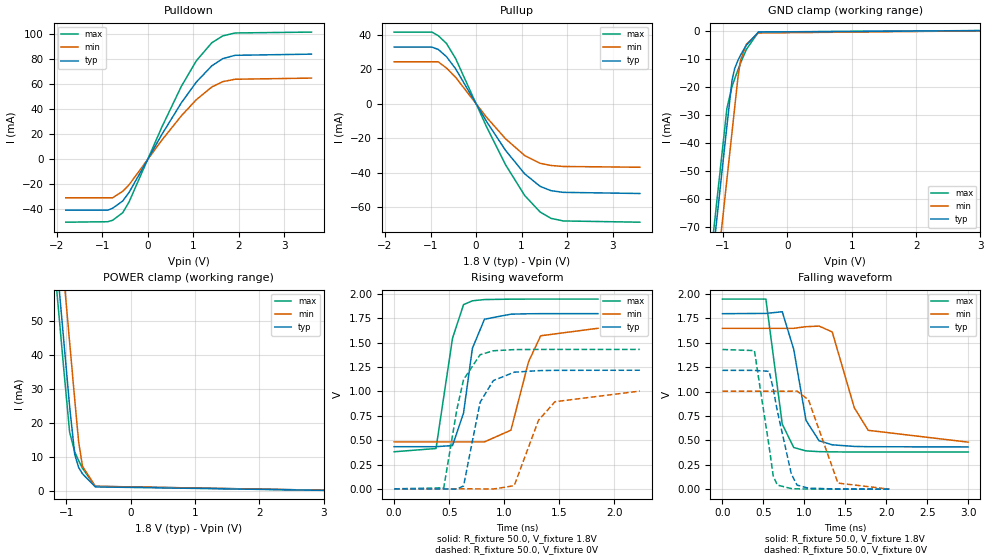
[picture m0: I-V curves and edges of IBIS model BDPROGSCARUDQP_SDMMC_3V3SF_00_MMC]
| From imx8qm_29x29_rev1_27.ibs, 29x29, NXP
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[Model] BDPROGSCARUDQP_SDMMC_3V3SF_00_MMC
Model_type I/O
Polarity   Non-Inverting
Enable   Active-Low
| CAP_THRESHOLD on pad IO is "CMOS" :
| Rising=10.0% of vdde1v8   Falling=90.0% of vdde1v8
| C_comp min and max val. don't necessarily correlate with the min and max pvt
| but are the smallest and greatest pad capacitance found.
| var   typ   min   max
C_comp   1.39830pF  1.34155pF  1.49815pF
Vinl = 577.5mV
Vinh = 1.2675V
Vmeas = 900.0mV   | Reference voltage for timing measurements
Cref  = 15.0pF   | Timing specification test load capacitance value
Rref  = 1.0MOhm   | Timing specification test load resistance value
Vref  = 1.8V   | Timing specification test load voltage
[Model Spec]
| TIME_THRESHOLD on pin ZI is "CORE" :
| Rising=50.0% of vdd   Falling=50.0% of vdd
Vinl 630.00000mV 577.50000mV 682.50000mV
Vinh 1.17000V 1.07250V 1.26750V
Vmeas 900.00000mV 825.00000mV 975.00000mV
Vref 1.80000V 1.65000V 1.95000V
| variable   typ   min   max
[Temperature Range] 25.0 125.0 -40.0
| variable   typ   min   max
[Voltage Range] 1.8V 1.65V 1.95V
| variable   typ   min   max
[POWER Clamp Reference] 1.8V 1.65V 1.95V
| variable   typ   min   max
[GND Clamp Reference] 0V 0V 0V
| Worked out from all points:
|   slope of the pulldown table from 0 to 0.27 V, typ, clamps not added: 15.6 ohm
|   slope of the pullup table from 0 to 0.27 V, typ, clamps not added: 22.9 ohm
|   GND clamp passes 1 mA (typ) near -0.48 V on its own axis
|   POWER clamp passes 1 mA (typ) near -0.53 V on its own axis
|   rising waveform, R_fixture 50.0, V_fixture 1.8V: 20-80 % time 107ps typ, 157ps min, 115ps max; typ from 0.433 V to 1.8 V
|   falling waveform, R_fixture 50.0, V_fixture 1.8V: 20-80 % time 167ps typ, 251ps min, 132ps max; typ from 1.8 V to 0.433 V
|   rising waveform, R_fixture 50.0, V_fixture 0V: 20-80 % time 139ps typ, 204ps min, 139ps max; typ from 0 V to 1.22 V
|   falling waveform, R_fixture 50.0, V_fixture 0V: 20-80 % time 187ps typ, 230ps min, 162ps max; typ from 1.22 V to 0 V
[POWER Clamp]
-1.8V     205.4mA    224.3mA    197mA
-1.18V    73.7mA     92.59mA    65.32mA
-1.15V    67.33mA    86.21mA    58.94mA
-1.12V    60.95mA    79.84mA    52.57mA
-1.06V    48.21mA    67.09mA    39.82mA
-1.04V    43.96mA    62.84mA    35.57mA
-950mV    24.83mA    43.72mA    17.27mA
-870mV    10.67mA    26.72mA    11.43mA
-810mV    6.903mA    14.47mA    8.897mA
-750mV    5.031mA    7.231mA    6.647mA
-550mV    1.187mA    1.353mA    1.363mA
3.6V      0A         0A         0A
[GND Clamp]
-1.8V     -216.7mA   -235.8mA   -210.3mA
-1.21V    -91.31mA   -110.4mA   -84.92mA
-1.12V    -72.19mA   -91.31mA   -65.8mA
-1.04V    -55.19mA   -74.31mA   -48.8mA
-940mV    -33.94mA   -53.06mA   -27.67mA
-860mV    -17.66mA   -36.06mA   -19.86mA
-820mV    -13.54mA   -27.56mA   -17.22mA
-770mV    -10.64mA   -16.96mA   -14.08mA
-730mV    -8.79mA    -10.76mA   -11.68mA
-640mV    -5.176mA   -4.882mA   -6.772mA
-450mV    -492.8uA   -817.4uA   -452.4uA
3.6V      109.1uA    87.23uA    140.4uA
| variable   typ   min   max
[Pullup Reference] 1.8V 1.65V 1.95V
| variable   typ   min   max
[Pulldown Reference] 0V 0V 0V
[Pullup]
-1.8V     33.01mA    24.43mA    41.69mA
-970mV    33.01mA    24.43mA    41.69mA
-830mV    31.61mA    24.43mA    39.61mA
-650mV    27.45mA    20.88mA    35.09mA
-450mV    20.46mA    15.52mA    26.43mA
230mV     -10.11mA   -7.67mA    -13.19mA
650mV     -26.95mA   -20.22mA   -35.31mA
1.07V     -40.53mA   -29.91mA   -53.1mA
1.41V     -47.79mA   -34.4mA    -62.68mA
1.65V     -50.28mA   -35.67mA   -66.34mA
1.92V     -51.25mA   -36.24mA   -67.83mA
3.6V      -51.91mA   -36.69mA   -68.55mA
[Pulldown]
-1.8V     -40.72mA   -30.81mA   -50.32mA
-880mV    -40.72mA   -30.81mA   -49.95mA
-770mV    -39.14mA   -30.78mA   -48.76mA
-550mV    -33.42mA   -25.62mA   -42.78mA
-410mV    -26.53mA   -20.44mA   -34.14mA
310mV     19.77mA    15.24mA    25.67mA
740mV     45.16mA    34.78mA    58.35mA
1.07V     61.77mA    47.68mA    78.8mA
1.41V     74.77mA    57.84mA    93.2mA
1.65V     80.47mA    62.07mA    98.65mA
1.92V     83.13mA    63.99mA    101mA
3.6V      84.07mA    64.91mA    101.7mA
[Ramp]
dV/dt_r 730.88031mV/139.16999ps 602.53977mV/204.04864ps 857.11439mV/139.26821ps
dV/dt_f 819.81631mV/166.75087ps 700.29607mV/250.61073ps 940.88152mV/131.63143ps
R_load = 50.0
| Removed startup time: 0s 0s 0s  .
| Removed end time: 1.83ns.
[Rising Waveform]
R_fixture   = 50.0
V_fixture   = 1.8V
V_fixture_min = 1.65V
V_fixture_max = 1.95V
0s        432.9mV    482.2mV    381mV
380ps     433mV      482.2mV    414.4mV
530ps     444.8mV    482.2mV    1.547V
630ps     778.7mV    482.2mV    1.892V
710ps     1.442V     482.2mV    1.931V
820ps     1.742V     482.4mV    1.944V
1.06ns    1.794V     602.6mV    1.948V
1.22ns    1.798V     1.305V     1.949V
1.33ns    1.799V     1.572V     1.949V
1.85ns    1.799V     1.649V     1.949V
| Removed startup time: 0s 0s 0s  .
| Removed end time: 2.98ns.
[Falling Waveform]
R_fixture   = 50.0
V_fixture   = 1.8V
V_fixture_min = 1.65V
V_fixture_max = 1.95V
0s        1.799V     1.649V     1.949V
530ps     1.802V     1.649V     1.949V
730ps     1.819V     1.649V     666.8mV
870ps     1.434V     1.649V     427.1mV
1.02ns    705.3mV    1.666V     392.5mV
1.18ns    496mV      1.672V     384.8mV
1.34ns    454.8mV    1.612V     382.3mV
1.61ns    438.5mV    834.1mV    381.1mV
1.78ns    435.4mV    603.3mV    380.9mV
3ns       432.9mV    482.2mV    381mV
| Removed startup time: 0s 0s 0s  .
| Removed end time: 2.21ns.
[Rising Waveform]
R_fixture   = 50.0
V_fixture   = 0V
V_fixture_min = 0V
V_fixture_max = 0V
0s        115uV      108.4uV    131uV
450ps     -393.5uV   158.4uV    10.76mV
570ps     -3.214mV   89.69uV    818.4mV
630ps     29.5mV     128uV      1.122V
780ps     888.6mV    -292.4uV   1.377V
900ps     1.112V     -2.045mV   1.418V
1.09ns    1.198V     32.56mV    1.43V
1.31ns    1.214V     703.8mV    1.432V
1.46ns    1.217V     895mV      1.432V
2.23ns    1.218V     1.004V     1.432V
| Removed startup time: 0s 0s 0s  .
| Removed end time: 2.02ns.
[Falling Waveform]
R_fixture   = 50.0
V_fixture   = 0V
V_fixture_min = 0V
V_fixture_max = 0V
0s        1.218V     1.004V     1.432V
390ps     1.218V     1.004V     1.421V
570ps     1.208V     1.004V     433.5mV
620ps     1.028V     1.004V     134.3mV
670ps     800.4mV    1.004V     42.3mV
840ps     158.6mV    1.004V     5.985mV
910ps     42.06mV    1.006V     3.411mV
1.05ns    10.31mV    916.5mV    1.437mV
1.41ns    1.368mV    62.51mV    400.4uV
2.04ns    122.1uV    119.5uV    135.6uV
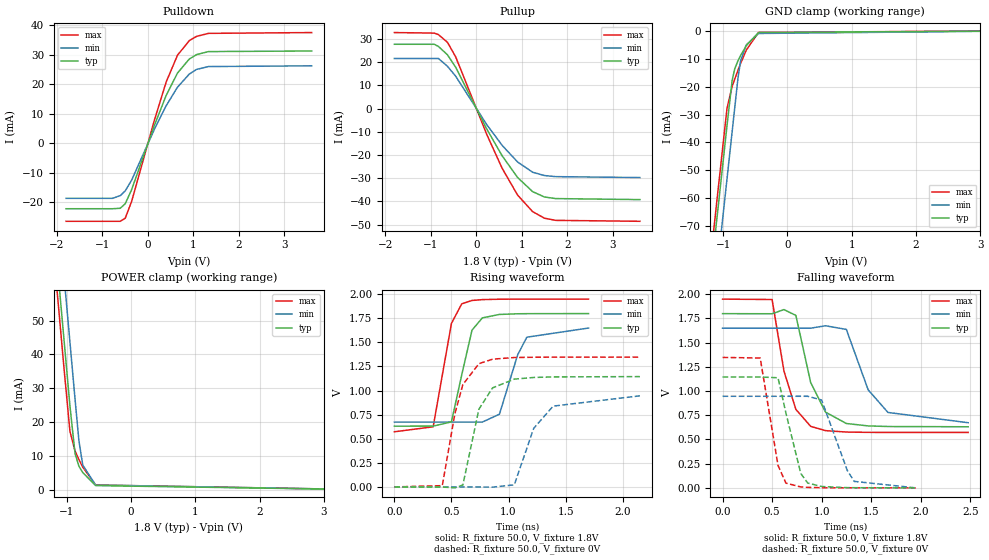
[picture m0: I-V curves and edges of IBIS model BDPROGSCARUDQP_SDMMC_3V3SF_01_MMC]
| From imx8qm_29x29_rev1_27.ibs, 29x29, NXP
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[Model] BDPROGSCARUDQP_SDMMC_3V3SF_01_MMC
Model_type I/O
Polarity   Non-Inverting
Enable   Active-Low
| CAP_THRESHOLD on pad IO is "CMOS" :
| Rising=10.0% of vdde1v8   Falling=90.0% of vdde1v8
| C_comp min and max val. don't necessarily correlate with the min and max pvt
| but are the smallest and greatest pad capacitance found.
| var   typ   min   max
C_comp   1.39700pF  1.34055pF  1.49705pF
Vinl = 577.5mV
Vinh = 1.2675V
Vmeas = 900.0mV   | Reference voltage for timing measurements
Cref  = 15.0pF   | Timing specification test load capacitance value
Rref  = 1.0MOhm   | Timing specification test load resistance value
Vref  = 1.8V   | Timing specification test load voltage
[Model Spec]
| TIME_THRESHOLD on pin ZI is "CORE" :
| Rising=50.0% of vdd   Falling=50.0% of vdd
Vinl 630.00000mV 577.50000mV 682.50000mV
Vinh 1.17000V 1.07250V 1.26750V
Vmeas 900.00000mV 825.00000mV 975.00000mV
Vref 1.80000V 1.65000V 1.95000V
| variable   typ   min   max
[Temperature Range] 25.0 125.0 -40.0
| variable   typ   min   max
[Voltage Range] 1.8V 1.65V 1.95V
| variable   typ   min   max
[POWER Clamp Reference] 1.8V 1.65V 1.95V
| variable   typ   min   max
[GND Clamp Reference] 0V 0V 0V
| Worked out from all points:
|   slope of the pulldown table from 0 to 0.27 V, typ, clamps not added: 23.9 ohm
|   slope of the pullup table from 0 to 0.27 V, typ, clamps not added: 26.6 ohm
|   GND clamp passes 1 mA (typ) near -0.48 V on its own axis
|   POWER clamp passes 1 mA (typ) near -0.53 V on its own axis
|   rising waveform, R_fixture 50.0, V_fixture 1.8V: 20-80 % time 120ps typ, 148ps min, 122ps max; typ from 0.631 V to 1.8 V
|   falling waveform, R_fixture 50.0, V_fixture 1.8V: 20-80 % time 198ps typ, 248ps min, 179ps max; typ from 1.8 V to 0.631 V
|   rising waveform, R_fixture 50.0, V_fixture 0V: 20-80 % time 143ps typ, 196ps min, 141ps max; typ from 0 V to 1.15 V
|   falling waveform, R_fixture 50.0, V_fixture 0V: 20-80 % time 159ps typ, 199ps min, 138ps max; typ from 1.15 V to 0 V
[POWER Clamp]
-1.8V     205.4mA    224.3mA    197mA
-1.18V    73.7mA     92.59mA    65.32mA
-1.15V    67.33mA    86.21mA    58.94mA
-1.12V    60.95mA    79.84mA    52.57mA
-1.06V    48.21mA    67.09mA    39.82mA
-1.04V    43.96mA    62.84mA    35.57mA
-950mV    24.83mA    43.72mA    17.27mA
-870mV    10.67mA    26.72mA    11.43mA
-810mV    6.903mA    14.47mA    8.897mA
-750mV    5.031mA    7.231mA    6.647mA
-550mV    1.187mA    1.353mA    1.363mA
3.6V      0A         0A         0A
[GND Clamp]
-1.8V     -216.7mA   -235.8mA   -210.3mA
-1.21V    -91.31mA   -110.4mA   -84.92mA
-1.12V    -72.19mA   -91.31mA   -65.8mA
-1.04V    -55.19mA   -74.31mA   -48.8mA
-940mV    -33.94mA   -53.06mA   -27.67mA
-860mV    -17.66mA   -36.06mA   -19.86mA
-820mV    -13.54mA   -27.56mA   -17.22mA
-770mV    -10.64mA   -16.96mA   -14.08mA
-730mV    -8.79mA    -10.76mA   -11.68mA
-640mV    -5.176mA   -4.882mA   -6.772mA
-450mV    -492.8uA   -817.4uA   -452.4uA
3.6V      109.1uA    87.23uA    140.4uA
| variable   typ   min   max
[Pullup Reference] 1.8V 1.65V 1.95V
| variable   typ   min   max
[Pulldown Reference] 0V 0V 0V
[Pullup]
-1.8V     27.77mA    21.63mA    32.82mA
-920mV    27.77mA    21.63mA    32.59mA
-830mV    26.81mA    21.63mA    31.93mA
-630mV    23.2mA     18.24mA    28.58mA
-450mV    17.82mA    13.95mA    22.27mA
230mV     -8.713mA   -6.829mA   -11.03mA
570mV     -20.33mA   -15.84mA   -25.72mA
910mV     -29.71mA   -23.01mA   -37.29mA
1.24V     -35.8mA    -27.44mA   -44.43mA
1.5V      -38.12mA   -28.87mA   -47.27mA
1.75V     -38.81mA   -29.34mA   -48.21mA
3.6V      -39.25mA   -29.74mA   -48.61mA
[Pulldown]
-1.8V     -22.2mA    -18.67mA   -26.46mA
-780mV    -22.2mA    -18.67mA   -26.46mA
-610mV    -22.04mA   -17.76mA   -26.46mA
-500mV    -20.5mA    -16.16mA   -25.41mA
-360mV    -15.76mA   -12.53mA   -19.76mA
140mV     6.017mA    4.706mA    7.753mA
400mV     16.23mA    12.74mA    20.79mA
650mV     23.85mA    19.04mA    29.89mA
910mV     28.6mA     23.5mA     34.86mA
1.07V     30.1mA     25.07mA    36.27mA
1.33V     31.11mA    26.03mA    37.29mA
3.6V      31.31mA    26.28mA    37.56mA
[Ramp]
dV/dt_r 686.83044mV/142.6003ps 567.34935mV/196.26704ps 808.86927mV/140.91314ps
dV/dt_f 700.93528mV/197.57155ps 585.82866mV/248.40399ps 825.4008mV/179.20548ps
R_load = 50.0
| Removed startup time: 0s 0s 0s  .
| Removed end time: 1.68ns.
[Rising Waveform]
R_fixture   = 50.0
V_fixture   = 1.8V
V_fixture_min = 1.65V
V_fixture_max = 1.95V
0s        630.9mV    672.9mV    572.5mV
340ps     631.2mV    672.9mV    624.3mV
500ps     675.4mV    673mV      1.697V
590ps     1.163V     673mV      1.9V
680ps     1.627V     673mV      1.935V
770ps     1.754V     672.9mV    1.944V
920ps     1.79V      754.9mV    1.948V
1.08ns    1.797V     1.372V     1.949V
1.16ns    1.798V     1.554V     1.949V
1.7ns     1.799V     1.649V     1.949V
| Removed startup time: 0s 0s 0s  .
| Removed end time: 2.46ns.
[Falling Waveform]
R_fixture   = 50.0
V_fixture   = 1.8V
V_fixture_min = 1.65V
V_fixture_max = 1.95V
0s        1.799V     1.649V     1.949V
500ps     1.798V     1.649V     1.945V
620ps     1.841V     1.649V     1.206V
740ps     1.781V     1.649V     810.9mV
890ps     1.087V     1.649V     634.8mV
1.04ns    781.9mV    1.674V     590.9mV
1.25ns    664.7mV    1.636V     576.5mV
1.47ns    639.8mV    1.013V     573.2mV
1.67ns    633.7mV    778.9mV    572.5mV
2.48ns    630.9mV    672.9mV    572.5mV
| Removed startup time: 0s 0s 0s  .
| Removed end time: 2.13ns.
[Rising Waveform]
R_fixture   = 50.0
V_fixture   = 0V
V_fixture_min = 0V
V_fixture_max = 0V
0s        153.2uV    140.2uV    179uV
420ps     -546.1uV   125.4uV    13.56mV
530ps     -9.393mV   171.9uV    759.2mV
600ps     20.36mV    100.8uV    1.063V
740ps     806.1mV    73.39uV    1.279V
860ps     1.028V     -1.713mV   1.326V
1.05ns    1.119V     21.74mV    1.343V
1.22ns    1.136V     608.1mV    1.346V
1.39ns    1.142V     838.7mV    1.347V
2.15ns    1.145V     945.7mV    1.347V
| Removed startup time: 0s 0s 0s  .
| Removed end time: 1.93ns.
[Falling Waveform]
R_fixture   = 50.0
V_fixture   = 0V
V_fixture_min = 0V
V_fixture_max = 0V
0s        1.145V     945.7mV    1.347V
380ps     1.145V     945.7mV    1.341V
560ps     1.137V     945.7mV    231.8mV
640ps     771.8mV    945.8mV    49.11mV
790ps     148mV      945.8mV    9.496mV
860ps     49.92mV    945.8mV    5.047mV
1ns       14.01mV    907.3mV    1.817mV
1.26ns    2.554mV    178.5mV    582uV
1.33ns    1.774mV    66.88mV    498.1uV
1.95ns    162.5uV    154.4uV    185.3uV
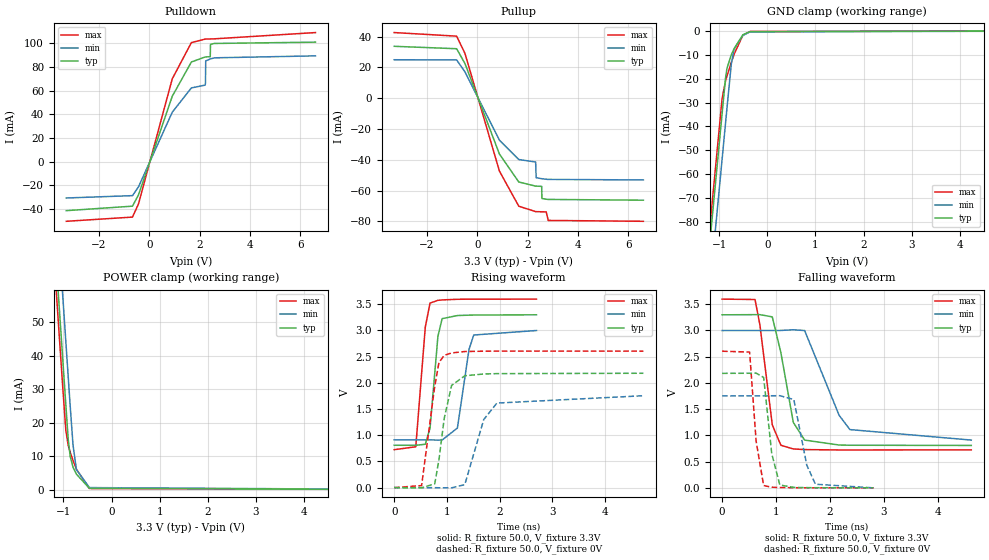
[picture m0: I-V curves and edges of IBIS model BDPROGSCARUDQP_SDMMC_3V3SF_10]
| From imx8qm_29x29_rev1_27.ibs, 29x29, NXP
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[Model] BDPROGSCARUDQP_SDMMC_3V3SF_10
Model_type I/O
Polarity   Non-Inverting
Enable   Active-Low
| CAP_THRESHOLD on pad IO is "CMOS" :
| Rising=10.0% of vdde3v3   Falling=90.0% of vdde3v3
| C_comp min and max val. don't necessarily correlate with the min and max pvt
| but are the smallest and greatest pad capacitance found.
| var   typ   min   max
C_comp   1.31090pF  1.26795pF  1.34510pF
Vinl = 750.0mV
Vinh = 2.25V
Vmeas = 1.65V   | Reference voltage for timing measurements
Cref  = 15.0pF   | Timing specification test load capacitance value
Rref  = 1.0MOhm   | Timing specification test load resistance value
Vref  = 3.3V   | Timing specification test load voltage
[Model Spec]
| TIME_THRESHOLD on pin ZI is "CORE" :
| Rising=50.0% of vdd   Falling=50.0% of vdd
Vinl 825.00000mV 750.00000mV 900.00000mV
Vinh 2.06250V 1.87500V 2.25000V
Vmeas 1.65000V 1.50000V 1.80000V
Vref 3.30000V 3.00000V 3.60000V
| variable   typ   min   max
[Temperature Range] 25.0 125.0 -40.0
| variable   typ   min   max
[Voltage Range] 3.3V 3.0V 3.6V
| variable   typ   min   max
[POWER Clamp Reference] 3.3V 3.0V 3.6V
| variable   typ   min   max
[GND Clamp Reference] 0V 0V 0V
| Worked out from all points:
|   slope of the pulldown table from 0 to 0.495 V, typ, clamps not added: 15.7 ohm
|   slope of the pullup table from 0 to 0.495 V, typ, clamps not added: 22.8 ohm
|   GND clamp passes 1 mA (typ) near -0.46 V on its own axis
|   POWER clamp passes 1 mA (typ) near -0.53 V on its own axis
|   rising waveform, R_fixture 50.0, V_fixture 3.3V: 20-80 % time 123ps typ, 168ps min, 122ps max; typ from 0.809 V to 3.3 V
|   falling waveform, R_fixture 50.0, V_fixture 3.3V: 20-80 % time 256ps typ, 424ps min, 203ps max; typ from 3.3 V to 0.809 V
|   rising waveform, R_fixture 50.0, V_fixture 0V: 20-80 % time 188ps typ, 300ps min, 183ps max; typ from 0 V to 2.18 V
|   falling waveform, R_fixture 50.0, V_fixture 0V: 20-80 % time 149ps typ, 203ps min, 122ps max; typ from 2.18 V to 0 V
[POWER Clamp]
-3.3V     524.6mA    543.5mA    516.1mA
-1.18V    74.13mA    93.03mA    65.73mA
-1.13V    63.5mA     82.4mA     55.11mA
-1.08V    52.88mA    71.78mA    44.49mA
-1.02V    40.13mA    59.03mA    31.74mA
-950mV    25.26mA    44.16mA    17.6mA
-900mV    14.93mA    33.53mA    13.17mA
-860mV    9.966mA    25.03mA    11.19mA
-800mV    6.661mA    13.2mA     8.673mA
-730mV    4.611mA    5.971mA    6.078mA
-460mV    377.7uA    599uA      338.7uA
6.6V      0A         0A         0A
[GND Clamp]
-3.3V     -535.9mA   -555mA     -529.5mA
-1.29V    -108.7mA   -127.9mA   -102.4mA
-1.13V    -74.74mA   -93.9mA    -68.39mA
-980mV    -42.86mA   -62.03mA   -36.51mA
-940mV    -34.36mA   -53.53mA   -28.08mA
-870mV    -19.62mA   -38.65mA   -20.84mA
-840mV    -15.5mA    -32.28mA   -18.78mA
-750mV    -9.826mA   -13.78mA   -13.06mA
-690mV    -7.205mA   -7.402mA   -9.546mA
-510mV    -1.433mA   -1.704mA   -1.633mA
-360mV    -54.77uA   -167.6uA   -42.24uA
6.6V      207.7uA    165.9uA    268.6uA
| variable   typ   min   max
[Pullup Reference] 3.3V 3.0V 3.6V
| variable   typ   min   max
[Pulldown Reference] 0V 0V 0V
[Pullup]
-3.3V     33.71mA    24.97mA    42.63mA
-820mV    32.13mA    24.86mA    40.3mA
-490mV    22.58mA    17.13mA    29.14mA
880mV     -36.28mA   -27.26mA   -47.35mA
1.65V     -54.46mA   -39.85mA   -70.18mA
2.32V     -57.13mA   -41.48mA   -73.7mA
2.34V     -57.15mA   -51.66mA   -73.71mA
2.56V     -57.29mA   -52.32mA   -73.82mA
2.57V     -65.17mA   -52.35mA   -73.83mA
2.74V     -65.64mA   -52.67mA   -73.88mA
2.82V     -65.78mA   -52.78mA   -79.42mA
6.6V      -66.28mA   -53.12mA   -79.99mA
[Pulldown]
-3.3V     -41.49mA   -30.78mA   -50.48mA
-670mV    -37.68mA   -28.78mA   -46.92mA
-430mV    -28.08mA   -21.29mA   -35.73mA
910mV     55.22mA    41.72mA    69.95mA
1.67V     84.2mA     62.3mA     100.6mA
2.22V     88.47mA    64.68mA    103.6mA
2.23V     88.48mA    66.76mA    103.6mA
2.24V     88.5mA     85.12mA    103.7mA
2.42V     88.69mA    86.76mA    103.7mA
2.43V     99.17mA    86.84mA    103.7mA
2.58V     99.89mA    87.74mA    103.8mA
6.6V      101mA      89.4mA     109.1mA
[Ramp]
dV/dt_r 1.3099V/188.25171ps 1.05212V/300.21154ps 1.5632V/183.30229ps
dV/dt_f 1.49389V/256.0841ps 1.25263V/423.56639ps 1.72452V/202.50135ps
R_load = 50.0
| Removed startup time: 0s 0s 0s  .
| Removed end time: 2.68ns.
[Rising Waveform]
R_fixture   = 50.0
V_fixture   = 3.3V
V_fixture_min = 3.0V
V_fixture_max = 3.6V
0s        808.7mV    911mV      724mV
410ps     808mV      911mV      780mV
590ps     827.9mV    911.1mV    3.062V
680ps     1.133V     911.1mV    3.522V
830ps     2.89V      907.3mV    3.575V
910ps     3.225V     908.9mV    3.583V
1.2ns     3.285V     1.138V     3.595V
1.42ns    3.292V     2.637V     3.597V
1.51ns    3.294V     2.913V     3.597V
2.7ns     3.299V     2.999V     3.598V
| Removed startup time: 0s 0s 0s  .
| Removed end time: 4.6ns.
[Falling Waveform]
R_fixture   = 50.0
V_fixture   = 3.3V
V_fixture_min = 3.0V
V_fixture_max = 3.6V
0s        3.299V     2.999V     3.598V
610ps     3.302V     2.999V     3.591V
700ps     3.302V     2.999V     3.112V
930ps     3.26V      2.999V     1.202V
1.09ns    2.576V     3.001V     811.7mV
1.32ns    1.248V     3.014V     742mV
1.53ns    910.9mV    2.999V     729.9mV
2.17ns    816.6mV    1.382V     722.4mV
2.37ns    812.6mV    1.111V     722.4mV
4.62ns    808.7mV    911mV      724mV
| Removed startup time: 0s 0s 0s  .
| Removed end time: 4.71ns.
[Rising Waveform]
R_fixture   = 50.0
V_fixture   = 0V
V_fixture_min = 0V
V_fixture_max = 0V
0s        118.5uV    111.8uV    137.3uV
520ps     -4.522mV   201.5uV    39.01mV
770ps     73.97mV    -881.9uV   1.938V
850ps     536.9mV    -2.746mV   2.39V
950ps     1.324V     -2.822mV   2.524V
1.09ns    1.952V     -4.309mV   2.571V
1.34ns    2.135V     56.63mV    2.598V
1.7ns     2.169V     1.3V       2.604V
1.95ns    2.176V     1.614V     2.606V
4.73ns    2.183V     1.754V     2.605V
| Removed startup time: 0s 0s 0s  .
| Removed end time: 2.79ns.
[Falling Waveform]
R_fixture   = 50.0
V_fixture   = 0V
V_fixture_min = 0V
V_fixture_max = 0V
0s        2.183V     1.754V     2.605V
510ps     2.185V     1.754V     2.589V
630ps     2.188V     1.754V     894mV
770ps     2.105V     1.754V     44.11mV
920ps     653.7mV    1.756V     12.7mV
1.07ns    54.57mV    1.757V     6.523mV
1.33ns    8.419mV    1.684V     2.95mV
1.57ns    4.101mV    432.5mV    1.099mV
1.73ns    3.022mV    69.24mV    556.9uV
2.81ns    118.5uV    111.4uV    137.4uV
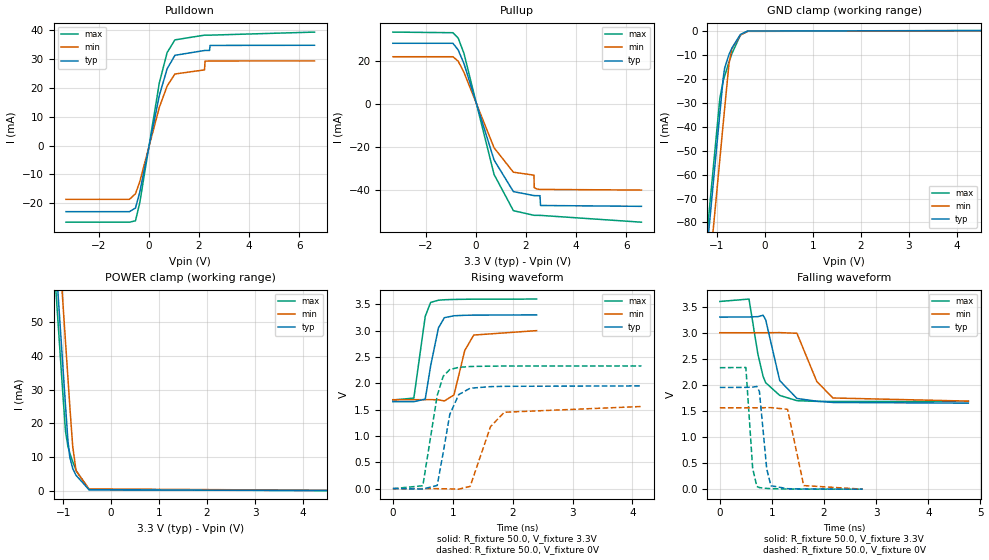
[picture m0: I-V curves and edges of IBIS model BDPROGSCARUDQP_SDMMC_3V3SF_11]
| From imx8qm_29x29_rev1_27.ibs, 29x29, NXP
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[Model] BDPROGSCARUDQP_SDMMC_3V3SF_11
Model_type I/O
Polarity   Non-Inverting
Enable   Active-Low
| CAP_THRESHOLD on pad IO is "CMOS" :
| Rising=10.0% of vdde3v3   Falling=90.0% of vdde3v3
| C_comp min and max val. don't necessarily correlate with the min and max pvt
| but are the smallest and greatest pad capacitance found.
| var   typ   min   max
C_comp   1.30990pF  1.26715pF  1.34440pF
Vinl = 750.0mV
Vinh = 2.25V
Vmeas = 1.65V   | Reference voltage for timing measurements
Cref  = 15.0pF   | Timing specification test load capacitance value
Rref  = 1.0MOhm   | Timing specification test load resistance value
Vref  = 3.3V   | Timing specification test load voltage
[Model Spec]
| TIME_THRESHOLD on pin ZI is "CORE" :
| Rising=50.0% of vdd   Falling=50.0% of vdd
Vinl 825.00000mV 750.00000mV 900.00000mV
Vinh 2.06250V 1.87500V 2.25000V
Vmeas 1.65000V 1.50000V 1.80000V
Vref 3.30000V 3.00000V 3.60000V
| variable   typ   min   max
[Temperature Range] 25.0 125.0 -40.0
| variable   typ   min   max
[Voltage Range] 3.3V 3.0V 3.6V
| variable   typ   min   max
[POWER Clamp Reference] 3.3V 3.0V 3.6V
| variable   typ   min   max
[GND Clamp Reference] 0V 0V 0V
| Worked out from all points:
|   slope of the pulldown table from 0 to 0.495 V, typ, clamps not added: 24.8 ohm
|   slope of the pullup table from 0 to 0.495 V, typ, clamps not added: 26.9 ohm
|   GND clamp passes 1 mA (typ) near -0.46 V on its own axis
|   POWER clamp passes 1 mA (typ) near -0.53 V on its own axis
|   rising waveform, R_fixture 50.0, V_fixture 3.3V: 20-80 % time 147ps typ, 176ps min, 134ps max; typ from 1.65 V to 3.3 V
|   falling waveform, R_fixture 50.0, V_fixture 3.3V: 20-80 % time 257ps typ, 345ps min, 235ps max; typ from 3.3 V to 1.65 V
|   rising waveform, R_fixture 50.0, V_fixture 0V: 20-80 % time 190ps typ, 274ps min, 193ps max; typ from 0 V to 1.95 V
|   falling waveform, R_fixture 50.0, V_fixture 0V: 20-80 % time 111ps typ, 156ps min, 89.7ps max; typ from 1.95 V to 0 V
[POWER Clamp]
-3.3V     524.6mA    543.5mA    516.1mA
-1.18V    74.13mA    93.03mA    65.73mA
-1.13V    63.5mA     82.4mA     55.11mA
-1.08V    52.88mA    71.78mA    44.49mA
-1.02V    40.13mA    59.03mA    31.74mA
-950mV    25.26mA    44.16mA    17.6mA
-900mV    14.93mA    33.53mA    13.17mA
-860mV    9.966mA    25.03mA    11.19mA
-800mV    6.661mA    13.2mA     8.673mA
-730mV    4.611mA    5.971mA    6.078mA
-460mV    377.7uA    599uA      338.7uA
6.6V      0A         0A         0A
[GND Clamp]
-3.3V     -535.9mA   -555mA     -529.5mA
-1.29V    -108.7mA   -127.9mA   -102.4mA
-1.13V    -74.74mA   -93.9mA    -68.39mA
-980mV    -42.86mA   -62.03mA   -36.51mA
-940mV    -34.36mA   -53.53mA   -28.08mA
-870mV    -19.62mA   -38.65mA   -20.84mA
-840mV    -15.5mA    -32.28mA   -18.78mA
-750mV    -9.826mA   -13.78mA   -13.06mA
-690mV    -7.205mA   -7.402mA   -9.546mA
-510mV    -1.433mA   -1.704mA   -1.633mA
-360mV    -54.77uA   -167.6uA   -42.24uA
6.6V      207.7uA    165.9uA    268.6uA
| variable   typ   min   max
[Pullup Reference] 3.3V 3.0V 3.6V
| variable   typ   min   max
[Pulldown Reference] 0V 0V 0V
[Pullup]
-3.3V     28.29mA    22.05mA    33.49mA
-910mV    28.29mA    22.05mA    33.2mA
-700mV    25.21mA    19.99mA    30.72mA
-470mV    18.91mA    14.81mA    23.6mA
730mV     -25.92mA   -20.25mA   -32.62mA
1.5V      -40.58mA   -31.58mA   -49.44mA
2.32V     -42.44mA   -32.95mA   -51.59mA
2.33V     -42.44mA   -38.74mA   -51.59mA
2.43V     -42.47mA   -39.38mA   -51.61mA
2.56V     -42.5mA    -39.55mA   -51.63mA
2.58V     -47.03mA   -39.57mA   -51.63mA
6.6V      -47.43mA   -39.87mA   -54.79mA
[Pulldown]
-3.3V     -22.92mA   -18.65mA   -26.58mA
-770mV    -22.92mA   -18.65mA   -26.58mA
-530mV    -21.66mA   -16.7mA    -26.09mA
-360mV    -16.13mA   -12.53mA   -19.82mA
420mV     17.42mA    13.3mA     21.81mA
730mV     26.64mA    20.66mA    32.27mA
1.04V     31.32mA    24.84mA    36.68mA
2.22V     33mA       26.27mA    38.32mA
2.24V     33.01mA    29.3mA     38.32mA
2.42V     33.01mA    29.35mA    38.32mA
2.44V     34.75mA    29.36mA    38.32mA
6.6V      34.81mA    29.38mA    39.38mA
[Ramp]
dV/dt_r 1.16975V/189.50514ps 935.39258mV/274.0416ps 1.39725V/192.9901ps
dV/dt_f 989.53002mV/257.16879ps 786.49611mV/345.14286ps 1.14965V/234.50303ps
R_load = 50.0
| Removed startup time: 0s 0s 0s  .
| Removed end time: 2.38ns.
[Rising Waveform]
R_fixture   = 50.0
V_fixture   = 3.3V
V_fixture_min = 3.0V
V_fixture_max = 3.6V
0s        1.649V     1.688V     1.682V
350ps     1.65V      1.688V     1.719V
540ps     1.699V     1.688V     3.27V
630ps     2.327V     1.689V     3.534V
760ps     3.05V      1.686V     3.576V
860ps     3.245V     1.665V     3.585V
1.02ns    3.281V     1.777V     3.591V
1.2ns     3.29V      2.622V     3.594V
1.35ns    3.293V     2.915V     3.596V
2.4ns     3.298V     2.999V     3.598V
| Removed startup time: 0s 0s 0s  .
| Removed end time: 4.75ns.
[Falling Waveform]
R_fixture   = 50.0
V_fixture   = 3.3V
V_fixture_min = 3.0V
V_fixture_max = 3.6V
0s        3.298V     2.999V     3.598V
560ps     3.301V     2.998V     3.644V
730ps     3.307V     2.999V     2.59V
830ps     3.334V     2.999V     2.164V
880ps     3.246V     2.999V     2.041V
1.15ns    2.081V     3.001V     1.797V
1.48ns    1.739V     2.988V     1.696V
1.86ns    1.686V     2.066V     1.683V
2.17ns    1.662V     1.748V     1.682V
4.77ns    1.649V     1.688V     1.682V
| Removed startup time: 0s 0s 0s  .
| Removed end time: 4.13ns.
[Rising Waveform]
R_fixture   = 50.0
V_fixture   = 0V
V_fixture_min = 0V
V_fixture_max = 0V
0s        157uV      144.5uV    187.5uV
500ps     -6.421mV   259.1uV    54.8mV
740ps     60.63mV    -240.4uV   1.768V
840ps     685.8mV    -3.195mV   2.133V
950ps     1.409V     -4.009mV   2.26V
1.1ns     1.785V     -9.984mV   2.302V
1.29ns    1.906V     42.06mV    2.318V
1.63ns    1.936V     1.177V     2.325V
1.86ns    1.942V     1.45V      2.327V
4.15ns    1.95V      1.559V     2.329V
| Removed startup time: 0s 0s 0s  .
| Removed end time: 2.72ns.
[Falling Waveform]
R_fixture   = 50.0
V_fixture   = 0V
V_fixture_min = 0V
V_fixture_max = 0V
0s        1.95V      1.559V     2.329V
500ps     1.951V     1.559V     2.332V
630ps     1.957V     1.56V      402mV
710ps     1.969V     1.56V      52.34mV
760ps     1.87V      1.56V      30.45mV
900ps     390.5mV    1.562V     14.45mV
980ps     66.13mV    1.563V     10.41mV
1.3ns     8.98mV     1.531V     2.718mV
1.61ns    3.86mV     68.96mV    702.8uV
2.74ns    157uV      144uV      187.5uV
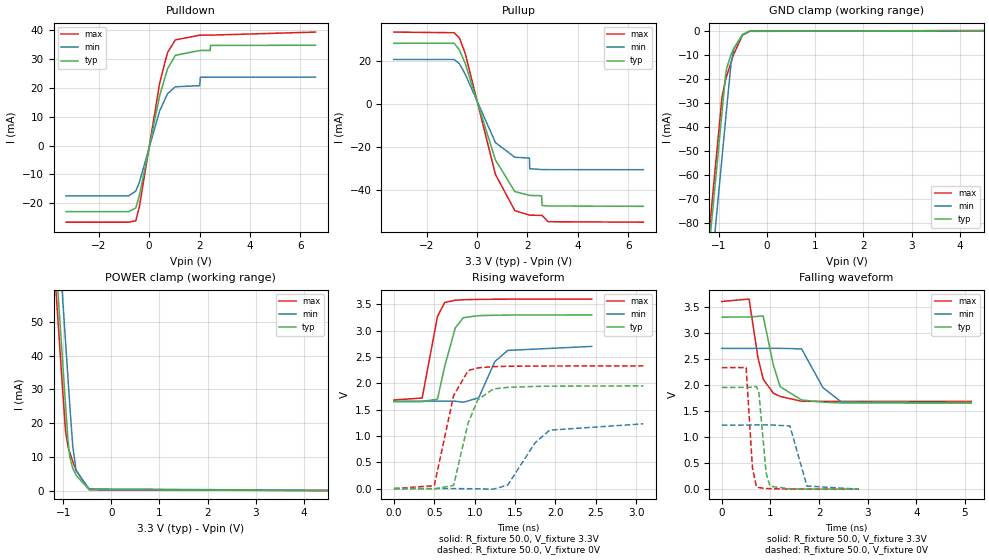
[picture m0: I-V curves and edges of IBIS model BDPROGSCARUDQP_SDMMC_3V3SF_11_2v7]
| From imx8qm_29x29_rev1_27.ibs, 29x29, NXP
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[Model] BDPROGSCARUDQP_SDMMC_3V3SF_11_2v7
Model_type I/O
Polarity   Non-Inverting
Enable   Active-Low
| CAP_THRESHOLD on pad IO is "CMOS" :
| Rising=10.0% of vdde3v3   Falling=90.0% of vdde3v3
| C_comp min and max val. don't necessarily correlate with the min and max pvt
| but are the smallest and greatest pad capacitance found.
| var   typ   min   max
C_comp   1.26715pF  1.18750pF  1.30990pF
Vinl = 675.0mV
Vinh = 2.25V
Vmeas = 1.65V   | Reference voltage for timing measurements
Cref  = 15.0pF   | Timing specification test load capacitance value
Rref  = 1.0MOhm   | Timing specification test load resistance value
Vref  = 3.3V   | Timing specification test load voltage
[Model Spec]
| TIME_THRESHOLD on pin ZI is "CORE" :
| Rising=50.0% of vdd   Falling=50.0% of vdd
Vinl 825.00000mV 675.00000mV 900.00000mV
Vinh 2.06250V 1.68750V 2.25000V
Vmeas 1.65000V 1.35000V 1.80000V
Vref 3.30000V 2.70000V 3.60000V
| variable   typ   min   max
[Temperature Range] 25.0 125.0 -40.0
| variable   typ   min   max
[Voltage Range] 3.3V 2.7V 3.6V
| variable   typ   min   max
[POWER Clamp Reference] 3.3V 2.7V 3.6V
| variable   typ   min   max
[GND Clamp Reference] 0V 0V 0V
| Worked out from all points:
|   slope of the pulldown table from 0 to 0.495 V, typ, clamps not added: 24.8 ohm
|   slope of the pullup table from 0 to 0.495 V, typ, clamps not added: 26.9 ohm
|   GND clamp passes 1 mA (typ) near -0.46 V on its own axis
|   POWER clamp passes 1 mA (typ) near -0.53 V on its own axis
|   rising waveform, R_fixture 50.0, V_fixture 3.3V: 20-80 % time 147ps typ, 188ps min, 134ps max; typ from 1.65 V to 3.3 V
|   falling waveform, R_fixture 50.0, V_fixture 3.3V: 20-80 % time 257ps typ, 390ps min, 235ps max; typ from 3.3 V to 1.65 V
|   rising waveform, R_fixture 50.0, V_fixture 0V: 20-80 % time 190ps typ, 313ps min, 193ps max; typ from 0 V to 1.95 V
|   falling waveform, R_fixture 50.0, V_fixture 0V: 20-80 % time 111ps typ, 180ps min, 89.7ps max; typ from 1.95 V to 0 V
[POWER Clamp]
-3.3V     524.6mA    543.4mA    516.1mA
-1.18V    74.13mA    92.92mA    65.73mA
-1.13V    63.5mA     82.3mA     55.11mA
-1.08V    52.88mA    71.67mA    44.49mA
-1.02V    40.13mA    58.93mA    31.74mA
-950mV    25.26mA    44.05mA    17.6mA
-900mV    14.93mA    33.43mA    13.17mA
-860mV    9.966mA    24.93mA    11.19mA
-800mV    6.661mA    13.12mA    8.673mA
-730mV    4.611mA    5.939mA    6.078mA
-460mV    377.7uA    598.1uA    338.7uA
6.6V      0A         0A         0A
[GND Clamp]
-3.3V     -535.9mA   -554.9mA   -529.5mA
-1.29V    -108.7mA   -127.8mA   -102.4mA
-1.13V    -74.74mA   -93.8mA    -68.39mA
-980mV    -42.86mA   -61.92mA   -36.51mA
-940mV    -34.36mA   -53.42mA   -28.08mA
-870mV    -19.62mA   -38.55mA   -20.84mA
-840mV    -15.5mA    -32.17mA   -18.78mA
-750mV    -9.826mA   -13.7mA    -13.06mA
-690mV    -7.205mA   -7.371mA   -9.546mA
-510mV    -1.433mA   -1.699mA   -1.633mA
-360mV    -54.77uA   -166.3uA   -42.24uA
6.6V      207.7uA    166.8uA    268.6uA
| variable   typ   min   max
[Pullup Reference] 3.3V 2.7V 3.6V
| variable   typ   min   max
[Pulldown Reference] 0V 0V 0V
[Pullup]
-3.3V     28.29mA    20.75mA    33.49mA
-910mV    28.29mA    20.75mA    33.2mA
-700mV    25.21mA    18.82mA    30.72mA
-470mV    18.91mA    13.94mA    23.6mA
730mV     -25.92mA   -17.83mA   -32.62mA
1.5V      -40.58mA   -24.64mA   -49.44mA
2.08V     -42.34mA   -25.01mA   -51.51mA
2.09V     -42.35mA   -29.96mA   -51.52mA
2.56V     -42.5mA    -30.35mA   -51.63mA
2.58V     -47.03mA   -30.36mA   -51.63mA
2.82V     -47.26mA   -30.39mA   -54.57mA
6.6V      -47.43mA   -30.41mA   -54.79mA
[Pulldown]
-3.3V     -22.92mA   -17.45mA   -26.58mA
-820mV    -22.92mA   -17.45mA   -26.58mA
-530mV    -21.66mA   -15.79mA   -26.09mA
-390mV    -17.39mA   -12.76mA   -21.33mA
420mV     17.42mA    12.1mA     21.81mA
730mV     26.64mA    18mA       32.27mA
1.04V     31.32mA    20.4mA     36.68mA
2.01V     32.99mA    20.79mA    38.31mA
2.03V     33mA       23.7mA     38.31mA
2.42V     33.01mA    23.74mA    38.32mA
2.44V     34.75mA    23.74mA    38.32mA
6.6V      34.81mA    23.75mA    39.38mA
[Ramp]
dV/dt_r 1.16975V/189.50514ps 737.10548mV/313.10036ps 1.39725V/192.9901ps
dV/dt_f 989.53002mV/257.16879ps 623.19328mV/389.77639ps 1.14965V/234.50303ps
R_load = 50.0
| Removed startup time: 0s 0s 0s  .
| Removed end time: 2.43ns.
[Rising Waveform]
R_fixture   = 50.0
V_fixture   = 3.3V
V_fixture_min = 2.7V
V_fixture_max = 3.6V
0s        1.649V     1.66V      1.682V
350ps     1.65V      1.66V      1.719V
540ps     1.699V     1.661V     3.27V
630ps     2.327V     1.661V     3.534V
760ps     3.05V      1.658V     3.576V
860ps     3.245V     1.639V     3.585V
1.05ns    3.283V     1.723V     3.592V
1.25ns    3.291V     2.411V     3.595V
1.41ns    3.294V     2.623V     3.596V
2.45ns    3.298V     2.699V     3.598V
| Removed startup time: 0s 0s 0s  .
| Removed end time: 5.11ns.
[Falling Waveform]
R_fixture   = 50.0
V_fixture   = 3.3V
V_fixture_min = 2.7V
V_fixture_max = 3.6V
0s        3.298V     2.699V     3.598V
560ps     3.301V     2.699V     3.644V
740ps     3.312V     2.699V     2.537V
850ps     3.32V      2.699V     2.108V
1.06ns    2.378V     2.7V       1.84V
1.2ns     1.964V     2.7V       1.777V
1.64ns    1.71V      2.689V     1.686V
2.08ns    1.668V     1.946V     1.682V
2.46ns    1.652V     1.67V      1.682V
5.13ns    1.649V     1.66V      1.682V
| Removed startup time: 0s 0s 0s  .
| Removed end time: 3.07ns.
[Rising Waveform]
R_fixture   = 50.0
V_fixture   = 0V
V_fixture_min = 0V
V_fixture_max = 0V
0s        157uV      126.8uV    187.5uV
500ps     -6.421mV   212.9uV    54.8mV
740ps     60.63mV    -154.4uV   1.768V
920ps     1.25V      -3.005mV   2.24V
1.04ns    1.686V     -4.47mV    2.291V
1.23ns    1.891V     -11.49mV   2.315V
1.41ns    1.922V     66.36mV    2.322V
1.75ns    1.94V      872.4mV    2.326V
1.93ns    1.944V     1.109V     2.327V
3.09ns    1.95V      1.229V     2.329V
| Removed startup time: 0s 0s 0s  .
| Removed end time: 2.8ns.
[Falling Waveform]
R_fixture   = 50.0
V_fixture   = 0V
V_fixture_min = 0V
V_fixture_max = 0V
0s        1.95V      1.229V     2.329V
500ps     1.951V     1.229V     2.332V
630ps     1.957V     1.23V      402mV
710ps     1.969V     1.231V     52.34mV
760ps     1.87V      1.231V     30.45mV
910ps     313.4mV    1.232V     13.84mV
990ps     56.51mV    1.233V     10.01mV
1.4ns     6.684mV    1.212V     1.725mV
1.75ns    2.666mV    60.68mV    429.5uV
2.82ns    157uV      126.3uV    187.5uV
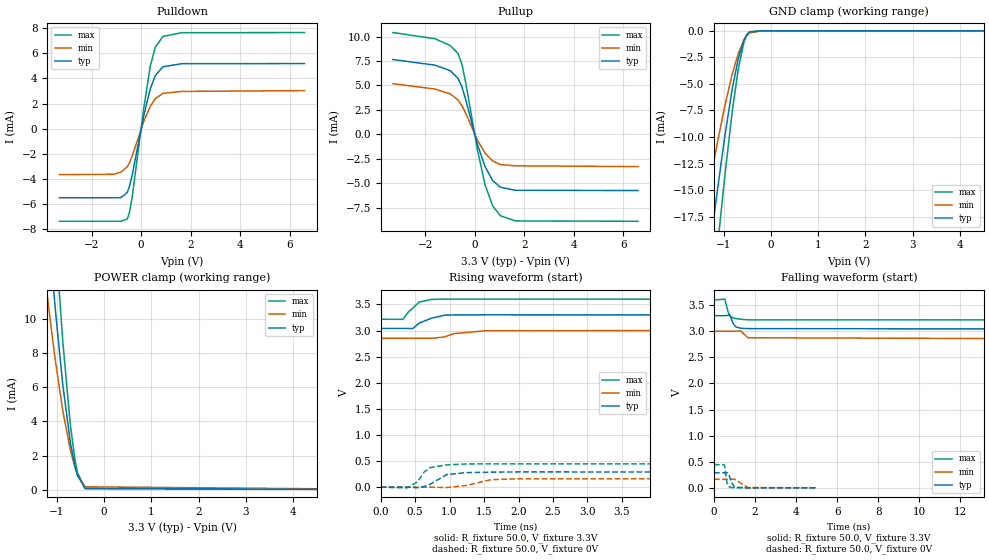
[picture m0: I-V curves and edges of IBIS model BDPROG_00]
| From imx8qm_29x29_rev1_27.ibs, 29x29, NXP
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[Model] BDPROG_00
Model_type I/O
Polarity   Non-Inverting
Enable   Active-Low
| CAP_THRESHOLD on pad IO is "CMOS" :
| Rising=10.0% of vdde3v3   Falling=90.0% of vdde3v3
| C_comp min and max val. don't necessarily correlate with the min and max pvt
| but are the smallest and greatest pad capacitance found.
| var   typ   min   max
C_comp   1.85655pF  1.66230pF  1.93185pF
Vinl = 800.0mV
Vinh = 2.0V
Vmeas = 1.65V   | Reference voltage for timing measurements
Cref  = 50.0pF   | Timing specification test load capacitance value
Rref  = 1.0MOhm   | Timing specification test load resistance value
Vref  = 3.3V   | Timing specification test load voltage
[Model Spec]
| TIME_THRESHOLD on pin ZI is "CORE" :
| Rising=50.0% of vdd   Falling=50.0% of vdd
Vinl 800.00000mV 800.00000mV 800.00000mV
Vinh 2.00000V 2.00000V 2.00000V
Vmeas 1.65000V 1.50000V 1.80000V
Vref 3.30000V 3.00000V 3.60000V
| variable   typ   min   max
[Temperature Range] 25.0 125.0 -40.0
| variable   typ   min   max
[Voltage Range] 3.3V 3.0V 3.6V
| variable   typ   min   max
[POWER Clamp Reference] 3.3V 3.0V 3.6V
| variable   typ   min   max
[GND Clamp Reference] 0V 0V 0V
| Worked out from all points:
|   slope of the pulldown table from 0 to 0.495 V, typ, clamps not added: 127 ohm
|   slope of the pullup table from 0 to 0.495 V, typ, clamps not added: 133 ohm
|   GND clamp passes 1 mA (typ) near -0.58 V on its own axis
|   POWER clamp passes 1 mA (typ) near -0.58 V on its own axis
|   rising waveform, R_fixture 50.0, V_fixture 3.3V: 20-80 % time 242ps typ, 384ps min, 170ps max; typ from 3.04 V to 3.3 V
|   falling waveform, R_fixture 50.0, V_fixture 3.3V: 20-80 % time 201ps typ, 233ps min, 192ps max; typ from 3.3 V to 3.04 V
|   rising waveform, R_fixture 50.0, V_fixture 0V: 20-80 % time 192ps typ, 294ps min, 169ps max; typ from 0 V to 0.288 V
|   falling waveform, R_fixture 50.0, V_fixture 0V: 20-80 % time 135ps typ, 228ps min, 92.2ps max; typ from 0.288 V to 0 V
[POWER Clamp]
-3.3V     110.4mA    79.71mA    140.4mA
-1.39V    23.37mA    16.28mA    32.13mA
-1.23V    17.37mA    12.17mA    24.18mA
-1.18V    15.59mA    10.96mA    21.8mA
-1.08V    12.22mA    8.693mA    17.21mA
-1.02V    10.33mA    7.426mA    14.59mA
-870mV    6.147mA    4.623mA    8.679mA
-710mV    2.758mA    2.312mA    3.771mA
-610mV    1.329mA    1.277mA    1.706mA
-560mV    827.2uA    884.9uA    1.001mA
-400mV    73.97uA    165.7uA    50.71uA
6.6V      0A         0A         0A
[GND Clamp]
-3.3V     -81.81mA   -63.72mA   -95.03mA
-1.44V    -25.76mA   -18.09mA   -33.96mA
-1.29V    -20.51mA   -14.35mA   -27.46mA
-1.13V    -15.01mA   -10.53mA   -20.42mA
-980mV    -10.12mA   -7.21mA    -13.93mA
-820mV    -5.543mA   -4.118mA   -7.691mA
-690mV    -2.659mA   -2.142mA   -3.617mA
-570mV    -870.5uA   -872.8uA   -1.079mA
-510mV    -367.8uA   -465.5uA   -395.3uA
-450mV    -106.6uA   -203.3uA   -84.64uA
-200mV    -18.65nA   -455.7nA   -5.392nA
6.6V      19.28nA    1.199uA    15.29nA
| variable   typ   min   max
[Pullup Reference] 3.3V 3.0V 3.6V
| variable   typ   min   max
[Pulldown Reference] 0V 0V 0V
[Pullup]
-3.3V     7.65mA     5.178mA    10.41mA
-1.6V     7.074mA    4.627mA    9.78mA
-980mV    6.503mA    4.126mA    9.076mA
-670mV    5.726mA    3.508mA    8.271mA
-510mV    4.831mA    2.929mA    7.136mA
-360mV    3.538mA    2.157mA    5.282mA
110mV     -995uA     -592uA     -1.543mA
420mV     -3.312mA   -1.933mA   -5.167mA
730mV     -4.74mA    -2.735mA   -7.345mA
1.04V     -5.422mA   -3.106mA   -8.343mA
1.65V     -5.734mA   -3.234mA   -8.875mA
6.6V      -5.763mA   -3.312mA   -8.912mA
[Pulldown]
-3.3V     -5.503mA   -3.658mA   -7.376mA
-1.13V    -5.503mA   -3.633mA   -7.376mA
-820mV    -5.491mA   -3.465mA   -7.376mA
-560mV    -5.072mA   -3.029mA   -7.198mA
-470mV    -4.587mA   -2.712mA   -6.658mA
-360mV    -3.651mA   -2.162mA   -5.401mA
110mV     1.068mA    601.1uA    1.69mA
370mV     3.188mA    1.784mA    4.999mA
570mV     4.234mA    2.386mA    6.482mA
880mV     4.931mA    2.817mA    7.347mA
1.65V     5.176mA    2.966mA    7.645mA
6.6V      5.183mA    3.03mA     7.653mA
[Ramp]
dV/dt_r 172.58384mV/191.48677ps 97.35732mV/294.08353ps 267.03784mV/224.59482ps
dV/dt_f 155.3793mV/201.03411ps 89.06582mV/233.29367ps 229.52395mV/192.19807ps
R_load = 50.0
| Removed startup time: 0s 0s 0s  .
| Removed end time: 5.0ns.
[Rising Waveform]
R_fixture   = 50.0
V_fixture   = 3.3V
V_fixture_min = 3.0V
V_fixture_max = 3.6V
0s        3.041V     2.852V     3.217V
324ps     3.041V     2.852V     3.215V
398ps     3.04V      2.852V     3.351V
469ps     3.04V      2.852V     3.431V
555ps     3.141V     2.852V     3.543V
735ps     3.235V     2.851V     3.596V
926ps     3.294V     2.878V     3.602V
1.063ns   3.299V     2.941V     3.602V
1.528ns   3.302V     2.997V     3.602V
5ns       3.3V       3.001V     3.6V
| Removed startup time: 0s 0s 0s  .
| Removed end time: 20.0ns.
[Falling Waveform]
R_fixture   = 50.0
V_fixture   = 3.3V
V_fixture_min = 3.0V
V_fixture_max = 3.6V
0s        3.3V       3V         3.6V
524ps     3.3V       3V         3.616V
676ps     3.304V     3V         3.376V
756ps     3.317V     3V         3.306V
804ps     3.279V     3V         3.283V
924ps     3.148V     3V         3.257V
1.052ns   3.086V     3.001V     3.244V
1.288ns   3.059V     3.009V     3.231V
1.644ns   3.051V     2.876V     3.219V
20ns      3.041V     2.852V     3.217V
| Removed startup time: 0s 0s 0s  .
| Removed end time: 20.0ns.
[Rising Waveform]
R_fixture   = 50.0
V_fixture   = 0V
V_fixture_min = 0V
V_fixture_max = 0V
0s        49.78nV    826.1nV    95.98nV
384ps     373.5uV    584.7nV    -12.64mV
536ps     -9.755mV   -2.778uV   103.2mV
632ps     13.88mV    -21.84uV   291.8mV
716ps     55.24mV    207.3uV    374mV
960ps     243.4mV    -6.356mV   428mV
1.248ns   278.9mV    34.29mV    444.8mV
1.596ns   288.4mV    143.7mV    447.5mV
1.956ns   292.3mV    159.9mV    447.7mV
20ns      287.6mV    162.3mV    445.2mV
| Removed startup time: 0s 0s 0s  .
| Removed end time: 4.999ns.
[Falling Waveform]
R_fixture   = 50.0
V_fixture   = 0V
V_fixture_min = 0V
V_fixture_max = 0V
0s        287.6mV    162.2mV    445.2mV
490ps     287.6mV    162.2mV    442.3mV
530ps     287.6mV    162.3mV    384mV
595ps     288.8mV    162.3mV    169.8mV
639ps     290.8mV    162.3mV    79.69mV
717ps     262.1mV    162.4mV    23.23mV
811ps     129mV      162.3mV    7.049mV
994ps     13.69mV    163.7mV    851.1uV
1.644ns   -635.1uV   4.47mV     -1.29mV
4.999ns   261.5uV    -603.4uV   450.1uV
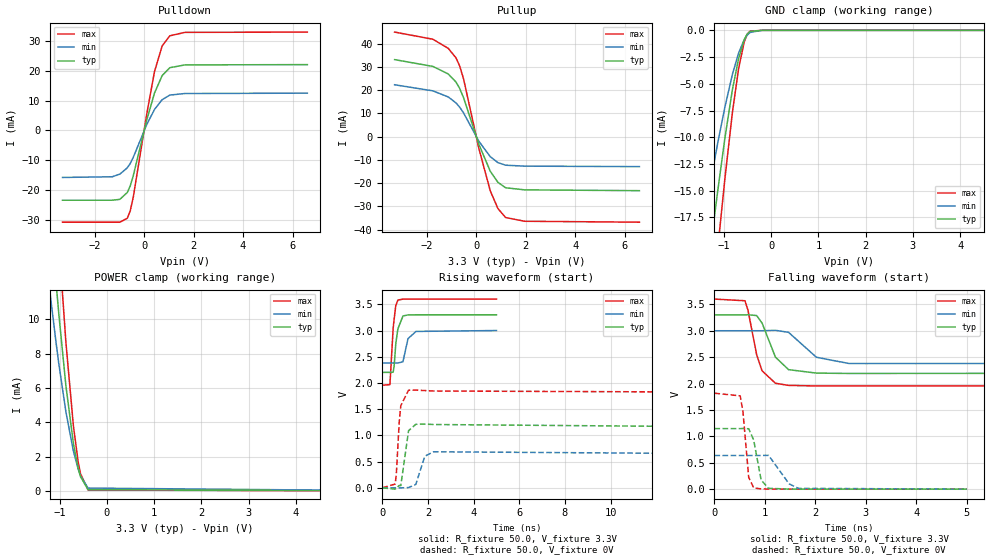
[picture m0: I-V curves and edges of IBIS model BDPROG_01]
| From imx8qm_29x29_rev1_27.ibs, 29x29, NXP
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[Model] BDPROG_01
Model_type I/O
Polarity   Non-Inverting
Enable   Active-Low
| CAP_THRESHOLD on pad IO is "CMOS" :
| Rising=10.0% of vdde3v3   Falling=90.0% of vdde3v3
| C_comp min and max val. don't necessarily correlate with the min and max pvt
| but are the smallest and greatest pad capacitance found.
| var   typ   min   max
C_comp   1.85655pF  1.66230pF  1.93185pF
Vinl = 800.0mV
Vinh = 2.0V
Vmeas = 1.65V   | Reference voltage for timing measurements
Cref  = 50.0pF   | Timing specification test load capacitance value
Rref  = 1.0MOhm   | Timing specification test load resistance value
Vref  = 3.3V   | Timing specification test load voltage
[Model Spec]
| TIME_THRESHOLD on pin ZI is "CORE" :
| Rising=50.0% of vdd   Falling=50.0% of vdd
Vinl 800.00000mV 800.00000mV 800.00000mV
Vinh 2.00000V 2.00000V 2.00000V
Vmeas 1.65000V 1.50000V 1.80000V
Vref 3.30000V 3.00000V 3.60000V
| variable   typ   min   max
[Temperature Range] 25.0 125.0 -40.0
| variable   typ   min   max
[Voltage Range] 3.3V 3.0V 3.6V
| variable   typ   min   max
[POWER Clamp Reference] 3.3V 3.0V 3.6V
| variable   typ   min   max
[GND Clamp Reference] 0V 0V 0V
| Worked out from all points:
|   slope of the pulldown table from 0 to 0.495 V, typ, clamps not added: 34.9 ohm
|   slope of the pullup table from 0 to 0.495 V, typ, clamps not added: 37.2 ohm
|   GND clamp passes 1 mA (typ) near -0.58 V on its own axis
|   POWER clamp passes 1 mA (typ) near -0.58 V on its own axis
|   rising waveform, R_fixture 50.0, V_fixture 3.3V: 20-80 % time 177ps typ, 201ps min, 158ps max; typ from 2.2 V to 3.3 V
|   falling waveform, R_fixture 50.0, V_fixture 3.3V: 20-80 % time 291ps typ, 421ps min, 233ps max; typ from 3.3 V to 2.2 V
|   rising waveform, R_fixture 50.0, V_fixture 0V: 20-80 % time 168ps typ, 236ps min, 151ps max; typ from 0 V to 1.15 V
|   falling waveform, R_fixture 50.0, V_fixture 0V: 20-80 % time 128ps typ, 199ps min, 95.5ps max; typ from 1.15 V to 0 V
[POWER Clamp]
-3.3V     110.4mA    79.71mA    140.4mA
-1.39V    23.37mA    16.28mA    32.13mA
-1.23V    17.37mA    12.17mA    24.18mA
-1.18V    15.59mA    10.96mA    21.8mA
-1.08V    12.22mA    8.693mA    17.21mA
-1.02V    10.33mA    7.426mA    14.59mA
-870mV    6.147mA    4.623mA    8.679mA
-710mV    2.758mA    2.312mA    3.771mA
-610mV    1.329mA    1.277mA    1.706mA
-560mV    827.2uA    884.9uA    1.001mA
-400mV    73.97uA    165.7uA    50.71uA
6.6V      0A         0A         0A
[GND Clamp]
-3.3V     -81.81mA   -63.72mA   -95.03mA
-1.44V    -25.76mA   -18.09mA   -33.96mA
-1.29V    -20.51mA   -14.35mA   -27.46mA
-1.13V    -15.01mA   -10.53mA   -20.42mA
-980mV    -10.12mA   -7.21mA    -13.93mA
-820mV    -5.543mA   -4.118mA   -7.691mA
-690mV    -2.659mA   -2.142mA   -3.617mA
-570mV    -870.5uA   -872.8uA   -1.079mA
-510mV    -367.8uA   -465.5uA   -395.3uA
-450mV    -106.6uA   -203.3uA   -84.64uA
-200mV    -18.65nA   -455.7nA   -5.392nA
6.6V      19.28nA    1.199uA    15.29nA
| variable   typ   min   max
[Pullup Reference] 3.3V 3.0V 3.6V
| variable   typ   min   max
[Pulldown Reference] 0V 0V 0V
[Pullup]
-3.3V     33.15mA    22.33mA    44.99mA
-1.75V    30.22mA    19.7mA     41.91mA
-1.13V    26.96mA    17.08mA    37.98mA
-820mV    23.53mA    14.54mA    33.95mA
-670mV    20.78mA    12.71mA    30.46mA
-510mV    16.71mA    10.19mA    24.8mA
110mV     -3.373mA   -2.016mA   -5.198mA
570mV     -14.91mA   -8.636mA   -23.37mA
880mV     -19.67mA   -11.18mA   -30.96mA
1.19V     -21.99mA   -12.28mA   -34.79mA
1.96V     -22.89mA   -12.69mA   -36.4mA
6.6V      -23.24mA   -12.89mA   -36.8mA
[Pulldown]
-3.3V     -23.32mA   -15.71mA   -30.67mA
-1.29V    -23.32mA   -15.48mA   -30.67mA
-980mV    -23.03mA   -14.58mA   -30.67mA
-680mV    -20.72mA   -12.48mA   -29.35mA
-560mV    -18.5mA    -11.01mA   -26.83mA
-440mV    -15.16mA   -9mA       -22.35mA
110mV     3.628mA    2.066mA    5.68mA
420mV     12.53mA    7.034mA    19.69mA
730mV     18.37mA    10.31mA    28.31mA
1.04V     20.99mA    11.84mA    31.66mA
1.65V     21.93mA    12.36mA    32.81mA
6.6V      22.02mA    12.48mA    32.9mA
[Ramp]
dV/dt_r 688.28789mV/167.86531ps 382.3013mV/236.37967ps 1.08999V/150.52572ps
dV/dt_f 659.0028mV/291.39232ps 371.62493mV/421.23821ps 986.08241mV/232.946ps
R_load = 50.0
| Removed startup time: 0s 0s 0s  .
| Removed end time: 5.0ns.
[Rising Waveform]
R_fixture   = 50.0
V_fixture   = 3.3V
V_fixture_min = 3.0V
V_fixture_max = 3.6V
0s        2.202V     2.381V     1.957V
331ps     2.202V     2.381V     1.968V
474ps     2.206V     2.381V     3.049V
516ps     2.324V     2.381V     3.215V
589ps     2.751V     2.381V     3.478V
681ps     3.033V     2.381V     3.581V
903ps     3.277V     2.405V     3.599V
1.123ns   3.298V     2.845V     3.6V
1.475ns   3.3V       2.983V     3.6V
5ns       3.3V       3V         3.6V
| Removed startup time: 0s 0s 0s  .
| Removed end time: 20.0ns.
[Falling Waveform]
R_fixture   = 50.0
V_fixture   = 3.3V
V_fixture_min = 3.0V
V_fixture_max = 3.6V
0s        3.3V       3V         3.6V
604ps     3.3V       3V         3.568V
664ps     3.303V     3V         3.393V
836ps     3.288V     3V         2.548V
944ps     3.145V     3V         2.241V
1.208ns   2.501V     3.008V     2.006V
1.468ns   2.263V     2.97V      1.965V
2.02ns    2.198V     2.498V     1.954V
2.668ns   2.191V     2.379V     1.955V
20ns      2.202V     2.381V     1.957V
| Removed startup time: 0s 0s 0s  .
| Removed end time: 20.0ns.
[Rising Waveform]
R_fixture   = 50.0
V_fixture   = 0V
V_fixture_min = 0V
V_fixture_max = 0V
0s        27.79nV    538.9nV    47.33nV
564ps     -24.86mV   -8.189uV   73.26mV
616ps     -3.501mV   -17.94uV   290.8mV
740ps     45.53mV    301.6uV    1.266V
808ps     43.59mV    64.97uV    1.567V
1.148ns   1.09V      5.746mV    1.862V
1.464ns   1.212V     64.82mV    1.864V
1.86ns    1.216V     602.6mV    1.855V
2.236ns   1.208V     688.1mV    1.847V
20ns      1.147V     637.2mV    1.817V
| Removed startup time: 0s 0s 0s  .
| Removed end time: 4.999ns.
[Falling Waveform]
R_fixture   = 50.0
V_fixture   = 0V
V_fixture_min = 0V
V_fixture_max = 0V
0s        1.147V     636.9mV    1.817V
510ps     1.147V     636.9mV    1.767V
564ps     1.149V     637mV      1.476V
679ps     1.144V     637.1mV    223.7mV
778ps     929.8mV    637.2mV    22.78mV
925ps     171.9mV    638.3mV    5.262mV
1.072ns   15.8mV     640mV      2.236mV
1.479ns   1.323mV    100.9mV    200.4uV
1.66ns    610.6uV    15.73mV    105uV
4.999ns   -41.05uV   -249.3uV   43.35uV
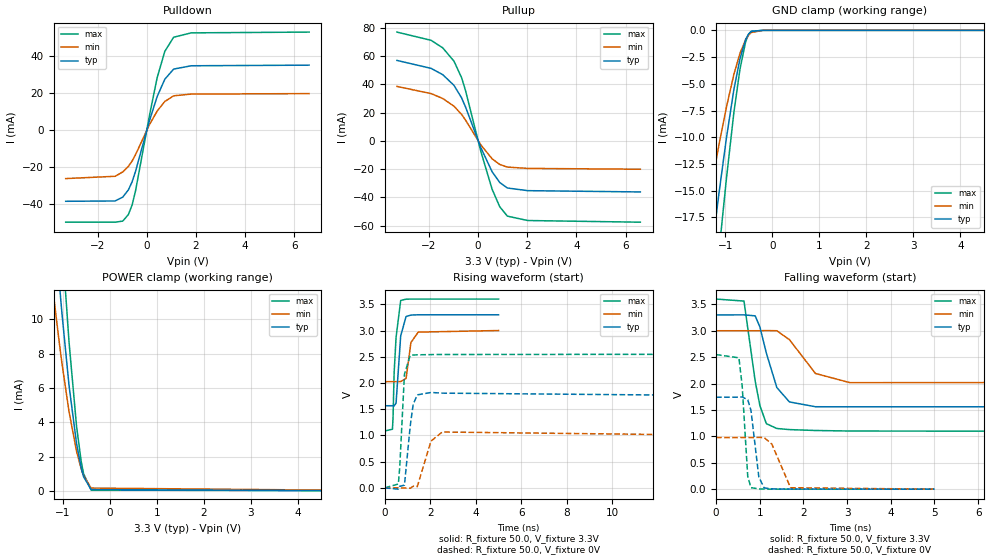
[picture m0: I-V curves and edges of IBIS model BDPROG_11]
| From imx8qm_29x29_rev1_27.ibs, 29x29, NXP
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[Model] BDPROG_11
Model_type I/O
Polarity   Non-Inverting
Enable   Active-Low
| CAP_THRESHOLD on pad IO is "CMOS" :
| Rising=10.0% of vdde3v3   Falling=90.0% of vdde3v3
| C_comp min and max val. don't necessarily correlate with the min and max pvt
| but are the smallest and greatest pad capacitance found.
| var   typ   min   max
C_comp   1.85655pF  1.66230pF  1.93185pF
Vinl = 800.0mV
Vinh = 2.0V
Vmeas = 1.65V   | Reference voltage for timing measurements
Cref  = 50.0pF   | Timing specification test load capacitance value
Rref  = 1.0MOhm   | Timing specification test load resistance value
Vref  = 3.3V   | Timing specification test load voltage
[Model Spec]
| TIME_THRESHOLD on pin ZI is "CORE" :
| Rising=50.0% of vdd   Falling=50.0% of vdd
Vinl 800.00000mV 800.00000mV 800.00000mV
Vinh 2.00000V 2.00000V 2.00000V
Vmeas 1.65000V 1.50000V 1.80000V
Vref 3.30000V 3.00000V 3.60000V
| variable   typ   min   max
[Temperature Range] 25.0 125.0 -40.0
| variable   typ   min   max
[Voltage Range] 3.3V 3.0V 3.6V
| variable   typ   min   max
[POWER Clamp Reference] 3.3V 3.0V 3.6V
| variable   typ   min   max
[GND Clamp Reference] 0V 0V 0V
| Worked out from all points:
|   slope of the pulldown table from 0 to 0.495 V, typ, clamps not added: 24 ohm
|   slope of the pullup table from 0 to 0.495 V, typ, clamps not added: 25.5 ohm
|   GND clamp passes 1 mA (typ) near -0.58 V on its own axis
|   POWER clamp passes 1 mA (typ) near -0.58 V on its own axis
|   rising waveform, R_fixture 50.0, V_fixture 3.3V: 20-80 % time 176ps typ, 188ps min, 159ps max; typ from 1.57 V to 3.3 V
|   falling waveform, R_fixture 50.0, V_fixture 3.3V: 20-80 % time 356ps typ, 529ps min, 266ps max; typ from 3.3 V to 1.57 V
|   rising waveform, R_fixture 50.0, V_fixture 0V: 20-80 % time 212ps typ, 312ps min, 169ps max; typ from 0 V to 1.74 V
|   falling waveform, R_fixture 50.0, V_fixture 0V: 20-80 % time 141ps typ, 215ps min, 112ps max; typ from 1.74 V to 0 V
[POWER Clamp]
-3.3V     110.4mA    79.71mA    140.4mA
-1.39V    23.37mA    16.28mA    32.13mA
-1.23V    17.37mA    12.17mA    24.18mA
-1.18V    15.59mA    10.96mA    21.8mA
-1.08V    12.22mA    8.693mA    17.21mA
-1.02V    10.33mA    7.426mA    14.59mA
-870mV    6.147mA    4.623mA    8.679mA
-710mV    2.758mA    2.312mA    3.771mA
-610mV    1.329mA    1.277mA    1.706mA
-560mV    827.2uA    884.9uA    1.001mA
-400mV    73.97uA    165.7uA    50.71uA
6.6V      0A         0A         0A
[GND Clamp]
-3.3V     -81.81mA   -63.72mA   -95.03mA
-1.44V    -25.76mA   -18.09mA   -33.96mA
-1.29V    -20.51mA   -14.35mA   -27.46mA
-1.13V    -15.01mA   -10.53mA   -20.42mA
-980mV    -10.12mA   -7.21mA    -13.93mA
-820mV    -5.543mA   -4.118mA   -7.691mA
-690mV    -2.659mA   -2.142mA   -3.617mA
-570mV    -870.5uA   -872.8uA   -1.079mA
-510mV    -367.8uA   -465.5uA   -395.3uA
-450mV    -106.6uA   -203.3uA   -84.64uA
-200mV    -18.65nA   -455.7nA   -5.392nA
6.6V      19.28nA    1.199uA    15.29nA
| variable   typ   min   max
[Pullup Reference] 3.3V 3.0V 3.6V
| variable   typ   min   max
[Pulldown Reference] 0V 0V 0V
[Pullup]
-3.3V     56.86mA    38.46mA    76.9mA
-1.91V    51.22mA    33.38mA    71.07mA
-1.44V    46.81mA    29.96mA    65.78mA
-980mV    39.22mA    24.48mA    56.35mA
-670mV    30.34mA    18.63mA    44.61mA
-510mV    23.93mA    14.66mA    35.52mA
110mV     -4.821mA   -2.89mA    -7.4mA
570mV     -21.86mA   -12.69mA   -34.23mA
880mV     -29.49mA   -16.73mA   -46.62mA
1.19V     -33.4mA    -18.61mA   -53.29mA
2.02V     -35.28mA   -19.54mA   -56.41mA
6.6V      -36.19mA   -20.13mA   -57.59mA
[Pulldown]
-3.3V     -38.7mA    -26.38mA   -50.04mA
-1.29V    -38.53mA   -25.14mA   -50.04mA
-980mV    -36.45mA   -22.78mA   -49.44mA
-750mV    -32.5mA    -19.74mA   -45.89mA
-600mV    -28.18mA   -16.89mA   -40.75mA
-460mV    -22.5mA    -13.42mA   -33.12mA
110mV     5.15mA     2.953mA    8.008mA
420mV     18.09mA    10.22mA    28.34mA
730mV     27.48mA    15.43mA    42.58mA
1.09V     33.02mA    18.51mA    50.3mA
1.81V     34.82mA    19.46mA    52.67mA
6.6V      35.15mA    19.71mA    53.09mA
[Ramp]
dV/dt_r 1.04558V/211.68714ps 586.56686mV/312.02719ps 1.52969V/168.89692ps
dV/dt_f 1.04039V/356.34889ps 584.78957mV/528.81476ps 1.50817V/266.36685ps
R_load = 50.0
| Removed startup time: 0s 0s 0s  .
| Removed end time: 5.0ns.
[Rising Waveform]
R_fixture   = 50.0
V_fixture   = 3.3V
V_fixture_min = 3.0V
V_fixture_max = 3.6V
0s        1.566V     2.025V     1.086V
337ps     1.566V     2.025V     1.118V
363ps     1.566V     2.025V     1.336V
410ps     1.563V     2.025V     2.187V
496ps     1.615V     2.025V     2.87V
699ps     2.898V     2.026V     3.573V
935ps     3.267V     2.087V     3.598V
1.15ns    3.295V     2.773V     3.6V
1.47ns    3.3V       2.97V      3.6V
5ns       3.3V       3V         3.6V
| Removed startup time: 0s 0s 0s  .
| Removed end time: 20.0ns.
[Falling Waveform]
R_fixture   = 50.0
V_fixture   = 3.3V
V_fixture_min = 3.0V
V_fixture_max = 3.6V
0s        3.3V       3V         3.6V
640ps     3.301V     3V         3.562V
896ps     3.282V     3V         2.048V
1.004ns   3.072V     3V         1.583V
1.152ns   2.576V     3.004V     1.24V
1.392ns   1.924V     3V         1.149V
1.68ns    1.652V     2.831V     1.128V
2.276ns   1.561V     2.191V     1.111V
3.064ns   1.559V     2.017V     1.101V
20ns      1.566V     2.025V     1.086V
| Removed startup time: 0s 0s 0s  .
| Removed end time: 20.0ns.
[Rising Waveform]
R_fixture   = 50.0
V_fixture   = 0V
V_fixture_min = 0V
V_fixture_max = 0V
0s        22.04nV    445.7nV    36.57nV
596ps     -24.89mV   -13.54uV   73.84mV
656ps     30.34mV    -2.478uV   384.7mV
864ps     51.23mV    -1.89mV    2.167V
1.116ns   1.173V     -7.95mV    2.525V
1.248ns   1.594V     30.75mV    2.533V
1.428ns   1.773V     23.37mV    2.537V
2.028ns   1.819V     891mV      2.541V
2.528ns   1.806V     1.065V     2.543V
20ns      1.741V     977.6mV    2.549V
| Removed startup time: 0s 0s 0s  .
| Removed end time: 4.999ns.
[Falling Waveform]
R_fixture   = 50.0
V_fixture   = 0V
V_fixture_min = 0V
V_fixture_max = 0V
0s        1.741V     977.1mV    2.549V
524ps     1.742V     977.1mV    2.487V
599ps     1.746V     977.1mV    1.954V
726ps     1.693V     977.4mV    240.2mV
800ps     1.491V     977.6mV    28.18mV
980ps     228.7mV    979.8mV    4.975mV
1.101ns   24.71mV    978.4mV    2.6mV
1.277ns   5.361mV    852.7mV    943.1uV
1.706ns   1.072mV    26.8mV     167.7uV
4.999ns   18.58uV    -131.5uV   43.6uV
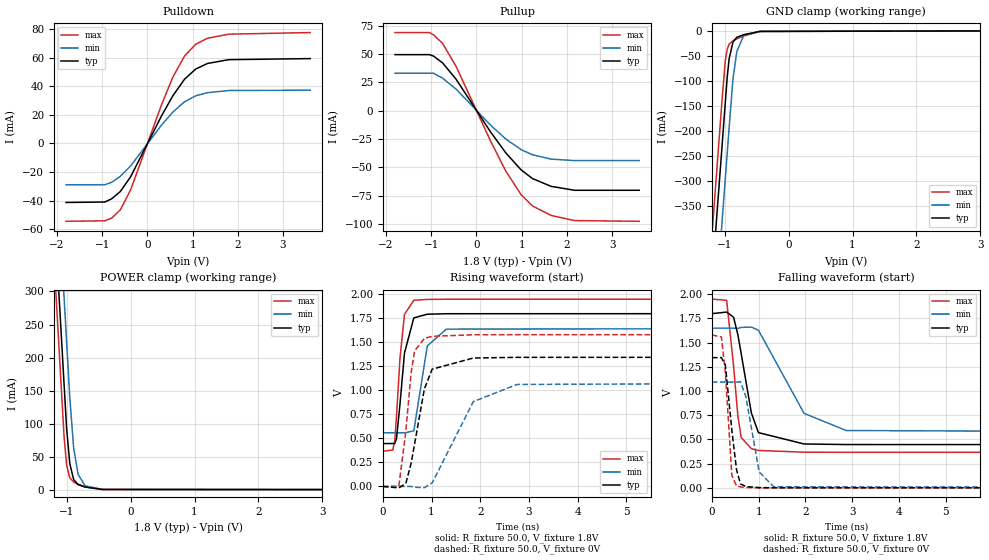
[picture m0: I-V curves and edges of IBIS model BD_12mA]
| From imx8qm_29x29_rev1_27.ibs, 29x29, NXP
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[Model] BD_12mA
Model_type I/O
Polarity   Non-Inverting
Enable   Active-Low
| C_comp min and max val. don't necessarily correlate with the min and max pvt
| but are the smallest and greatest pad capacitance found.
| var   typ   min   max
C_comp   1.59140pF  1.51715pF  1.65910pF
Vinl = 577.5mV
Vinh = 1.2675V
Vmeas = 900.0mV   | Reference voltage for timing measurements
Cref  = 15.0pF   | Timing specification test load capacitance value
Rref  = 1.0MOhm   | Timing specification test load resistance value
Vref  = 1.8V   | Timing specification test load voltage
[Model Spec]
| :
Vinl 630.00000mV 577.50000mV 682.50000mV
Vinh 1.17000V 1.07250V 1.26750V
| variable   typ   min   max
[Temperature Range] 25.0 125.0 -40.0
| variable   typ   min   max
[Voltage Range] 1.8V 1.65V 1.95V
| variable   typ   min   max
[POWER Clamp Reference] 1.8V 1.65V 1.95V
| variable   typ   min   max
[GND Clamp Reference] 0V 0V 0V
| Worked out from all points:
|   slope of the pulldown table from 0 to 0.27 V, typ, clamps not added: 16.1 ohm
|   slope of the pullup table from 0 to 0.27 V, typ, clamps not added: 16.7 ohm
|   GND clamp passes 1 mA (typ) near -0.44 V on its own axis
|   POWER clamp passes 1 mA (typ) near -0.55 V on its own axis
|   rising waveform, R_fixture 50.0, V_fixture 1.8V: 20-80 % time 157ps typ, 180ps min, 132ps max; typ from 0.446 V to 1.8 V
|   falling waveform, R_fixture 50.0, V_fixture 1.8V: 20-80 % time 296ps typ, 708ps min, 169ps max; typ from 1.8 V to 0.446 V
|   rising waveform, R_fixture 50.0, V_fixture 0V: 20-80 % time 291ps typ, 614ps min, 174ps max; typ from 0 V to 1.34 V
|   falling waveform, R_fixture 50.0, V_fixture 0V: 20-80 % time 160ps typ, 226ps min, 114ps max; typ from 1.34 V to 0 V
[POWER Clamp]
-1.8V     1.452A     1.584A     1.373A
-1.18V    398.2mA    529.9mA    318.8mA
-1.15V    347.2mA    478.9mA    267.8mA
-1.12V    296.2mA    427.9mA    216.8mA
-1.04V    160.2mA    291.9mA    80.78mA
-1V       92.69mA    223.9mA    36.89mA
-950mV    39.12mA    138.9mA    17.72mA
-890mV    15.28mA    63.28mA    11.47mA
-820mV    7.619mA    23.03mA    8.072mA
-710mV    3.877mA    5.679mA    4.137mA
-440mV    198.6uA    468.9uA    81.6uA
3.6V      0A         0A         0A
[GND Clamp]
-1.8V     -1.52A     -1.672A    -1.429A
-1.21V    -517.1mA   -668.6mA   -425.9mA
-1.12V    -364.1mA   -515.6mA   -272.9mA
-1.04V    -228.1mA   -379.6mA   -136.9mA
-990mV    -143.1mA   -294.6mA   -59.11mA
-960mV    -92.41mA   -243.6mA   -36.73mA
-930mV    -55.69mA   -192.6mA   -26.66mA
-870mV    -22.37mA   -96.04mA   -19.77mA
-810mV    -12.81mA   -41.2mA    -16.04mA
-700mV    -7.565mA   -8.808mA   -10.1mA
-450mV    -1.118mA   -1.064mA   -1.253mA
3.6V      32.66uA    16.11uA    55.52uA
| variable   typ   min   max
[Pullup Reference] 1.8V 1.65V 1.95V
| variable   typ   min   max
[Pulldown Reference] 0V 0V 0V
[Pullup]
-1.8V     49.58mA    33.12mA    69.08mA
-1.04V    49.58mA    33.12mA    69.08mA
-950mV    48.32mA    33.12mA    67.12mA
-750mV    42.34mA    28.83mA    59.56mA
-450mV    27.85mA    19.13mA    39.2mA
310mV     -18.57mA   -12.63mA   -26.55mA
650mV     -37.26mA   -24.97mA   -53.38mA
990mV     -52.31mA   -34.41mA   -74.27mA
1.24V     -59.93mA   -38.89mA   -84.14mA
1.65V     -66.78mA   -42.73mA   -92.5mA
2.17V     -70.27mA   -44.05mA   -97.05mA
3.6V      -70.27mA   -44.05mA   -97.68mA
[Pulldown]
-1.8V     -41.19mA   -28.81mA   -54.34mA
-940mV    -40.88mA   -28.81mA   -53.99mA
-790mV    -38.61mA   -27.06mA   -52.11mA
-600mV    -33.58mA   -22.92mA   -46.35mA
-370mV    -23.17mA   -15.62mA   -32.35mA
310mV     19.14mA    12.75mA    26.88mA
560mV     33.19mA    21.87mA    46.16mA
820mV     44.84mA    29.1mA     61.05mA
1.07V     52.02mA    33.3mA     69.32mA
1.33V     55.88mA    35.48mA    73.47mA
1.8V      58.52mA    36.99mA    76.32mA
3.6V      59.26mA    37.18mA    77.44mA
[Ramp]
dV/dt_r 806.75803mV/291.36766ps 655.54291mV/614.09262ps 947.82793mV/174.28592ps
dV/dt_f 812.28312mV/296.22415ps 655.01202mV/708.04056ps 949.46005mV/168.73899ps
R_load = 50.0
| Removed startup time: 0s 0s 0s  .
| Removed end time: 20.0ns.
[Rising Waveform]
R_fixture   = 50.0
V_fixture   = 1.8V
V_fixture_min = 1.65V
V_fixture_max = 1.95V
0s        446.3mV    558.4mV    367.6mV
204ps     447.1mV    558.4mV    379.2mV
244ps     446.6mV    558.4mV    476.3mV
280ps     497.8mV    558.4mV    729mV
352ps     857.5mV    558.4mV    1.335V
444ps     1.389V     558.4mV    1.791V
636ps     1.755V     578.6mV    1.938V
912ps     1.793V     1.463V     1.947V
1.304ns   1.798V     1.638V     1.949V
20ns      1.8V       1.65V      1.95V
| Removed startup time: 0s 0s 0s  .
| Removed end time: 20.0ns.
[Falling Waveform]
R_fixture   = 50.0
V_fixture   = 1.8V
V_fixture_min = 1.65V
V_fixture_max = 1.95V
0s        1.8V       1.65V      1.95V
316ps     1.816V     1.65V      1.938V
464ps     1.763V     1.65V      1.262V
556ps     1.582V     1.648V     741.6mV
628ps     1.384V     1.658V     519.1mV
844ps     775.6mV    1.661V     405.2mV
996ps     570.6mV    1.629V     386.4mV
1.972ns   453.5mV    769.8mV    368.5mV
2.872ns   447.5mV    592.6mV    367.6mV
20ns      446.2mV    558.3mV    367.6mV
| Removed startup time: 0s 0s 0s  .
| Removed end time: 20.0ns.
[Rising Waveform]
R_fixture   = 50.0
V_fixture   = 0V
V_fixture_min = 0V
V_fixture_max = 0V
0s        172.3nV    365.3nV    403.9nV
328ps     -14.5mV    370.8nV    2.319mV
472ps     32.5mV     2.273uV    576.6mV
580ps     239.8mV    935.8uV    1.183V
652ps     443.5mV    -8.463mV   1.411V
852ps     1.015V     -12.72mV   1.541V
1.012ns   1.221V     36.83mV    1.563V
1.856ns   1.337V     883.1mV    1.579V
2.756ns   1.344V     1.062V     1.58V
20ns      1.345V     1.093V     1.58V
| Removed startup time: 0s 0s 0s  .
| Removed end time: 20.0ns.
[Falling Waveform]
R_fixture   = 50.0
V_fixture   = 0V
V_fixture_min = 0V
V_fixture_max = 0V
0s        1.345V     1.093V     1.58V
204ps     1.346V     1.093V     1.559V
288ps     1.27V      1.093V     1.198V
428ps     594.4mV    1.093V     127.5mV
528ps     186.4mV    1.092V     19mV
612ps     40.45mV    1.097V     9.744mV
728ps     13.44mV    940mV      3.997mV
1.012ns   2.722mV    163.9mV    794.6uV
1.324ns   820.8uV    11.64mV    260.6uV
20ns      208.2nV    424.1nV    429.2nV
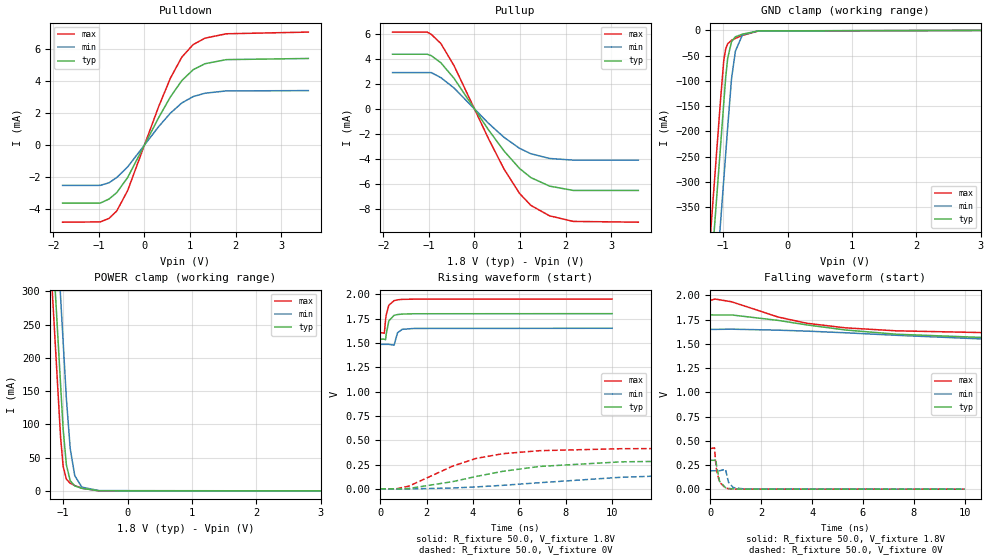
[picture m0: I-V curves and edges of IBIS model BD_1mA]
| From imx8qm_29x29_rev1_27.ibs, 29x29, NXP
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[Model] BD_1mA
Model_type I/O
Polarity   Non-Inverting
Enable   Active-Low
| C_comp min and max val. don't necessarily correlate with the min and max pvt
| but are the smallest and greatest pad capacitance found.
| var   typ   min   max
C_comp   1.59395pF  1.51855pF  1.66305pF
Vinl = 577.5mV
Vinh = 1.2675V
Vmeas = 900.0mV   | Reference voltage for timing measurements
Cref  = 15.0pF   | Timing specification test load capacitance value
Rref  = 1.0MOhm   | Timing specification test load resistance value
Vref  = 1.8V   | Timing specification test load voltage
[Model Spec]
| :
Vinl 630.00000mV 577.50000mV 682.50000mV
Vinh 1.17000V 1.07250V 1.26750V
| variable   typ   min   max
[Temperature Range] 25.0 125.0 -40.0
| variable   typ   min   max
[Voltage Range] 1.8V 1.65V 1.95V
| variable   typ   min   max
[POWER Clamp Reference] 1.8V 1.65V 1.95V
| variable   typ   min   max
[GND Clamp Reference] 0V 0V 0V
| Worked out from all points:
|   slope of the pulldown table from 0 to 0.27 V, typ, clamps not added: 182 ohm
|   slope of the pullup table from 0 to 0.27 V, typ, clamps not added: 186 ohm
|   GND clamp passes 1 mA (typ) near -0.44 V on its own axis
|   POWER clamp passes 1 mA (typ) near -0.55 V on its own axis
|   rising waveform, R_fixture 50.0, V_fixture 1.8V: 20-80 % time 156ps typ, 151ps min, 156ps max; typ from 1.54 V to 1.8 V
|   falling waveform, R_fixture 50.0, V_fixture 1.8V: 20-80 % time 5.37ns typ, 9.83ns min, 3.41ns max; typ from 1.8 V to 1.54 V
|   rising waveform, R_fixture 50.0, V_fixture 0V: 20-80 % time 4.41ns typ, 8.23ns min, 2.73ns max; typ from 0 V to 0.299 V
|   falling waveform, R_fixture 50.0, V_fixture 0V: 20-80 % time 155ps typ, 155ps min, 152ps max; typ from 0.299 V to 0 V
[POWER Clamp]
-1.8V     1.452A     1.584A     1.373A
-1.18V    398.2mA    529.9mA    318.8mA
-1.15V    347.2mA    478.9mA    267.8mA
-1.12V    296.2mA    427.9mA    216.8mA
-1.04V    160.2mA    291.9mA    80.8mA
-1V       92.7mA     223.9mA    36.91mA
-950mV    39.13mA    138.9mA    17.74mA
-890mV    15.29mA    63.28mA    11.49mA
-820mV    7.624mA    23.03mA    8.083mA
-710mV    3.879mA    5.678mA    4.143mA
-440mV    197.6uA    467.9uA    81.17uA
3.6V      0A         0A         0A
[GND Clamp]
-1.8V     -1.52A     -1.672A    -1.429A
-1.21V    -517.1mA   -668.6mA   -425.8mA
-1.12V    -364.1mA   -515.6mA   -272.8mA
-1.04V    -228.1mA   -379.6mA   -136.8mA
-990mV    -143.1mA   -294.6mA   -59.09mA
-960mV    -92.39mA   -243.6mA   -36.7mA
-930mV    -55.67mA   -192.6mA   -26.64mA
-870mV    -22.36mA   -96.03mA   -19.75mA
-810mV    -12.79mA   -41.19mA   -16.01mA
-700mV    -7.546mA   -8.795mA   -10.07mA
-450mV    -1.097mA   -1.052mA   -1.224mA
3.6V      62.08nA    1.045uA    237nA
| variable   typ   min   max
[Pullup Reference] 1.8V 1.65V 1.95V
| variable   typ   min   max
[Pulldown Reference] 0V 0V 0V
[Pullup]
-1.8V     4.41mA     2.94mA     6.183mA
-1.04V    4.41mA     2.94mA     6.183mA
-950mV    4.294mA    2.94mA     6.001mA
-740mV    3.73mA     2.538mA    5.273mA
-450mV    2.48mA     1.704mA    3.499mA
310mV     -1.659mA   -1.132mA   -2.373mA
650mV     -3.346mA   -2.25mA    -4.795mA
990mV     -4.741mA   -3.13mA    -6.742mA
1.24V     -5.476mA   -3.564mA   -7.703mA
1.65V     -6.156mA   -3.942mA   -8.536mA
2.17V     -6.503mA   -4.073mA   -8.984mA
3.6V      -6.503mA   -4.073mA   -9.046mA
[Pulldown]
-1.8V     -3.65mA    -2.54mA    -4.847mA
-970mV    -3.65mA    -2.54mA    -4.829mA
-780mV    -3.397mA   -2.377mA   -4.612mA
-610mV    -2.997mA   -2.05mA    -4.147mA
-370mV    -2.049mA   -1.385mA   -2.867mA
310mV     1.697mA    1.135mA    2.385mA
570mV     3.002mA    1.985mA    4.179mA
820mV     4.024mA    2.622mA    5.493mA
1.07V     4.706mA    3.022mA    6.281mA
1.33V     5.081mA    3.232mA    6.682mA
1.8V      5.337mA    3.377mA    6.955mA
3.6V      5.408mA    3.395mA    7.061mA
[Ramp]
dV/dt_r 179.15648mV/4.40908ns 113.77431mV/8.23474ns 250.98831mV/2.73242ns
dV/dt_f 157.0087mV/5.37213ns 98.14576mV/9.82807ns 206.41671mV/3.41041ns
R_load = 50.0
| Removed startup time: 0s 0s 0s  .
| Removed end time: 10.0ns.
[Rising Waveform]
R_fixture   = 50.0
V_fixture   = 1.8V
V_fixture_min = 1.65V
V_fixture_max = 1.95V
0s        1.538V     1.485V     1.606V
176ps     1.538V     1.485V     1.6V
228ps     1.532V     1.485V     1.736V
256ps     1.588V     1.485V     1.787V
368ps     1.726V     1.485V     1.886V
596ps     1.783V     1.476V     1.934V
744ps     1.791V     1.604V     1.942V
948ps     1.796V     1.639V     1.947V
1.458ns   1.799V     1.648V     1.949V
10ns      1.8V       1.65V      1.95V
| Removed startup time: 0s 0s 0s  .
| Removed end time: 34.993ns.
[Falling Waveform]
R_fixture   = 50.0
V_fixture   = 1.8V
V_fixture_min = 1.65V
V_fixture_max = 1.95V
0s        1.8V       1.65V      1.95V
189ps     1.798V     1.65V      1.963V
840ps     1.799V     1.652V     1.935V
2.66ns    1.743V     1.642V     1.778V
3.794ns   1.696V     1.632V     1.713V
5.306ns   1.644V     1.615V     1.666V
7.308ns   1.6V       1.589V     1.635V
11.23ns   1.561V     1.545V     1.614V
17.21ns   1.543V     1.509V     1.607V
34.99ns   1.538V     1.486V     1.606V
| Removed startup time: 0s 0s 0s  .
| Removed end time: 35.0ns.
[Rising Waveform]
R_fixture   = 50.0
V_fixture   = 0V
V_fixture_min = 0V
V_fixture_max = 0V
0s        697.3nV    1.445uV    2.102uV
693ps     -427.8uV   -2.667mV   1.465mV
1.239ns   4.661mV    -167.4uV   28.73mV
3.129ns   75mV       9.403mV    235mV
4.144ns   128.3mV    20.45mV    313.7mV
5.292ns   181mV      36.87mV    361.9mV
6.874ns   230.8mV    63.76mV    392.7mV
10.39ns   278mV      119.4mV    412.9mV
16.32ns   295.4mV    167.4mV    418mV
35ns      298.6mV    189.6mV    418.3mV
| Removed startup time: 0s 0s 0s  .
| Removed end time: 10.0ns.
[Falling Waveform]
R_fixture   = 50.0
V_fixture   = 0V
V_fixture_min = 0V
V_fixture_max = 0V
0s        298.6mV    190.3mV    418.3mV
166ps     298.1mV    190.3mV    427.1mV
216ps     311.1mV    190.3mV    265.6mV
248ps     239.6mV    190.3mV    194.6mV
366ps     81.22mV    190.3mV    71mV
598ps     14.87mV    205.4mV    13.08mV
718ps     7.154mV    70.48mV    5.408mV
902ps     2.694mV    17mV       1.436mV
1.328ns   349.6uV    2.127mV    220.7uV
10ns      12.81uV    21.05uV    8.784uV
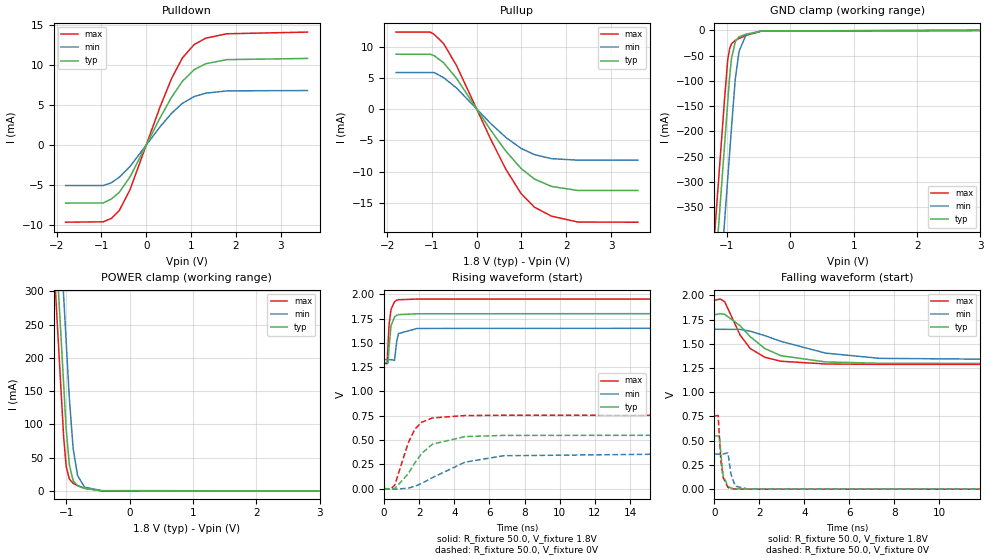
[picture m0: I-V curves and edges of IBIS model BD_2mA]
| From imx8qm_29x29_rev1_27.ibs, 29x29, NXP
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[Model] BD_2mA
Model_type I/O
Polarity   Non-Inverting
Enable   Active-Low
| C_comp min and max val. don't necessarily correlate with the min and max pvt
| but are the smallest and greatest pad capacitance found.
| var   typ   min   max
C_comp   1.59380pF  1.51845pF  1.66285pF
Vinl = 577.5mV
Vinh = 1.2675V
Vmeas = 900.0mV   | Reference voltage for timing measurements
Cref  = 15.0pF   | Timing specification test load capacitance value
Rref  = 1.0MOhm   | Timing specification test load resistance value
Vref  = 1.8V   | Timing specification test load voltage
[Model Spec]
| :
Vinl 630.00000mV 577.50000mV 682.50000mV
Vinh 1.17000V 1.07250V 1.26750V
| variable   typ   min   max
[Temperature Range] 25.0 125.0 -40.0
| variable   typ   min   max
[Voltage Range] 1.8V 1.65V 1.95V
| variable   typ   min   max
[POWER Clamp Reference] 1.8V 1.65V 1.95V
| variable   typ   min   max
[GND Clamp Reference] 0V 0V 0V
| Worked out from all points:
|   slope of the pulldown table from 0 to 0.27 V, typ, clamps not added: 91.1 ohm
|   slope of the pullup table from 0 to 0.27 V, typ, clamps not added: 93.2 ohm
|   GND clamp passes 1 mA (typ) near -0.44 V on its own axis
|   POWER clamp passes 1 mA (typ) near -0.55 V on its own axis
|   rising waveform, R_fixture 50.0, V_fixture 1.8V: 20-80 % time 156ps typ, 159ps min, 155ps max; typ from 1.3 V to 1.8 V
|   falling waveform, R_fixture 50.0, V_fixture 1.8V: 20-80 % time 1.63ns typ, 3.07ns min, 1.05ns max; typ from 1.8 V to 1.3 V
|   rising waveform, R_fixture 50.0, V_fixture 0V: 20-80 % time 1.38ns typ, 2.61ns min, 873ps max; typ from 0 V to 0.549 V
|   falling waveform, R_fixture 50.0, V_fixture 0V: 20-80 % time 155ps typ, 166ps min, 152ps max; typ from 0.549 V to 0 V
[POWER Clamp]
-1.8V     1.452A     1.584A     1.373A
-1.18V    398.2mA    529.9mA    318.8mA
-1.15V    347.2mA    478.9mA    267.8mA
-1.12V    296.2mA    427.9mA    216.8mA
-1.04V    160.2mA    291.9mA    80.78mA
-1V       92.69mA    223.9mA    36.89mA
-950mV    39.12mA    138.9mA    17.72mA
-890mV    15.28mA    63.28mA    11.47mA
-820mV    7.619mA    23.03mA    8.072mA
-710mV    3.877mA    5.679mA    4.137mA
-440mV    198.6uA    468.9uA    81.6uA
3.6V      0A         0A         0A
[GND Clamp]
-1.8V     -1.52A     -1.672A    -1.429A
-1.21V    -517.1mA   -668.6mA   -425.9mA
-1.12V    -364.1mA   -515.6mA   -272.9mA
-1.04V    -228.1mA   -379.6mA   -136.9mA
-990mV    -143.1mA   -294.6mA   -59.11mA
-960mV    -92.41mA   -243.6mA   -36.73mA
-930mV    -55.69mA   -192.6mA   -26.66mA
-870mV    -22.37mA   -96.04mA   -19.77mA
-810mV    -12.81mA   -41.2mA    -16.04mA
-700mV    -7.565mA   -8.808mA   -10.1mA
-450mV    -1.118mA   -1.064mA   -1.253mA
3.6V      32.66uA    16.11uA    55.52uA
| variable   typ   min   max
[Pullup Reference] 1.8V 1.65V 1.95V
| variable   typ   min   max
[Pulldown Reference] 0V 0V 0V
[Pullup]
-1.8V     8.81mA     5.88mA     12.36mA
-1.04V    8.81mA     5.88mA     12.36mA
-950mV    8.587mA    5.88mA     12mA
-740mV    7.46mA     5.075mA    10.54mA
-450mV    4.96mA     3.409mA    6.998mA
310mV     -3.319mA   -2.264mA   -4.747mA
650mV     -6.692mA   -4.502mA   -9.591mA
990mV     -9.482mA   -6.264mA   -13.49mA
1.29V     -11.18mA   -7.264mA   -15.69mA
1.67V     -12.36mA   -7.916mA   -17.12mA
2.26V     -13.01mA   -8.155mA   -18.07mA
3.6V      -13.01mA   -8.155mA   -18.09mA
[Pulldown]
-1.8V     -7.3mA     -5.1mA     -9.694mA
-960mV    -7.285mA   -5.1mA     -9.645mA
-780mV    -6.794mA   -4.754mA   -9.223mA
-600mV    -5.935mA   -4.055mA   -8.219mA
-360mV    -3.997mA   -2.702mA   -5.59mA
310mV     3.394mA    2.27mA     4.77mA
570mV     6.005mA    3.972mA    8.359mA
810mV     7.979mA    5.205mA    10.9mA
1.07V     9.412mA    6.047mA    12.56mA
1.33V     10.16mA    6.469mA    13.36mA
1.8V      10.67mA    6.759mA    13.91mA
3.6V      10.82mA    6.796mA    14.12mA
[Ramp]
dV/dt_r 329.64115mV/1.37527ns 217.55376mV/2.61367ns 452.75449mV/872.88242ps
dV/dt_f 302.28602mV/1.62513ns 193.73993mV/3.0701ns 397.13837mV/1.04893ns
R_load = 50.0
| Removed startup time: 0s 0s 0s  .
| Removed end time: 20.0ns.
[Rising Waveform]
R_fixture   = 50.0
V_fixture   = 1.8V
V_fixture_min = 1.65V
V_fixture_max = 1.95V
0s        1.296V     1.327V     1.288V
180ps     1.296V     1.327V     1.285V
232ps     1.293V     1.327V     1.481V
288ps     1.447V     1.327V     1.678V
400ps     1.674V     1.327V     1.842V
600ps     1.767V     1.319V     1.923V
724ps     1.783V     1.513V     1.938V
828ps     1.79V      1.595V     1.943V
1.892ns   1.799V     1.648V     1.95V
20ns      1.8V       1.65V      1.95V
| Removed startup time: 0s 0s 0s  .
| Removed end time: 20.0ns.
[Falling Waveform]
R_fixture   = 50.0
V_fixture   = 1.8V
V_fixture_min = 1.65V
V_fixture_max = 1.95V
0s        1.8V       1.65V      1.95V
264ps     1.811V     1.65V      1.962V
460ps     1.804V     1.65V      1.934V
1.148ns   1.686V     1.649V     1.589V
1.596ns   1.573V     1.63V      1.451V
2.248ns   1.451V     1.584V     1.361V
2.968ns   1.377V     1.525V     1.32V
4.952ns   1.313V     1.404V     1.292V
7.36ns    1.299V     1.35V      1.288V
20ns      1.296V     1.327V     1.288V
| Removed startup time: 0s 0s 0s  .
| Removed end time: 20.0ns.
[Rising Waveform]
R_fixture   = 50.0
V_fixture   = 0V
V_fixture_min = 0V
V_fixture_max = 0V
0s        559.4nV    1.201uV    1.593uV
404ps     -4.084mV   1.2uV      -2.996mV
616ps     958.9uV    -4.935mV   38.39mV
1.372ns   151.6mV    5.217mV    467.6mV
1.752ns   264.1mV    24.19mV    611.4mV
2.148ns   362.8mV    54.18mV    683.5mV
2.76ns    458.1mV    113.9mV    727.3mV
4.604ns   535.5mV    272.2mV    752.3mV
6.8ns     547.8mV    338.8mV    755mV
20ns      549.4mV    362.6mV    754.6mV
| Removed startup time: 0s 0s 0s  .
| Removed end time: 20.0ns.
[Falling Waveform]
R_fixture   = 50.0
V_fixture   = 0V
V_fixture_min = 0V
V_fixture_max = 0V
0s        549.1mV    362.5mV    754.2mV
168ps     548.7mV    362.5mV    760.4mV
224ps     552.5mV    362.5mV    535.6mV
284ps     377.2mV    362.5mV    300.7mV
388ps     144.3mV    362.5mV    122mV
604ps     28.73mV    375.1mV    17.76mV
736ps     11.71mV    156.9mV    5.648mV
932ps     3.284mV    30.69mV    1.649mV
1.48ns    416.5uV    2.569mV    267.1uV
20ns      653.1nV    1.384uV    1.671uV
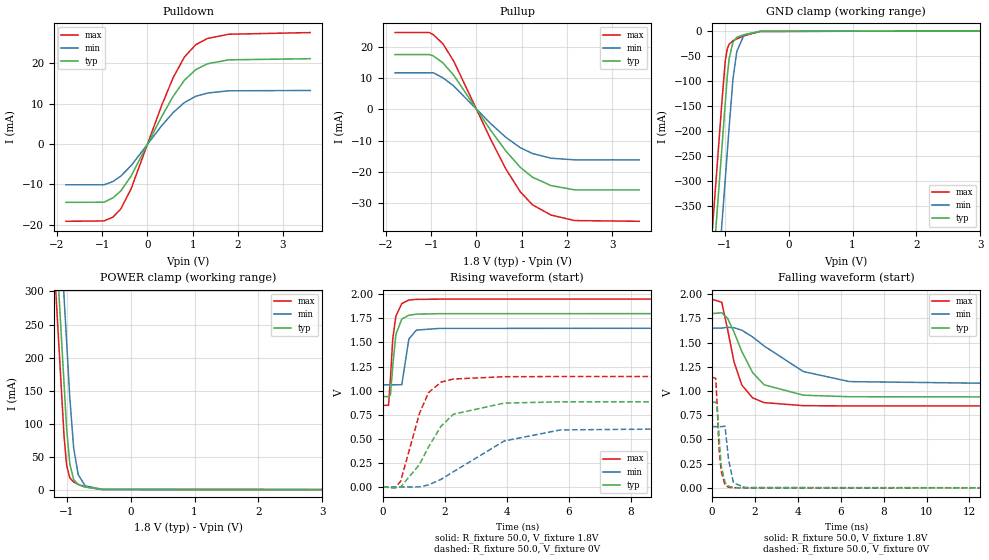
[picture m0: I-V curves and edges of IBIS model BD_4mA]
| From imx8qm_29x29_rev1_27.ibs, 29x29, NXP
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[Model] BD_4mA
Model_type I/O
Polarity   Non-Inverting
Enable   Active-Low
| C_comp min and max val. don't necessarily correlate with the min and max pvt
| but are the smallest and greatest pad capacitance found.
| var   typ   min   max
C_comp   1.59330pF  1.51815pF  1.66215pF
Vinl = 577.5mV
Vinh = 1.2675V
Vmeas = 900.0mV   | Reference voltage for timing measurements
Cref  = 15.0pF   | Timing specification test load capacitance value
Rref  = 1.0MOhm   | Timing specification test load resistance value
Vref  = 1.8V   | Timing specification test load voltage
[Model Spec]
| :
Vinl 630.00000mV 577.50000mV 682.50000mV
Vinh 1.17000V 1.07250V 1.26750V
| variable   typ   min   max
[Temperature Range] 25.0 125.0 -40.0
| variable   typ   min   max
[Voltage Range] 1.8V 1.65V 1.95V
| variable   typ   min   max
[POWER Clamp Reference] 1.8V 1.65V 1.95V
| variable   typ   min   max
[GND Clamp Reference] 0V 0V 0V
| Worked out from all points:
|   slope of the pulldown table from 0 to 0.27 V, typ, clamps not added: 46.1 ohm
|   slope of the pullup table from 0 to 0.27 V, typ, clamps not added: 46.8 ohm
|   GND clamp passes 1 mA (typ) near -0.44 V on its own axis
|   POWER clamp passes 1 mA (typ) near -0.55 V on its own axis
|   rising waveform, R_fixture 50.0, V_fixture 1.8V: 20-80 % time 159ps typ, 170ps min, 156ps max; typ from 0.939 V to 1.8 V
|   falling waveform, R_fixture 50.0, V_fixture 1.8V: 20-80 % time 1.19ns typ, 2.48ns min, 731ps max; typ from 1.8 V to 0.938 V
|   rising waveform, R_fixture 50.0, V_fixture 0V: 20-80 % time 1.01ns typ, 2.05ns min, 611ps max; typ from 0 V to 0.886 V
|   falling waveform, R_fixture 50.0, V_fixture 0V: 20-80 % time 172ps typ, 202ps min, 163ps max; typ from 0.886 V to 0 V
[POWER Clamp]
-1.8V     1.452A     1.584A     1.373A
-1.18V    398.2mA    529.9mA    318.8mA
-1.15V    347.2mA    478.9mA    267.8mA
-1.12V    296.2mA    427.9mA    216.8mA
-1.04V    160.2mA    291.9mA    80.78mA
-1V       92.69mA    223.9mA    36.89mA
-950mV    39.12mA    138.9mA    17.72mA
-890mV    15.28mA    63.28mA    11.47mA
-820mV    7.619mA    23.03mA    8.072mA
-710mV    3.877mA    5.679mA    4.137mA
-440mV    198.6uA    468.9uA    81.6uA
3.6V      0A         0A         0A
[GND Clamp]
-1.8V     -1.52A     -1.672A    -1.429A
-1.21V    -517.1mA   -668.6mA   -425.9mA
-1.12V    -364.1mA   -515.6mA   -272.9mA
-1.04V    -228.1mA   -379.6mA   -136.9mA
-990mV    -143.1mA   -294.6mA   -59.11mA
-960mV    -92.41mA   -243.6mA   -36.73mA
-930mV    -55.69mA   -192.6mA   -26.66mA
-870mV    -22.37mA   -96.04mA   -19.77mA
-810mV    -12.81mA   -41.2mA    -16.04mA
-700mV    -7.565mA   -8.808mA   -10.1mA
-450mV    -1.118mA   -1.064mA   -1.253mA
3.6V      32.66uA    16.11uA    55.52uA
| variable   typ   min   max
[Pullup Reference] 1.8V 1.65V 1.95V
| variable   typ   min   max
[Pulldown Reference] 0V 0V 0V
[Pullup]
-1.8V     17.55mA    11.7mA     24.59mA
-1.04V    17.55mA    11.7mA     24.59mA
-950mV    17.09mA    11.7mA     23.87mA
-740mV    14.85mA    10.1mA     20.98mA
-500mV    10.88mA    7.451mA    15.37mA
310mV     -6.602mA   -4.503mA   -9.442mA
650mV     -13.31mA   -8.947mA   -19.07mA
970mV     -18.56mA   -12.27mA   -26.4mA
1.24V     -21.73mA   -14.15mA   -30.57mA
1.65V     -24.41mA   -15.64mA   -33.84mA
2.17V     -25.77mA   -16.16mA   -35.6mA
3.6V      -25.77mA   -16.16mA   -35.84mA
[Pulldown]
-1.8V     -14.42mA   -10.07mA   -19.11mA
-960mV    -14.39mA   -10.07mA   -19.02mA
-760mV    -13.28mA   -9.263mA   -18.05mA
-590mV    -11.61mA   -7.92mA    -16.08mA
-360mV    -7.897mA   -5.333mA   -11.04mA
310mV     6.7mA      4.474mA    9.415mA
570mV     11.84mA    7.815mA    16.47mA
820mV     15.83mA    10.3mA     21.59mA
1.07V     18.45mA    11.84mA    24.62mA
1.33V     19.89mA    12.64mA    26.16mA
1.8V      20.86mA    13.2mA     27.2mA
3.6V      21.14mA    13.27mA    27.61mA
[Ramp]
dV/dt_r 531.6259mV/1.00633ns 379.58432mV/2.04743ns 687.97807mV/610.51835ps
dV/dt_f 516.91311mV/1.19205ns 353.54186mV/2.47949ns 662.09079mV/730.60653ps
R_load = 50.0
| Removed startup time: 0s 0s 0s  .
| Removed end time: 20.0ns.
[Rising Waveform]
R_fixture   = 50.0
V_fixture   = 1.8V
V_fixture_min = 1.65V
V_fixture_max = 1.95V
0s        938.7mV    1.061V     846.7mV
184ps     938.7mV    1.061V     848.5mV
244ps     954.6mV    1.061V     1.121V
320ps     1.255V     1.061V     1.537V
420ps     1.582V     1.061V     1.773V
612ps     1.743V     1.062V     1.904V
840ps     1.783V     1.536V     1.941V
1.084ns   1.794V     1.629V     1.947V
1.824ns   1.799V     1.646V     1.95V
20ns      1.8V       1.65V      1.95V
| Removed startup time: 0s 0s 0s  .
| Removed end time: 20.0ns.
[Falling Waveform]
R_fixture   = 50.0
V_fixture   = 1.8V
V_fixture_min = 1.65V
V_fixture_max = 1.95V
0s        1.8V       1.65V      1.95V
460ps     1.809V     1.65V      1.917V
724ps     1.755V     1.659V     1.646V
1.032ns   1.61V      1.654V     1.302V
1.396ns   1.409V     1.629V     1.062V
1.9ns     1.191V     1.559V     929.3mV
2.432ns   1.065V     1.466V     881mV
4.26ns    957.4mV    1.202V     849.4mV
6.404ns   941.6mV    1.098V     846.4mV
20ns      938.5mV    1.061V     846.5mV
| Removed startup time: 0s 0s 0s  .
| Removed end time: 20.0ns.
[Rising Waveform]
R_fixture   = 50.0
V_fixture   = 0V
V_fixture_min = 0V
V_fixture_max = 0V
0s        397.9nV    881.4nV    1.058uV
392ps     -8.294mV   882.5nV    -6.081mV
572ps     -509.3uV   1.094mV    58.26mV
1.184ns   234.4mV    1.938mV    764.5mV
1.472ns   414.5mV    22.13mV    979mV
1.88ns    632.4mV    79.52mV    1.089V
2.28ns    756.1mV    159.5mV    1.121V
3.92ns    871.4mV    478mV      1.145V
5.728ns   884.2mV    593mV      1.147V
20ns      886mV      632.6mV    1.147V
| Removed startup time: 0s 0s 0s  .
| Removed end time: 20.0ns.
[Falling Waveform]
R_fixture   = 50.0
V_fixture   = 0V
V_fixture_min = 0V
V_fixture_max = 0V
0s        885.8mV    632.5mV    1.146V
180ps     885mV      632.5mV    1.131V
244ps     851.8mV    632.5mV    869.5mV
332ps     537.4mV    632.5mV    412.4mV
432ps     230.1mV    632.5mV    173.2mV
612ps     57.11mV    636.9mV    28.64mV
780ps     16.44mV    288.8mV    5.805mV
1.008ns   3.467mV    50.53mV    1.313mV
1.564ns   522.1uV    3.784mV    307.5uV
20ns      467.8nV    1.017uV    1.112uV
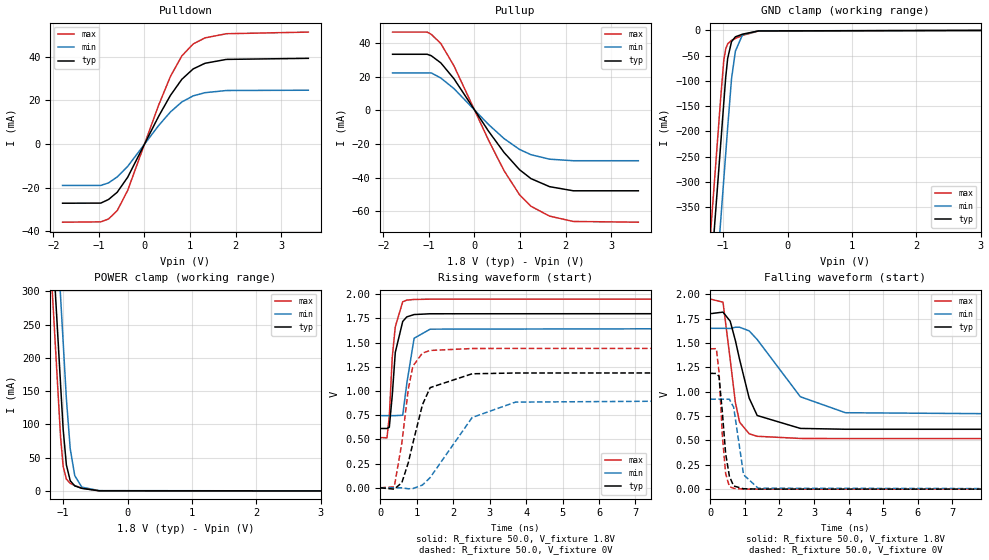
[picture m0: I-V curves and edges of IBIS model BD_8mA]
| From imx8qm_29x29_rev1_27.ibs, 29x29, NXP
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[Model] BD_8mA
Model_type I/O
Polarity   Non-Inverting
Enable   Active-Low
| C_comp min and max val. don't necessarily correlate with the min and max pvt
| but are the smallest and greatest pad capacitance found.
| var   typ   min   max
C_comp   1.59240pF  1.51775pF  1.66070pF
Vinl = 577.5mV
Vinh = 1.2675V
Vmeas = 900.0mV   | Reference voltage for timing measurements
Cref  = 15.0pF   | Timing specification test load capacitance value
Rref  = 1.0MOhm   | Timing specification test load resistance value
Vref  = 1.8V   | Timing specification test load voltage
[Model Spec]
| :
Vinl 630.00000mV 577.50000mV 682.50000mV
Vinh 1.17000V 1.07250V 1.26750V
| variable   typ   min   max
[Temperature Range] 25.0 125.0 -40.0
| variable   typ   min   max
[Voltage Range] 1.8V 1.65V 1.95V
| variable   typ   min   max
[POWER Clamp Reference] 1.8V 1.65V 1.95V
| variable   typ   min   max
[GND Clamp Reference] 0V 0V 0V
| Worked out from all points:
|   slope of the pulldown table from 0 to 0.27 V, typ, clamps not added: 24.4 ohm
|   slope of the pullup table from 0 to 0.27 V, typ, clamps not added: 24.8 ohm
|   GND clamp passes 1 mA (typ) near -0.44 V on its own axis
|   POWER clamp passes 1 mA (typ) near -0.55 V on its own axis
|   rising waveform, R_fixture 50.0, V_fixture 1.8V: 20-80 % time 161ps typ, 176ps min, 155ps max; typ from 0.613 V to 1.8 V
|   falling waveform, R_fixture 50.0, V_fixture 1.8V: 20-80 % time 509ps typ, 1.19ns min, 291ps max; typ from 1.8 V to 0.613 V
|   rising waveform, R_fixture 50.0, V_fixture 0V: 20-80 % time 492ps typ, 1.04ns min, 293ps max; typ from 0 V to 1.19 V
|   falling waveform, R_fixture 50.0, V_fixture 0V: 20-80 % time 175ps typ, 217ps min, 146ps max; typ from 1.19 V to 0 V
[POWER Clamp]
-1.8V     1.452A     1.584A     1.373A
-1.18V    398.2mA    529.9mA    318.8mA
-1.15V    347.2mA    478.9mA    267.8mA
-1.12V    296.2mA    427.9mA    216.8mA
-1.04V    160.2mA    291.9mA    80.78mA
-1V       92.69mA    223.9mA    36.89mA
-950mV    39.12mA    138.9mA    17.72mA
-890mV    15.28mA    63.28mA    11.47mA
-820mV    7.619mA    23.03mA    8.072mA
-710mV    3.877mA    5.679mA    4.137mA
-440mV    198.6uA    468.9uA    81.6uA
3.6V      0A         0A         0A
[GND Clamp]
-1.8V     -1.52A     -1.672A    -1.429A
-1.21V    -517.1mA   -668.6mA   -425.9mA
-1.12V    -364.1mA   -515.6mA   -272.9mA
-1.04V    -228.1mA   -379.6mA   -136.9mA
-990mV    -143.1mA   -294.6mA   -59.11mA
-960mV    -92.41mA   -243.6mA   -36.73mA
-930mV    -55.69mA   -192.6mA   -26.66mA
-870mV    -22.37mA   -96.04mA   -19.77mA
-810mV    -12.81mA   -41.2mA    -16.04mA
-700mV    -7.565mA   -8.808mA   -10.1mA
-450mV    -1.118mA   -1.064mA   -1.253mA
3.6V      32.66uA    16.11uA    55.52uA
| variable   typ   min   max
[Pullup Reference] 1.8V 1.65V 1.95V
| variable   typ   min   max
[Pulldown Reference] 0V 0V 0V
[Pullup]
-1.8V     33.19mA    22.15mA    46.34mA
-1.04V    33.19mA    22.15mA    46.34mA
-950mV    32.34mA    22.15mA    45.01mA
-740mV    28.09mA    19.12mA    39.58mA
-450mV    18.65mA    12.81mA    26.27mA
310mV     -12.45mA   -8.478mA   -17.81mA
650mV     -25.03mA   -16.79mA   -35.85mA
990mV     -35.24mA   -23.22mA   -50.07mA
1.24V     -40.5mA    -26.32mA   -56.89mA
1.65V     -45.28mA   -28.99mA   -62.74mA
2.17V     -47.72mA   -29.91mA   -65.91mA
3.6V      -47.72mA   -29.91mA   -66.34mA
[Pulldown]
-1.8V     -27.2mA    -19.03mA   -35.9mA
-960mV    -27.14mA   -19.03mA   -35.75mA
-790mV    -25.49mA   -17.87mA   -34.42mA
-600mV    -22.18mA   -15.14mA   -30.62mA
-370mV    -15.31mA   -10.32mA   -21.37mA
310mV     12.65mA    8.427mA    17.76mA
570mV     22.27mA    14.67mA    30.95mA
820mV     29.64mA    19.25mA    40.37mA
1.07V     34.42mA    22.05mA    45.88mA
1.33V     37mA       23.51mA    48.66mA
1.8V      38.78mA    24.51mA    50.56mA
3.6V      39.27mA    24.64mA    51.31mA
[Ramp]
dV/dt_r 712.64131mV/491.57941ps 553.99837mV/1.03985ns 863.81253mV/292.50934ps
dV/dt_f 712.20928mV/508.76258ps 542.7094mV/1.18835ns 858.71125mV/291.06301ps
R_load = 50.0
| Removed startup time: 0s 0s 0s  .
| Removed end time: 20.0ns.
[Rising Waveform]
R_fixture   = 50.0
V_fixture   = 1.8V
V_fixture_min = 1.65V
V_fixture_max = 1.95V
0s        613.1mV    745.6mV    518.9mV
184ps     613.1mV    745.6mV    516.5mV
248ps     625.6mV    745.6mV    741mV
328ps     952.8mV    745.6mV    1.345V
412ps     1.399V     745.6mV    1.664V
616ps     1.719V     749.5mV    1.922V
728ps     1.766V     1.08V      1.939V
928ps     1.79V      1.545V     1.946V
1.368ns   1.798V     1.639V     1.949V
20ns      1.8V       1.65V      1.95V
| Removed startup time: 0s 0s 0s  .
| Removed end time: 20.0ns.
[Falling Waveform]
R_fixture   = 50.0
V_fixture   = 1.8V
V_fixture_min = 1.65V
V_fixture_max = 1.95V
0s        1.8V       1.65V      1.95V
368ps     1.816V     1.65V      1.918V
576ps     1.723V     1.648V     1.33V
724ps     1.527V     1.661V     892.4mV
848ps     1.33V      1.661V     687.4mV
1.124ns   934.5mV    1.624V     568.5mV
1.356ns   755.7mV    1.535V     542.3mV
2.604ns   623.2mV    948mV      520.2mV
3.908ns   614.6mV    784.1mV    518.8mV
20ns      613mV      745.5mV    518.8mV
| Removed startup time: 0s 0s 0s  .
| Removed end time: 20.0ns.
[Rising Waveform]
R_fixture   = 50.0
V_fixture   = 0V
V_fixture_min = 0V
V_fixture_max = 0V
0s        252.2nV    558.9nV    624.1nV
384ps     -14.16mV   559.9nV    9.664mV
592ps     53.45mV    -483.8uV   463.9mV
768ps     258.8mV    -9.964mV   1.017V
892ps     456.9mV    -8.19mV    1.255V
1.156ns   857.6mV    28.5mV     1.392V
1.368ns   1.035V     105.7mV    1.419V
2.52ns    1.178V     726.4mV    1.439V
3.708ns   1.186V     885.3mV    1.44V
20ns      1.188V     923.3mV    1.44V
| Removed startup time: 0s 0s 0s  .
| Removed end time: 20.0ns.
[Falling Waveform]
R_fixture   = 50.0
V_fixture   = 0V
V_fixture_min = 0V
V_fixture_max = 0V
0s        1.188V     923.2mV    1.44V
176ps     1.187V     923.2mV    1.441V
252ps     1.157V     923.2mV    1.204V
348ps     793.5mV    923.2mV    554.2mV
444ps     365.5mV    923.2mV    161mV
552ps     133.3mV    922.7mV    27.43mV
676ps     32.45mV    840.7mV    8.316mV
964ps     4.192mV    147.5mV    1.226mV
1.384ns   812.5uV    9.624mV    329.3uV
20ns      300.3nV    634.6nV    659.3nV
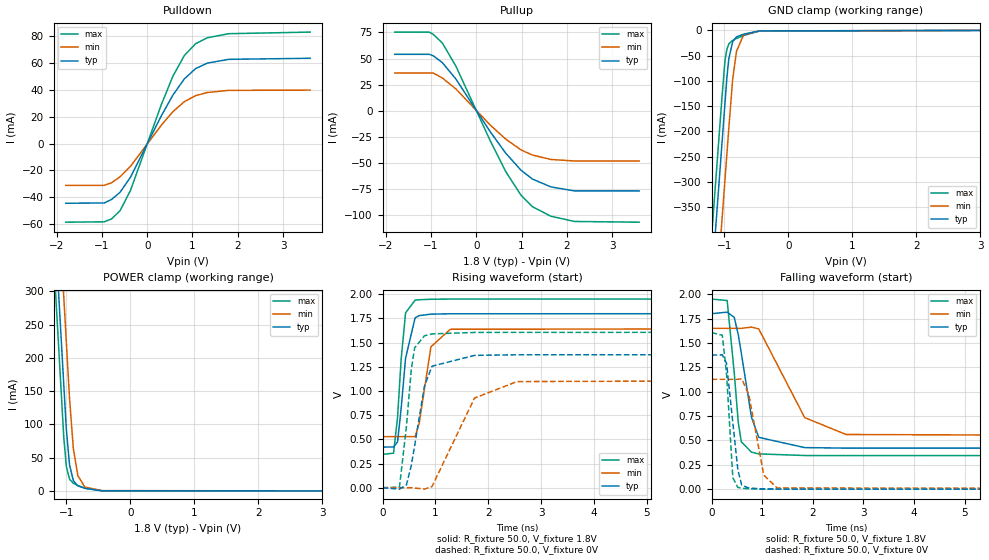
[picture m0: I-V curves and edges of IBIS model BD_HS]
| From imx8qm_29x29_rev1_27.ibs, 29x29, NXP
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[Model] BD_HS
Model_type I/O
Polarity   Non-Inverting
Enable   Active-Low
| C_comp min and max val. don't necessarily correlate with the min and max pvt
| but are the smallest and greatest pad capacitance found.
| var   typ   min   max
C_comp   1.59110pF  1.51705pF  1.65860pF
Vinl = 577.5mV
Vinh = 1.2675V
Vmeas = 900.0mV   | Reference voltage for timing measurements
Cref  = 15.0pF   | Timing specification test load capacitance value
Rref  = 1.0MOhm   | Timing specification test load resistance value
Vref  = 1.8V   | Timing specification test load voltage
[Model Spec]
| :
Vinl 630.00000mV 577.50000mV 682.50000mV
Vinh 1.17000V 1.07250V 1.26750V
| variable   typ   min   max
[Temperature Range] 25.0 125.0 -40.0
| variable   typ   min   max
[Voltage Range] 1.8V 1.65V 1.95V
| variable   typ   min   max
[POWER Clamp Reference] 1.8V 1.65V 1.95V
| variable   typ   min   max
[GND Clamp Reference] 0V 0V 0V
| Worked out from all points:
|   slope of the pulldown table from 0 to 0.27 V, typ, clamps not added: 15 ohm
|   slope of the pullup table from 0 to 0.27 V, typ, clamps not added: 15.3 ohm
|   GND clamp passes 1 mA (typ) near -0.44 V on its own axis
|   POWER clamp passes 1 mA (typ) near -0.55 V on its own axis
|   rising waveform, R_fixture 50.0, V_fixture 1.8V: 20-80 % time 153ps typ, 181ps min, 122ps max; typ from 0.42 V to 1.8 V
|   falling waveform, R_fixture 50.0, V_fixture 1.8V: 20-80 % time 258ps typ, 617ps min, 147ps max; typ from 1.8 V to 0.42 V
|   rising waveform, R_fixture 50.0, V_fixture 0V: 20-80 % time 255ps typ, 535ps min, 153ps max; typ from 0 V to 1.38 V
|   falling waveform, R_fixture 50.0, V_fixture 0V: 20-80 % time 151ps typ, 225ps min, 104ps max; typ from 1.38 V to 0 V
[POWER Clamp]
-1.8V     1.452A     1.584A     1.373A
-1.18V    398.2mA    529.9mA    318.8mA
-1.15V    347.2mA    478.9mA    267.8mA
-1.12V    296.2mA    427.9mA    216.8mA
-1.04V    160.2mA    291.9mA    80.78mA
-1V       92.69mA    223.9mA    36.89mA
-950mV    39.12mA    138.9mA    17.72mA
-890mV    15.28mA    63.28mA    11.47mA
-820mV    7.619mA    23.03mA    8.072mA
-710mV    3.877mA    5.679mA    4.137mA
-440mV    198.6uA    468.9uA    81.6uA
3.6V      0A         0A         0A
[GND Clamp]
-1.8V     -1.52A     -1.672A    -1.429A
-1.21V    -517.1mA   -668.6mA   -425.9mA
-1.12V    -364.1mA   -515.6mA   -272.9mA
-1.04V    -228.1mA   -379.6mA   -136.9mA
-990mV    -143.1mA   -294.6mA   -59.11mA
-960mV    -92.41mA   -243.6mA   -36.73mA
-930mV    -55.69mA   -192.6mA   -26.66mA
-870mV    -22.37mA   -96.04mA   -19.77mA
-810mV    -12.81mA   -41.2mA    -16.04mA
-700mV    -7.565mA   -8.808mA   -10.1mA
-450mV    -1.118mA   -1.064mA   -1.253mA
3.6V      32.66uA    16.11uA    55.52uA
| variable   typ   min   max
[Pullup Reference] 1.8V 1.65V 1.95V
| variable   typ   min   max
[Pulldown Reference] 0V 0V 0V
[Pullup]
-1.8V     54.04mA    36.09mA    75.35mA
-1.04V    54.04mA    36.09mA    75.35mA
-950mV    52.66mA    36.09mA    73.2mA
-750mV    46.15mA    31.42mA    64.95mA
-450mV    30.36mA    20.85mA    42.74mA
310mV     -20.25mA   -13.77mA   -28.95mA
650mV     -40.65mA   -27.25mA   -58.24mA
990mV     -57.13mA   -37.59mA   -81.13mA
1.24V     -65.51mA   -42.53mA   -92mA
1.65V     -73.07mA   -46.76mA   -101.2mA
2.17V     -76.93mA   -48.22mA   -106.2mA
3.6V      -76.93mA   -48.22mA   -106.9mA
[Pulldown]
-1.8V     -44.45mA   -31.1mA    -58.57mA
-950mV    -44.23mA   -31.1mA    -58.28mA
-790mV    -41.67mA   -29.2mA    -56.2mA
-600mV    -36.25mA   -24.73mA   -50.01mA
-370mV    -25.01mA   -16.86mA   -34.91mA
310mV     20.65mA    13.75mA    29mA
570mV     36.35mA    23.92mA    50.5mA
820mV     48.3mA     31.33mA    65.74mA
1.07V     55.97mA    35.81mA    74.56mA
1.33V     60.08mA    38.14mA    78.98mA
1.8V      62.88mA    39.74mA    82mA
3.6V      63.67mA    39.94mA    83.2mA
[Ramp]
dV/dt_r 824.75504mV/254.74451ps 675.95236mV/534.60427ps 963.76588mV/152.83342ps
dV/dt_f 828.07946mV/258.13469ps 673.19306mV/616.51378ps 963.3159mV/147.46457ps
R_load = 50.0
| Removed startup time: 0s 0s 0s  .
| Removed end time: 20.0ns.
[Rising Waveform]
R_fixture   = 50.0
V_fixture   = 1.8V
V_fixture_min = 1.65V
V_fixture_max = 1.95V
0s        419.9mV    528.1mV    344.5mV
208ps     420.7mV    528.1mV    357.1mV
284ps     474.5mV    528.1mV    727.2mV
352ps     818.9mV    528.1mV    1.327V
436ps     1.34V      528.1mV    1.808V
616ps     1.755V     528mV      1.939V
692ps     1.779V     660.9mV    1.943V
916ps     1.794V     1.457V     1.948V
1.284ns   1.798V     1.638V     1.95V
20ns      1.8V       1.65V      1.95V
| Removed startup time: 0s 0s 0s  .
| Removed end time: 20.0ns.
[Falling Waveform]
R_fixture   = 50.0
V_fixture   = 1.8V
V_fixture_min = 1.65V
V_fixture_max = 1.95V
0s        1.8V       1.65V      1.95V
308ps     1.816V     1.65V      1.935V
448ps     1.762V     1.65V      1.194V
528ps     1.583V     1.65V      681.5mV
588ps     1.393V     1.65V      485.5mV
788ps     738.6mV    1.662V     379.6mV
932ps     531.7mV    1.644V     361.8mV
1.84ns    426.3mV    733.9mV    345.3mV
2.656ns   421mV      560.9mV    344.5mV
20ns      419.9mV    528mV      344.5mV
| Removed startup time: 0s 0s 0s  .
| Removed end time: 20.0ns.
[Rising Waveform]
R_fixture   = 50.0
V_fixture   = 0V
V_fixture_min = 0V
V_fixture_max = 0V
0s        158.6nV    329.9nV    366.9nV
320ps     -15.03mV   334nV      5.956mV
452ps     29.62mV    683.2nV    632.7mV
544ps     229.4mV    36.09uV    1.225V
608ps     436.2mV    -3.367mV   1.447V
792ps     1.049V     -13.86mV   1.57V
936ps     1.256V     12.28mV    1.59V
1.74ns    1.368V     926.6mV    1.605V
2.544ns   1.374V     1.097V     1.606V
20ns      1.375V     1.127V     1.606V
| Removed startup time: 0s 0s 0s  .
| Removed end time: 20.0ns.
[Falling Waveform]
R_fixture   = 50.0
V_fixture   = 0V
V_fixture_min = 0V
V_fixture_max = 0V
0s        1.375V     1.127V     1.606V
212ps     1.378V     1.127V     1.579V
296ps     1.292V     1.127V     1.181V
420ps     682.5mV    1.127V     117.7mV
520ps     195.9mV    1.127V     17.57mV
596ps     41.12mV    1.132V     10.05mV
736ps     11.68mV    969.5mV    3.456mV
1.032ns   2.326mV    143.1mV    664uV
1.296ns   825.8uV    12.47mV    250.9uV
20ns      192.5nV    385.5nV    390.6nV
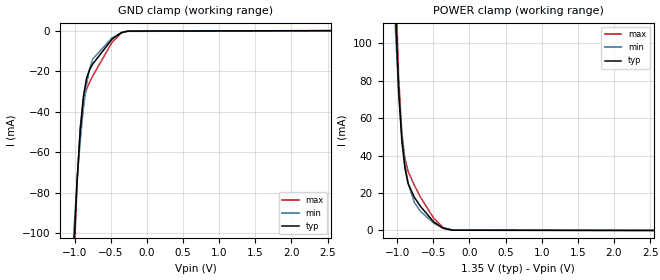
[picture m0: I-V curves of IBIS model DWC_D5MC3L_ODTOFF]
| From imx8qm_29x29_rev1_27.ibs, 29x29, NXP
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[Model] DWC_D5MC3L_ODTOFF
Model_type   Input
Polarity   Non-Inverting
Enable   Active-High
C_comp   1.262pF   1.180pF   1.365pF
C_comp_power_clamp   279.441fF   258.852fF   306.885fF
C_comp_gnd_clamp 973.651fF   908.565fF   1.053pF
Vinh = 800.000mV
Vinl = 550.000mV
[Model Spec]
D_overshoot_ampl_h 0.4 NA   NA
D_overshoot_ampl_l 0.4 NA   NA
D_overshoot_area_l 100.000p NA   NA
D_overshoot_area_h 100.000p NA   NA
[Receiver Thresholds]
Vth = 675.000mV
Vth_min = 661.500mV
Vth_max = 688.500mV
Vinh_ac = 125.000mV
Vinh_dc = 90.000mV
Vinl_ac = -125.000mV
Vinl_dc = -90.000mV
Tslew_ac = 5.000ns
Threshold_sensitivity = 0.5
Reference_supply Power_clamp_ref
[Temperature Range]   25.000   125.000   -40.000
[Voltage Range]   1.350V   1.283V   1.450V
[GND Clamp Reference]   0.00V   0.00V   0.00V
[C Comp Corner]
| variable   typ   min   max
C_comp 1.262pF   1.365pF   1.180pF
C_comp_pullup 279.441fF   306.885fF   258.852fF
C_comp_pulldown 973.651fF   1.053pF   908.565fF
[POWER Clamp Reference]   1.350V   1.283V   1.450V
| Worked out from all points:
|   GND clamp passes 1 mA (typ) near -0.36 V on its own axis
|   POWER clamp passes 1 mA (typ) near -0.36 V on its own axis
[GND Clamp]
-1.318V   -593.4mA   -427mA     -758.7mA
-1.011V   -108.7mA   -99.8mA    -118.2mA
-966.7mV  -74.7mA    -74.6mA    -75.87mA
-922.7mV  -49.41mA   -54.3mA    -47.9mA
-878.8mV  -32.42mA   -38.21mA   -34.12mA
-834.8mV  -23.33mA   -26.23mA   -28.72mA
-790.9mV  -19.01mA   -18.35mA   -25.26mA
-747mV    -16.25mA   -13.76mA   -22.11mA
-483.3mV  -4.093mA   -3.434mA   -5.633mA
-351.5mV  -766.8uA   -911.3uA   -894.7uA
-263.6mV  -79.41uA   -192.1uA   -51.43uA
2.68V     154.9uA    127.3uA    193.1uA
[Power Clamp]
-1.33V    727.8mA    510.6mA    954.1mA
-1.023V   119.4mA    107.4mA    137.5mA
-978.8mV  74.87mA    74.2mA     82.23mA
-934.8mV  47.95mA    50.66mA    52.21mA
-890.9mV  32.9mA     35.12mA    38.1mA
-847mV    24.9mA     25.11mA    31.53mA
-759.1mV  17.5mA     14.71mA    23.9mA
-671.2mV  12.54mA    9.915mA    17.38mA
-495.5mV  4.603mA    3.922mA    6.563mA
-363.6mV  1.088mA    1.21mA     1.541mA
-231.8mV  46.56uA    141.4uA    53.69uA
2.668V    -76.24uA   -66.58uA   -87.76uA
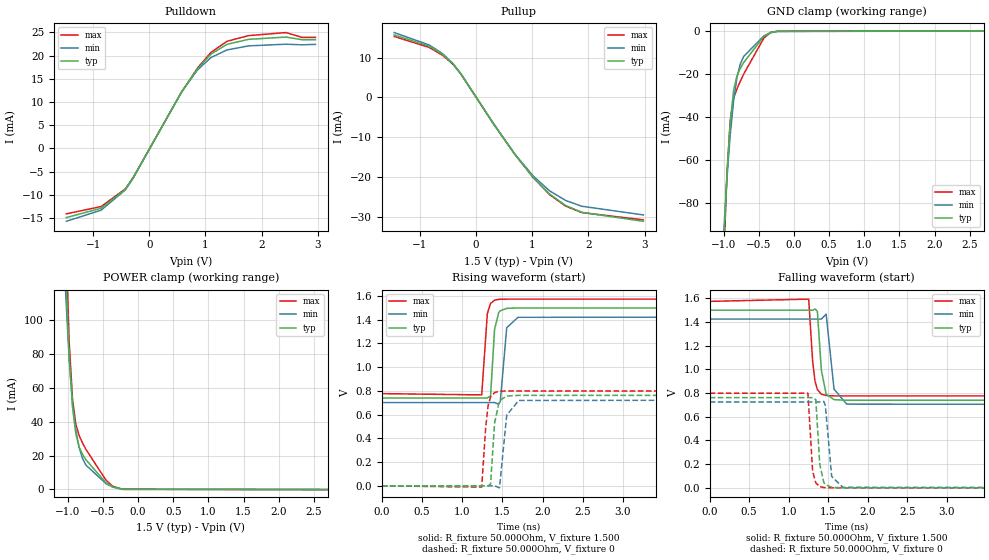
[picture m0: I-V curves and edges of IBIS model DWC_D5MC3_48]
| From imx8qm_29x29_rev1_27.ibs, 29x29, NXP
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[Model] DWC_D5MC3_48
Model_type   I/O
Polarity   Non-Inverting
Enable   Active-High
C_comp   1.260pF   1.180pF   1.362pF
C_comp_pullup   275.501fF   256.643fF   303.068fF
C_comp_pulldown 982.421fF   918.243fF   1.058pF
Vinh = 875.000mV
Vinl = 625.000mV
Vmeas = 750.000mV
Vref = 750.000mV
Rref = 50Ohms
Cref = 0pF
[Model Spec]
Vinh   875.000mV   837.500mV   912.500mV
Vinl   625.000mV   587.500mV   662.500mV
Vmeas   750.000mV   712.500mV   787.500mV
Vref   750.000mV   712.500mV   787.500mV
D_overshoot_ampl_h 0.4 NA   NA
D_overshoot_ampl_l 0.4 NA   NA
D_overshoot_area_l 100.000p NA   NA
D_overshoot_area_h 100.000p NA   NA
[Receiver Thresholds]
Vth = 750.000mV
Vth_min = 735.000mV
Vth_max = 765.000mV
Vinh_ac = 125.000mV
Vinh_dc = 100.000mV
Vinl_ac = -125.000mV
Vinl_dc = -100.000mV
Tslew_ac = 5.000ns
Threshold_sensitivity = 0.5
Reference_supply Pullup_ref
[Temperature Range]   25.000   125.000   -40.000
[Voltage Range]   1.500V   1.425V   1.575V
[GND Clamp Reference]   0.00V   0.00V   0.00V
[C Comp Corner]
| variable   typ   min   max
C_comp 1.260pF   1.362pF   1.180pF
C_comp_pullup 275.501fF   303.068fF   256.643fF
C_comp_pulldown 982.421fF   1.058pF   918.243fF
[Pulldown Reference]   0.00V   0.00V   0.00V
[POWER Clamp Reference]   1.500V   1.425V   1.575V
[Pullup Reference]   1.500V   1.425V   1.575V
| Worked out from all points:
|   slope of the pulldown table from 0 to 0.225 V, typ, clamps not added: 45.8 ohm
|   slope of the pullup table from 0 to 0.225 V, typ, clamps not added: 46.4 ohm
|   GND clamp passes 1 mA (typ) near -0.36 V on its own axis
|   POWER clamp passes 1 mA (typ) near -0.34 V on its own axis
|   rising waveform, R_fixture 50.000Ohm, V_fixture 1.500: 20-80 % time 43.7ps typ, 49ps min, 40.9ps max; typ from 0.739 V to 1.5 V
|   rising waveform, R_fixture 50.000Ohm, V_fixture 0: 20-80 % time 51.2ps typ, 58.8ps min, 48ps max; typ from 0 V to 0.761 V
|   falling waveform, R_fixture 50.000Ohm, V_fixture 1.500: 20-80 % time 55.3ps typ, 62.1ps min, 52ps max; typ from 1.5 V to 0.739 V
|   falling waveform, R_fixture 50.000Ohm, V_fixture 0: 20-80 % time 44.9ps typ, 51ps min, 41.5ps max; typ from 0.761 V to 0 V
[GND Clamp]
-1.48V    -918.2mA   -652.1mA   -1.176A
-1.002V   -101.7mA   -94.77mA   -109.1mA
-954.5mV  -67.02mA   -68.69mA   -66.81mA
-906.8mV  -42.34mA   -48.1mA    -41.42mA
-859.1mV  -27.51mA   -32.38mA   -31.19mA
-811.4mV  -20.68mA   -21.56mA   -26.8mA
-763.6mV  -17.22mA   -15.21mA   -23.29mA
-715.9mV  -14.57mA   -11.71mA   -19.94mA
-429.5mV  -2.409mA   -2.204mA   -3.222mA
-334.1mV  -538.8uA   -707.4uA   -589.3uA
-238.6mV  -34.43uA   -108.5uA   -17.28uA
2.959V    171.1uA    140uA      213.2uA
[Power Clamp]
-1.459V   1.027A     711.2mA    1.35A
-1.03V    129.3mA    114.5mA    151.4mA
-981.8mV  78.48mA    77.22mA    87.29mA
-934.1mV  48.73mA    51.4mA     53.47mA
-886.4mV  32.89mA    34.83mA    38.4mA
-838.6mV  24.91mA    24.53mA    31.7mA
-790.9mV  20.61mA    18.26mA    27.45mA
-743.2mV  17.51mA    14.37mA    23.68mA
-456.8mV  3.892mA    3.387mA    5.399mA
-361.4mV  1.383mA    1.455mA    1.887mA
-218.2mV  56.59uA    161.1uA    60.54uA
2.979V    -85.62uA   -74.93uA   -101.2uA
[Pulldown]
-1.48V    -14.9mA    -15.7mA    -14.1mA
-859.1mV  -12.89mA   -13.3mA    -12.52mA
-429.5mV  -8.843mA   -8.963mA   -8.734mA
-286.4mV  -6.277mA   -6.383mA   -6.232mA
572.7mV   12.1mA     12.15mA    12.11mA
859.1mV   17.17mA    16.91mA    17.32mA
1.098V    20.3mA     19.57mA    20.68mA
1.384V    22.41mA    21.2mA     23.06mA
1.766V    23.48mA    22.07mA    24.28mA
2.434V    23.97mA    22.44mA    24.94mA
2.72V     23.4mA     22.3mA     23.9mA
2.959V    23.4mA     22.4mA     23.9mA
[Pullup]
-1.459V   15.7mA     16.29mA    15.31mA
-838.6mV  12.88mA    13.19mA    12.56mA
-600mV    10.84mA    11.02mA    10.6mA
-409.1mV  8.392mA    8.464mA    8.261mA
-265.9mV  5.779mA    5.843mA    5.724mA
306.8mV   -6.586mA   -6.661mA   -6.565mA
688.6mV   -14.3mA    -14.28mA   -14.32mA
1.023V    -20.24mA   -19.89mA   -20.32mA
1.309V    -24.34mA   -23.54mA   -24.49mA
1.595V    -27.23mA   -25.96mA   -27.38mA
1.882V    -28.94mA   -27.41mA   -29.01mA
2.979V    -31.2mA    -29.6mA    -30.84mA
[Ramp]
R_load=50.000Ohm
dV/dt_r   455.970mV/48.000ps  434.005mV/54.000ps  478.080mV/45.000ps
dV/dt_f   455.940mV/50.500ps  434.005mV/56.500ps  478.080mV/47.000ps
[Rising waveform]
R_fixture=50.000Ohm
V_fixture=1.500
V_fixture_min=1.425
V_fixture_max=1.575
0s        739.1mV    700.9mV    776.5mV
1.243ns   739.1mV    700.9mV    765.7mV
1.313ns   740.1mV    700.9mV    1.451V
1.353ns   756.7mV    700.8mV    1.536V
1.403ns   1.317V     701.8mV    1.563V
1.454ns   1.458V     686.9mV    1.57V
1.474ns   1.474V     710.8mV    1.571V
1.554ns   1.494V     1.331V     1.572V
1.694ns   1.498V     1.419V     1.572V
10ns      1.498V     1.423V     1.572V
[Rising waveform]
R_fixture=50.000Ohm
V_fixture=0
0s        902nV      15.77uV    110.2nV
1.243ns   21.14uV    15.24uV    -10.72mV
1.293ns   98.32uV    22.33uV    496.2mV
1.323ns   280.1uV    32.64uV    677.3mV
1.353ns   15.29mV    -52.18uV   747.6mV
1.403ns   529mV      710.2uV    785.5mV
1.464ns   718.3mV    -17.01mV   796.2mV
1.554ns   756.1mV    595.6mV    798.8mV
1.704ns   761.6mV    719mV      799.1mV
10ns      761.1mV    724.2mV    797.8mV
[Falling waveform]
R_fixture=50.000Ohm
V_fixture=1.500
V_fixture_min=1.425
V_fixture_max=1.575
0s        1.498V     1.423V     1.572V
1.253ns   1.498V     1.423V     1.591V
1.303ns   1.497V     1.423V     1.066V
1.333ns   1.508V     1.423V     898.8mV
1.363ns   1.488V     1.423V     829.2mV
1.413ns   992.9mV    1.423V     789.9mV
1.474ns   789.7mV    1.464V     778.3mV
1.574ns   743.8mV    831.5mV    775.3mV
1.734ns   738.3mV    705.7mV    775mV
10ns      738.9mV    700.8mV    776.2mV
[Falling waveform]
R_fixture=50.000Ohm
V_fixture=0
0s        760.8mV    724.1mV    797.5mV
1.243ns   760.8mV    724.1mV    797.6mV
1.303ns   760.5mV    724.1mV    140.2mV
1.343ns   743mV      724.1mV    41.95mV
1.393ns   199.4mV    723.7mV    10.9mV
1.444ns   45.29mV    729.2mV    2.997mV
1.464ns   27.35mV    694mV      1.825mV
1.544ns   4.72mV     96.12mV    260uV
1.684ns   301.4uV    5.116mV    15.87uV
10ns      1.052uV    15.88uV    185.2nV
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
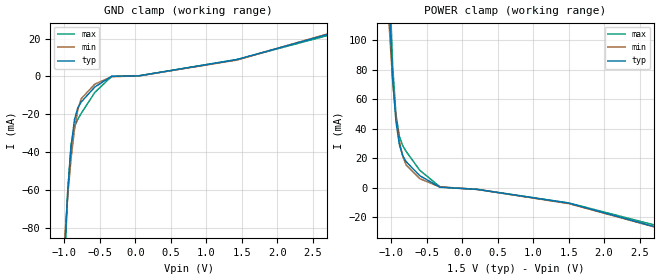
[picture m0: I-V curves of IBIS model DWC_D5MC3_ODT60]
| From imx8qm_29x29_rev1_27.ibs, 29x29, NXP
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[Model] DWC_D5MC3_ODT60
Model_type   Input
Polarity   Non-Inverting
Enable   Active-High
C_comp   1.445pF   1.389pF   1.452pF
C_comp_power_clamp   469.673fF   403.915fF   473.652fF
C_comp_gnd_clamp 972.887fF   910.007fF   1.047pF
Vinh = 875.000mV
Vinl = 625.000mV
[Model Spec]
D_overshoot_ampl_h 0.4 NA   NA
D_overshoot_ampl_l 0.4 NA   NA
D_overshoot_area_l 100.000p NA   NA
D_overshoot_area_h 100.000p NA   NA
[Receiver Thresholds]
Vth = 750.000mV
Vth_min = 735.000mV
Vth_max = 765.000mV
Vinh_ac = 125.000mV
Vinh_dc = 100.000mV
Vinl_ac = -125.000mV
Vinl_dc = -100.000mV
Tslew_ac = 5.000ns
Threshold_sensitivity = 0.5
Reference_supply Power_clamp_ref
[Temperature Range]   25.000   125.000   -40.000
[Voltage Range]   1.500V   1.425V   1.575V
[GND Clamp Reference]   0.00V   0.00V   0.00V
[C Comp Corner]
| variable   typ   min   max
C_comp 1.445pF   1.452pF   1.389pF
C_comp_pullup 469.673fF   403.915fF   473.652fF
C_comp_pulldown 972.887fF   1.047pF   910.007fF
[POWER Clamp Reference]   1.500V   1.425V   1.575V
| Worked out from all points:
|   GND clamp passes 1 mA (typ) near -0.41 V on its own axis
|   POWER clamp passes 1 mA (typ) near -0.37 V on its own axis
[GND Clamp]
-1.48V    -906.7mA   -641.1mA   -1.165A
-1.002V   -95.63mA   -88.94mA   -103mA
-954.5mV  -61.44mA   -63.37mA   -61.18mA
-906.8mV  -37.26mA   -43.26mA   -36.29mA
-859.1mV  -22.91mA   -28.01mA   -26.54mA
-811.4mV  -16.55mA   -17.65mA   -22.61mA
-763.6mV  -13.54mA   -11.74mA   -19.55mA
-572.7mV  -5.625mA   -4.104mA   -8.506mA
-334.1mV  51.16uA    -145.3uA   25.45uA
47.73mV   282.5uA    280.9uA    271.5uA
1.432V    8.881mA    8.659mA    8.927mA
2.959V    24.81mA    25.15mA    24.06mA
[Power Clamp]
-1.459V   1.018A     702.4mA    1.341A
-1.03V    124.3mA    109.6mA    146.5mA
-981.8mV  73.98mA    72.73mA    82.88mA
-934.1mV  44.64mA    47.32mA    49.47mA
-886.4mV  29.19mA    31.14mA    34.79mA
-838.6mV  21.59mA    21.22mA    28.45mA
-790.9mV  17.64mA    15.31mA    24.56mA
-600mV    8.146mA    6.12mA     11.84mA
-313.6mV  258.3uA    405.9uA    517.5uA
211.4mV   -1.184mA   -1.192mA   -1.163mA
1.5V      -10.52mA   -10.81mA   -10.37mA
2.979V    -30.08mA   -30.19mA   -28.67mA
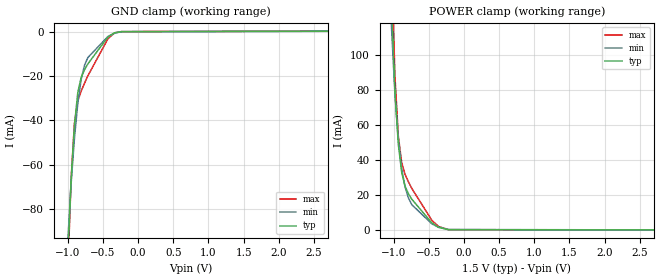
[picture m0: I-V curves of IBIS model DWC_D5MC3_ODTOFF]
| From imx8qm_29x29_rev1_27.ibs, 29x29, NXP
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[Model] DWC_D5MC3_ODTOFF
Model_type   Input
Polarity   Non-Inverting
Enable   Active-High
C_comp   1.260pF   1.180pF   1.362pF
C_comp_power_clamp   275.501fF   256.643fF   303.068fF
C_comp_gnd_clamp 982.421fF   918.243fF   1.058pF
Vinh = 875.000mV
Vinl = 625.000mV
[Model Spec]
D_overshoot_ampl_h 0.4 NA   NA
D_overshoot_ampl_l 0.4 NA   NA
D_overshoot_area_l 100.000p NA   NA
D_overshoot_area_h 100.000p NA   NA
[Receiver Thresholds]
Vth = 750.000mV
Vth_min = 735.000mV
Vth_max = 765.000mV
Vinh_ac = 125.000mV
Vinh_dc = 100.000mV
Vinl_ac = -125.000mV
Vinl_dc = -100.000mV
Tslew_ac = 5.000ns
Threshold_sensitivity = 0.5
Reference_supply Power_clamp_ref
[Temperature Range]   25.000   125.000   -40.000
[Voltage Range]   1.500V   1.425V   1.575V
[GND Clamp Reference]   0.00V   0.00V   0.00V
[C Comp Corner]
| variable   typ   min   max
C_comp 1.260pF   1.362pF   1.180pF
C_comp_pullup 275.501fF   303.068fF   256.643fF
C_comp_pulldown 982.421fF   1.058pF   918.243fF
[POWER Clamp Reference]   1.500V   1.425V   1.575V
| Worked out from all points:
|   GND clamp passes 1 mA (typ) near -0.36 V on its own axis
|   POWER clamp passes 1 mA (typ) near -0.34 V on its own axis
[GND Clamp]
-1.48V    -918.2mA   -652.1mA   -1.176A
-1.002V   -101.7mA   -94.77mA   -109.1mA
-954.5mV  -67.02mA   -68.69mA   -66.81mA
-906.8mV  -42.34mA   -48.1mA    -41.42mA
-859.1mV  -27.51mA   -32.38mA   -31.19mA
-811.4mV  -20.68mA   -21.56mA   -26.8mA
-763.6mV  -17.22mA   -15.21mA   -23.29mA
-715.9mV  -14.57mA   -11.71mA   -19.94mA
-429.5mV  -2.409mA   -2.204mA   -3.222mA
-334.1mV  -538.8uA   -707.4uA   -589.3uA
-238.6mV  -34.43uA   -108.5uA   -17.28uA
2.959V    171.1uA    140uA      213.2uA
[Power Clamp]
-1.459V   1.027A     711.2mA    1.35A
-1.03V    129.3mA    114.5mA    151.4mA
-981.8mV  78.48mA    77.22mA    87.29mA
-934.1mV  48.73mA    51.4mA     53.47mA
-886.4mV  32.89mA    34.83mA    38.4mA
-838.6mV  24.91mA    24.53mA    31.7mA
-790.9mV  20.61mA    18.26mA    27.45mA
-743.2mV  17.51mA    14.37mA    23.68mA
-456.8mV  3.892mA    3.387mA    5.399mA
-361.4mV  1.383mA    1.455mA    1.887mA
-218.2mV  56.59uA    161.1uA    60.54uA
2.979V    -85.62uA   -74.93uA   -101.2uA
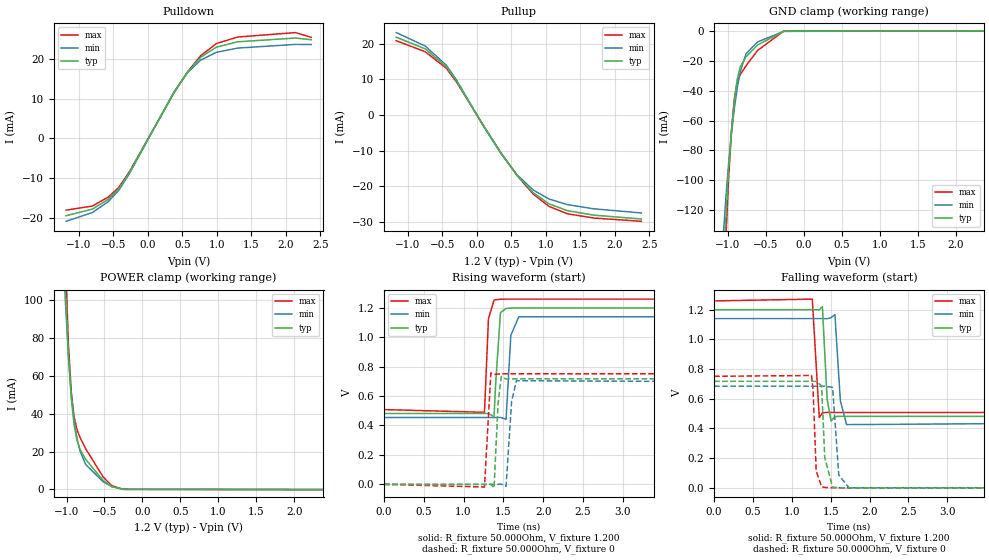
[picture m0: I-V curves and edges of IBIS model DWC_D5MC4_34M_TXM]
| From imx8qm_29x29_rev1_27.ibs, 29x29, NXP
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[Model] DWC_D5MC4_34M_TXM
Model_type   I/O
Polarity   Non-Inverting
Enable   Active-High
C_comp   1.264pF   1.181pF   1.367pF
C_comp_pullup   284.419fF   263.792fF   311.358fF
C_comp_pulldown 969.046fF   901.845fF   1.049pF
Vinh = 693.000mV
Vinl = 507.000mV
Vmeas = 600.000mV
Vref = 600.000mV
Rref = 50Ohms
Cref = 0pF
[Model Spec]
Vinh   693.000mV   663.000mV   723.000mV
Vinl   507.000mV   477.000mV   537.000mV
Vmeas   600.000mV   570.000mV   630.000mV
Vref   600.000mV   570.000mV   630.000mV
D_overshoot_ampl_h 0.4 NA   NA
D_overshoot_ampl_l 0.4 NA   NA
D_overshoot_area_l 60.000p NA   NA
D_overshoot_area_h 60.000p NA   NA
[Receiver Thresholds]
Vth = 600.000mV
Vth_min = 588.000mV
Vth_max = 612.000mV
Vinh_ac = 68.000mV
Vinh_dc = 68.000mV
Vinl_ac = -68.000mV
Vinl_dc = -68.000mV
Tslew_ac = 5.000ns
Reference_supply Pullup_ref
[Temperature Range]   25.000   125.000   -40.000
[Voltage Range]   1.200V   1.140V   1.260V
[GND Clamp Reference]   0.00V   0.00V   0.00V
[C Comp Corner]
| variable   typ   min   max
C_comp 1.264pF   1.367pF   1.181pF
C_comp_pullup 284.419fF   311.358fF   263.792fF
C_comp_pulldown 969.046fF   1.049pF   901.845fF
[Pulldown Reference]   0.00V   0.00V   0.00V
[POWER Clamp Reference]   1.200V   1.140V   1.260V
[Pullup Reference]   1.200V   1.140V   1.260V
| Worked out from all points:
|   slope of the pulldown table from 0 to 0.18 V, typ, clamps not added: 31.8 ohm
|   slope of the pullup table from 0 to 0.18 V, typ, clamps not added: 31.9 ohm
|   GND clamp passes 1 mA (typ) near -0.36 V on its own axis
|   POWER clamp passes 1 mA (typ) near -0.38 V on its own axis
|   rising waveform, R_fixture 50.000Ohm, V_fixture 1.200: 20-80 % time 32.5ps typ, 39.9ps min, 27.8ps max; typ from 0.481 V to 1.2 V
|   rising waveform, R_fixture 50.000Ohm, V_fixture 0: 20-80 % time 34.1ps typ, 45.2ps min, 27.8ps max; typ from 0 V to 0.717 V
|   falling waveform, R_fixture 50.000Ohm, V_fixture 1.200: 20-80 % time 37.1ps typ, 46ps min, 31.3ps max; typ from 1.2 V to 0.481 V
|   falling waveform, R_fixture 50.000Ohm, V_fixture 0: 20-80 % time 37.2ps typ, 45.9ps min, 31.4ps max; typ from 0.717 V to 0 V
[GND Clamp]
-1.184V   -342.5mA   -256.9mA   -430.7mA
-1.069V   -170mA     -142.2mA   -199.2mA
-1.031V   -127.6mA   -113.2mA   -142.7mA
-992.7mV  -93.59mA   -88.73mA   -98.99mA
-954.5mV  -66.78mA   -68.42mA   -66.61mA
-916.4mV  -46.35mA   -51.62mA   -45.02mA
-878.2mV  -32.2mA    -37.95mA   -34mA
-840mV    -24.05mA   -27.38mA   -29.18mA
-763.6mV  -17.22mA   -15.2mA    -23.29mA
-610.9mV  -9.369mA   -7.283mA   -12.96mA
-267.3mV  -89.24uA   -208uA     -59.9uA
2.367V    136.8uA    111.6uA    170.5uA
[Power Clamp]
-1.167V   370mA      273mA      475mA
-1.015V   108.4mA    99.12mA    123mA
-976.4mV  71.8mA     71.42mA    77.9mA
-938.2mV  48.37mA    51.03mA    51.81mA
-900mV    34.2mA     36.79mA    38.28mA
-861.8mV  25.98mA    27.04mA    31.54mA
-823.6mV  21.25mA    20.48mA    27.58mA
-747.3mV  15.81mA    13.12mA    21.46mA
-518.2mV  4.768mA    4.041mA    6.612mA
-403.6mV  1.471mA    1.528mA    1.982mA
-250.9mV  45.63uA    138.2uA    40.3uA
2.384V    -68.4uA    -58.87uA   -80.92uA
[Pulldown]
-1.184V   -19.4mA    -20.8mA    -18mA
-801.8mV  -17.73mA   -18.59mA   -16.96mA
-572.7mV  -15.26mA   -15.86mA   -14.7mA
-420mV    -12.62mA   -12.99mA   -12.28mA
-267.3mV  -8.551mA   -8.851mA   -8.351mA
381.8mV   11.65mA    11.8mA     11.55mA
572.7mV   16.61mA    16.47mA    16.66mA
763.6mV   20.38mA    19.67mA    20.77mA
992.7mV   22.94mA    21.63mA    23.84mA
1.298V    24.27mA    22.7mA     25.47mA
2.138V    25.23mA    23.63mA    26.6mA
2.367V    24.8mA     23.6mA     25.4mA
[Pullup]
-1.167V   21.8mA     23.09mA    20.81mA
-747.3mV  18.52mA    19.32mA    17.72mA
-441.8mV  13.53mA    13.94mA    13.1mA
-289.1mV  9.344mA    9.662mA    9.11mA
92.7mV    -2.936mA   -3.019mA   -2.889mA
360mV     -10.99mA   -11.12mA   -10.92mA
589.1mV   -17.07mA   -16.9mA    -17.13mA
818.2mV   -21.84mA   -21.07mA   -22.22mA
1.047V    -24.95mA   -23.59mA   -25.67mA
1.315V    -26.86mA   -25.17mA   -27.74mA
1.696V    -28.12mA   -26.34mA   -28.93mA
2.384V    -29.2mA    -27.5mA    -29.84mA
[Ramp]
R_load=50.000Ohm
dV/dt_r   430.380mV/34.000ps  410.819mV/43.500ps  450.330mV/28.000ps
dV/dt_f   430.380mV/38.000ps  410.819mV/47.000ps  450.330mV/32.000ps
[Rising waveform]
R_fixture=50.000Ohm
V_fixture=1.200
V_fixture_min=1.140
V_fixture_max=1.260
0s        481.2mV    453.7mV    507.9mV
1.263ns   481.2mV    453.7mV    489.4mV
1.313ns   481.5mV    453.7mV    1.125V
1.383ns   458.6mV    453.6mV    1.251V
1.403ns   679.5mV    453.7mV    1.254V
1.464ns   1.166V     454.9mV    1.257V
1.534ns   1.195V     442mV      1.258V
1.594ns   1.197V     1.012V     1.258V
1.694ns   1.198V     1.138V     1.258V
10ns      1.199V     1.139V     1.258V
[Rising waveform]
R_fixture=50.000Ohm
V_fixture=0
0s        168.4nV    4.199uV    19.87nV
1.263ns   -5.994uV   3.056uV    -18.06mV
1.343ns   1.792mV    5.824uV    756.6mV
1.383ns   -23.72mV   -105.7uV   746.7mV
1.434ns   549.2mV    607uV      749.1mV
1.474ns   732.6mV    1.642mV    750.3mV
1.534ns   715.4mV    -12.92mV   750.9mV
1.604ns   716.1mV    564.3mV    751.1mV
1.664ns   716.9mV    703.9mV    751.1mV
10ns      717.1mV    684.1mV    750.8mV
[Falling waveform]
R_fixture=50.000Ohm
V_fixture=1.200
V_fixture_min=1.140
V_fixture_max=1.260
0s        1.199V     1.139V     1.258V
1.263ns   1.199V     1.139V     1.27V
1.353ns   1.198V     1.139V     473mV
1.393ns   1.219V     1.139V     504.6mV
1.454ns   596.4mV    1.138V     508.1mV
1.504ns   450.3mV    1.145V     507.7mV
1.554ns   479.7mV    1.166V     507.5mV
1.624ns   481.6mV    586.5mV    507.5mV
1.704ns   481.1mV    425.6mV    507.5mV
10ns      481.1mV    453.7mV    507.8mV
[Falling waveform]
R_fixture=50.000Ohm
V_fixture=0
0s        717mV      684.1mV    750.7mV
1.253ns   717mV      684.1mV    756mV
1.273ns   717mV      684.1mV    661.4mV
1.313ns   716.7mV    684.1mV    113.9mV
1.383ns   686.1mV    684.1mV    7.421mV
1.423ns   205.5mV    683.8mV    3.001mV
1.524ns   4.44mV     676.6mV    222.4uV
1.604ns   1.326mV    86.32mV    27.38uV
1.734ns   98uV       1.225mV    5.57uV
10ns      395.8nV    4.451uV    170.9nV
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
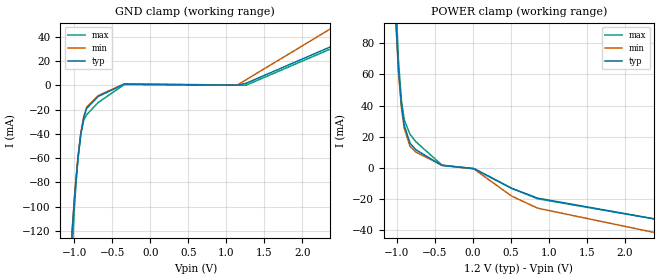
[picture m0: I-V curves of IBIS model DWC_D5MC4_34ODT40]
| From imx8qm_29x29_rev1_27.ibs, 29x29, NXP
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[Model] DWC_D5MC4_34ODT40
Model_type   Input
Polarity   Non-Inverting
Enable   Active-High
C_comp   1.393pF   1.314pF   1.427pF
C_comp_power_clamp   363.572fF   359.862fF   375.457fF
C_comp_gnd_clamp 1.019pF   938.534fF   1.043pF
Vinh = 969.000mV
Vinl = 783.000mV
[Model Spec]
D_overshoot_ampl_h 0.4 NA   NA
D_overshoot_ampl_l 0.4 NA   NA
D_overshoot_area_l 60.000p NA   NA
D_overshoot_area_h 60.000p NA   NA
[Receiver Thresholds]
Vth = 876.000mV
Vth_min = 864.000mV
Vth_max = 888.000mV
Vinh_ac = 68.000mV
Vinh_dc = 68.000mV
Vinl_ac = -68.000mV
Vinl_dc = -68.000mV
Tslew_ac = 5.000ns
Reference_supply Power_clamp_ref
[Temperature Range]   25.000   125.000   -40.000
[Voltage Range]   1.200V   1.140V   1.260V
[GND Clamp Reference]   0.00V   0.00V   0.00V
[C Comp Corner]
| variable   typ   min   max
C_comp 1.393pF   1.427pF   1.314pF
C_comp_pullup 363.572fF   375.457fF   359.862fF
C_comp_pulldown 1.019pF   1.043pF   938.534fF
[POWER Clamp Reference]   1.200V   1.140V   1.260V
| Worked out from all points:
|   GND clamp passes 1 mA (typ) near -0.46 V on its own axis
|   POWER clamp passes 1 mA (typ) near -0.37 V on its own axis
[GND Clamp]
-1.184V   -335.1mA   -333.6mA   -423.5mA
-1.031V   -121.4mA   -120.1mA   -136.6mA
-992.7mV  -87.62mA   -86.4mA    -93.11mA
-954.5mV  -61.07mA   -59.92mA   -61.01mA
-916.4mV  -40.91mA   -39.83mA   -39.68mA
-878.2mV  -27.04mA   -26.02mA   -28.92mA
-840mV    -19.16mA   -18.19mA   -24.36mA
-687.3mV  -9.245mA   -8.479mA   -14.18mA
-343.6mV  985.5uA    1.152mA    580.4uA
1.145V    66uA       234.2uA    78.62uA
1.26V     1.682mA    4.563mA    90.35uA
2.367V    31.62mA    46.43mA    29.85mA
[Power Clamp]
-1.167V   357.4mA    352.8mA    461.7mA
-1.015V   99.11mA    97.15mA    113.1mA
-976.4mV  63.31mA    61.62mA    68.77mA
-938.2mV  40.66mA    38.77mA    43.48mA
-900mV    27.25mA    25.27mA    30.72mA
-823.6mV  15.76mA    13.84mA    21.51mA
-747.3mV  11.66mA    10.14mA    16.78mA
-403.6mV  1.492mA    1.696mA    1.768mA
16.4mV    -452.4uA   -710uA     -444uA
512.7mV   -13.1mA    -18.12mA   -13.13mA
856.4mV   -19.43mA   -25.9mA    -19.85mA
2.384V    -32.69mA   -41.42mA   -32.73mA
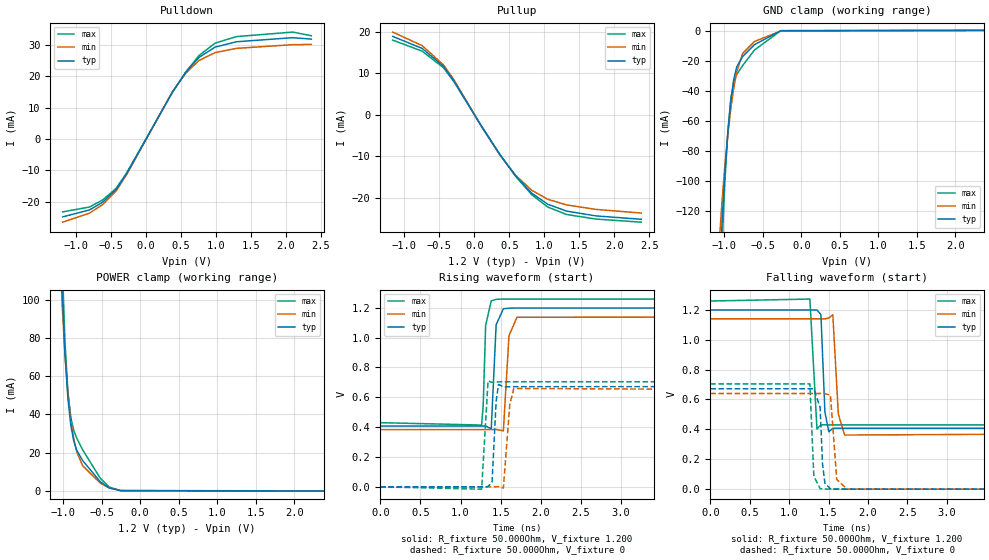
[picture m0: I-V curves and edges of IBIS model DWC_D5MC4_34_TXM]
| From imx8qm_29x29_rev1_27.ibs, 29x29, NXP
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[Model] DWC_D5MC4_34_TXM
Model_type   I/O
Polarity   Non-Inverting
Enable   Active-High
C_comp   1.264pF   1.181pF   1.367pF
C_comp_pullup   284.432fF   263.792fF   311.497fF
C_comp_pulldown 969.064fF   901.870fF   1.049pF
Vinh = 910.000mV
Vinl = 724.000mV
Vmeas = 817.000mV
Vref = 817.000mV
Rref = 50Ohms
Cref = 0pF
[Model Spec]
Vinh   910.000mV   869.000mV   951.000mV
Vinl   724.000mV   683.000mV   765.000mV
Vmeas   817.000mV   776.000mV   858.000mV
Vref   817.000mV   776.000mV   858.000mV
D_overshoot_ampl_h 0.4 NA   NA
D_overshoot_ampl_l 0.4 NA   NA
D_overshoot_area_l 60.000p NA   NA
D_overshoot_area_h 60.000p NA   NA
[Receiver Thresholds]
Vth = 817.000mV
Vth_min = 805.000mV
Vth_max = 829.000mV
Vinh_ac = 68.000mV
Vinh_dc = 68.000mV
Vinl_ac = -68.000mV
Vinl_dc = -68.000mV
Tslew_ac = 5.000ns
Reference_supply Pullup_ref
[Temperature Range]   25.000   125.000   -40.000
[Voltage Range]   1.200V   1.140V   1.260V
[GND Clamp Reference]   0.00V   0.00V   0.00V
[C Comp Corner]
| variable   typ   min   max
C_comp 1.264pF   1.367pF   1.181pF
C_comp_pullup 284.432fF   311.497fF   263.792fF
C_comp_pulldown 969.064fF   1.049pF   901.870fF
[Pulldown Reference]   0.00V   0.00V   0.00V
[POWER Clamp Reference]   1.200V   1.140V   1.260V
[Pullup Reference]   1.200V   1.140V   1.260V
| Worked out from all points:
|   slope of the pulldown table from 0 to 0.18 V, typ, clamps not added: 24.8 ohm
|   slope of the pullup table from 0 to 0.18 V, typ, clamps not added: 36.9 ohm
|   GND clamp passes 1 mA (typ) near -0.36 V on its own axis
|   POWER clamp passes 1 mA (typ) near -0.38 V on its own axis
|   rising waveform, R_fixture 50.000Ohm, V_fixture 1.200: 20-80 % time 34.6ps typ, 43.7ps min, 29.5ps max; typ from 0.408 V to 1.2 V
|   rising waveform, R_fixture 50.000Ohm, V_fixture 0: 20-80 % time 35.7ps typ, 48.6ps min, 28.5ps max; typ from 0 V to 0.671 V
|   falling waveform, R_fixture 50.000Ohm, V_fixture 1.200: 20-80 % time 34.5ps typ, 42.6ps min, 29.4ps max; typ from 1.2 V to 0.407 V
|   falling waveform, R_fixture 50.000Ohm, V_fixture 0: 20-80 % time 34.7ps typ, 43.5ps min, 28ps max; typ from 0.671 V to 0 V
[GND Clamp]
-1.184V   -342.5mA   -256.9mA   -430.7mA
-1.069V   -170mA     -142.2mA   -199.2mA
-1.031V   -127.6mA   -113.2mA   -142.7mA
-992.7mV  -93.59mA   -88.73mA   -98.99mA
-954.5mV  -66.78mA   -68.42mA   -66.61mA
-916.4mV  -46.35mA   -51.62mA   -45.02mA
-878.2mV  -32.2mA    -37.95mA   -34mA
-840mV    -24.05mA   -27.38mA   -29.18mA
-763.6mV  -17.22mA   -15.2mA    -23.29mA
-610.9mV  -9.369mA   -7.283mA   -12.96mA
-267.3mV  -89.24uA   -208uA     -59.9uA
2.367V    136.8uA    111.6uA    170.5uA
[Power Clamp]
-1.167V   370mA      273mA      475mA
-1.015V   108.4mA    99.12mA    123mA
-976.4mV  71.8mA     71.42mA    77.9mA
-938.2mV  48.37mA    51.03mA    51.81mA
-900mV    34.2mA     36.79mA    38.28mA
-861.8mV  25.98mA    27.04mA    31.54mA
-823.6mV  21.25mA    20.48mA    27.58mA
-747.3mV  15.81mA    13.12mA    21.46mA
-518.2mV  4.768mA    4.041mA    6.612mA
-403.6mV  1.471mA    1.528mA    1.982mA
-250.9mV  45.63uA    138.2uA    40.3uA
2.384V    -68.4uA    -58.87uA   -80.92uA
[Pulldown]
-1.184V   -24.9mA    -26.6mA    -23.3mA
-801.8mV  -22.69mA   -23.71mA   -21.76mA
-610.9mV  -20.18mA   -20.93mA   -19.46mA
-420mV    -16.15mA   -16.57mA   -15.76mA
-267.3mV  -10.94mA   -11.29mA   -10.72mA
381.8mV   14.91mA    15.06mA    14.83mA
572.7mV   21.26mA    21.01mA    21.39mA
763.6mV   26.08mA    25.08mA    26.68mA
992.7mV   29.35mA    27.59mA    30.62mA
1.298V    31.06mA    28.95mA    32.71mA
2.1V      32.36mA    30.13mA    34.15mA
2.367V    31.9mA     30.2mA     33mA
[Pullup]
-1.167V   18.9mA     19.94mA    18.01mA
-747.3mV  16.01mA    16.68mA    15.35mA
-441.8mV  11.7mA     12.04mA    11.35mA
-289.1mV  8.08mA     8.346mA    7.898mA
92.7mV    -2.539mA   -2.608mA   -2.504mA
360mV     -9.505mA   -9.608mA   -9.465mA
589.1mV   -14.76mA   -14.6mA    -14.85mA
818.2mV   -18.89mA   -18.2mA    -19.26mA
1.047V    -21.57mA   -20.37mA   -22.25mA
1.315V    -23.22mA   -21.73mA   -24.04mA
1.734V    -24.38mA   -22.81mA   -25.14mA
2.384V    -25.2mA    -23.7mA    -25.9mA
[Ramp]
R_load=50.000Ohm
dV/dt_r   438.690mV/35.500ps  418.439mV/46.500ps  459.600mV/29.000ps
dV/dt_f   438.690mV/35.000ps  418.439mV/43.500ps  459.570mV/29.000ps
[Rising waveform]
R_fixture=50.000Ohm
V_fixture=1.200
V_fixture_min=1.140
V_fixture_max=1.260
0s        407.5mV    383.5mV    430mV
1.263ns   407.5mV    383.5mV    413.9mV
1.283ns   407.4mV    383.5mV    548.4mV
1.313ns   407.7mV    383.5mV    1.081V
1.383ns   388.9mV    383.4mV    1.246V
1.444ns   1.086V     384.7mV    1.256V
1.534ns   1.193V     375.1mV    1.258V
1.604ns   1.197V     1.013V     1.258V
1.704ns   1.198V     1.136V     1.258V
10ns      1.198V     1.139V     1.258V
[Rising waveform]
R_fixture=50.000Ohm
V_fixture=0
0s        143.8nV    3.584uV    16.94nV
1.263ns   -6.581uV   2.689uV    -15.59mV
1.343ns   1.526mV    3.323uV    709mV
1.393ns   32.48mV    -98.36uV   699.9mV
1.444ns   575.2mV    954.2uV    702.4mV
1.474ns   686.5mV    1.341mV    703.4mV
1.534ns   670mV      -8.354mV   704.1mV
1.614ns   670.5mV    553.1mV    704.3mV
1.664ns   671.1mV    659.1mV    704.3mV
10ns      671.3mV    639.4mV    703.9mV
[Falling waveform]
R_fixture=50.000Ohm
V_fixture=1.200
V_fixture_min=1.140
V_fixture_max=1.260
0s        1.198V     1.139V     1.258V
1.263ns   1.198V     1.139V     1.271V
1.353ns   1.198V     1.139V     401.8mV
1.403ns   1.167V     1.139V     430.4mV
1.454ns   513.2mV    1.138V     430.5mV
1.504ns   382.8mV    1.145V     429.9mV
1.554ns   407.6mV    1.166V     429.7mV
1.624ns   408mV      501.6mV    429.7mV
1.704ns   407.4mV    361.9mV    429.7mV
10ns      407.4mV    383.5mV    430mV
[Falling waveform]
R_fixture=50.000Ohm
V_fixture=0
0s        671.2mV    639.4mV    703.8mV
1.263ns   671.2mV    639.4mV    703.7mV
1.313ns   671mV      639.4mV    86.87mV
1.393ns   547mV      639.4mV    3.697mV
1.423ns   170.2mV    639.1mV    1.884mV
1.454ns   39.61mV    639.1mV    852.1uV
1.524ns   2.278mV    628mV      130.9uV
1.604ns   876.1uV    65.05mV    17.22uV
1.734ns   61.88uV    402uV      5.439uV
10ns      341.7nV    3.875uV    224.9nV
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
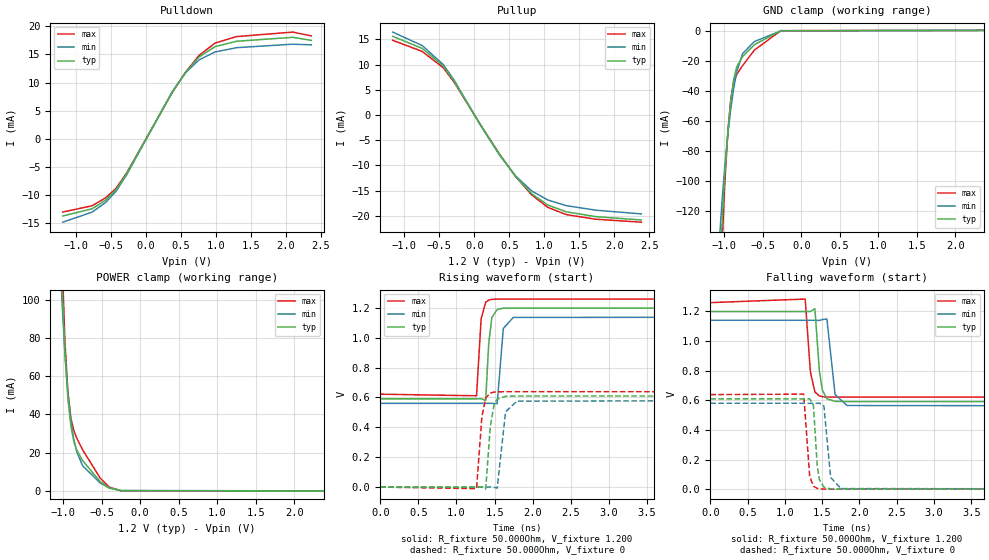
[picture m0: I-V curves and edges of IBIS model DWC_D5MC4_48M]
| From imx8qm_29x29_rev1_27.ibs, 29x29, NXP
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[Model] DWC_D5MC4_48M
Model_type   I/O
Polarity   Non-Inverting
Enable   Active-High
C_comp   1.264pF   1.181pF   1.367pF
C_comp_pullup   284.419fF   263.792fF   311.358fF
C_comp_pulldown 969.046fF   901.845fF   1.049pF
Vinh = 693.000mV
Vinl = 507.000mV
Vmeas = 600.000mV
Vref = 600.000mV
Rref = 50Ohms
Cref = 0pF
[Model Spec]
Vinh   693.000mV   663.000mV   723.000mV
Vinl   507.000mV   477.000mV   537.000mV
Vmeas   600.000mV   570.000mV   630.000mV
Vref   600.000mV   570.000mV   630.000mV
D_overshoot_ampl_h 0.4 NA   NA
D_overshoot_ampl_l 0.4 NA   NA
D_overshoot_area_l 60.000p NA   NA
D_overshoot_area_h 60.000p NA   NA
[Receiver Thresholds]
Vth = 600.000mV
Vth_min = 588.000mV
Vth_max = 612.000mV
Vinh_ac = 68.000mV
Vinh_dc = 68.000mV
Vinl_ac = -68.000mV
Vinl_dc = -68.000mV
Tslew_ac = 5.000ns
Reference_supply Pullup_ref
[Temperature Range]   25.000   125.000   -40.000
[Voltage Range]   1.200V   1.140V   1.260V
[GND Clamp Reference]   0.00V   0.00V   0.00V
[C Comp Corner]
| variable   typ   min   max
C_comp 1.264pF   1.367pF   1.181pF
C_comp_pullup 284.419fF   311.358fF   263.792fF
C_comp_pulldown 969.046fF   1.049pF   901.845fF
[Pulldown Reference]   0.00V   0.00V   0.00V
[POWER Clamp Reference]   1.200V   1.140V   1.260V
[Pullup Reference]   1.200V   1.140V   1.260V
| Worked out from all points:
|   slope of the pulldown table from 0 to 0.18 V, typ, clamps not added: 44.5 ohm
|   slope of the pullup table from 0 to 0.18 V, typ, clamps not added: 44.6 ohm
|   GND clamp passes 1 mA (typ) near -0.36 V on its own axis
|   POWER clamp passes 1 mA (typ) near -0.38 V on its own axis
|   rising waveform, R_fixture 50.000Ohm, V_fixture 1.200: 20-80 % time 43ps typ, 49ps min, 40.1ps max; typ from 0.591 V to 1.2 V
|   rising waveform, R_fixture 50.000Ohm, V_fixture 0: 20-80 % time 57.4ps typ, 66.7ps min, 52.7ps max; typ from 0 V to 0.609 V
|   falling waveform, R_fixture 50.000Ohm, V_fixture 1.200: 20-80 % time 61.5ps typ, 70.4ps min, 55.9ps max; typ from 1.2 V to 0.591 V
|   falling waveform, R_fixture 50.000Ohm, V_fixture 0: 20-80 % time 48.4ps typ, 57ps min, 42.6ps max; typ from 0.609 V to 0 V
[GND Clamp]
-1.184V   -342.5mA   -256.9mA   -430.7mA
-1.069V   -170mA     -142.2mA   -199.2mA
-1.031V   -127.6mA   -113.2mA   -142.7mA
-992.7mV  -93.59mA   -88.73mA   -98.99mA
-954.5mV  -66.78mA   -68.42mA   -66.61mA
-916.4mV  -46.35mA   -51.62mA   -45.02mA
-878.2mV  -32.2mA    -37.95mA   -34mA
-840mV    -24.05mA   -27.38mA   -29.18mA
-763.6mV  -17.22mA   -15.2mA    -23.29mA
-610.9mV  -9.369mA   -7.283mA   -12.96mA
-267.3mV  -89.24uA   -208uA     -59.9uA
2.367V    136.8uA    111.6uA    170.5uA
[Power Clamp]
-1.167V   370mA      273mA      475mA
-1.015V   108.4mA    99.12mA    123mA
-976.4mV  71.8mA     71.42mA    77.9mA
-938.2mV  48.37mA    51.03mA    51.81mA
-900mV    34.2mA     36.79mA    38.28mA
-861.8mV  25.98mA    27.04mA    31.54mA
-823.6mV  21.25mA    20.48mA    27.58mA
-747.3mV  15.81mA    13.12mA    21.46mA
-518.2mV  4.768mA    4.041mA    6.612mA
-403.6mV  1.471mA    1.528mA    1.982mA
-250.9mV  45.63uA    138.2uA    40.3uA
2.384V    -68.4uA    -58.87uA   -80.92uA
[Pulldown]
-1.184V   -13.7mA    -14.8mA    -13mA
-763.6mV  -12.42mA   -13.01mA   -11.88mA
-572.7mV  -10.9mA    -11.32mA   -10.49mA
-420mV    -9.006mA   -9.275mA   -8.766mA
-267.3mV  -6.103mA   -6.321mA   -5.966mA
381.8mV   8.318mA    8.43mA     8.253mA
572.7mV   11.86mA    11.76mA    11.89mA
763.6mV   14.55mA    14.04mA    14.83mA
992.7mV   16.39mA    15.44mA    17.02mA
1.298V    17.34mA    16.2mA     18.17mA
2.1V      18.04mA    16.82mA    18.97mA
2.367V    17.5mA     16.7mA     18.3mA
[Pullup]
-1.167V   15.6mA     16.44mA    14.81mA
-747.3mV  13.22mA    13.79mA    12.62mA
-441.8mV  9.664mA    9.956mA    9.334mA
-289.1mV  6.675mA    6.903mA    6.496mA
92.7mV    -2.098mA   -2.157mA   -2.06mA
360mV     -7.853mA   -7.946mA   -7.784mA
589.1mV   -12.19mA   -12.07mA   -12.21mA
818.2mV   -15.6mA    -15.05mA   -15.83mA
1.047V    -17.83mA   -16.84mA   -18.29mA
1.315V    -19.19mA   -17.97mA   -19.75mA
1.734V    -20.14mA   -18.86mA   -20.65mA
2.384V    -20.8mA    -19.6mA    -21.24mA
[Ramp]
R_load=50.000Ohm
dV/dt_r   365.130mV/50.500ps  347.458mV/58.000ps  382.260mV/47.000ps
dV/dt_f   365.130mV/56.000ps  347.458mV/64.500ps  382.260mV/50.000ps
[Rising waveform]
R_fixture=50.000Ohm
V_fixture=1.200
V_fixture_min=1.140
V_fixture_max=1.260
0s        590.7mV    560.1mV    621.5mV
1.263ns   590.7mV    560.1mV    610.9mV
1.323ns   591.4mV    560.1mV    1.125V
1.383ns   579.5mV    560mV      1.237V
1.423ns   961.7mV    560.5mV    1.251V
1.464ns   1.135V     560.4mV    1.256V
1.534ns   1.188V     558.2mV    1.258V
1.614ns   1.197V     1.061V     1.258V
1.744ns   1.198V     1.135V     1.258V
10ns      1.198V     1.139V     1.258V
[Rising waveform]
R_fixture=50.000Ohm
V_fixture=0
0s        204.3nV    5.107uV    24.05nV
1.263ns   -2.732uV   3.889uV    -10.54mV
1.333ns   1.028mV    16.93uV    470mV
1.383ns   -14.02mV   -88.27uV   595.6mV
1.444ns   407.7mV    870.7uV    629.3mV
1.494ns   553.7mV    -2.138mV   635.6mV
1.534ns   587.8mV    -7.39mV    637.2mV
1.644ns   607.4mV    503.6mV    638.2mV
1.794ns   609.5mV    575.4mV    638.2mV
10ns      609.4mV    579.5mV    637.8mV
[Falling waveform]
R_fixture=50.000Ohm
V_fixture=1.200
V_fixture_min=1.140
V_fixture_max=1.260
0s        1.198V     1.139V     1.258V
1.273ns   1.198V     1.139V     1.282V
1.343ns   1.198V     1.139V     790.4mV
1.403ns   1.217V     1.139V     655.4mV
1.464ns   795.2mV    1.138V     628.5mV
1.504ns   666.9mV    1.144V     623.8mV
1.564ns   609.4mV    1.148V     621.6mV
1.674ns   592.3mV    638.3mV    620.9mV
1.834ns   590.4mV    564mV      620.9mV
10ns      590.6mV    560.1mV    621.4mV
[Falling waveform]
R_fixture=50.000Ohm
V_fixture=0
0s        609.3mV    579.5mV    637.7mV
1.253ns   609.3mV    579.5mV    640.9mV
1.333ns   609.2mV    579.5mV    88.26mV
1.383ns   569.1mV    579.5mV    20.39mV
1.434ns   161mV      579.1mV    5.319mV
1.464ns   64.33mV    580.2mV    2.491mV
1.524ns   13.63mV    561mV      562.2uV
1.614ns   2.011mV    79.41mV    64.37uV
1.754ns   128.6uV    3.946mV    8.084uV
10ns      587.1nV    5.42uV     68.84nV
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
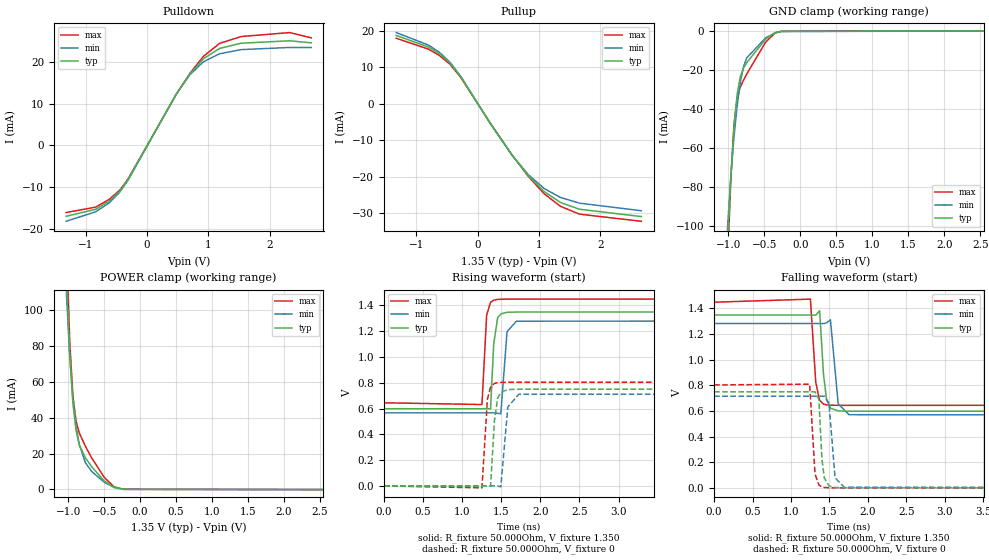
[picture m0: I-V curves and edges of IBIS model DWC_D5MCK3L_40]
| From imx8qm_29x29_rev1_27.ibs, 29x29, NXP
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[Model] DWC_D5MCK3L_40
Model_type   I/O
Polarity   Non-Inverting
Enable   Active-High
C_comp   1.262pF   1.180pF   1.365pF
C_comp_pullup   279.441fF   258.852fF   306.885fF
C_comp_pulldown 973.651fF   908.565fF   1.053pF
Vinh = 800.000mV
Vinl = 550.000mV
Vmeas = 675.000mV
Vref = 675.000mV
Rref = 50Ohms
Cref = 0pF
[Model Spec]
Vinh   800.000mV   767.000mV   850.000mV
Vinl   550.000mV   517.000mV   600.000mV
Vmeas   675.000mV   642.000mV   725.000mV
Vref   675.000mV   642.000mV   725.000mV
D_overshoot_ampl_h 0.4 NA   NA
D_overshoot_ampl_l 0.4 NA   NA
D_overshoot_area_l 100.000p NA   NA
D_overshoot_area_h 100.000p NA   NA
[Receiver Thresholds]
Vcross_low = 525.000mV
Vcross_high = 825.000mV
Vdiff_ac = 250.000mV
Vdiff_dc = 180.000mV
Tdiffslew_ac = 10.000ns
[Temperature Range]   25.000   125.000   -40.000
[Voltage Range]   1.350V   1.283V   1.450V
[GND Clamp Reference]   0.00V   0.00V   0.00V
[C Comp Corner]
| variable   typ   min   max
C_comp 1.262pF   1.365pF   1.180pF
C_comp_pullup 279.441fF   306.885fF   258.852fF
C_comp_pulldown 973.651fF   1.053pF   908.565fF
[Pulldown Reference]   0.00V   0.00V   0.00V
[POWER Clamp Reference]   1.350V   1.283V   1.450V
[Pullup Reference]   1.350V   1.283V   1.450V
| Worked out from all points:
|   slope of the pulldown table from 0 to 0.203 V, typ, clamps not added: 37.8 ohm
|   slope of the pullup table from 0 to 0.203 V, typ, clamps not added: 38.2 ohm
|   GND clamp passes 1 mA (typ) near -0.36 V on its own axis
|   POWER clamp passes 1 mA (typ) near -0.36 V on its own axis
|   rising waveform, R_fixture 50.000Ohm, V_fixture 1.350: 20-80 % time 40.1ps typ, 45.7ps min, 37.5ps max; typ from 0.598 V to 1.35 V
|   rising waveform, R_fixture 50.000Ohm, V_fixture 0: 20-80 % time 49ps typ, 56.7ps min, 45ps max; typ from 0 V to 0.749 V
|   falling waveform, R_fixture 50.000Ohm, V_fixture 1.350: 20-80 % time 51.9ps typ, 59.1ps min, 48.5ps max; typ from 1.35 V to 0.598 V
|   falling waveform, R_fixture 50.000Ohm, V_fixture 0: 20-80 % time 42.2ps typ, 48.9ps min, 37.8ps max; typ from 0.749 V to 0 V
[GND Clamp]
-1.318V   -593.4mA   -427mA     -758.7mA
-1.011V   -108.7mA   -99.8mA    -118.2mA
-966.7mV  -74.7mA    -74.6mA    -75.87mA
-922.7mV  -49.41mA   -54.3mA    -47.9mA
-878.8mV  -32.42mA   -38.21mA   -34.12mA
-834.8mV  -23.33mA   -26.23mA   -28.72mA
-790.9mV  -19.01mA   -18.35mA   -25.26mA
-747mV    -16.25mA   -13.76mA   -22.11mA
-483.3mV  -4.093mA   -3.434mA   -5.633mA
-351.5mV  -766.8uA   -911.3uA   -894.7uA
-263.6mV  -79.41uA   -192.1uA   -51.43uA
2.68V     154.9uA    127.3uA    193.1uA
[Power Clamp]
-1.33V    727.8mA    510.6mA    954.1mA
-1.023V   119.4mA    107.4mA    137.5mA
-978.8mV  74.87mA    74.2mA     82.23mA
-934.8mV  47.95mA    50.66mA    52.21mA
-890.9mV  32.9mA     35.12mA    38.1mA
-847mV    24.9mA     25.11mA    31.53mA
-759.1mV  17.5mA     14.71mA    23.9mA
-671.2mV  12.54mA    9.915mA    17.38mA
-495.5mV  4.603mA    3.922mA    6.563mA
-363.6mV  1.088mA    1.21mA     1.541mA
-231.8mV  46.56uA    141.4uA    53.69uA
2.668V    -76.24uA   -66.58uA   -87.76uA
[Pulldown]
-1.318V   -17mA      -18.2mA    -16.1mA
-834.8mV  -15.32mA   -15.91mA   -14.8mA
-615.2mV  -13.36mA   -13.77mA   -12.94mA
-439.4mV  -10.93mA   -11.15mA   -10.69mA
-307.6mV  -8.174mA   -8.353mA   -8.038mA
483.3mV   12.39mA    12.48mA    12.35mA
703mV     17.17mA    16.97mA    17.31mA
922.7mV   20.81mA    20.07mA    21.38mA
1.186V    23.27mA    21.98mA    24.48mA
1.538V    24.52mA    22.98mA    26.12mA
2.329V    25.1mA     23.5mA     27.07mA
2.68V     24.6mA     23.5mA     25.8mA
[Pullup]
-1.33V    18.8mA     19.59mA    18.03mA
-803mV    15.61mA    16.14mA    15.03mA
-627.3mV  13.79mA    14.18mA    13.31mA
-451.5mV  11.19mA    11.42mA    10.86mA
-275.8mV  7.343mA    7.515mA    7.201mA
207.6mV   -5.434mA   -5.544mA   -5.381mA
559.1mV   -14.08mA   -14.13mA   -14.08mA
822.7mV   -19.72mA   -19.44mA   -19.93mA
1.086V    -24.18mA   -23.33mA   -24.78mA
1.35V     -27.13mA   -25.75mA   -28.19mA
1.658V    -28.98mA   -27.31mA   -30.33mA
2.668V    -31mA      -29.4mA    -32.3mA
[Ramp]
R_load=50.000Ohm
dV/dt_r   449.790mV/45.000ps  429.118mV/52.000ps  481.860mV/41.000ps
dV/dt_f   449.790mV/48.000ps  429.118mV/54.500ps  481.860mV/44.000ps
[Rising waveform]
R_fixture=50.000Ohm
V_fixture=1.350
V_fixture_min=1.283
V_fixture_max=1.450
0s        598.4mV    566.3mV    644.6mV
1.253ns   598.4mV    566.3mV    631mV
1.313ns   599.4mV    566.3mV    1.324V
1.363ns   597.1mV    566.2mV    1.424V
1.403ns   1.099V     566.6mV    1.44V
1.454ns   1.304V     563.8mV    1.446V
1.494ns   1.333V     558.7mV    1.447V
1.574ns   1.346V     1.196V     1.448V
1.694ns   1.348V     1.277V     1.448V
10ns      1.348V     1.282V     1.448V
[Rising waveform]
R_fixture=50.000Ohm
V_fixture=0
0s        387.7nV    8.16uV     51.48nV
1.253ns   6.976uV    6.988uV    -14.9mV
1.323ns   1.401mV    23.3uV     672.9mV
1.363ns   -2.956mV   -76.9uV    765.9mV
1.413ns   508.6mV    622.7uV    794.5mV
1.454ns   680.7mV    -294.1uV   800.7mV
1.494ns   726.2mV    -7.681mV   802.8mV
1.584ns   746.8mV    611.8mV    803.8mV
1.724ns   749.7mV    710.2mV    803.9mV
10ns      749.4mV    715mV      803.1mV
[Falling waveform]
R_fixture=50.000Ohm
V_fixture=1.350
V_fixture_min=1.283
V_fixture_max=1.450
0s        1.348V     1.282V     1.448V
1.253ns   1.348V     1.282V     1.472V
1.323ns   1.347V     1.282V     821.9mV
1.373ns   1.381V     1.282V     683mV
1.423ns   888.5mV    1.281V     653.7mV
1.464ns   686mV      1.287V     647.1mV
1.514ns   621.4mV    1.311V     644.6mV
1.614ns   600.4mV    655.6mV    643.7mV
1.754ns   597.9mV    570.9mV    643.7mV
10ns      598.3mV    566.2mV    644.4mV
[Falling waveform]
R_fixture=50.000Ohm
V_fixture=0
0s        749.3mV    714.9mV    802.9mV
1.243ns   749.3mV    714.9mV    808.7mV
1.313ns   748.9mV    714.9mV    109.2mV
1.363ns   692.8mV    715mV      22.61mV
1.403ns   222.1mV    714.6mV    7.427mV
1.434ns   77.7mV     715.1mV    3.271mV
1.494ns   14.87mV    662.1mV    698.4uV
1.574ns   2.576mV    77.83mV    94.44uV
1.694ns   229.7uV    5.284mV    10.94uV
10ns      488.7nV    8.259uV    184.7nV
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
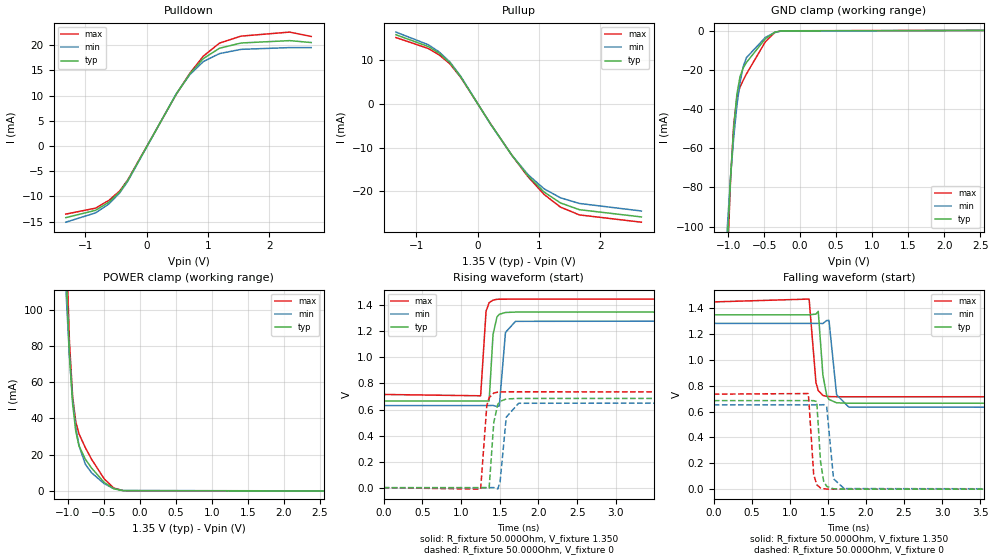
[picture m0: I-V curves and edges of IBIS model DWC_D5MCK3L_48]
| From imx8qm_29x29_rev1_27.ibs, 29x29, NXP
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[Model] DWC_D5MCK3L_48
Model_type   I/O
Polarity   Non-Inverting
Enable   Active-High
C_comp   1.262pF   1.180pF   1.365pF
C_comp_pullup   279.441fF   258.852fF   306.885fF
C_comp_pulldown 973.651fF   908.565fF   1.053pF
Vinh = 800.000mV
Vinl = 550.000mV
Vmeas = 675.000mV
Vref = 675.000mV
Rref = 50Ohms
Cref = 0pF
[Model Spec]
Vinh   800.000mV   767.000mV   850.000mV
Vinl   550.000mV   517.000mV   600.000mV
Vmeas   675.000mV   642.000mV   725.000mV
Vref   675.000mV   642.000mV   725.000mV
D_overshoot_ampl_h 0.4 NA   NA
D_overshoot_ampl_l 0.4 NA   NA
D_overshoot_area_l 100.000p NA   NA
D_overshoot_area_h 100.000p NA   NA
[Receiver Thresholds]
Vcross_low = 525.000mV
Vcross_high = 825.000mV
Vdiff_ac = 250.000mV
Vdiff_dc = 180.000mV
Tdiffslew_ac = 10.000ns
[Temperature Range]   25.000   125.000   -40.000
[Voltage Range]   1.350V   1.283V   1.450V
[GND Clamp Reference]   0.00V   0.00V   0.00V
[C Comp Corner]
| variable   typ   min   max
C_comp 1.262pF   1.365pF   1.180pF
C_comp_pullup 279.441fF   306.885fF   258.852fF
C_comp_pulldown 973.651fF   1.053pF   908.565fF
[Pulldown Reference]   0.00V   0.00V   0.00V
[POWER Clamp Reference]   1.350V   1.283V   1.450V
[Pullup Reference]   1.350V   1.283V   1.450V
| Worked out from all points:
|   slope of the pulldown table from 0 to 0.203 V, typ, clamps not added: 45.3 ohm
|   slope of the pullup table from 0 to 0.203 V, typ, clamps not added: 45.8 ohm
|   GND clamp passes 1 mA (typ) near -0.36 V on its own axis
|   POWER clamp passes 1 mA (typ) near -0.36 V on its own axis
|   rising waveform, R_fixture 50.000Ohm, V_fixture 1.350: 20-80 % time 43.3ps typ, 48.8ps min, 40.9ps max; typ from 0.665 V to 1.35 V
|   rising waveform, R_fixture 50.000Ohm, V_fixture 0: 20-80 % time 53.2ps typ, 61.6ps min, 49.3ps max; typ from 0 V to 0.685 V
|   falling waveform, R_fixture 50.000Ohm, V_fixture 1.350: 20-80 % time 57.5ps typ, 65.2ps min, 53.3ps max; typ from 1.35 V to 0.665 V
|   falling waveform, R_fixture 50.000Ohm, V_fixture 0: 20-80 % time 46.2ps typ, 53ps min, 41.5ps max; typ from 0.685 V to 0 V
[GND Clamp]
-1.318V   -593.4mA   -427mA     -758.7mA
-1.011V   -108.7mA   -99.8mA    -118.2mA
-966.7mV  -74.7mA    -74.6mA    -75.87mA
-922.7mV  -49.41mA   -54.3mA    -47.9mA
-878.8mV  -32.42mA   -38.21mA   -34.12mA
-834.8mV  -23.33mA   -26.23mA   -28.72mA
-790.9mV  -19.01mA   -18.35mA   -25.26mA
-747mV    -16.25mA   -13.76mA   -22.11mA
-483.3mV  -4.093mA   -3.434mA   -5.633mA
-351.5mV  -766.8uA   -911.3uA   -894.7uA
-263.6mV  -79.41uA   -192.1uA   -51.43uA
2.68V     154.9uA    127.3uA    193.1uA
[Power Clamp]
-1.33V    727.8mA    510.6mA    954.1mA
-1.023V   119.4mA    107.4mA    137.5mA
-978.8mV  74.87mA    74.2mA     82.23mA
-934.8mV  47.95mA    50.66mA    52.21mA
-890.9mV  32.9mA     35.12mA    38.1mA
-847mV    24.9mA     25.11mA    31.53mA
-759.1mV  17.5mA     14.71mA    23.9mA
-671.2mV  12.54mA    9.915mA    17.38mA
-495.5mV  4.603mA    3.922mA    6.563mA
-363.6mV  1.088mA    1.21mA     1.541mA
-231.8mV  46.56uA    141.4uA    53.69uA
2.668V    -76.24uA   -66.58uA   -87.76uA
[Pulldown]
-1.318V   -14.2mA    -15.1mA    -13.5mA
-834.8mV  -12.76mA   -13.26mA   -12.32mA
-615.2mV  -11.12mA   -11.48mA   -10.77mA
-439.4mV  -9.099mA   -9.296mA   -8.898mA
-307.6mV  -6.807mA   -6.963mA   -6.694mA
483.3mV   10.32mA    10.4mA     10.28mA
703mV     14.3mA     14.14mA    14.42mA
922.7mV   17.33mA    16.73mA    17.81mA
1.186V    19.37mA    18.31mA    20.39mA
1.538V    20.41mA    19.15mA    21.77mA
2.329V    20.88mA    19.5mA     22.57mA
2.68V     20.5mA     19.5mA     21.7mA
[Pullup]
-1.33V    15.7mA     16.3mA     15.06mA
-803mV    13.01mA    13.43mA    12.56mA
-627.3mV  11.5mA     11.8mA     11.12mA
-451.5mV  9.33mA     9.507mA    9.082mA
-275.8mV  6.124mA    6.257mA    6.022mA
207.6mV   -4.531mA   -4.616mA   -4.5mA
559.1mV   -11.74mA   -11.76mA   -11.77mA
822.7mV   -16.45mA   -16.18mA   -16.66mA
1.086V    -20.16mA   -19.42mA   -20.71mA
1.35V     -22.61mA   -21.44mA   -23.56mA
1.658V    -24.15mA   -22.73mA   -25.34mA
2.668V    -25.8mA    -24.45mA   -27mA
[Ramp]
R_load=50.000Ohm
dV/dt_r   410.400mV/49.000ps  390.957mV/55.500ps  440.100mV/45.000ps
dV/dt_f   410.370mV/52.000ps  390.927mV/59.500ps  440.070mV/48.500ps
[Rising waveform]
R_fixture=50.000Ohm
V_fixture=1.350
V_fixture_min=1.283
V_fixture_max=1.450
0s        665mV      630.5mV    715.6mV
1.253ns   665mV      630.5mV    705.4mV
1.323ns   665.9mV    630.6mV    1.355V
1.363ns   666.2mV    630.5mV    1.42V
1.413ns   1.175V     631.4mV    1.44V
1.464ns   1.311V     623.1mV    1.446V
1.494ns   1.331V     626.2mV    1.447V
1.574ns   1.345V     1.192V     1.447V
1.704ns   1.348V     1.277V     1.448V
10ns      1.348V     1.282V     1.448V
[Rising waveform]
R_fixture=50.000Ohm
V_fixture=0
0s        428.7nV    9.028uV    56.87nV
1.253ns   8.208uV    7.839uV    -11.49mV
1.333ns   278.6uV    15.22uV    632mV
1.363ns   -1.975mV   -71.11uV   691.3mV
1.423ns   501.2mV    1.061mV    726.7mV
1.474ns   638.2mV    -10.53mV   733.4mV
1.504ns   662.4mV    42.65mV    734.7mV
1.584ns   681.2mV    541.4mV    735.8mV
1.744ns   685.1mV    647.9mV    735.9mV
10ns      684.8mV    652.1mV    735.1mV
[Falling waveform]
R_fixture=50.000Ohm
V_fixture=1.350
V_fixture_min=1.283
V_fixture_max=1.450
0s        1.348V     1.282V     1.448V
1.253ns   1.348V     1.282V     1.47V
1.343ns   1.354V     1.282V     823.3mV
1.373ns   1.375V     1.282V     762.8mV
1.434ns   882.4mV    1.281V     724.7mV
1.484ns   724.8mV    1.304V     717.5mV
1.514ns   693.9mV    1.305V     715.9mV
1.614ns   667.9mV    730.4mV    714.6mV
1.774ns   664.5mV    634.7mV    714.5mV
10ns      664.9mV    630.5mV    715.4mV
[Falling waveform]
R_fixture=50.000Ohm
V_fixture=0
0s        684.6mV    652mV      734.8mV
1.243ns   684.6mV    652mV      739.3mV
1.313ns   684.3mV    652mV      113.5mV
1.353ns   678mV      652.1mV    34.42mV
1.403ns   213.2mV    651.7mV    9.006mV
1.444ns   61.39mV    653.5mV    3.183mV
1.484ns   21.75mV    637mV      1.18mV
1.574ns   3.085mV    79.66mV    133.7uV
1.714ns   196.3uV    4.291mV    11.41uV
10ns      675.5nV    9.3uV      117.7nV
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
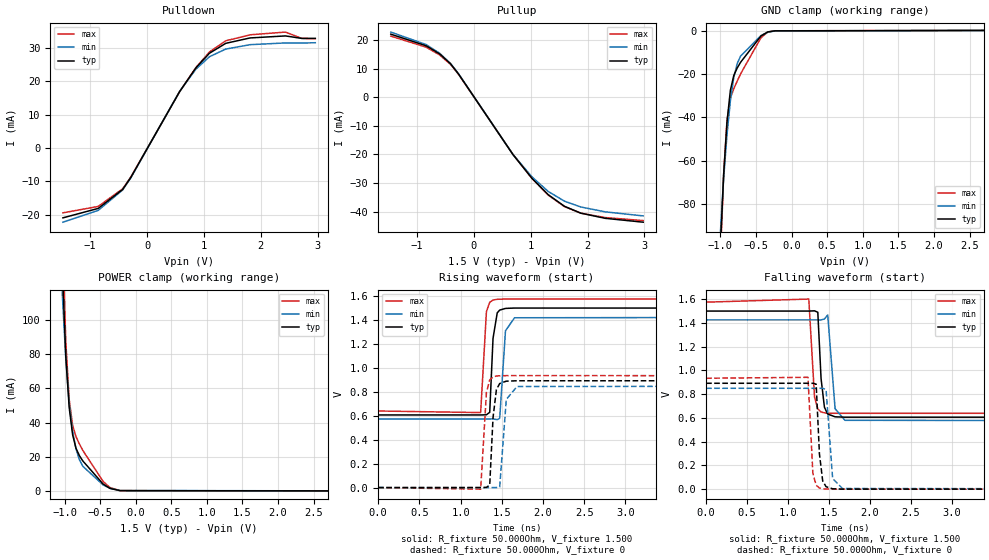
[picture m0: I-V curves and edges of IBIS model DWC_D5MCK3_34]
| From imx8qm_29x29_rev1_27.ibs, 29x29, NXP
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[Model] DWC_D5MCK3_34
Model_type   I/O
Polarity   Non-Inverting
Enable   Active-High
C_comp   1.260pF   1.180pF   1.362pF
C_comp_pullup   275.501fF   256.643fF   303.068fF
C_comp_pulldown 982.421fF   918.243fF   1.058pF
Vinh = 875.000mV
Vinl = 625.000mV
Vmeas = 750.000mV
Vref = 750.000mV
Rref = 50Ohms
Cref = 0pF
[Model Spec]
Vinh   875.000mV   838.000mV   913.000mV
Vinl   625.000mV   588.000mV   663.000mV
Vmeas   750.000mV   713.000mV   788.000mV
Vref   750.000mV   713.000mV   788.000mV
D_overshoot_ampl_h 0.4 NA   NA
D_overshoot_ampl_l 0.4 NA   NA
D_overshoot_area_l 100.000p NA   NA
D_overshoot_area_h 100.000p NA   NA
[Receiver Thresholds]
Vcross_low = 575.000mV
Vcross_high = 925.000mV
Vdiff_ac = 250.000mV
Vdiff_dc = 200.000mV
Tdiffslew_ac = 10.000ns
[Temperature Range]   25.000   125.000   -40.000
[Voltage Range]   1.500V   1.425V   1.575V
[GND Clamp Reference]   0.00V   0.00V   0.00V
[C Comp Corner]
| variable   typ   min   max
C_comp 1.260pF   1.362pF   1.180pF
C_comp_pullup 275.501fF   303.068fF   256.643fF
C_comp_pulldown 982.421fF   1.058pF   918.243fF
[Pulldown Reference]   0.00V   0.00V   0.00V
[POWER Clamp Reference]   1.500V   1.425V   1.575V
[Pullup Reference]   1.500V   1.425V   1.575V
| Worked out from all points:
|   slope of the pulldown table from 0 to 0.225 V, typ, clamps not added: 32.7 ohm
|   slope of the pullup table from 0 to 0.225 V, typ, clamps not added: 33.1 ohm
|   GND clamp passes 1 mA (typ) near -0.36 V on its own axis
|   POWER clamp passes 1 mA (typ) near -0.34 V on its own axis
|   rising waveform, R_fixture 50.000Ohm, V_fixture 1.500: 20-80 % time 37.6ps typ, 43.4ps min, 35ps max; typ from 0.606 V to 1.5 V
|   rising waveform, R_fixture 50.000Ohm, V_fixture 0: 20-80 % time 43.7ps typ, 51.1ps min, 40.4ps max; typ from 0 V to 0.891 V
|   falling waveform, R_fixture 50.000Ohm, V_fixture 1.500: 20-80 % time 45.5ps typ, 51.3ps min, 43.3ps max; typ from 1.5 V to 0.606 V
|   falling waveform, R_fixture 50.000Ohm, V_fixture 0: 20-80 % time 38.4ps typ, 43.2ps min, 35ps max; typ from 0.891 V to 0 V
[GND Clamp]
-1.48V    -918.2mA   -652.1mA   -1.176A
-1.002V   -101.7mA   -94.77mA   -109.1mA
-954.5mV  -67.02mA   -68.69mA   -66.81mA
-906.8mV  -42.34mA   -48.1mA    -41.42mA
-859.1mV  -27.51mA   -32.38mA   -31.19mA
-811.4mV  -20.68mA   -21.56mA   -26.8mA
-763.6mV  -17.22mA   -15.21mA   -23.29mA
-715.9mV  -14.57mA   -11.71mA   -19.94mA
-429.5mV  -2.409mA   -2.204mA   -3.222mA
-334.1mV  -538.8uA   -707.4uA   -589.3uA
-238.6mV  -34.43uA   -108.5uA   -17.28uA
2.959V    171.1uA    140uA      213.2uA
[Power Clamp]
-1.459V   1.027A     711.2mA    1.35A
-1.03V    129.3mA    114.5mA    151.4mA
-981.8mV  78.48mA    77.22mA    87.29mA
-934.1mV  48.73mA    51.4mA     53.47mA
-886.4mV  32.89mA    34.83mA    38.4mA
-838.6mV  24.91mA    24.53mA    31.7mA
-790.9mV  20.61mA    18.26mA    27.45mA
-743.2mV  17.51mA    14.37mA    23.68mA
-456.8mV  3.892mA    3.387mA    5.399mA
-361.4mV  1.383mA    1.455mA    1.887mA
-218.2mV  56.59uA    161.1uA    60.54uA
2.979V    -85.62uA   -74.93uA   -101.2uA
[Pulldown]
-1.48V    -20.9mA    -22.2mA    -19.4mA
-859.1mV  -18.07mA   -18.66mA   -17.48mA
-429.5mV  -12.39mA   -12.55mA   -12.19mA
-286.4mV  -8.796mA   -8.941mA   -8.69mA
572.7mV   16.95mA    17.01mA    16.88mA
859.1mV   24.06mA    23.68mA    24.15mA
1.098V    28.46mA    27.41mA    28.84mA
1.384V    31.42mA    29.7mA     32.18mA
1.814V    33.04mA    31.02mA    33.98mA
2.434V    33.64mA    31.54mA    34.79mA
2.72V     32.9mA     31.5mA     32.9mA
2.959V    32.9mA     31.6mA     32.8mA
[Pullup]
-1.459V   22.1mA     22.83mA    21.41mA
-838.6mV  18.05mA    18.47mA    17.56mA
-600mV    15.19mA    15.42mA    14.82mA
-409.1mV  11.75mA    11.85mA    11.54mA
-265.9mV  8.091mA    8.177mA    7.994mA
688.6mV   -20.02mA   -19.99mA   -19.99mA
1.023V    -28.34mA   -27.85mA   -28.39mA
1.309V    -34.09mA   -32.95mA   -34.21mA
1.595V    -38.14mA   -36.35mA   -38.26mA
1.882V    -40.54mA   -38.38mA   -40.55mA
2.311V    -42.35mA   -40.08mA   -42.08mA
2.979V    -43.7mA    -41.5mA    -43.14mA
[Ramp]
R_load=50.000Ohm
dV/dt_r   534.960mV/41.500ps  509.816mV/48.000ps  560.130mV/38.500ps
dV/dt_f   534.960mV/42.000ps  509.816mV/48.000ps  560.100mV/39.000ps
[Rising waveform]
R_fixture=50.000Ohm
V_fixture=1.500
V_fixture_min=1.425
V_fixture_max=1.575
0s        606mV      572.9mV    639mV
1.243ns   606mV      572.9mV    625.7mV
1.313ns   607.4mV    572.9mV    1.468V
1.353ns   628.2mV    572.8mV    1.546V
1.393ns   1.245V     573.3mV    1.565V
1.444ns   1.458V     566.6mV    1.571V
1.474ns   1.481V     578mV      1.572V
1.544ns   1.495V     1.308V     1.573V
1.654ns   1.498V     1.417V     1.573V
10ns      1.498V     1.424V     1.573V
[Rising waveform]
R_fixture=50.000Ohm
V_fixture=0
0s        745.4nV    13.01uV    91.45nV
1.243ns   19.7uV     12.49uV    -13.29mV
1.313ns   1.552mV    29.92uV    794mV
1.353ns   21.69mV    -64.52uV   898mV
1.393ns   583.1mV    269.7uV    923.2mV
1.434ns   817.2mV    290.3uV    930.7mV
1.474ns   868.3mV    5.622mV    933mV
1.554ns   887.9mV    735.7mV    934mV
1.684ns   891.2mV    843.4mV    934.1mV
10ns      890.9mV    848.6mV    933.3mV
[Falling waveform]
R_fixture=50.000Ohm
V_fixture=1.500
V_fixture_min=1.425
V_fixture_max=1.575
0s        1.498V     1.424V     1.573V
1.253ns   1.498V     1.424V     1.599V
1.323ns   1.5V       1.424V     774.8mV
1.363ns   1.488V     1.424V     675mV
1.403ns   928.8mV    1.423V     649.5mV
1.444ns   688.7mV    1.432V     641.7mV
1.484ns   631.7mV    1.465V     639.2mV
1.574ns   608.6mV    676.8mV    638mV
1.694ns   605.5mV    579.2mV    637.9mV
10ns      605.8mV    572.8mV    638.8mV
[Falling waveform]
R_fixture=50.000Ohm
V_fixture=0
0s        890.7mV    848.5mV    933mV
1.243ns   890.7mV    848.5mV    940.7mV
1.303ns   890.2mV    848.5mV    131.1mV
1.343ns   883.3mV    848.5mV    33.03mV
1.383ns   295mV      848.3mV    10.08mV
1.423ns   68.46mV    849mV      3.376mV
1.464ns   20.68mV    836.2mV    1.142mV
1.544ns   3.336mV    89.5mV     143.7uV
1.664ns   288.4uV    5.545mV    12.31uV
10ns      943.7nV    13.21uV    322.9nV
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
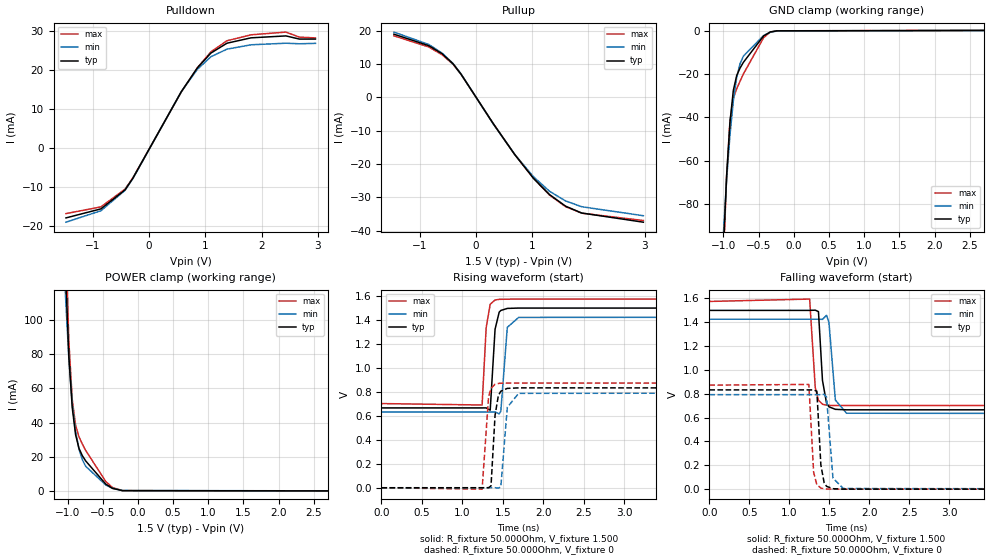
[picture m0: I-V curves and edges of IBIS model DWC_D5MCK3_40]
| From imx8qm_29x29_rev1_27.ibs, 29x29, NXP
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[Model] DWC_D5MCK3_40
Model_type   I/O
Polarity   Non-Inverting
Enable   Active-High
C_comp   1.260pF   1.180pF   1.362pF
C_comp_pullup   275.501fF   256.643fF   303.068fF
C_comp_pulldown 982.421fF   918.243fF   1.058pF
Vinh = 875.000mV
Vinl = 625.000mV
Vmeas = 750.000mV
Vref = 750.000mV
Rref = 50Ohms
Cref = 0pF
[Model Spec]
Vinh   875.000mV   838.000mV   913.000mV
Vinl   625.000mV   588.000mV   663.000mV
Vmeas   750.000mV   713.000mV   788.000mV
Vref   750.000mV   713.000mV   788.000mV
D_overshoot_ampl_h 0.4 NA   NA
D_overshoot_ampl_l 0.4 NA   NA
D_overshoot_area_l 100.000p NA   NA
D_overshoot_area_h 100.000p NA   NA
[Receiver Thresholds]
Vcross_low = 575.000mV
Vcross_high = 925.000mV
Vdiff_ac = 250.000mV
Vdiff_dc = 200.000mV
Tdiffslew_ac = 10.000ns
[Temperature Range]   25.000   125.000   -40.000
[Voltage Range]   1.500V   1.425V   1.575V
[GND Clamp Reference]   0.00V   0.00V   0.00V
[C Comp Corner]
| variable   typ   min   max
C_comp 1.260pF   1.362pF   1.180pF
C_comp_pullup 275.501fF   303.068fF   256.643fF
C_comp_pulldown 982.421fF   1.058pF   918.243fF
[Pulldown Reference]   0.00V   0.00V   0.00V
[POWER Clamp Reference]   1.500V   1.425V   1.575V
[Pullup Reference]   1.500V   1.425V   1.575V
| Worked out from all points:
|   slope of the pulldown table from 0 to 0.225 V, typ, clamps not added: 38.1 ohm
|   slope of the pullup table from 0 to 0.225 V, typ, clamps not added: 38.6 ohm
|   GND clamp passes 1 mA (typ) near -0.36 V on its own axis
|   POWER clamp passes 1 mA (typ) near -0.34 V on its own axis
|   rising waveform, R_fixture 50.000Ohm, V_fixture 1.500: 20-80 % time 39.9ps typ, 45.8ps min, 37.3ps max; typ from 0.666 V to 1.5 V
|   rising waveform, R_fixture 50.000Ohm, V_fixture 0: 20-80 % time 46.5ps typ, 54ps min, 43.9ps max; typ from 0 V to 0.832 V
|   falling waveform, R_fixture 50.000Ohm, V_fixture 1.500: 20-80 % time 50.1ps typ, 55.8ps min, 47.5ps max; typ from 1.5 V to 0.665 V
|   falling waveform, R_fixture 50.000Ohm, V_fixture 0: 20-80 % time 41.5ps typ, 46.7ps min, 38.1ps max; typ from 0.832 V to 0 V
[GND Clamp]
-1.48V    -918.2mA   -652.1mA   -1.176A
-1.002V   -101.7mA   -94.77mA   -109.1mA
-954.5mV  -67.02mA   -68.69mA   -66.81mA
-906.8mV  -42.34mA   -48.1mA    -41.42mA
-859.1mV  -27.51mA   -32.38mA   -31.19mA
-811.4mV  -20.68mA   -21.56mA   -26.8mA
-763.6mV  -17.22mA   -15.21mA   -23.29mA
-715.9mV  -14.57mA   -11.71mA   -19.94mA
-429.5mV  -2.409mA   -2.204mA   -3.222mA
-334.1mV  -538.8uA   -707.4uA   -589.3uA
-238.6mV  -34.43uA   -108.5uA   -17.28uA
2.959V    171.1uA    140uA      213.2uA
[Power Clamp]
-1.459V   1.027A     711.2mA    1.35A
-1.03V    129.3mA    114.5mA    151.4mA
-981.8mV  78.48mA    77.22mA    87.29mA
-934.1mV  48.73mA    51.4mA     53.47mA
-886.4mV  32.89mA    34.83mA    38.4mA
-838.6mV  24.91mA    24.53mA    31.7mA
-790.9mV  20.61mA    18.26mA    27.45mA
-743.2mV  17.51mA    14.37mA    23.68mA
-456.8mV  3.892mA    3.387mA    5.399mA
-361.4mV  1.383mA    1.455mA    1.887mA
-218.2mV  56.59uA    161.1uA    60.54uA
2.979V    -85.62uA   -74.93uA   -101.2uA
[Pulldown]
-1.48V    -17.8mA    -18.9mA    -16.7mA
-859.1mV  -15.49mA   -15.97mA   -14.98mA
-429.5mV  -10.63mA   -10.75mA   -10.44mA
-286.4mV  -7.545mA   -7.656mA   -7.449mA
572.7mV   14.54mA    14.57mA    14.47mA
859.1mV   20.64mA    20.27mA    20.7mA
1.098V    24.41mA    23.47mA    24.72mA
1.384V    26.94mA    25.42mA    27.57mA
1.814V    28.32mA    26.54mA    29.1mA
2.434V    28.81mA    26.94mA    29.79mA
2.673V    28mA       26.8mA     28.5mA
2.959V    28mA       26.9mA     28.3mA
[Pullup]
-1.459V   18.9mA     19.53mA    18.41mA
-838.6mV  15.46mA    15.81mA    15.06mA
-600mV    13.01mA    13.2mA     12.71mA
-409.1mV  10.07mA    10.14mA    9.903mA
-265.9mV  6.934mA    7.003mA    6.859mA
306.8mV   -7.902mA   -7.983mA   -7.867mA
688.6mV   -17.16mA   -17.12mA   -17.16mA
1.023V    -24.29mA   -23.85mA   -24.36mA
1.309V    -29.21mA   -28.22mA   -29.36mA
1.595V    -32.69mA   -31.12mA   -32.84mA
1.882V    -34.75mA   -32.86mA   -34.8mA
2.979V    -37.5mA    -35.56mA   -37mA
[Ramp]
R_load=50.000Ohm
dV/dt_r   499.380mV/43.500ps  475.436mV/50.500ps  522.840mV/41.000ps
dV/dt_f   499.380mV/45.500ps  475.436mV/51.500ps  522.810mV/43.000ps
[Rising waveform]
R_fixture=50.000Ohm
V_fixture=1.500
V_fixture_min=1.425
V_fixture_max=1.575
0s        665.6mV    630.8mV    701.7mV
1.243ns   665.6mV    630.8mV    689.8mV
1.293ns   665.7mV    630.8mV    1.334V
1.343ns   646.6mV    630.7mV    1.53V
1.403ns   1.322V     631.7mV    1.565V
1.454ns   1.464V     615.9mV    1.571V
1.474ns   1.478V     637.2mV    1.571V
1.554ns   1.495V     1.337V     1.572V
1.694ns   1.498V     1.42V      1.573V
10ns      1.498V     1.424V     1.573V
[Rising waveform]
R_fixture=50.000Ohm
V_fixture=0
0s        815.8nV    14.26uV    100.1nV
1.243ns   20.46uV    13.74uV    -11.86mV
1.323ns   359.7uV    30.24uV    760.2mV
1.353ns   15.44mV    -58.82uV   828.8mV
1.403ns   606mV      769.2uV    862.4mV
1.444ns   769.2mV    -3.733mV   869.5mV
1.474ns   804.7mV    6.384mV    871.4mV
1.554ns   828.4mV    670.4mV    872.8mV
1.694ns   832.6mV    786.9mV    873mV
10ns      832.1mV    792mV      872mV
[Falling waveform]
R_fixture=50.000Ohm
V_fixture=1.500
V_fixture_min=1.425
V_fixture_max=1.575
0s        1.498V     1.424V     1.573V
1.253ns   1.498V     1.424V     1.593V
1.323ns   1.5V       1.424V     851.3mV
1.363ns   1.488V     1.424V     745.3mV
1.413ns   912.2mV    1.423V     711.8mV
1.464ns   720.4mV    1.457V     703.4mV
1.494ns   690.4mV    1.398V     701.8mV
1.574ns   669mV      747.3mV    700.6mV
1.714ns   664.9mV    636.2mV    700.5mV
10ns      665.4mV    630.7mV    701.5mV
[Falling waveform]
R_fixture=50.000Ohm
V_fixture=0
0s        831.9mV    791.9mV    871.7mV
1.243ns   831.9mV    791.9mV    877.6mV
1.303ns   831.5mV    791.9mV    138mV
1.343ns   820.9mV    791.9mV    37.71mV
1.393ns   202.5mV    791.5mV    9.151mV
1.434ns   54.05mV    794.8mV    3.103mV
1.464ns   23.93mV    772.3mV    1.434mV
1.544ns   3.95mV     93.64mV    191.1uV
1.674ns   291uV      5.299mV    14.47uV
10ns      1.128uV    14.43uV    292.5nV
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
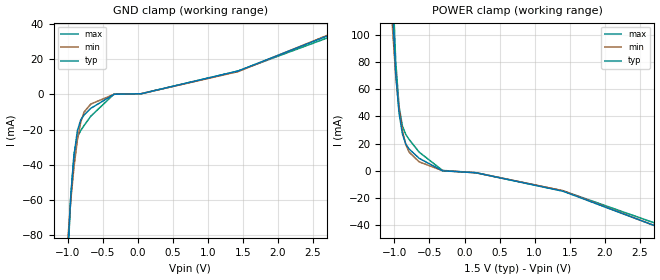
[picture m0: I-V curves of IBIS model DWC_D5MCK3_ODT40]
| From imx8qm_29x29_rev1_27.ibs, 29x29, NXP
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[Model] DWC_D5MCK3_ODT40
Model_type   Input
Polarity   Non-Inverting
Enable   Active-High
C_comp   1.505pF   1.492pF   1.544pF
C_comp_power_clamp   572.866fF   450.742fF   593.000fF
C_comp_gnd_clamp 969.219fF   907.572fF   1.040pF
Vinh = 875.000mV
Vinl = 625.000mV
[Model Spec]
D_overshoot_ampl_h 0.4 NA   NA
D_overshoot_ampl_l 0.4 NA   NA
D_overshoot_area_l 100.000p NA   NA
D_overshoot_area_h 100.000p NA   NA
[Receiver Thresholds]
Vcross_low = 575.000mV
Vcross_high = 925.000mV
Vdiff_ac = 250.000mV
Vdiff_dc = 200.000mV
Tdiffslew_ac = 10.000ns
[Temperature Range]   25.000   125.000   -40.000
[Voltage Range]   1.500V   1.425V   1.575V
[GND Clamp Reference]   0.00V   0.00V   0.00V
[C Comp Corner]
| variable   typ   min   max
C_comp 1.544pF   1.492pF   1.505pF
C_comp_pullup 572.866fF   450.742fF   593.000fF
C_comp_pulldown 969.219fF   1.040pF   907.572fF
[POWER Clamp Reference]   1.500V   1.425V   1.575V
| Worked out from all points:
|   GND clamp passes 1 mA (typ) near -0.44 V on its own axis
|   POWER clamp passes 1 mA (typ) near -0.38 V on its own axis
[GND Clamp]
-1.48V    -900.7mA   -635.4mA   -1.159A
-1.002V   -92.53mA   -86.05mA   -99.8mA
-954.5mV  -58.56mA   -60.68mA   -58.3mA
-906.8mV  -34.65mA   -40.81mA   -33.68mA
-859.1mV  -20.55mA   -25.8mA    -24.19mA
-811.4mV  -14.45mA   -15.66mA   -20.49mA
-763.6mV  -11.67mA   -9.981mA   -17.66mA
-668.2mV  -7.88mA    -5.45mA    -12.36mA
-334.1mV  130.9uA    138.4uA    332.2uA
47.73mV   424.6uA    422uA      407.6uA
1.432V    13.35mA    13.02mA    13.37mA
2.959V    37.37mA    37.82mA    35.96mA
[Power Clamp]
-1.459V   1.013A     697.9mA    1.336A
-1.03V    121.7mA    107.1mA    143.9mA
-981.8mV  71.63mA    70.44mA    80.57mA
-934.1mV  42.53mA    45.25mA    47.45mA
-886.4mV  27.3mA     29.27mA    32.99mA
-838.6mV  19.9mA     19.53mA    26.86mA
-790.9mV  16.14mA    13.81mA    23.14mA
-647.7mV  9.241mA    6.646mA    13.81mA
-313.6mV  62.47uA    194uA      352.7uA
163.6mV   -1.37mA    -1.376mA   -1.33mA
1.405V    -14.93mA   -14.59mA   -14.59mA
2.979V    -45.38mA   -45.44mA   -43.07mA
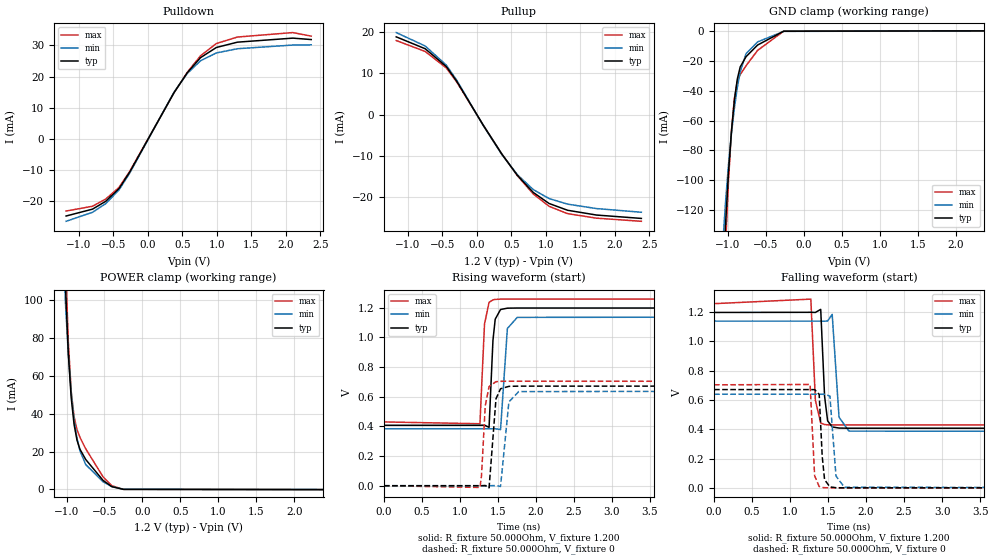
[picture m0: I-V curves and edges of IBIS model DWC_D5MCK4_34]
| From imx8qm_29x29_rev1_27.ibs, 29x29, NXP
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[Model] DWC_D5MCK4_34
Model_type   I/O
Polarity   Non-Inverting
Enable   Active-High
C_comp   1.264pF   1.181pF   1.367pF
C_comp_pullup   284.432fF   263.792fF   311.497fF
C_comp_pulldown 969.064fF   901.870fF   1.049pF
Vinh = 910.000mV
Vinl = 724.000mV
Vmeas = 817.000mV
Vref = 817.000mV
Rref = 50Ohms
Cref = 0pF
[Model Spec]
Vinh   910.000mV   869.000mV   951.000mV
Vinl   724.000mV   683.000mV   765.000mV
Vmeas   817.000mV   776.000mV   858.000mV
Vref   817.000mV   776.000mV   858.000mV
D_overshoot_ampl_h 0.4 NA   NA
D_overshoot_ampl_l 0.4 NA   NA
D_overshoot_area_l 60.000p NA   NA
D_overshoot_area_h 60.000p NA   NA
[Receiver Thresholds]
Vcross_low = 697.000mV
Vcross_high = 937.000mV
Vdiff_ac = 136.000mV
Vdiff_dc = 136.000mV
Tdiffslew_ac = 10.000ns
[Temperature Range]   25.000   125.000   -40.000
[Voltage Range]   1.200V   1.140V   1.260V
[GND Clamp Reference]   0.00V   0.00V   0.00V
[C Comp Corner]
| variable   typ   min   max
C_comp 1.264pF   1.367pF   1.181pF
C_comp_pullup 284.432fF   311.497fF   263.792fF
C_comp_pulldown 969.064fF   1.049pF   901.870fF
[Pulldown Reference]   0.00V   0.00V   0.00V
[POWER Clamp Reference]   1.200V   1.140V   1.260V
[Pullup Reference]   1.200V   1.140V   1.260V
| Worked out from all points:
|   slope of the pulldown table from 0 to 0.18 V, typ, clamps not added: 24.8 ohm
|   slope of the pullup table from 0 to 0.18 V, typ, clamps not added: 36.9 ohm
|   GND clamp passes 1 mA (typ) near -0.36 V on its own axis
|   POWER clamp passes 1 mA (typ) near -0.38 V on its own axis
|   rising waveform, R_fixture 50.000Ohm, V_fixture 1.200: 20-80 % time 39.7ps typ, 47.4ps min, 36.8ps max; typ from 0.408 V to 1.2 V
|   rising waveform, R_fixture 50.000Ohm, V_fixture 0: 20-80 % time 52.7ps typ, 63.4ps min, 47.7ps max; typ from 0 V to 0.671 V
|   falling waveform, R_fixture 50.000Ohm, V_fixture 1.200: 20-80 % time 43.2ps typ, 49.8ps min, 38.9ps max; typ from 1.2 V to 0.407 V
|   falling waveform, R_fixture 50.000Ohm, V_fixture 0: 20-80 % time 37.4ps typ, 46.3ps min, 31.9ps max; typ from 0.671 V to 0 V
[GND Clamp]
-1.184V   -342.5mA   -256.9mA   -430.7mA
-1.069V   -170mA     -142.2mA   -199.2mA
-1.031V   -127.6mA   -113.2mA   -142.7mA
-992.7mV  -93.59mA   -88.73mA   -98.99mA
-954.5mV  -66.78mA   -68.42mA   -66.61mA
-916.4mV  -46.35mA   -51.62mA   -45.02mA
-878.2mV  -32.2mA    -37.95mA   -34mA
-840mV    -24.05mA   -27.38mA   -29.18mA
-763.6mV  -17.22mA   -15.2mA    -23.29mA
-610.9mV  -9.369mA   -7.283mA   -12.96mA
-267.3mV  -89.24uA   -208uA     -59.9uA
2.367V    136.8uA    111.6uA    170.5uA
[Power Clamp]
-1.167V   370mA      273mA      475mA
-1.015V   108.4mA    99.12mA    123mA
-976.4mV  71.8mA     71.42mA    77.9mA
-938.2mV  48.37mA    51.03mA    51.81mA
-900mV    34.2mA     36.79mA    38.28mA
-861.8mV  25.98mA    27.04mA    31.54mA
-823.6mV  21.25mA    20.48mA    27.58mA
-747.3mV  15.81mA    13.12mA    21.46mA
-518.2mV  4.768mA    4.041mA    6.612mA
-403.6mV  1.471mA    1.528mA    1.982mA
-250.9mV  45.63uA    138.2uA    40.3uA
2.384V    -68.4uA    -58.87uA   -80.92uA
[Pulldown]
-1.184V   -24.9mA    -26.6mA    -23.3mA
-801.8mV  -22.69mA   -23.71mA   -21.76mA
-610.9mV  -20.18mA   -20.93mA   -19.46mA
-420mV    -16.15mA   -16.57mA   -15.76mA
-267.3mV  -10.94mA   -11.29mA   -10.72mA
381.8mV   14.91mA    15.06mA    14.83mA
572.7mV   21.26mA    21.01mA    21.39mA
763.6mV   26.08mA    25.08mA    26.68mA
992.7mV   29.35mA    27.59mA    30.62mA
1.298V    31.06mA    28.95mA    32.71mA
2.1V      32.36mA    30.13mA    34.15mA
2.367V    31.9mA     30.2mA     33mA
[Pullup]
-1.167V   18.9mA     19.94mA    18.01mA
-747.3mV  16.01mA    16.68mA    15.35mA
-441.8mV  11.7mA     12.04mA    11.35mA
-289.1mV  8.08mA     8.346mA    7.898mA
92.7mV    -2.539mA   -2.608mA   -2.504mA
360mV     -9.505mA   -9.608mA   -9.465mA
589.1mV   -14.76mA   -14.6mA    -14.85mA
818.2mV   -18.89mA   -18.2mA    -19.26mA
1.047V    -21.57mA   -20.37mA   -22.25mA
1.315V    -23.22mA   -21.73mA   -24.04mA
1.734V    -24.38mA   -22.81mA   -25.14mA
2.384V    -25.2mA    -23.7mA    -25.9mA
[Ramp]
R_load=50.000Ohm
dV/dt_r   438.690mV/46.500ps  418.439mV/56.000ps  459.600mV/42.500ps
dV/dt_f   438.690mV/41.000ps  418.439mV/48.500ps  459.570mV/36.000ps
[Rising waveform]
R_fixture=50.000Ohm
V_fixture=1.200
V_fixture_min=1.140
V_fixture_max=1.260
0s        407.5mV    383.5mV    430mV
1.263ns   407.5mV    383.5mV    417.8mV
1.323ns   408.2mV    383.5mV    1.09V
1.383ns   393.6mV    383.4mV    1.236V
1.434ns   979.4mV    384.2mV    1.253V
1.464ns   1.123V     384.4mV    1.256V
1.534ns   1.188V     378.3mV    1.258V
1.624ns   1.197V     1.06V      1.258V
1.754ns   1.198V     1.135V     1.258V
10ns      1.198V     1.139V     1.258V
[Rising waveform]
R_fixture=50.000Ohm
V_fixture=0
0s        143.8nV    3.584uV    16.94nV
1.263ns   -6.237uV   2.715uV    -11.82mV
1.283ns   -76.26uV   5.391uV    63.63mV
1.333ns   1.099mV    11.33uV    539.4mV
1.383ns   -14.51mV   -86.63uV   668.6mV
1.474ns   586mV      1.147mV    701.3mV
1.534ns   653.9mV    -5.437mV   703.7mV
1.644ns   669.9mV    565.6mV    704.3mV
1.774ns   671.4mV    634.7mV    704.3mV
10ns      671.3mV    639.4mV    703.9mV
[Falling waveform]
R_fixture=50.000Ohm
V_fixture=1.200
V_fixture_min=1.140
V_fixture_max=1.260
0s        1.198V     1.139V     1.258V
1.273ns   1.199V     1.139V     1.289V
1.333ns   1.198V     1.139V     597.8mV
1.403ns   1.219V     1.139V     442.8mV
1.454ns   625.2mV    1.138V     432.6mV
1.494ns   457.8mV    1.14V      430.6mV
1.554ns   416.1mV    1.185V     429.9mV
1.644ns   408.4mV    482.8mV    429.7mV
1.774ns   407.3mV    387.5mV    429.7mV
10ns      407.4mV    383.5mV    430mV
[Falling waveform]
R_fixture=50.000Ohm
V_fixture=0
0s        671.2mV    639.4mV    703.8mV
1.263ns   671.2mV    639.4mV    706mV
1.323ns   670.8mV    639.4mV    82.9mV
1.383ns   638.2mV    639.4mV    9.139mV
1.423ns   212.8mV    639.1mV    2.797mV
1.454ns   55.92mV    639.1mV    1.177mV
1.524ns   6.445mV    626.7mV    174.6uV
1.604ns   1.099mV    80.51mV    22.14uV
1.714ns   111.4uV    4.114mV    5.83uV
10ns      426.5nV    3.909uV    270.7nV
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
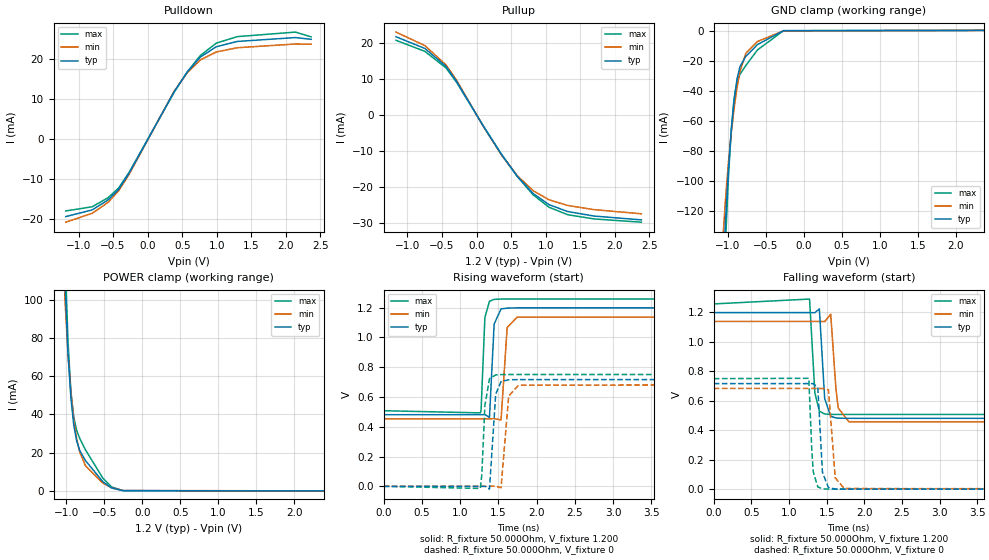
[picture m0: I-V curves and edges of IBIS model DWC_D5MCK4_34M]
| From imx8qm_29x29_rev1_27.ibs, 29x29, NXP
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[Model] DWC_D5MCK4_34M
Model_type   I/O
Polarity   Non-Inverting
Enable   Active-High
C_comp   1.264pF   1.181pF   1.367pF
C_comp_pullup   284.419fF   263.792fF   311.358fF
C_comp_pulldown 969.046fF   901.845fF   1.049pF
Vinh = 693.000mV
Vinl = 507.000mV
Vmeas = 600.000mV
Vref = 600.000mV
Rref = 50Ohms
Cref = 0pF
[Model Spec]
Vinh   693.000mV   663.000mV   723.000mV
Vinl   507.000mV   477.000mV   537.000mV
Vmeas   600.000mV   570.000mV   630.000mV
Vref   600.000mV   570.000mV   630.000mV
D_overshoot_ampl_h 0.4 NA   NA
D_overshoot_ampl_l 0.4 NA   NA
D_overshoot_area_l 60.000p NA   NA
D_overshoot_area_h 60.000p NA   NA
[Receiver Thresholds]
Vcross_low = 480.000mV
Vcross_high = 720.000mV
Vdiff_ac = 136.000mV
Vdiff_dc = 136.000mV
Tdiffslew_ac = 10.000ns
[Temperature Range]   25.000   125.000   -40.000
[Voltage Range]   1.200V   1.140V   1.260V
[GND Clamp Reference]   0.00V   0.00V   0.00V
[C Comp Corner]
| variable   typ   min   max
C_comp 1.264pF   1.367pF   1.181pF
C_comp_pullup 284.419fF   311.358fF   263.792fF
C_comp_pulldown 969.046fF   1.049pF   901.845fF
[Pulldown Reference]   0.00V   0.00V   0.00V
[POWER Clamp Reference]   1.200V   1.140V   1.260V
[Pullup Reference]   1.200V   1.140V   1.260V
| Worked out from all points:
|   slope of the pulldown table from 0 to 0.18 V, typ, clamps not added: 31.8 ohm
|   slope of the pullup table from 0 to 0.18 V, typ, clamps not added: 31.9 ohm
|   GND clamp passes 1 mA (typ) near -0.36 V on its own axis
|   POWER clamp passes 1 mA (typ) near -0.38 V on its own axis
|   rising waveform, R_fixture 50.000Ohm, V_fixture 1.200: 20-80 % time 37.2ps typ, 43.2ps min, 34.2ps max; typ from 0.481 V to 1.2 V
|   rising waveform, R_fixture 50.000Ohm, V_fixture 0: 20-80 % time 47.7ps typ, 56.6ps min, 43.8ps max; typ from 0 V to 0.717 V
|   falling waveform, R_fixture 50.000Ohm, V_fixture 1.200: 20-80 % time 50.4ps typ, 57.6ps min, 46.1ps max; typ from 1.2 V to 0.481 V
|   falling waveform, R_fixture 50.000Ohm, V_fixture 0: 20-80 % time 41.8ps typ, 50ps min, 36.8ps max; typ from 0.717 V to 0 V
[GND Clamp]
-1.184V   -342.5mA   -256.9mA   -430.7mA
-1.069V   -170mA     -142.2mA   -199.2mA
-1.031V   -127.6mA   -113.2mA   -142.7mA
-992.7mV  -93.59mA   -88.73mA   -98.99mA
-954.5mV  -66.78mA   -68.42mA   -66.61mA
-916.4mV  -46.35mA   -51.62mA   -45.02mA
-878.2mV  -32.2mA    -37.95mA   -34mA
-840mV    -24.05mA   -27.38mA   -29.18mA
-763.6mV  -17.22mA   -15.2mA    -23.29mA
-610.9mV  -9.369mA   -7.283mA   -12.96mA
-267.3mV  -89.24uA   -208uA     -59.9uA
2.367V    136.8uA    111.6uA    170.5uA
[Power Clamp]
-1.167V   370mA      273mA      475mA
-1.015V   108.4mA    99.12mA    123mA
-976.4mV  71.8mA     71.42mA    77.9mA
-938.2mV  48.37mA    51.03mA    51.81mA
-900mV    34.2mA     36.79mA    38.28mA
-861.8mV  25.98mA    27.04mA    31.54mA
-823.6mV  21.25mA    20.48mA    27.58mA
-747.3mV  15.81mA    13.12mA    21.46mA
-518.2mV  4.768mA    4.041mA    6.612mA
-403.6mV  1.471mA    1.528mA    1.982mA
-250.9mV  45.63uA    138.2uA    40.3uA
2.384V    -68.4uA    -58.87uA   -80.92uA
[Pulldown]
-1.184V   -19.4mA    -20.8mA    -18mA
-801.8mV  -17.73mA   -18.59mA   -16.96mA
-572.7mV  -15.26mA   -15.86mA   -14.7mA
-420mV    -12.62mA   -12.99mA   -12.28mA
-267.3mV  -8.551mA   -8.851mA   -8.351mA
381.8mV   11.65mA    11.8mA     11.55mA
572.7mV   16.61mA    16.47mA    16.66mA
763.6mV   20.38mA    19.67mA    20.77mA
992.7mV   22.94mA    21.63mA    23.84mA
1.298V    24.27mA    22.7mA     25.47mA
2.138V    25.23mA    23.63mA    26.6mA
2.367V    24.8mA     23.6mA     25.4mA
[Pullup]
-1.167V   21.8mA     23.09mA    20.81mA
-747.3mV  18.52mA    19.32mA    17.72mA
-441.8mV  13.53mA    13.94mA    13.1mA
-289.1mV  9.344mA    9.662mA    9.11mA
92.7mV    -2.936mA   -3.019mA   -2.889mA
360mV     -10.99mA   -11.12mA   -10.92mA
589.1mV   -17.07mA   -16.9mA    -17.13mA
818.2mV   -21.84mA   -21.07mA   -22.22mA
1.047V    -24.95mA   -23.59mA   -25.67mA
1.315V    -26.86mA   -25.17mA   -27.74mA
1.696V    -28.12mA   -26.34mA   -28.93mA
2.384V    -29.2mA    -27.5mA    -29.84mA
[Ramp]
R_load=50.000Ohm
dV/dt_r   430.380mV/43.000ps  410.819mV/51.000ps  450.330mV/40.000ps
dV/dt_f   430.380mV/46.500ps  410.819mV/54.500ps  450.330mV/42.000ps
[Rising waveform]
R_fixture=50.000Ohm
V_fixture=1.200
V_fixture_min=1.140
V_fixture_max=1.260
0s        481.2mV    453.7mV    507.9mV
1.263ns   481.2mV    453.7mV    493.5mV
1.273ns   481.1mV    453.7mV    507.8mV
1.323ns   482mV      453.7mV    1.135V
1.383ns   463.6mV    453.6mV    1.243V
1.444ns   1.09V      455mV      1.256V
1.534ns   1.192V     445.6mV    1.258V
1.614ns   1.197V     1.067V     1.258V
1.744ns   1.199V     1.136V     1.258V
10ns      1.199V     1.139V     1.258V
[Rising waveform]
R_fixture=50.000Ohm
V_fixture=0
0s        168.4nV    4.199uV    19.87nV
1.263ns   -5.672uV   3.087uV    -14.14mV
1.283ns   -87.45uV   5.847uV    80.13mV
1.323ns   717.7uV    19.35uV    542.9mV
1.383ns   -19.03mV   -102.7uV   722.8mV
1.464ns   619.1mV    1.652mV    748.3mV
1.534ns   703.6mV    -9.706mV   750.7mV
1.634ns   715.8mV    606.8mV    751.1mV
1.764ns   717.1mV    679.8mV    751.1mV
10ns      717.1mV    684.1mV    750.8mV
[Falling waveform]
R_fixture=50.000Ohm
V_fixture=1.200
V_fixture_min=1.140
V_fixture_max=1.260
0s        1.199V     1.139V     1.258V
1.273ns   1.199V     1.139V     1.291V
1.343ns   1.198V     1.139V     656.5mV
1.403ns   1.224V     1.139V     529.5mV
1.474ns   614.7mV    1.138V     510.5mV
1.554ns   495mV      1.188V     507.8mV
1.624ns   483.8mV    677.8mV    507.5mV
1.654ns   482.4mV    551.5mV    507.5mV
1.794ns   481mV      458mV      507.5mV
10ns      481.1mV    453.7mV    507.8mV
[Falling waveform]
R_fixture=50.000Ohm
V_fixture=0
0s        717mV      684.1mV    750.7mV
1.263ns   717mV      684.1mV    753mV
1.303ns   716.9mV    684.1mV    259.7mV
1.323ns   716.6mV    684.1mV    116.1mV
1.383ns   689.7mV    684.1mV    15.17mV
1.444ns   115mV      683.6mV    2.713mV
1.524ns   10.26mV    675.3mV    323.1uV
1.614ns   1.426mV    76.69mV    30.89uV
1.734ns   122uV      4.34mV     5.913uV
10ns      304.4nV    4.365uV    217.4nV
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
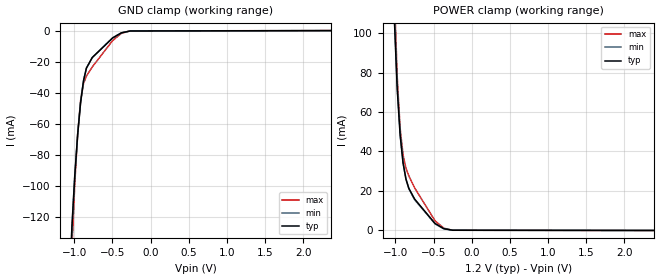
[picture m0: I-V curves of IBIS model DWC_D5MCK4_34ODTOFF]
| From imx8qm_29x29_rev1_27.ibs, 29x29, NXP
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[Model] DWC_D5MCK4_34ODTOFF
Model_type   Input
Polarity   Non-Inverting
Enable   Active-High
C_comp   1.264pF   1.181pF   1.264pF
C_comp_power_clamp   284.419fF   263.792fF   286.390fF
C_comp_gnd_clamp 969.046fF   901.845fF   969.654fF
Vinh = 910.000mV
Vinl = 724.000mV
[Model Spec]
D_overshoot_ampl_h 0.4 NA   NA
D_overshoot_ampl_l 0.4 NA   NA
D_overshoot_area_l 60.000p NA   NA
D_overshoot_area_h 60.000p NA   NA
[Receiver Thresholds]
Vcross_low = 697.000mV
Vcross_high = 937.000mV
Vdiff_ac = 136.000mV
Vdiff_dc = 136.000mV
Tdiffslew_ac = 10.000ns
[Temperature Range]   25.000   125.000   -40.000
[Voltage Range]   1.200V   1.140V   1.260V
[GND Clamp Reference]   0.00V   0.00V   0.00V
[C Comp Corner]
| variable   typ   min   max
C_comp 1.264pF   1.264pF   1.181pF
C_comp_pullup 284.419fF   286.390fF   263.792fF
C_comp_pulldown 969.046fF   969.654fF   901.845fF
[POWER Clamp Reference]   1.200V   1.140V   1.260V
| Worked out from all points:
|   GND clamp passes 1 mA (typ) near -0.36 V on its own axis
|   POWER clamp passes 1 mA (typ) near -0.38 V on its own axis
[GND Clamp]
-1.184V   -342.5mA   -342.4mA   -430.7mA
-1.031V   -127.6mA   -127.6mA   -142.7mA
-992.7mV  -93.59mA   -93.52mA   -98.99mA
-954.5mV  -66.78mA   -66.74mA   -66.61mA
-916.4mV  -46.35mA   -46.32mA   -45.02mA
-878.2mV  -32.2mA    -32.19mA   -34mA
-840mV    -24.05mA   -24.05mA   -29.18mA
-763.6mV  -17.22mA   -17.22mA   -23.29mA
-496.4mV  -4.559mA   -4.559mA   -6.292mA
-381.8mV  -1.286mA   -1.286mA   -1.614mA
-267.3mV  -89.24uA   -89.23uA   -59.9uA
2.367V    136.8uA    136.8uA    170.5uA
[Power Clamp]
-1.167V   370mA      370mA      475mA
-1.015V   108.4mA    109.7mA    123mA
-976.4mV  71.8mA     73.01mA    77.9mA
-938.2mV  48.37mA    49.08mA    51.81mA
-900mV    34.2mA     34.51mA    38.28mA
-861.8mV  25.98mA    25.98mA    31.54mA
-823.6mV  21.25mA    21.04mA    27.58mA
-747.3mV  15.81mA    15.45mA    21.46mA
-480mV    3.453mA    3.248mA    4.784mA
-365.5mV  823.4uA    745.6uA    1.073mA
-250.9mV  45.63uA    42.16uA    40.3uA
2.384V    -68.4uA    -71.86uA   -80.92uA
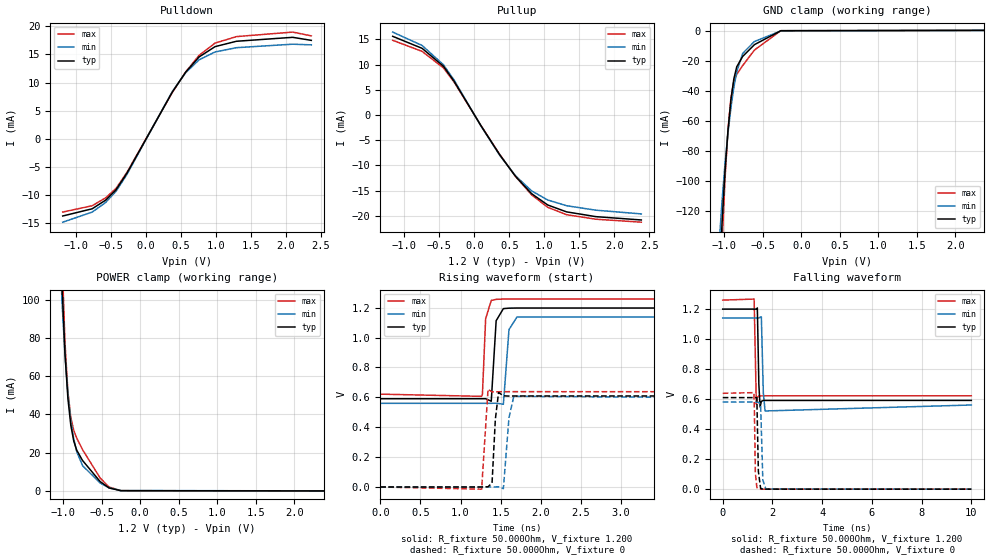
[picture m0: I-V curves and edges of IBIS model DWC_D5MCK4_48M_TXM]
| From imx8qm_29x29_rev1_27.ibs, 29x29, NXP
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[Model] DWC_D5MCK4_48M_TXM
Model_type   I/O
Polarity   Non-Inverting
Enable   Active-High
C_comp   1.264pF   1.181pF   1.367pF
C_comp_pullup   284.419fF   263.792fF   311.358fF
C_comp_pulldown 969.046fF   901.841fF   1.049pF
Vinh = 693.000mV
Vinl = 507.000mV
Vmeas = 600.000mV
Vref = 600.000mV
Rref = 50Ohms
Cref = 0pF
[Model Spec]
Vinh   693.000mV   663.000mV   723.000mV
Vinl   507.000mV   477.000mV   537.000mV
Vmeas   600.000mV   570.000mV   630.000mV
Vref   600.000mV   570.000mV   630.000mV
D_overshoot_ampl_h 0.4 NA   NA
D_overshoot_ampl_l 0.4 NA   NA
D_overshoot_area_l 60.000p NA   NA
D_overshoot_area_h 60.000p NA   NA
[Receiver Thresholds]
Vcross_low = 480.000mV
Vcross_high = 720.000mV
Vdiff_ac = 136.000mV
Vdiff_dc = 136.000mV
Tdiffslew_ac = 10.000ns
[Temperature Range]   25.000   125.000   -40.000
[Voltage Range]   1.200V   1.140V   1.260V
[GND Clamp Reference]   0.00V   0.00V   0.00V
[C Comp Corner]
| variable   typ   min   max
C_comp 1.264pF   1.367pF   1.181pF
C_comp_pullup 284.419fF   311.358fF   263.792fF
C_comp_pulldown 969.046fF   1.049pF   901.841fF
[Pulldown Reference]   0.00V   0.00V   0.00V
[POWER Clamp Reference]   1.200V   1.140V   1.260V
[Pullup Reference]   1.200V   1.140V   1.260V
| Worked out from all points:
|   slope of the pulldown table from 0 to 0.18 V, typ, clamps not added: 44.5 ohm
|   slope of the pullup table from 0 to 0.18 V, typ, clamps not added: 44.6 ohm
|   GND clamp passes 1 mA (typ) near -0.36 V on its own axis
|   POWER clamp passes 1 mA (typ) near -0.38 V on its own axis
|   rising waveform, R_fixture 50.000Ohm, V_fixture 1.200: 20-80 % time 36.2ps typ, 43.7ps min, 30.9ps max; typ from 0.591 V to 1.2 V
|   rising waveform, R_fixture 50.000Ohm, V_fixture 0: 20-80 % time 35.3ps typ, 46.8ps min, 28.1ps max; typ from 0 V to 0.609 V
|   falling waveform, R_fixture 50.000Ohm, V_fixture 1.200: 20-80 % time 39.2ps typ, 50.2ps min, 31.8ps max; typ from 1.2 V to 0.591 V
|   falling waveform, R_fixture 50.000Ohm, V_fixture 0: 20-80 % time 41.7ps typ, 51.1ps min, 34.8ps max; typ from 0.609 V to 0 V
[GND Clamp]
-1.184V   -342.5mA   -256.9mA   -430.7mA
-1.069V   -170mA     -142.2mA   -199.2mA
-1.031V   -127.6mA   -113.2mA   -142.7mA
-992.7mV  -93.59mA   -88.73mA   -98.99mA
-954.5mV  -66.78mA   -68.42mA   -66.61mA
-916.4mV  -46.35mA   -51.62mA   -45.02mA
-878.2mV  -32.2mA    -37.95mA   -34mA
-840mV    -24.05mA   -27.38mA   -29.18mA
-763.6mV  -17.22mA   -15.2mA    -23.29mA
-610.9mV  -9.369mA   -7.283mA   -12.96mA
-267.3mV  -89.24uA   -208uA     -59.9uA
2.367V    136.8uA    111.6uA    170.5uA
[Power Clamp]
-1.167V   370mA      273mA      475mA
-1.015V   108.4mA    99.12mA    123mA
-976.4mV  71.8mA     71.42mA    77.9mA
-938.2mV  48.37mA    51.03mA    51.81mA
-900mV    34.2mA     36.79mA    38.28mA
-861.8mV  25.98mA    27.04mA    31.54mA
-823.6mV  21.25mA    20.48mA    27.58mA
-747.3mV  15.81mA    13.12mA    21.46mA
-518.2mV  4.768mA    4.041mA    6.612mA
-403.6mV  1.471mA    1.528mA    1.982mA
-250.9mV  45.63uA    138.2uA    40.3uA
2.384V    -68.4uA    -58.87uA   -80.92uA
[Pulldown]
-1.184V   -13.7mA    -14.8mA    -13mA
-763.6mV  -12.42mA   -13.01mA   -11.88mA
-572.7mV  -10.9mA    -11.32mA   -10.49mA
-420mV    -9.006mA   -9.275mA   -8.766mA
-267.3mV  -6.103mA   -6.321mA   -5.966mA
381.8mV   8.318mA    8.43mA     8.253mA
572.7mV   11.86mA    11.76mA    11.89mA
763.6mV   14.55mA    14.04mA    14.83mA
992.7mV   16.39mA    15.44mA    17.02mA
1.298V    17.34mA    16.2mA     18.17mA
2.1V      18.04mA    16.82mA    18.97mA
2.367V    17.5mA     16.7mA     18.3mA
[Pullup]
-1.167V   15.6mA     16.44mA    14.81mA
-747.3mV  13.22mA    13.79mA    12.62mA
-441.8mV  9.664mA    9.956mA    9.334mA
-289.1mV  6.675mA    6.903mA    6.496mA
92.7mV    -2.098mA   -2.157mA   -2.06mA
360mV     -7.853mA   -7.946mA   -7.784mA
589.1mV   -12.19mA   -12.07mA   -12.21mA
818.2mV   -15.6mA    -15.05mA   -15.83mA
1.047V    -17.83mA   -16.84mA   -18.29mA
1.315V    -19.19mA   -17.97mA   -19.75mA
1.734V    -20.14mA   -18.86mA   -20.65mA
2.384V    -20.8mA    -19.6mA    -21.24mA
[Ramp]
R_load=50.000Ohm
dV/dt_r   365.130mV/36.500ps  347.458mV/46.000ps  382.260mV/30.000ps
dV/dt_f   365.130mV/41.500ps  347.458mV/51.500ps  382.260mV/34.000ps
[Rising waveform]
R_fixture=50.000Ohm
V_fixture=1.200
V_fixture_min=1.140
V_fixture_max=1.260
0s        590.7mV    560.1mV    621.5mV
1.263ns   590.7mV    560.1mV    606.8mV
1.273ns   590.6mV    560.1mV    621.5mV
1.313ns   591mV      560.2mV    1.126V
1.383ns   573.9mV    560mV      1.249V
1.444ns   1.113V     561.3mV    1.256V
1.534ns   1.194V     554mV      1.258V
1.604ns   1.197V     1.054V     1.258V
1.704ns   1.198V     1.138V     1.258V
10ns      1.198V     1.139V     1.258V
[Rising waveform]
R_fixture=50.000Ohm
V_fixture=0
0s        204.3nV    5.107uV    24.05nV
1.263ns   -3.021uV   3.855uV    -14.52mV
1.343ns   1.504mV    8.673uV    654.2mV
1.393ns   27.14mV    -106.1uV   636.4mV
1.434ns   452.9mV    513.1uV    636.6mV
1.474ns   633.1mV    1.399mV    637.5mV
1.534ns   610.3mV    -10.91mV   638mV
1.604ns   608.6mV    464.5mV    638.2mV
1.664ns   609.2mV    607.1mV    638.2mV
10ns      609.4mV    579.5mV    637.8mV
[Falling waveform]
R_fixture=50.000Ohm
V_fixture=1.200
V_fixture_min=1.140
V_fixture_max=1.260
0s        1.198V     1.139V     1.258V
1.263ns   1.198V     1.139V     1.265V
1.353ns   1.198V     1.139V     564.9mV
1.393ns   1.206V     1.139V     609.3mV
1.454ns   696.9mV    1.138V     620mV
1.504ns   546.9mV    1.144V     620.7mV
1.554ns   584.3mV    1.147V     620.8mV
1.634ns   590.4mV    640.8mV    620.9mV
1.704ns   590.4mV    520.3mV    620.9mV
10ns      590.6mV    560.1mV    621.4mV
[Falling waveform]
R_fixture=50.000Ohm
V_fixture=0
0s        609.3mV    579.5mV    637.7mV
1.253ns   609.3mV    579.5mV    642.5mV
1.273ns   609.3mV    579.5mV    541.1mV
1.313ns   609mV      579.5mV    109.8mV
1.373ns   608.7mV    579.5mV    11.39mV
1.434ns   119.5mV    579.1mV    3.032mV
1.524ns   5.685mV    562.3mV    348.1uV
1.614ns   1.377mV    60.74mV    41.16uV
1.734ns   139.4uV    1.617mV    8.042uV
10ns      344.1nV    5.328uV    142.5nV
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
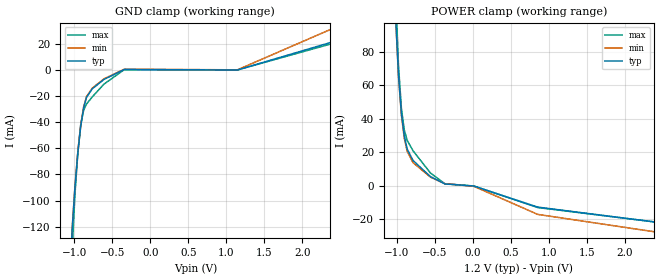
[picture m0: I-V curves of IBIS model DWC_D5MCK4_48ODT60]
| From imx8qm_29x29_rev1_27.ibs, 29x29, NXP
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[Model] DWC_D5MCK4_48ODT60
Model_type   Input
Polarity   Non-Inverting
Enable   Active-High
C_comp   1.348pF   1.271pF   1.374pF
C_comp_power_clamp   335.985fF   329.909fF   346.315fF
C_comp_gnd_clamp 1.002pF   926.265fF   1.019pF
Vinh = 960.000mV
Vinl = 774.000mV
[Model Spec]
D_overshoot_ampl_h 0.4 NA   NA
D_overshoot_ampl_l 0.4 NA   NA
D_overshoot_area_l 60.000p NA   NA
D_overshoot_area_h 60.000p NA   NA
[Receiver Thresholds]
Vcross_low = 747.000mV
Vcross_high = 987.000mV
Vdiff_ac = 136.000mV
Vdiff_dc = 136.000mV
Tdiffslew_ac = 10.000ns
[Temperature Range]   25.000   125.000   -40.000
[Voltage Range]   1.200V   1.140V   1.260V
[GND Clamp Reference]   0.00V   0.00V   0.00V
[C Comp Corner]
| variable   typ   min   max
C_comp 1.348pF   1.374pF   1.271pF
C_comp_pullup 335.985fF   346.315fF   329.909fF
C_comp_pulldown 1.002pF   1.019pF   926.265fF
[POWER Clamp Reference]   1.200V   1.140V   1.260V
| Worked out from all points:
|   GND clamp passes 1 mA (typ) near -0.43 V on its own axis
|   POWER clamp passes 1 mA (typ) near -0.37 V on its own axis
[GND Clamp]
-1.184V   -337.6mA   -336.6mA   -426mA
-1.031V   -123.5mA   -122.6mA   -138.8mA
-992.7mV  -89.64mA   -88.76mA   -95.17mA
-954.5mV  -62.99mA   -62.21mA   -62.91mA
-916.4mV  -42.74mA   -42.01mA   -41.49mA
-878.2mV  -28.78mA   -28.09mA   -30.64mA
-840mV    -20.8mA    -20.16mA   -25.99mA
-763.6mV  -14.32mA   -13.75mA   -20.45mA
-610.9mV  -7.16mA    -6.714mA   -10.77mA
-343.6mV  433.7uA    670.6uA    344.7uA
1.145V    65.57uA    178.2uA    78.74uA
2.367V    21.07mA    31.04mA    19.89mA
[Power Clamp]
-1.167V   361.5mA    358.4mA    466.1mA
-1.015V   102.2mA    101.3mA    116.4mA
-976.4mV  66.14mA    65.36mA    71.85mA
-938.2mV  43.23mA    42.17mA    46.26mA
-900mV    29.57mA    28.32mA    33.24mA
-861.8mV  21.84mA    20.48mA    27.01mA
-785.5mV  15mA       13.7mA     20.84mA
-556.4mV  5.379mA    5.034mA    7.521mA
-365.5mV  940uA      1.097mA    1.059mA
16.4mV    -300.7uA   -473.9uA   -294.9uA
856.4mV   -12.91mA   -17.27mA   -13.18mA
2.384V    -21.73mA   -27.61mA   -21.72mA
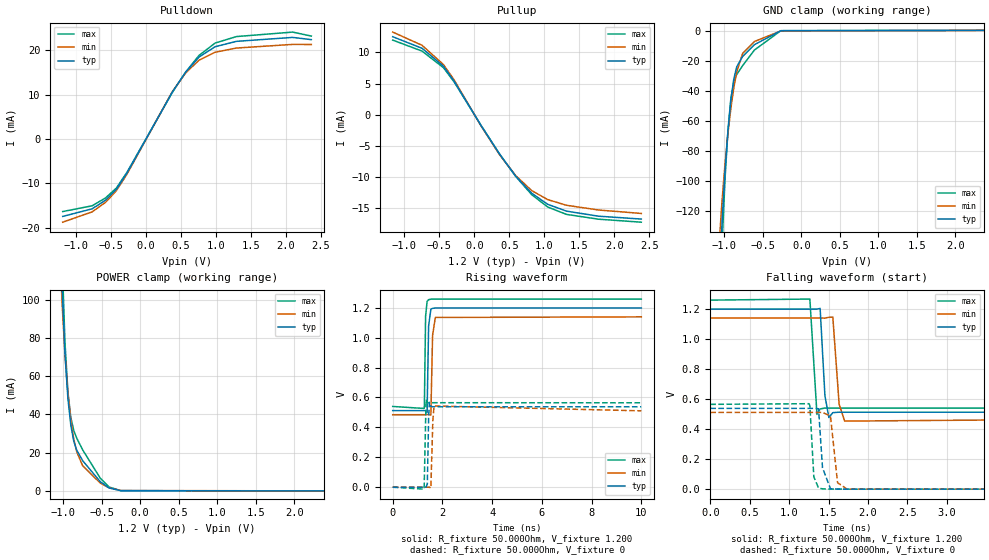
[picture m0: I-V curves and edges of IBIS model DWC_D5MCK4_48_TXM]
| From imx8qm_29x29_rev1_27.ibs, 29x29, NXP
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[Model] DWC_D5MCK4_48_TXM
Model_type   I/O
Polarity   Non-Inverting
Enable   Active-High
C_comp   1.264pF   1.181pF   1.367pF
C_comp_pullup   284.432fF   263.792fF   311.497fF
C_comp_pulldown 969.064fF   901.870fF   1.049pF
Vinh = 960.000mV
Vinl = 774.000mV
Vmeas = 867.000mV
Vref = 867.000mV
Rref = 50Ohms
Cref = 0pF
[Model Spec]
Vinh   960.000mV   917.000mV   1.003V
Vinl   774.000mV   731.000mV   817.000mV
Vmeas   867.000mV   823.000mV   910.000mV
Vref   867.000mV   823.000mV   910.000mV
D_overshoot_ampl_h 0.4 NA   NA
D_overshoot_ampl_l 0.4 NA   NA
D_overshoot_area_l 60.000p NA   NA
D_overshoot_area_h 60.000p NA   NA
[Receiver Thresholds]
Vcross_low = 747.000mV
Vcross_high = 987.000mV
Vdiff_ac = 136.000mV
Vdiff_dc = 136.000mV
Tdiffslew_ac = 10.000ns
[Temperature Range]   25.000   125.000   -40.000
[Voltage Range]   1.200V   1.140V   1.260V
[GND Clamp Reference]   0.00V   0.00V   0.00V
[C Comp Corner]
| variable   typ   min   max
C_comp 1.264pF   1.367pF   1.181pF
C_comp_pullup 284.432fF   311.497fF   263.792fF
C_comp_pulldown 969.064fF   1.049pF   901.870fF
[Pulldown Reference]   0.00V   0.00V   0.00V
[POWER Clamp Reference]   1.200V   1.140V   1.260V
[Pullup Reference]   1.200V   1.140V   1.260V
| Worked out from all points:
|   slope of the pulldown table from 0 to 0.18 V, typ, clamps not added: 35.1 ohm
|   slope of the pullup table from 0 to 0.18 V, typ, clamps not added: 55.5 ohm
|   GND clamp passes 1 mA (typ) near -0.36 V on its own axis
|   POWER clamp passes 1 mA (typ) near -0.38 V on its own axis
|   rising waveform, R_fixture 50.000Ohm, V_fixture 1.200: 20-80 % time 39.5ps typ, 48ps min, 33.7ps max; typ from 0.512 V to 1.2 V
|   rising waveform, R_fixture 50.000Ohm, V_fixture 0: 20-80 % time 35.5ps typ, 48.7ps min, 27.9ps max; typ from 0 V to 0.538 V
|   falling waveform, R_fixture 50.000Ohm, V_fixture 1.200: 20-80 % time 38.2ps typ, 48.1ps min, 31.6ps max; typ from 1.2 V to 0.512 V
|   falling waveform, R_fixture 50.000Ohm, V_fixture 0: 20-80 % time 39.3ps typ, 49.5ps min, 32.2ps max; typ from 0.538 V to 0 V
[GND Clamp]
-1.184V   -342.5mA   -256.9mA   -430.7mA
-1.069V   -170mA     -142.2mA   -199.2mA
-1.031V   -127.6mA   -113.2mA   -142.7mA
-992.7mV  -93.59mA   -88.73mA   -98.99mA
-954.5mV  -66.78mA   -68.42mA   -66.61mA
-916.4mV  -46.35mA   -51.62mA   -45.02mA
-878.2mV  -32.2mA    -37.95mA   -34mA
-840mV    -24.05mA   -27.38mA   -29.18mA
-763.6mV  -17.22mA   -15.2mA    -23.29mA
-610.9mV  -9.369mA   -7.283mA   -12.96mA
-267.3mV  -89.24uA   -208uA     -59.9uA
2.367V    136.8uA    111.6uA    170.5uA
[Power Clamp]
-1.167V   370mA      273mA      475mA
-1.015V   108.4mA    99.12mA    123mA
-976.4mV  71.8mA     71.42mA    77.9mA
-938.2mV  48.37mA    51.03mA    51.81mA
-900mV    34.2mA     36.79mA    38.28mA
-861.8mV  25.98mA    27.04mA    31.54mA
-823.6mV  21.25mA    20.48mA    27.58mA
-747.3mV  15.81mA    13.12mA    21.46mA
-518.2mV  4.768mA    4.041mA    6.612mA
-403.6mV  1.471mA    1.528mA    1.982mA
-250.9mV  45.63uA    138.2uA    40.3uA
2.384V    -68.4uA    -58.87uA   -80.92uA
[Pulldown]
-1.184V   -17.5mA    -18.8mA    -16.4mA
-763.6mV  -15.78mA   -16.47mA   -15.1mA
-572.7mV  -13.84mA   -14.33mA   -13.33mA
-420mV    -11.44mA   -11.74mA   -11.14mA
-267.3mV  -7.752mA   -8mA       -7.576mA
381.8mV   10.57mA    10.67mA    10.48mA
572.7mV   15.06mA    14.89mA    15.11mA
763.6mV   18.48mA    17.77mA    18.84mA
992.7mV   20.8mA     19.55mA    21.62mA
1.298V    22.01mA    20.5mA     23.09mA
2.1V      22.9mA     21.32mA    24.1mA
2.367V    22.4mA     21.3mA     23.2mA
[Pullup]
-1.167V   12.5mA     13.24mA    11.96mA
-747.3mV  10.64mA    11.12mA    10.19mA
-441.8mV  7.776mA    8.032mA    7.539mA
-289.1mV  5.373mA    5.57mA     5.247mA
92.7mV    -1.688mA   -1.741mA   -1.664mA
360mV     -6.32mA    -6.411mA   -6.288mA
589.1mV   -9.812mA   -9.738mA   -9.864mA
818.2mV   -12.56mA   -12.14mA   -12.79mA
1.047V    -14.34mA   -13.58mA   -14.77mA
1.315V    -15.43mA   -14.49mA   -15.95mA
1.773V    -16.24mA   -15.25mA   -16.72mA
2.384V    -16.7mA    -15.8mA    -17.2mA
[Ramp]
R_load=50.000Ohm
dV/dt_r   367.110mV/38.000ps  349.349mV/49.000ps  384.630mV/31.000ps
dV/dt_f   367.110mV/39.000ps  349.349mV/49.500ps  384.630mV/32.500ps
[Rising waveform]
R_fixture=50.000Ohm
V_fixture=1.200
V_fixture_min=1.140
V_fixture_max=1.260
0s        512.2mV    484.8mV    540mV
1.263ns   512.1mV    484.8mV    526.6mV
1.273ns   512.1mV    484.8mV    539.3mV
1.323ns   512.9mV    484.8mV    1.143V
1.383ns   498.6mV    484.7mV    1.242V
1.444ns   1.077V     485.8mV    1.254V
1.534ns   1.19V      482.2mV    1.257V
1.604ns   1.196V     1.015V     1.258V
1.714ns   1.198V     1.135V     1.258V
10ns      1.198V     1.139V     1.258V
[Rising waveform]
R_fixture=50.000Ohm
V_fixture=0
0s        178.6nV    4.466uV    21.06nV
1.263ns   -3.588uV   3.357uV    -13.04mV
1.343ns   1.269mV    6.852uV    587.6mV
1.393ns   22.89mV    -87.84uV   565.4mV
1.444ns   461.4mV    805.1uV    564.1mV
1.474ns   568.2mV    1.129mV    564.4mV
1.534ns   541.4mV    -5.918mV   564.8mV
1.614ns   537.5mV    443.7mV    565mV
1.664ns   537.7mV    543.2mV    565mV
10ns      537.7mV    510.7mV    564.5mV
[Falling waveform]
R_fixture=50.000Ohm
V_fixture=1.200
V_fixture_min=1.140
V_fixture_max=1.260
0s        1.198V     1.139V     1.258V
1.263ns   1.198V     1.139V     1.265V
1.353ns   1.198V     1.139V     497.3mV
1.393ns   1.203V     1.139V     533.9mV
1.454ns   621.8mV    1.138V     539.7mV
1.504ns   476.9mV    1.144V     539.6mV
1.554ns   509.2mV    1.145V     539.5mV
1.634ns   512.3mV    565.7mV    539.5mV
1.704ns   512mV      453mV      539.5mV
10ns      512.1mV    484.7mV    539.9mV
[Falling waveform]
R_fixture=50.000Ohm
V_fixture=0
0s        537.6mV    510.6mV    564.4mV
1.253ns   537.6mV    510.6mV    568.7mV
1.263ns   537.6mV    510.6mV    556.2mV
1.313ns   537.4mV    510.6mV    82.89mV
1.373ns   535.1mV    510.6mV    6.548mV
1.423ns   143.5mV    510.3mV    2.358mV
1.524ns   2.877mV    486.8mV    194uV
1.614ns   862.8uV    43.15mV    22.67uV
1.734ns   83.71uV    386.4uV    6.088uV
10ns      459.2nV    4.637uV    230.6nV
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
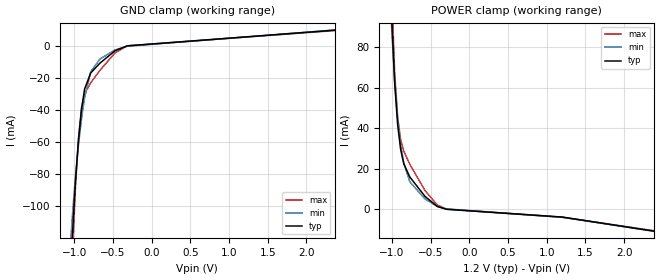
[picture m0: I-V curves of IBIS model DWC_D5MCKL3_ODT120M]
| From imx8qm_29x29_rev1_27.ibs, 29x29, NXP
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[Model] DWC_D5MCKL3_ODT120M
Model_type   Input
Polarity   Non-Inverting
Enable   Active-High
C_comp   1.276pF   1.192pF   1.376pF
C_comp_power_clamp   301.758fF   275.481fF   323.727fF
C_comp_gnd_clamp 964.271fF   900.430fF   1.045pF
Vinh = 735.000mV
Vinl = 465.000mV
[Model Spec]
D_overshoot_ampl_h 0.35 NA   NA
D_overshoot_ampl_l 0.35 NA   NA
D_overshoot_area_l 100.000p NA   NA
D_overshoot_area_h 100.000p NA   NA
[Receiver Thresholds]
Vcross_low = 480.000mV
Vcross_high = 720.000mV
Vdiff_ac = 270.000mV
Vdiff_dc = 200.000mV
Tdiffslew_ac = 10.000ns
[Temperature Range]   25.000   125.000   -40.000
[Voltage Range]   1.200V   1.140V   1.300V
[GND Clamp Reference]   0.00V   0.00V   0.00V
[C Comp Corner]
| variable   typ   min   max
C_comp 1.276pF   1.376pF   1.192pF
C_comp_pullup 301.758fF   323.727fF   275.481fF
C_comp_pulldown 964.271fF   1.045pF   900.430fF
[POWER Clamp Reference]   1.200V   1.140V   1.300V
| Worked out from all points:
|   GND clamp passes 1 mA (typ) near -0.38 V on its own axis
|   POWER clamp passes 1 mA (typ) near -0.39 V on its own axis
[GND Clamp]
-1.182V   -335.7mA   -251.3mA   -422.9mA
-1.064V   -160.4mA   -134.9mA   -187.2mA
-1.024V   -118.3mA   -105.9mA   -131.3mA
-984.8mV  -84.83mA   -81.72mA   -88.7mA
-945.5mV  -58.88mA   -61.8mA    -57.92mA
-906.1mV  -39.62mA   -45.49mA   -38.71mA
-866.7mV  -27.08mA   -32.47mA   -29.97mA
-787.9mV  -17.05mA   -16.31mA   -23.19mA
-669.7mV  -10.96mA   -8.364mA   -15.45mA
-472.7mV  -3.175mA   -2.682mA   -4.494mA
-315.2mV  -126.8uA   -344.7uA   -87.65uA
2.364V    9.614mA    9.741mA    9.358mA
[Power Clamp]
-1.164V   359.7mA    265.4mA    462.4mA
-1.006V   96.92mA    90.43mA    109.7mA
-966.7mV  62.81mA    63.8mA     68.27mA
-927.3mV  41.78mA    44.77mA    45.59mA
-887.9mV  29.48mA    31.79mA    34.38mA
-848.5mV  22.59mA    23.1mA     28.83mA
-769.7mV  16.02mA    13.65mA    22.28mA
-572.7mV  6.416mA    5.167mA    9.279mA
-415.1mV  1.511mA    1.548mA    2.246mA
-297mV    104.7uA    292.1uA    155.5uA
1.2V      -3.74mA    -3.819mA   -3.843mA
2.382V    -10.67mA   -10.76mA   -10.46mA
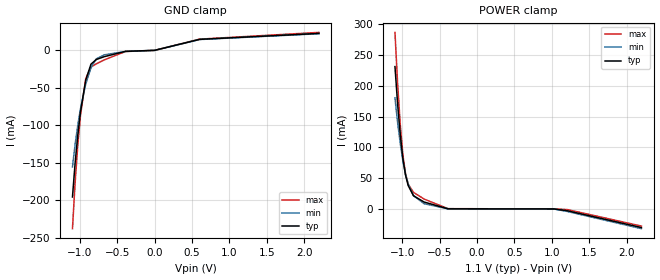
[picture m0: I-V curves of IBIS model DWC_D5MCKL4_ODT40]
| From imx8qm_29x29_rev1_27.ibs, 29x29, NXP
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[Model] DWC_D5MCKL4_ODT40
Model_type   Input
Polarity   Non-Inverting
Enable   Active-High
C_comp   1.266pF   1.196pF   1.355pF
C_comp_power_clamp   320.176fF   293.498fF   346.477fF
C_comp_gnd_clamp 941.141fF   910.824fF   1.029pF
Vinh = 640.000mV
Vinl = 460.000mV
[Model Spec]
D_overshoot_ampl_h 0.35 NA   NA
D_overshoot_ampl_l 0.35 NA   NA
D_overshoot_area_l 800.000p NA   NA
D_overshoot_area_h 800.000p NA   NA
[Receiver Thresholds]
Vcross_low = 455.000mV
Vcross_high = 645.000mV
Vdiff_ac = 140.000mV
Vdiff_dc = 140.000mV
Tdiffslew_ac = 10.000ns
[Temperature Range]   25.000   125.000   -40.000
[Voltage Range]   1.100V   1.060V   1.170V
[GND Clamp Reference]   0.00V   0.00V   0.00V
[C Comp Corner]
| variable   typ   min   max
C_comp 1.266pF   1.355pF   1.196pF
C_comp_pullup 320.176fF   346.477fF   293.498fF
C_comp_pulldown 941.141fF   1.029pF   910.824fF
[POWER Clamp Reference]   1.100V   1.060V   1.170V
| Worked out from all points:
|   GND clamp passes 1 mA (typ) near -0.36 V on its own axis
|   POWER clamp passes 1 mA (typ) near -0.44 V on its own axis
[GND Clamp]
-1.099V   -195.6mA   -155.5mA   -237.8mA
-1.064V   -150.8mA   -125.7mA   -177mA
-1.028V   -113.1mA   -99.99mA   -126.9mA
-992.7mV  -82.61mA   -78.29mA   -87.52mA
-921.8mV  -39.7mA    -45.07mA   -37.8mA
-850.9mV  -18.34mA   -22.92mA   -22.32mA
-780mV    -12.25mA   -11.29mA   -18.03mA
-673.6mV  -8.465mA   -6.035mA   -12.72mA
-390mV    -1.367mA   -1.49mA    -1.581mA
-1.5uV    -25.79uA   -38.82uA   -16.83uA
602.7mV   14.64mA    14.39mA    14.93mA
2.198V    22.53mA    22.13mA    23.91mA
[Power Clamp]
-1.098V   231.3mA    180.6mA    286.9mA
-1.063V   171mA      140.7mA    204.7mA
-1.027V   120.1mA    106.1mA    136.4mA
-991.8mV  81.36mA    77.64mA    87.25mA
-956.4mV  54.83mA    56.07mA    57mA
-920.9mV  37.93mA    40.37mA    40.16mA
-850mV    21.39mA    21.68mA    26.95mA
-708.2mV  11.24mA    8.518mA    16.02mA
-389.1mV  203.2uA    202.9uA    480.9uA
1.029V    -4.931nA   -61.66uA   -674.2pA
1.206V    -2.902mA   -4.083mA   -969.5uA
2.199V    -30.21mA   -32.03mA   -27.87mA
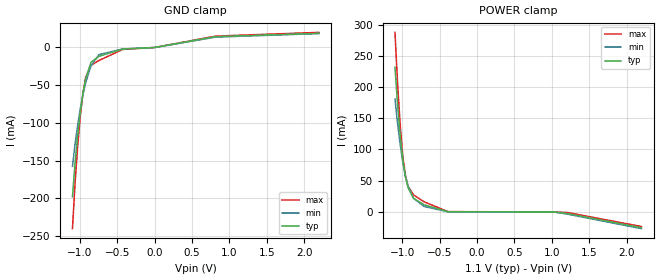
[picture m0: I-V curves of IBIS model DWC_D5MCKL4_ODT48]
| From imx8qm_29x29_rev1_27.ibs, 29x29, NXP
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[Model] DWC_D5MCKL4_ODT48
Model_type   Input
Polarity   Non-Inverting
Enable   Active-High
C_comp   1.275pF   1.202pF   1.366pF
C_comp_power_clamp   319.887fF   295.371fF   344.015fF
C_comp_gnd_clamp 943.606fF   901.225fF   1.037pF
Vinh = 640.000mV
Vinl = 460.000mV
[Model Spec]
D_overshoot_ampl_h 0.35 NA   NA
D_overshoot_ampl_l 0.35 NA   NA
D_overshoot_area_l 800.000p NA   NA
D_overshoot_area_h 800.000p NA   NA
[Receiver Thresholds]
Vcross_low = 455.000mV
Vcross_high = 645.000mV
Vdiff_ac = 140.000mV
Vdiff_dc = 140.000mV
Tdiffslew_ac = 10.000ns
[Temperature Range]   25.000   125.000   -40.000
[Voltage Range]   1.100V   1.060V   1.170V
[GND Clamp Reference]   0.00V   0.00V   0.00V
[C Comp Corner]
| variable   typ   min   max
C_comp 1.275pF   1.366pF   1.202pF
C_comp_pullup 319.887fF   344.015fF   295.371fF
C_comp_pulldown 943.606fF   1.037pF   901.225fF
[POWER Clamp Reference]   1.100V   1.060V   1.170V
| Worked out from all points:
|   GND clamp passes 1 mA (typ) near -0.36 V on its own axis
|   POWER clamp passes 1 mA (typ) near -0.43 V on its own axis
[GND Clamp]
-1.099V   -197.8mA   -157.6mA   -240.1mA
-1.064V   -152.8mA   -127.6mA   -179.2mA
-1.028V   -115mA     -101.8mA   -128.9mA
-992.7mV  -84.45mA   -80.06mA   -89.38mA
-957.3mV  -60.06mA   -61.75mA   -59.77mA
-921.8mV  -41.21mA   -46.52mA   -39.39mA
-850.9mV  -19.59mA   -24.11mA   -23.65mA
-744.5mV  -11.72mA   -9.449mA   -17.19mA
-425.5mV  -1.998mA   -1.914mA   -2.581mA
-1.5uV    -21.49uA   -32.38uA   -13.98uA
815.5mV   14.32mA    13.74mA    15.08mA
2.198V    18.79mA    18.43mA    20mA
[Power Clamp]
-1.098V   231.7mA    181mA      287.4mA
-1.063V   171.5mA    141.1mA    205.1mA
-1.027V   120.6mA    106.6mA    136.8mA
-991.8mV  81.74mA    78.14mA    87.63mA
-956.4mV  55.23mA    56.52mA    57.38mA
-920.9mV  38.31mA    40.8mA     40.52mA
-850mV    21.74mA    22.07mA    27.29mA
-708.2mV  11.51mA    8.835mA    16.29mA
-389.1mV  331.8uA    358.1uA    605uA
1.029V    -4.915nA   -51.38uA   -667.6pA
1.206V    -2.419mA   -3.401mA   -808.7uA
2.199V    -25.19mA   -26.68mA   -23.25mA
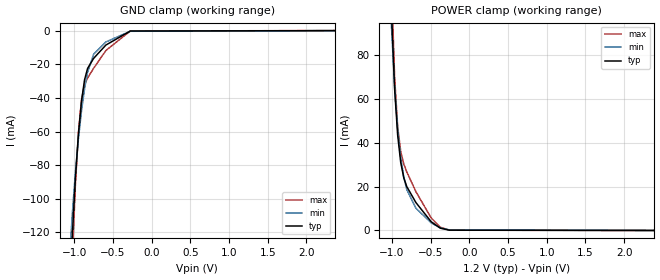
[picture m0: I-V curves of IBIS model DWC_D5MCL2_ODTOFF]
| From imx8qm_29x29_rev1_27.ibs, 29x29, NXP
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[Model] DWC_D5MCL2_ODTOFF
Model_type   Input
Polarity   Non-Inverting
Enable   Active-High
C_comp   1.264pF   1.181pF   1.367pF
C_comp_power_clamp   285.781fF   264.560fF   312.242fF
C_comp_gnd_clamp 969.546fF   903.205fF   1.049pF
Vinh = 820.000mV
Vinl = 380.000mV
[Model Spec]
D_overshoot_ampl_h 0.35 NA   NA
D_overshoot_ampl_l 0.35 NA   NA
D_overshoot_area_l 150.000p NA   NA
D_overshoot_area_h 150.000p NA   NA
[Receiver Thresholds]
Vth = 600.000mV
Vth_min = 588.000mV
Vth_max = 612.000mV
Vinh_ac = 220.000mV
Vinh_dc = 130.000mV
Vinl_ac = -220.000mV
Vinl_dc = -130.000mV
Tslew_ac = 5.000ns
Threshold_sensitivity = 0.5
Reference_supply Power_clamp_ref
[Temperature Range]   25.000   125.000   -40.000
[Voltage Range]   1.200V   1.140V   1.300V
[GND Clamp Reference]   0.00V   0.00V   0.00V
[C Comp Corner]
| variable   typ   min   max
C_comp 1.264pF   1.367pF   1.181pF
C_comp_pullup 285.781fF   312.242fF   264.560fF
C_comp_pulldown 969.546fF   1.049pF   903.205fF
[POWER Clamp Reference]   1.200V   1.140V   1.300V
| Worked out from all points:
|   GND clamp passes 1 mA (typ) near -0.36 V on its own axis
|   POWER clamp passes 1 mA (typ) near -0.38 V on its own axis
[GND Clamp]
-1.182V   -339.3mA   -254.8mA   -426.6mA
-1.064V   -163.5mA   -137.8mA   -190.4mA
-1.024V   -121.1mA   -108.6mA   -134.3mA
-984.8mV  -87.5mA    -84.22mA   -91.46mA
-945.5mV  -61.36mA   -64.12mA   -60.5mA
-906.1mV  -41.91mA   -47.62mA   -41.1mA
-866.7mV  -29.17mA   -34.43mA   -32.17mA
-827.3mV  -22.35mA   -24.56mA   -28.07mA
-748.5mV  -16.34mA   -13.87mA   -22.22mA
-590.9mV  -8.454mA   -6.602mA   -11.71mA
-275.8mV  -116.4uA   -248.8uA   -84.78uA
2.364V    136.6uA    111.3uA    170.2uA
[Power Clamp]
-1.164V   362.5mA    268.1mA    465.2mA
-1.006V   98.99mA    92.43mA    111.8mA
-966.7mV  64.74mA    65.63mA    70.25mA
-927.3mV  43.55mA    46.45mA    47.41mA
-887.9mV  31.08mA    33.31mA    36.05mA
-848.5mV  24.04mA    24.48mA    30.35mA
-809.1mV  19.97mA    18.62mA    26.67mA
-690.9mV  12.66mA    10.09mA    17.63mA
-493.9mV  3.911mA    3.404mA    5.643mA
-375.8mV  976.4uA    1.116mA    1.399mA
-257.6mV  56.8uA     160.4uA    65.6uA
2.382V    -68.29uA   -58.74uA   -77.9uA
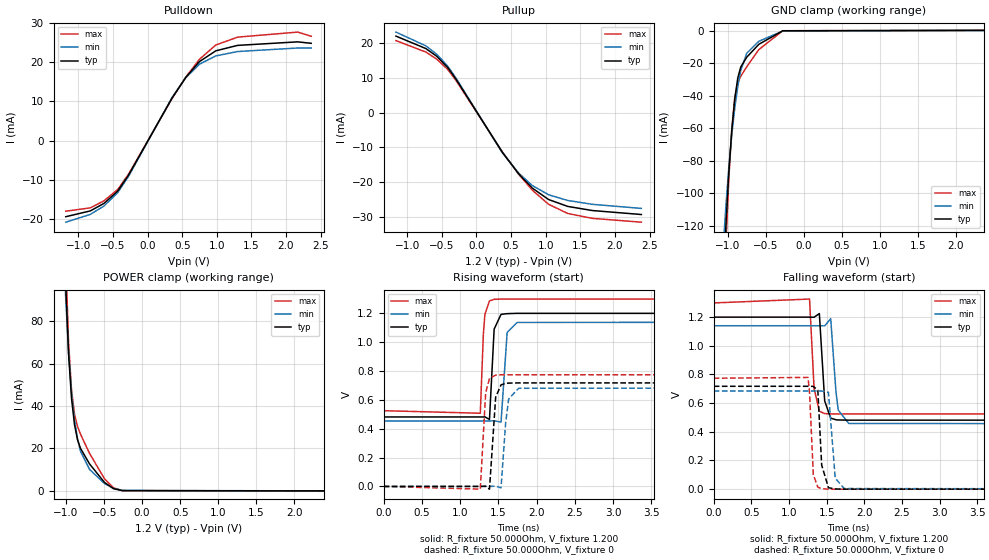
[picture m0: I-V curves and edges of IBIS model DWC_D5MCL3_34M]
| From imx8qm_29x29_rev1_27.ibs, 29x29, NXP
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[Model] DWC_D5MCL3_34M
Model_type   I/O
Polarity   Non-Inverting
Enable   Active-High
C_comp   1.264pF   1.181pF   1.367pF
C_comp_pullup   284.419fF   261.977fF   311.358fF
C_comp_pulldown 969.046fF   903.001fF   1.049pF
Vinh = 735.000mV
Vinl = 465.000mV
Vmeas = 600.000mV
Vref = 600.000mV
Rref = 50Ohms
Cref = 5pF
[Model Spec]
Vinh   735.000mV   705.000mV   785.000mV
Vinl   465.000mV   435.000mV   515.000mV
Vmeas   600.000mV   570.000mV   650.000mV
Vref   600.000mV   570.000mV   650.000mV
D_overshoot_ampl_h 0.35 NA   NA
D_overshoot_ampl_l 0.35 NA   NA
D_overshoot_area_l 100.000p NA   NA
D_overshoot_area_h 100.000p NA   NA
[Receiver Thresholds]
Vth = 600.000mV
Vth_min = 588.000mV
Vth_max = 612.000mV
Vinh_ac = 135.000mV
Vinh_dc = 100.000mV
Vinl_ac = -135.000mV
Vinl_dc = -100.000mV
Tslew_ac = 5.000ns
Reference_supply Pullup_ref
[Temperature Range]   25.000   125.000   -40.000
[Voltage Range]   1.200V   1.140V   1.300V
[GND Clamp Reference]   0.00V   0.00V   0.00V
[C Comp Corner]
| variable   typ   min   max
C_comp 1.264pF   1.367pF   1.181pF
C_comp_pullup 284.419fF   311.358fF   261.977fF
C_comp_pulldown 969.046fF   1.049pF   903.001fF
[Pulldown Reference]   0.00V   0.00V   0.00V
[POWER Clamp Reference]   1.200V   1.140V   1.300V
[Pullup Reference]   1.200V   1.140V   1.300V
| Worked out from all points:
|   slope of the pulldown table from 0 to 0.18 V, typ, clamps not added: 31.8 ohm
|   slope of the pullup table from 0 to 0.18 V, typ, clamps not added: 31.9 ohm
|   GND clamp passes 1 mA (typ) near -0.36 V on its own axis
|   POWER clamp passes 1 mA (typ) near -0.38 V on its own axis
|   rising waveform, R_fixture 50.000Ohm, V_fixture 1.200: 20-80 % time 37.1ps typ, 43.2ps min, 34.3ps max; typ from 0.481 V to 1.2 V
|   rising waveform, R_fixture 50.000Ohm, V_fixture 0: 20-80 % time 47.7ps typ, 56.6ps min, 43.2ps max; typ from 0 V to 0.717 V
|   falling waveform, R_fixture 50.000Ohm, V_fixture 1.200: 20-80 % time 50.4ps typ, 57.7ps min, 46ps max; typ from 1.2 V to 0.481 V
|   falling waveform, R_fixture 50.000Ohm, V_fixture 0: 20-80 % time 41.7ps typ, 49.9ps min, 36ps max; typ from 0.717 V to 0 V
[GND Clamp]
-1.182V   -339.3mA   -254.8mA   -426.6mA
-1.064V   -163.5mA   -137.8mA   -190.4mA
-1.024V   -121.1mA   -108.6mA   -134.3mA
-984.8mV  -87.5mA    -84.22mA   -91.46mA
-945.5mV  -61.36mA   -64.12mA   -60.5mA
-906.1mV  -41.91mA   -47.62mA   -41.1mA
-866.7mV  -29.17mA   -34.43mA   -32.17mA
-827.3mV  -22.35mA   -24.56mA   -28.07mA
-748.5mV  -16.34mA   -13.87mA   -22.22mA
-590.9mV  -8.454mA   -6.602mA   -11.71mA
-275.8mV  -116.4uA   -248.8uA   -84.78uA
2.364V    136.6uA    111.3uA    170.2uA
[Power Clamp]
-1.164V   362.5mA    268.1mA    465.2mA
-1.006V   98.99mA    92.43mA    111.8mA
-966.7mV  64.74mA    65.63mA    70.25mA
-927.3mV  43.55mA    46.45mA    47.41mA
-887.9mV  31.08mA    33.31mA    36.05mA
-848.5mV  24.04mA    24.48mA    30.35mA
-809.1mV  19.97mA    18.62mA    26.67mA
-690.9mV  12.66mA    10.09mA    17.63mA
-493.9mV  3.911mA    3.404mA    5.643mA
-375.8mV  976.4uA    1.116mA    1.399mA
-257.6mV  56.8uA     160.4uA    65.6uA
2.382V    -68.29uA   -58.74uA   -77.9uA
[Pulldown]
-1.182V   -19.4mA    -20.8mA    -18mA
-827.3mV  -17.92mA   -18.81mA   -17.15mA
-630.3mV  -16.01mA   -16.68mA   -15.35mA
-433.3mV  -12.9mA    -13.29mA   -12.49mA
-275.8mV  -8.812mA   -9.115mA   -8.565mA
354.5mV   10.88mA    11.04mA    10.75mA
551.5mV   16.11mA    16.02mA    16.17mA
748.5mV   20.13mA    19.47mA    20.72mA
984.8mV   22.88mA    21.59mA    24.36mA
1.3V      24.27mA    22.7mA     26.37mA
2.167V    25.17mA    23.6mA     27.66mA
2.364V    24.8mA     23.6mA     26.6mA
[Pullup]
-1.164V   21.9mA     23.05mA    20.61mA
-730.3mV  18.32mA    19.1mA     17.32mA
-572.7mV  16.1mA     16.67mA    15.27mA
-415.1mV  12.89mA    13.27mA    12.34mA
-297mV    9.589mA    9.909mA    9.243mA
372.7mV   -11.36mA   -11.48mA   -11.23mA
609.1mV   -17.54mA   -17.33mA   -17.66mA
806.1mV   -21.63mA   -20.9mA    -22.22mA
1.042V    -24.91mA   -23.55mA   -26.28mA
1.318V    -26.88mA   -25.18mA   -28.9mA
1.673V    -28.06mA   -26.28mA   -30.3mA
2.382V    -29.2mA    -27.45mA   -31.4mA
[Ramp]
R_load=50.000Ohm
dV/dt_r   430.380mV/43.000ps  410.819mV/51.000ps  464.040mV/39.000ps
dV/dt_f   430.380mV/46.500ps  410.819mV/54.500ps  464.040mV/41.500ps
[Rising waveform]
R_fixture=50.000Ohm
V_fixture=1.200
V_fixture_min=1.140
V_fixture_max=1.300
0s        481.2mV    453.7mV    524.6mV
1.263ns   481.2mV    453.7mV    507mV
1.303ns   481.2mV    453.7mV    1.054V
1.323ns   482mV      453.7mV    1.191V
1.383ns   463.6mV    453.6mV    1.285V
1.444ns   1.09V      455mV      1.296V
1.534ns   1.192V     445.5mV    1.298V
1.614ns   1.197V     1.067V     1.298V
1.744ns   1.199V     1.136V     1.298V
10ns      1.199V     1.139V     1.298V
[Rising waveform]
R_fixture=50.000Ohm
V_fixture=0
0s        168.4nV    4.199uV    23.43nV
1.263ns   -5.66uV    3.088uV    -18.82mV
1.333ns   1.287mV    14.46uV    648mV
1.383ns   -19.04mV   -102.6uV   749mV
1.464ns   619mV      1.651mV    771.1mV
1.534ns   703.6mV    -9.729mV   773.2mV
1.594ns   713.8mV    438.9mV    773.5mV
1.634ns   715.8mV    606.8mV    773.5mV
1.764ns   717.1mV    679.8mV    773.6mV
10ns      717.1mV    684.1mV    773.2mV
[Falling waveform]
R_fixture=50.000Ohm
V_fixture=1.200
V_fixture_min=1.140
V_fixture_max=1.300
0s        1.199V     1.139V     1.298V
1.273ns   1.199V     1.139V     1.325V
1.333ns   1.198V     1.139V     702.3mV
1.403ns   1.224V     1.139V     543.2mV
1.474ns   614.7mV    1.138V     526.8mV
1.554ns   495mV      1.188V     524.4mV
1.624ns   483.8mV    677.7mV    524.1mV
1.654ns   482.4mV    551.5mV    524.1mV
1.794ns   481mV      458mV      524.1mV
10ns      481.1mV    453.7mV    524.5mV
[Falling waveform]
R_fixture=50.000Ohm
V_fixture=0
0s        717mV      684.1mV    773.1mV
1.253ns   717mV      684.1mV    778.9mV
1.273ns   717mV      684.1mV    671.3mV
1.323ns   716.6mV    684.1mV    100.7mV
1.383ns   689.5mV    684.1mV    13.73mV
1.434ns   167.8mV    683.7mV    3.271mV
1.524ns   10.23mV    675.3mV    300.2uV
1.614ns   1.417mV    76.67mV    29.79uV
1.734ns   120.3uV    4.339mV    6.623uV
10ns      512.5nV    4.365uV    317.8nV
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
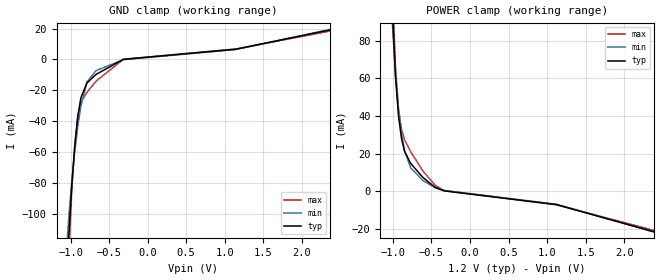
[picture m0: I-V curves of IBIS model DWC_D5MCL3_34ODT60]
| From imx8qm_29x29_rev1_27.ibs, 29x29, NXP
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[Model] DWC_D5MCL3_34ODT60
Model_type   Input
Polarity   Non-Inverting
Enable   Active-High
C_comp   1.288pF   1.215pF   1.384pF
C_comp_power_clamp   316.705fF   301.468fF   337.157fF
C_comp_gnd_clamp 960.969fF   898.238fF   1.040pF
Vinh = 952.000mV
Vinl = 682.000mV
[Model Spec]
D_overshoot_ampl_h 0.35 NA   NA
D_overshoot_ampl_l 0.35 NA   NA
D_overshoot_area_l 100.000p NA   NA
D_overshoot_area_h 100.000p NA   NA
[Receiver Thresholds]
Vth = 817.000mV
Vth_min = 805.000mV
Vth_max = 829.000mV
Vinh_ac = 135.000mV
Vinh_dc = 100.000mV
Vinl_ac = -135.000mV
Vinl_dc = -100.000mV
Tslew_ac = 5.000ns
Reference_supply Power_clamp_ref
[Temperature Range]   25.000   125.000   -40.000
[Voltage Range]   1.200V   1.140V   1.300V
[GND Clamp Reference]   0.00V   0.00V   0.00V
[C Comp Corner]
| variable   typ   min   max
C_comp 1.288pF   1.384pF   1.215pF
C_comp_pullup 316.705fF   337.157fF   301.468fF
C_comp_pulldown 960.969fF   1.040pF   898.238fF
[POWER Clamp Reference]   1.200V   1.140V   1.300V
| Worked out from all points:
|   GND clamp passes 1 mA (typ) near -0.40 V on its own axis
|   POWER clamp passes 1 mA (typ) near -0.40 V on its own axis
[GND Clamp]
-1.182V   -331.9mA   -247.7mA   -419mA
-1.064V   -157.3mA   -131.9mA   -184.1mA
-1.024V   -115.3mA   -103.1mA   -128.4mA
-984.8mV  -82.1mA    -79.15mA   -85.92mA
-945.5mV  -56.36mA   -59.43mA   -55.35mA
-906.1mV  -37.3mA    -43.31mA   -36.34mA
-866.7mV  -24.95mA   -30.47mA   -27.78mA
-787.9mV  -15.29mA   -14.68mA   -21.37mA
-669.7mV  -9.699mA   -7.215mA   -14.13mA
-315.2mV  96.89uA    -165.1uA   163.1uA
1.142V    6.659mA    6.456mA    6.817mA
2.364V    19.18mA    19.48mA    18.42mA
[Power Clamp]
-1.164V   356.7mA    262.6mA    459.5mA
-1.006V   94.77mA    88.34mA    107.5mA
-966.7mV  60.85mA    61.9mA     66.31mA
-927.3mV  40mA       43.05mA    43.81mA
-887.9mV  27.86mA    30.23mA    32.76mA
-848.5mV  21.14mA    21.7mA     27.36mA
-769.7mV  14.86mA    12.55mA    21.09mA
-612.1mV  7.429mA    5.775mA    10.9mA
-454.5mV  2.163mA    2.007mA    3.305mA
-336.4mV  262.4uA    489.6uA    420.7uA
1.121V    -7.047mA   -6.849mA   -7.112mA
2.382V    -21.42mA   -21.57mA   -20.7mA
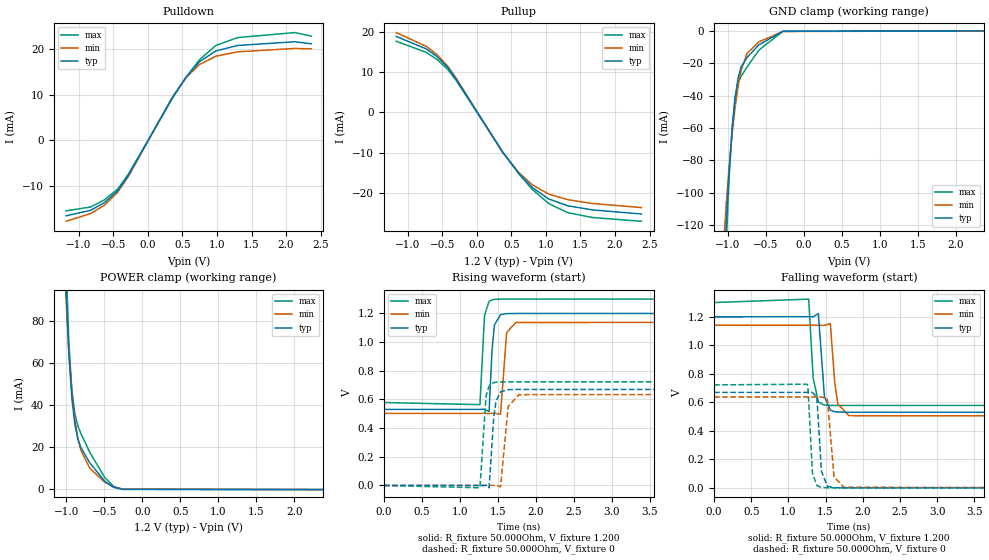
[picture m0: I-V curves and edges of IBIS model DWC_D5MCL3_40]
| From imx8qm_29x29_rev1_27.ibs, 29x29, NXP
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[Model] DWC_D5MCL3_40
Model_type   I/O
Polarity   Non-Inverting
Enable   Active-High
C_comp   1.264pF   1.181pF   1.367pF
C_comp_pullup   284.432fF   261.981fF   311.497fF
C_comp_pulldown 969.059fF   903.013fF   1.049pF
Vinh = 975.000mV
Vinl = 705.000mV
Vmeas = 840.000mV
Vref = 840.000mV
Rref = 50Ohms
Cref = 5pF
[Model Spec]
Vinh   975.000mV   933.000mV   1.045V
Vinl   705.000mV   663.000mV   775.000mV
Vmeas   840.000mV   798.000mV   910.000mV
Vref   840.000mV   798.000mV   910.000mV
D_overshoot_ampl_h 0.35 NA   NA
D_overshoot_ampl_l 0.35 NA   NA
D_overshoot_area_l 100.000p NA   NA
D_overshoot_area_h 100.000p NA   NA
[Receiver Thresholds]
Vth = 840.000mV
Vth_min = 828.000mV
Vth_max = 852.000mV
Vinh_ac = 135.000mV
Vinh_dc = 100.000mV
Vinl_ac = -135.000mV
Vinl_dc = -100.000mV
Tslew_ac = 5.000ns
Reference_supply Pullup_ref
[Temperature Range]   25.000   125.000   -40.000
[Voltage Range]   1.200V   1.140V   1.300V
[GND Clamp Reference]   0.00V   0.00V   0.00V
[C Comp Corner]
| variable   typ   min   max
C_comp 1.264pF   1.367pF   1.181pF
C_comp_pullup 284.432fF   311.497fF   261.981fF
C_comp_pulldown 969.059fF   1.049pF   903.013fF
[Pulldown Reference]   0.00V   0.00V   0.00V
[POWER Clamp Reference]   1.200V   1.140V   1.300V
[Pullup Reference]   1.200V   1.140V   1.300V
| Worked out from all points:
|   slope of the pulldown table from 0 to 0.18 V, typ, clamps not added: 37.1 ohm
|   slope of the pullup table from 0 to 0.18 V, typ, clamps not added: 37.2 ohm
|   GND clamp passes 1 mA (typ) near -0.36 V on its own axis
|   POWER clamp passes 1 mA (typ) near -0.38 V on its own axis
|   rising waveform, R_fixture 50.000Ohm, V_fixture 1.200: 20-80 % time 39.8ps typ, 45.6ps min, 37.3ps max; typ from 0.53 V to 1.2 V
|   rising waveform, R_fixture 50.000Ohm, V_fixture 0: 20-80 % time 52.2ps typ, 61.3ps min, 47.1ps max; typ from 0 V to 0.669 V
|   falling waveform, R_fixture 50.000Ohm, V_fixture 1.200: 20-80 % time 55.4ps typ, 63.8ps min, 50ps max; typ from 1.2 V to 0.53 V
|   falling waveform, R_fixture 50.000Ohm, V_fixture 0: 20-80 % time 44.8ps typ, 53.2ps min, 38.9ps max; typ from 0.669 V to 0 V
[GND Clamp]
-1.182V   -339.3mA   -254.8mA   -426.6mA
-1.064V   -163.5mA   -137.8mA   -190.4mA
-1.024V   -121.1mA   -108.6mA   -134.3mA
-984.8mV  -87.5mA    -84.22mA   -91.46mA
-945.5mV  -61.36mA   -64.12mA   -60.5mA
-906.1mV  -41.91mA   -47.62mA   -41.1mA
-866.7mV  -29.17mA   -34.43mA   -32.17mA
-827.3mV  -22.35mA   -24.56mA   -28.07mA
-748.5mV  -16.34mA   -13.87mA   -22.22mA
-590.9mV  -8.454mA   -6.602mA   -11.71mA
-275.8mV  -116.4uA   -248.8uA   -84.78uA
2.364V    136.6uA    111.3uA    170.2uA
[Power Clamp]
-1.164V   362.5mA    268.1mA    465.2mA
-1.006V   98.99mA    92.43mA    111.8mA
-966.7mV  64.74mA    65.63mA    70.25mA
-927.3mV  43.55mA    46.45mA    47.41mA
-887.9mV  31.08mA    33.31mA    36.05mA
-848.5mV  24.04mA    24.48mA    30.35mA
-809.1mV  19.97mA    18.62mA    26.67mA
-690.9mV  12.66mA    10.09mA    17.63mA
-493.9mV  3.911mA    3.404mA    5.643mA
-375.8mV  976.4uA    1.116mA    1.399mA
-257.6mV  56.8uA     160.4uA    65.6uA
2.382V    -68.29uA   -58.74uA   -77.9uA
[Pulldown]
-1.182V   -16.6mA    -17.8mA    -15.5mA
-827.3mV  -15.38mA   -16.1mA    -14.66mA
-630.3mV  -13.73mA   -14.29mA   -13.12mA
-433.3mV  -11.07mA   -11.38mA   -10.68mA
-275.8mV  -7.56mA    -7.806mA   -7.327mA
354.5mV   9.334mA    9.459mA    9.199mA
551.5mV   13.82mA    13.72mA    13.83mA
748.5mV   17.28mA    16.67mA    17.72mA
984.8mV   19.64mA    18.48mA    20.84mA
1.3V      20.84mA    19.43mA    22.57mA
2.127V    21.65mA    20.18mA    23.67mA
2.364V    21.2mA     20.1mA     22.9mA
[Pullup]
-1.164V   18.8mA     19.75mA    17.61mA
-730.3mV  15.72mA    16.35mA    14.85mA
-572.7mV  13.82mA    14.28mA    13.1mA
-415.1mV  11.07mA    11.37mA    10.58mA
-297mV    8.231mA    8.487mA    7.928mA
372.7mV   -9.747mA   -9.831mA   -9.632mA
609.1mV   -15.06mA   -14.85mA   -15.14mA
806.1mV   -18.57mA   -17.9mA    -19.05mA
1.042V    -21.38mA   -20.17mA   -22.53mA
1.318V    -23.07mA   -21.56mA   -24.77mA
1.673V    -24.08mA   -22.5mA    -25.96mA
2.382V    -25.1mA    -23.5mA    -26.9mA
[Ramp]
R_load=50.000Ohm
dV/dt_r   401.250mV/46.500ps  382.229mV/54.000ps  432.480mV/42.500ps
dV/dt_f   401.280mV/50.500ps  382.229mV/59.000ps  432.510mV/45.500ps
[Rising waveform]
R_fixture=50.000Ohm
V_fixture=1.200
V_fixture_min=1.140
V_fixture_max=1.300
0s        529.9mV    501.6mV    577.8mV
1.263ns   529.9mV    501.6mV    562.9mV
1.323ns   530.7mV    501.6mV    1.185V
1.383ns   515.2mV    501.5mV    1.282V
1.423ns   951mV      502mV      1.293V
1.454ns   1.118V     502.8mV    1.296V
1.534ns   1.19V      496.2mV    1.298V
1.614ns   1.197V     1.065V     1.298V
1.734ns   1.198V     1.135V     1.298V
10ns      1.198V     1.139V     1.298V
[Rising waveform]
R_fixture=50.000Ohm
V_fixture=0
0s        184.5nV    4.611uV    25.69nV
1.263ns   -4.332uV   3.448uV    -16.16mV
1.343ns   1.37mV     7.193uV    622.4mV
1.383ns   -16.68mV   -94.96uV   691.8mV
1.444ns   471.6mV    961.4uV    716.2mV
1.474ns   586.8mV    1.319mV    719.3mV
1.534ns   652mV      -9.097mV   721.3mV
1.634ns   667.3mV    549.7mV    721.8mV
1.774ns   669.1mV    632.3mV    721.9mV
10ns      668.9mV    636.8mV    721.4mV
[Falling waveform]
R_fixture=50.000Ohm
V_fixture=1.200
V_fixture_min=1.140
V_fixture_max=1.300
0s        1.198V     1.139V     1.298V
1.273ns   1.199V     1.139V     1.322V
1.333ns   1.198V     1.139V     768.7mV
1.403ns   1.221V     1.139V     601.4mV
1.484ns   641.5mV    1.138V     580mV
1.564ns   543.9mV    1.151V     577.5mV
1.624ns   533.4mV    733mV      577.2mV
1.664ns   531.3mV    588.5mV    577.2mV
1.814ns   529.6mV    505.6mV    577.2mV
10ns      529.8mV    501.6mV    577.6mV
[Falling waveform]
R_fixture=50.000Ohm
V_fixture=0
0s        668.9mV    636.8mV    721.3mV
1.253ns   668.9mV    636.8mV    726.1mV
1.263ns   668.9mV    636.8mV    706.2mV
1.323ns   668.5mV    636.8mV    105.2mV
1.383ns   635.5mV    636.8mV    15.96mV
1.444ns   117.4mV    636.4mV    3.038mV
1.524ns   11.8mV     623.6mV    385.4uV
1.614ns   1.674mV    78.77mV    41.83uV
1.744ns   123.5uV    4.112mV    7.594uV
10ns      429.2nV    4.823uV    94.92nV
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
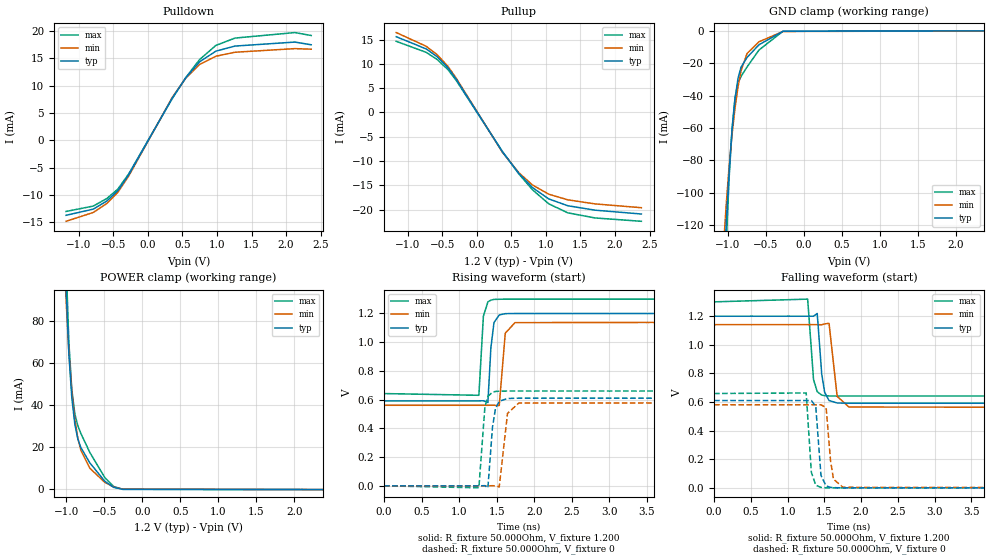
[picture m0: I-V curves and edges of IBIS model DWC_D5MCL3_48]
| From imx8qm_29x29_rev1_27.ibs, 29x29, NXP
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[Model] DWC_D5MCL3_48
Model_type   I/O
Polarity   Non-Inverting
Enable   Active-High
C_comp   1.264pF   1.181pF   1.367pF
C_comp_pullup   284.432fF   261.981fF   311.497fF
C_comp_pulldown 969.059fF   903.017fF   1.049pF
Vinh = 1.002V
Vinl = 732.000mV
Vmeas = 867.000mV
Vref = 867.000mV
Rref = 50Ohms
Cref = 5pF
[Model Spec]
Vinh   1.002V   958.000mV   1.074V
Vinl   732.000mV   688.000mV   804.000mV
Vmeas   867.000mV   823.000mV   939.000mV
Vref   867.000mV   823.000mV   939.000mV
D_overshoot_ampl_h 0.35 NA   NA
D_overshoot_ampl_l 0.35 NA   NA
D_overshoot_area_l 100.000p NA   NA
D_overshoot_area_h 100.000p NA   NA
[Receiver Thresholds]
Vth = 867.000mV
Vth_min = 855.000mV
Vth_max = 879.000mV
Vinh_ac = 135.000mV
Vinh_dc = 100.000mV
Vinl_ac = -135.000mV
Vinl_dc = -100.000mV
Tslew_ac = 5.000ns
Reference_supply Pullup_ref
[Temperature Range]   25.000   125.000   -40.000
[Voltage Range]   1.200V   1.140V   1.300V
[GND Clamp Reference]   0.00V   0.00V   0.00V
[C Comp Corner]
| variable   typ   min   max
C_comp 1.264pF   1.367pF   1.181pF
C_comp_pullup 284.432fF   311.497fF   261.981fF
C_comp_pulldown 969.059fF   1.049pF   903.017fF
[Pulldown Reference]   0.00V   0.00V   0.00V
[POWER Clamp Reference]   1.200V   1.140V   1.300V
[Pullup Reference]   1.200V   1.140V   1.300V
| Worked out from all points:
|   slope of the pulldown table from 0 to 0.18 V, typ, clamps not added: 44.5 ohm
|   slope of the pullup table from 0 to 0.18 V, typ, clamps not added: 44.6 ohm
|   GND clamp passes 1 mA (typ) near -0.36 V on its own axis
|   POWER clamp passes 1 mA (typ) near -0.38 V on its own axis
|   rising waveform, R_fixture 50.000Ohm, V_fixture 1.200: 20-80 % time 43ps typ, 49ps min, 40.6ps max; typ from 0.591 V to 1.2 V
|   rising waveform, R_fixture 50.000Ohm, V_fixture 0: 20-80 % time 57.4ps typ, 66.7ps min, 51.8ps max; typ from 0 V to 0.609 V
|   falling waveform, R_fixture 50.000Ohm, V_fixture 1.200: 20-80 % time 61.5ps typ, 70.4ps min, 55.5ps max; typ from 1.2 V to 0.591 V
|   falling waveform, R_fixture 50.000Ohm, V_fixture 0: 20-80 % time 48.4ps typ, 57ps min, 42.4ps max; typ from 0.609 V to 0 V
[GND Clamp]
-1.182V   -339.3mA   -254.8mA   -426.6mA
-1.064V   -163.5mA   -137.8mA   -190.4mA
-1.024V   -121.1mA   -108.6mA   -134.3mA
-984.8mV  -87.5mA    -84.22mA   -91.46mA
-945.5mV  -61.36mA   -64.12mA   -60.5mA
-906.1mV  -41.91mA   -47.62mA   -41.1mA
-866.7mV  -29.17mA   -34.43mA   -32.17mA
-827.3mV  -22.35mA   -24.56mA   -28.07mA
-748.5mV  -16.34mA   -13.87mA   -22.22mA
-590.9mV  -8.454mA   -6.602mA   -11.71mA
-275.8mV  -116.4uA   -248.8uA   -84.78uA
2.364V    136.6uA    111.3uA    170.2uA
[Power Clamp]
-1.164V   362.5mA    268.1mA    465.2mA
-1.006V   98.99mA    92.43mA    111.8mA
-966.7mV  64.74mA    65.63mA    70.25mA
-927.3mV  43.55mA    46.45mA    47.41mA
-887.9mV  31.08mA    33.31mA    36.05mA
-848.5mV  24.04mA    24.48mA    30.35mA
-809.1mV  19.97mA    18.62mA    26.67mA
-690.9mV  12.66mA    10.09mA    17.63mA
-493.9mV  3.911mA    3.404mA    5.643mA
-375.8mV  976.4uA    1.116mA    1.399mA
-257.6mV  56.8uA     160.4uA    65.6uA
2.382V    -68.29uA   -58.74uA   -77.9uA
[Pulldown]
-1.182V   -13.7mA    -14.8mA    -13mA
-787.9mV  -12.57mA   -13.18mA   -12.01mA
-590.9mV  -11.07mA   -11.52mA   -10.62mA
-433.3mV  -9.208mA   -9.488mA   -8.909mA
-275.8mV  -6.289mA   -6.51mA    -6.115mA
354.5mV   7.765mA    7.888mA    7.678mA
551.5mV   11.5mA     11.44mA    11.54mA
748.5mV   14.38mA    13.9mA     14.79mA
984.8mV   16.34mA    15.41mA    17.39mA
1.261V    17.27mA    16.14mA    18.73mA
2.127V    18mA       16.8mA     19.74mA
2.364V    17.5mA     16.7mA     19.2mA
[Pullup]
-1.164V   15.6mA     16.45mA    14.65mA
-730.3mV  13.08mA    13.63mA    12.38mA
-572.7mV  11.5mA     11.91mA    10.92mA
-415.1mV  9.21mA     9.482mA    8.825mA
-297mV    6.851mA    7.079mA    6.615mA
372.7mV   -8.112mA   -8.2mA     -8.037mA
609.1mV   -12.53mA   -12.38mA   -12.63mA
806.1mV   -15.45mA   -14.92mA   -15.9mA
1.042V    -17.79mA   -16.82mA   -18.8mA
1.318V    -19.2mA    -17.98mA   -20.66mA
1.712V    -20.11mA   -18.82mA   -21.71mA
2.382V    -20.9mA    -19.6mA    -22.4mA
[Ramp]
R_load=50.000Ohm
dV/dt_r   365.130mV/50.500ps  347.458mV/58.000ps  394.470mV/46.500ps
dV/dt_f   365.130mV/56.000ps  347.458mV/64.500ps  394.470mV/49.500ps
[Rising waveform]
R_fixture=50.000Ohm
V_fixture=1.200
V_fixture_min=1.140
V_fixture_max=1.300
0s        590.7mV    560.1mV    641.5mV
1.263ns   590.7mV    560.1mV    629.5mV
1.323ns   591.4mV    560.1mV    1.179V
1.383ns   579.4mV    560mV      1.279V
1.423ns   961.5mV    560.5mV    1.291V
1.464ns   1.135V     560.4mV    1.296V
1.534ns   1.188V     558.1mV    1.297V
1.614ns   1.197V     1.061V     1.298V
1.744ns   1.198V     1.135V     1.298V
10ns      1.198V     1.139V     1.298V
[Rising waveform]
R_fixture=50.000Ohm
V_fixture=0
0s        204.3nV    5.107uV    28.36nV
1.263ns   -2.726uV   3.889uV    -13.82mV
1.343ns   1.201mV    8.614uV    548mV
1.383ns   -14.03mV   -88.22uV   622mV
1.444ns   407.7mV    870.5uV    651.3mV
1.484ns   537.9mV    172uV      656.2mV
1.534ns   587.8mV    -7.402mV   658.3mV
1.644ns   607.4mV    503.6mV    659mV
1.794ns   609.5mV    575.4mV    659.1mV
10ns      609.4mV    579.5mV    658.6mV
[Falling waveform]
R_fixture=50.000Ohm
V_fixture=1.200
V_fixture_min=1.140
V_fixture_max=1.300
0s        1.198V     1.139V     1.298V
1.273ns   1.198V     1.139V     1.317V
1.353ns   1.198V     1.139V     755.1mV
1.403ns   1.217V     1.139V     671.2mV
1.464ns   795.2mV    1.138V     647.4mV
1.504ns   666.9mV    1.144V     643.3mV
1.564ns   609.4mV    1.148V     641.3mV
1.674ns   592.3mV    638.3mV    640.8mV
1.834ns   590.4mV    563.9mV    640.8mV
10ns      590.6mV    560.1mV    641.3mV
[Falling waveform]
R_fixture=50.000Ohm
V_fixture=0
0s        609.3mV    579.5mV    658.4mV
1.253ns   609.3mV    579.5mV    662.2mV
1.323ns   609mV      579.5mV    108.7mV
1.383ns   569.1mV    579.5mV    18.69mV
1.454ns   86.42mV    579.5mV    2.973mV
1.524ns   13.63mV    561mV      525.4uV
1.584ns   3.702mV    190.8mV    123.2uV
1.624ns   1.645mV    60.17mV    49.62uV
1.754ns   129uV      3.941mV    8.808uV
10ns      587.4nV    5.418uV    325.9nV
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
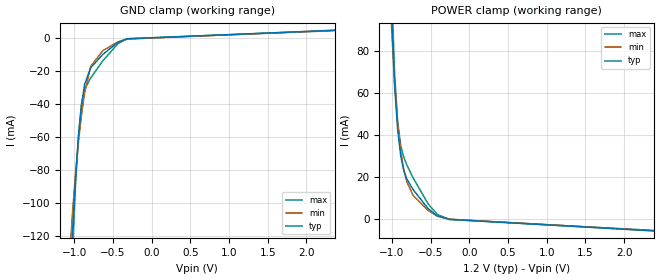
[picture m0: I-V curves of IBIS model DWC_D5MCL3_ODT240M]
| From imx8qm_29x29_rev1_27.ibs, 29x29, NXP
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[Model] DWC_D5MCL3_ODT240M
Model_type   Input
Polarity   Non-Inverting
Enable   Active-High
C_comp   1.266pF   1.183pF   1.367pF
C_comp_power_clamp   289.189fF   266.254fF   313.330fF
C_comp_gnd_clamp 966.826fF   901.503fF   1.047pF
Vinh = 735.000mV
Vinl = 465.000mV
[Model Spec]
D_overshoot_ampl_h 0.35 NA   NA
D_overshoot_ampl_l 0.35 NA   NA
D_overshoot_area_l 100.000p NA   NA
D_overshoot_area_h 100.000p NA   NA
[Receiver Thresholds]
Vth = 600.000mV
Vth_min = 588.000mV
Vth_max = 612.000mV
Vinh_ac = 135.000mV
Vinh_dc = 100.000mV
Vinl_ac = -135.000mV
Vinl_dc = -100.000mV
Tslew_ac = 5.000ns
Reference_supply Power_clamp_ref
[Temperature Range]   25.000   125.000   -40.000
[Voltage Range]   1.200V   1.140V   1.300V
[GND Clamp Reference]   0.00V   0.00V   0.00V
[C Comp Corner]
| variable   typ   min   max
C_comp 1.266pF   1.367pF   1.183pF
C_comp_pullup 289.189fF   313.330fF   266.254fF
C_comp_pulldown 966.826fF   1.047pF   901.503fF
[POWER Clamp Reference]   1.200V   1.140V   1.300V
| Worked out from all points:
|   GND clamp passes 1 mA (typ) near -0.37 V on its own axis
|   POWER clamp passes 1 mA (typ) near -0.38 V on its own axis
[GND Clamp]
-1.182V   -337.6mA   -253.1mA   -424.7mA
-1.064V   -162mA     -136.3mA   -188.8mA
-1.024V   -119.7mA   -107.2mA   -132.8mA
-984.8mV  -86.16mA   -82.97mA   -90.08mA
-945.5mV  -60.11mA   -62.96mA   -59.21mA
-906.1mV  -40.75mA   -46.56mA   -39.91mA
-866.7mV  -28.11mA   -33.45mA   -31.07mA
-787.9mV  -17.91mA   -17.12mA   -24.12mA
-630.3mV  -9.73mA    -7.477mA   -13.61mA
-433.3mV  -2.288mA   -2.086mA   -3.122mA
-315.2mV  -236.5uA   -432.9uA   -218uA
2.364V    4.93mA     4.928mA    4.723mA
[Power Clamp]
-1.164V   361.1mA    266.8mA    463.8mA
-1.006V   97.99mA    91.46mA    110.8mA
-966.7mV  63.78mA    64.72mA    69.28mA
-927.3mV  42.66mA    45.61mA    46.52mA
-887.9mV  30.27mA    32.55mA    35.22mA
-848.5mV  23.31mA    23.79mA    29.6mA
-809.1mV  19.31mA    18mA       26mA
-730.3mV  14.31mA    11.6mA     19.97mA
-533.3mV  5.121mA    4.266mA    7.403mA
-415.1mV  1.611mA    1.634mA    2.362mA
-257.6mV  26.78uA    141.6uA    30.44uA
2.382V    -5.445mA   -5.41mA    -5.222mA
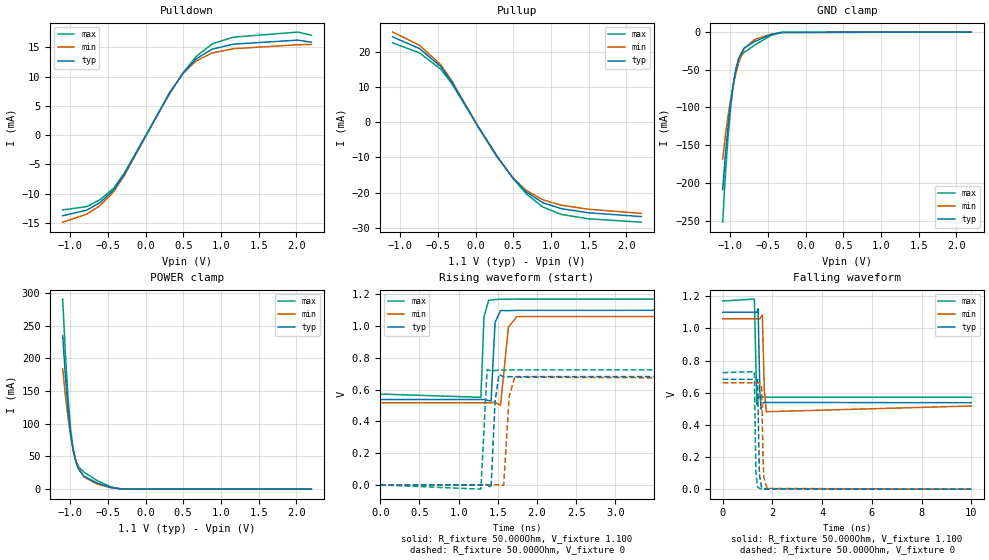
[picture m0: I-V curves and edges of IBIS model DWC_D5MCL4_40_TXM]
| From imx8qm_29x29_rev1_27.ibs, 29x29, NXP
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[Model] DWC_D5MCL4_40_TXM
Model_type   I/O
Polarity   Non-Inverting
Enable   Active-High
C_comp   1.321pF   1.237pF   1.427pF
C_comp_pullup   304.579fF   285.377fF   319.196fF
C_comp_pulldown 1.005pF   946.034fF   1.122pF
Vinh = 390.000mV
Vinl = 210.000mV
Vmeas = 300.000mV
Vref = 300.000mV
Rref = 50Ohms
Cref = 0pF
[Model Spec]
Vinh   390.000mV   379.000mV   409.000mV
Vinl   210.000mV   199.000mV   229.000mV
Vmeas   300.000mV   289.000mV   319.000mV
Vref   300.000mV   289.000mV   319.000mV
D_overshoot_ampl_h 0.35 NA   NA
D_overshoot_ampl_l 0.35 NA   NA
D_overshoot_area_l 800.000p NA   NA
D_overshoot_area_h 800.000p NA   NA
[Receiver Thresholds]
Vth = 300.000mV
Vth_min = 289.000mV
Vth_max = 311.000mV
Vinh_ac = 70.000mV
Vinh_dc = 70.000mV
Vinl_ac = -70.000mV
Vinl_dc = -70.000mV
Tslew_ac = 5.000ns
Reference_supply Pullup_ref
[Temperature Range]   25.000   125.000   -40.000
[Voltage Range]   1.100V   1.060V   1.170V
[GND Clamp Reference]   0.00V   0.00V   0.00V
[C Comp Corner]
| variable   typ   min   max
C_comp 1.321pF   1.427pF   1.237pF
C_comp_pullup 304.579fF   319.196fF   285.377fF
C_comp_pulldown 1.005pF   1.122pF   946.034fF
[Pulldown Reference]   0.00V   0.00V   0.00V
[POWER Clamp Reference]   1.100V   1.060V   1.170V
[Pullup Reference]   1.100V   1.060V   1.170V
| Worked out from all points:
|   slope of the pulldown table from 0 to 0.165 V, typ, clamps not added: 43.1 ohm
|   slope of the pullup table from 0 to 0.165 V, typ, clamps not added: 28.7 ohm
|   GND clamp passes 1 mA (typ) near -0.36 V on its own axis
|   POWER clamp passes 1 mA (typ) near -0.39 V on its own axis
|   rising waveform, R_fixture 50.000Ohm, V_fixture 1.100: 20-80 % time 31.1ps typ, 37.4ps min, 26.9ps max; typ from 0.538 V to 1.1 V
|   rising waveform, R_fixture 50.000Ohm, V_fixture 0: 20-80 % time 36.6ps typ, 46.3ps min, 29.6ps max; typ from 0 V to 0.683 V
|   falling waveform, R_fixture 50.000Ohm, V_fixture 1.100: 20-80 % time 41.4ps typ, 53ps min, 33.3ps max; typ from 1.1 V to 0.538 V
|   falling waveform, R_fixture 50.000Ohm, V_fixture 0: 20-80 % time 43.1ps typ, 52.7ps min, 36.1ps max; typ from 0.683 V to 0 V
[GND Clamp]
-1.099V   -209.2mA   -168.4mA   -252.1mA
-1.064V   -163.4mA   -137.7mA   -190.3mA
-1.028V   -124.9mA   -111.2mA   -139.2mA
-992.7mV  -93.53mA   -88.68mA   -98.97mA
-957.3mV  -68.45mA   -69.71mA   -68.58mA
-921.8mV  -48.89mA   -53.8mA    -47.45mA
-886.4mV  -34.72mA   -40.61mA   -35.66mA
-815.5mV  -21.1mA    -22.26mA   -27.15mA
-673.6mV  -12.42mA   -9.691mA   -17.09mA
-460.9mV  -3.348mA   -2.898mA   -4.568mA
-319.1mV  -385.7uA   -561.1uA   -390.5uA
2.198V    36.46nA    642nA      5.339nA
[Power Clamp]
-1.098V   234.6mA    183.9mA    290.8mA
-1.063V   174.2mA    143.9mA    208.3mA
-1.027V   123.2mA    109.2mA    139.7mA
-991.8mV  84.12mA    80.63mA    90.23mA
-956.4mV  57.38mA    58.87mA    59.68mA
-920.9mV  40.3mA     43.02mA    42.62mA
-885.5mV  29.76mA    31.87mA    33.77mA
-814.5mV  19.66mA    18.65mA    25.86mA
-637.3mV  9.272mA    7.463mA    12.87mA
-460mV    2.471mA    2.346mA    3.441mA
-318.2mV  227.1uA    402.8uA    250.8uA
2.199V    -18.43nA   -638.2nA   -2.113nA
[Pulldown]
-1.099V   -13.8mA    -14.9mA    -12.8mA
-780mV    -12.84mA   -13.52mA   -12.23mA
-602.7mV  -11.54mA   -12.05mA   -11.04mA
-425.5mV  -9.432mA   -9.731mA   -9.118mA
-283.6mV  -6.717mA   -6.955mA   -6.523mA
319.1mV   7.194mA    7.308mA    7.124mA
496.4mV   10.58mA    10.54mA    10.64mA
673.6mV   13.08mA    12.73mA    13.5mA
886.4mV   14.73mA    14.07mA    15.63mA
1.17V     15.57mA    14.79mA    16.77mA
2.021V    16.26mA    15.47mA    17.63mA
2.198V    15.9mA     15.5mA     17.1mA
[Pullup]
-1.098V   24.3mA     25.66mA    22.6mA
-743.6mV  20.98mA    21.93mA    19.75mA
-460mV    15.85mA    16.36mA    15.11mA
-318.2mV  11.57mA    11.98mA    11.13mA
36.4mV    -1.292mA   -1.335mA   -1.258mA
284.5mV   -9.68mA    -9.838mA   -9.563mA
497.3mV   -15.86mA   -15.8mA    -15.96mA
674.5mV   -19.8mA    -19.37mA   -20.36mA
887.3mV   -22.8mA    -21.97mA   -24.02mA
1.135V    -24.55mA   -23.55mA   -26.18mA
1.49V     -25.71mA   -24.7mA    -27.42mA
2.199V    -26.8mA    -25.9mA    -28.4mA
[Ramp]
R_load=50.000Ohm
dV/dt_r   373.710mV/33.500ps  361.229mV/42.000ps  396.780mV/28.500ps
dV/dt_f   373.740mV/43.500ps  361.259mV/54.000ps  396.810mV/35.000ps
[Rising waveform]
R_fixture=50.000Ohm
V_fixture=1.100
V_fixture_min=1.060
V_fixture_max=1.170
0s        537.6mV    517.4mV    572mV
1.283ns   537.5mV    517.4mV    551.5mV
1.323ns   537.8mV    517.4mV    1.058V
1.383ns   531.2mV    517.3mV    1.163V
1.413ns   527.3mV    517.3mV    1.164V
1.464ns   1.024V     518.8mV    1.167V
1.534ns   1.098V     502.4mV    1.169V
1.634ns   1.097V     992.8mV    1.169V
1.744ns   1.099V     1.06V      1.17V
10ns      1.1V       1.06V      1.17V
[Rising waveform]
R_fixture=50.000Ohm
V_fixture=0
0s        124.5nV    3.673uV    17.89nV
1.283ns   -48.73uV   4.558uV    -26.82mV
1.363ns   1.959mV    -11.02uV   726.6mV
1.413ns   -18.53mV   -131.1uV   717.3mV
1.464ns   523.1mV    1.123mV    720.4mV
1.514ns   696.8mV    360.8uV    722.3mV
1.574ns   679.7mV    -2.091mV   723.4mV
1.644ns   680.6mV    555.6mV    724mV
1.714ns   681.8mV    678.4mV    724.4mV
10ns      683.3mV    661.5mV    724.6mV
[Falling waveform]
R_fixture=50.000Ohm
V_fixture=1.100
V_fixture_min=1.060
V_fixture_max=1.170
0s        1.1V       1.06V      1.17V
1.273ns   1.1V       1.06V      1.182V
1.373ns   1.099V     1.06V      525.6mV
1.423ns   1.122V     1.06V      569.2mV
1.494ns   608.7mV    1.059V     574.5mV
1.544ns   496.6mV    1.071V     573.8mV
1.594ns   532.5mV    1.084V     573.1mV
1.674ns   539.6mV    614.7mV    572.3mV
1.754ns   539.1mV    481.5mV    571.9mV
10ns      537.5mV    517.3mV    571.9mV
[Falling waveform]
R_fixture=50.000Ohm
V_fixture=0
0s        683.3mV    661.5mV    724.6mV
1.273ns   683.3mV    661.5mV    730.3mV
1.333ns   683mV      661.5mV    108.8mV
1.403ns   680.9mV    661.6mV    14.4mV
1.474ns   97.83mV    661.2mV    5.583mV
1.564ns   8.441mV    639mV      1.711mV
1.624ns   5.368mV    191.4mV    831uV
1.654ns   4.009mV    72.85mV    591.1uV
1.784ns   1.096mV    4.62mV     151.3uV
10ns      413.7nV    4.058uV    128.1nV
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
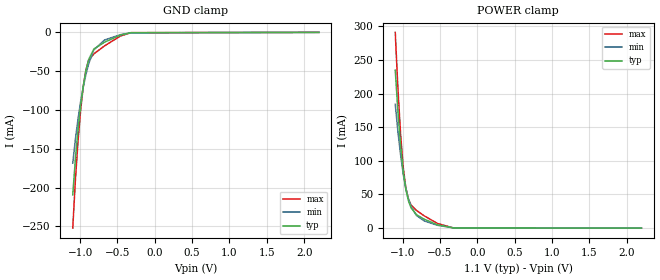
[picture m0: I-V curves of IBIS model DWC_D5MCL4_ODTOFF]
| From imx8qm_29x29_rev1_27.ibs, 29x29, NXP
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[Model] DWC_D5MCL4_ODTOFF
Model_type   Input
Polarity   Non-Inverting
Enable   Active-High
C_comp   1.292pF   1.207pF   1.398pF
C_comp_power_clamp   275.984fF   251.288fF   307.785fF
C_comp_gnd_clamp 1.016pF   955.238fF   1.090pF
Vinh = 640.000mV
Vinl = 460.000mV
[Model Spec]
D_overshoot_ampl_h 0.35 NA   NA
D_overshoot_ampl_l 0.35 NA   NA
D_overshoot_area_l 800.000p NA   NA
D_overshoot_area_h 800.000p NA   NA
[Receiver Thresholds]
Vth = 550.000mV
Vth_min = 539.000mV
Vth_max = 561.000mV
Vinh_ac = 70.000mV
Vinh_dc = 70.000mV
Vinl_ac = -70.000mV
Vinl_dc = -70.000mV
Tslew_ac = 5.000ns
Reference_supply Power_clamp_ref
[Temperature Range]   25.000   125.000   -40.000
[Voltage Range]   1.100V   1.060V   1.170V
[GND Clamp Reference]   0.00V   0.00V   0.00V
[C Comp Corner]
| variable   typ   min   max
C_comp 1.292pF   1.398pF   1.207pF
C_comp_pullup 275.984fF   307.785fF   251.288fF
C_comp_pulldown 1.016pF   1.090pF   955.238fF
[POWER Clamp Reference]   1.100V   1.060V   1.170V
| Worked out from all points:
|   GND clamp passes 1 mA (typ) near -0.36 V on its own axis
|   POWER clamp passes 1 mA (typ) near -0.39 V on its own axis
[GND Clamp]
-1.099V   -209.3mA   -168.4mA   -252.2mA
-1.064V   -163.5mA   -137.8mA   -190.5mA
-1.028V   -125mA     -111.2mA   -139.4mA
-992.7mV  -93.66mA   -88.73mA   -99.27mA
-957.3mV  -68.61mA   -69.77mA   -68.95mA
-921.8mV  -49.09mA   -53.87mA   -47.88mA
-886.4mV  -34.96mA   -40.69mA   -36.13mA
-815.5mV  -21.41mA   -22.37mA   -27.61mA
-673.6mV  -12.67mA   -9.856mA   -17.42mA
-460.9mV  -3.435mA   -2.974mA   -4.682mA
-319.1mV  -398.9uA   -579.2uA   -404.1uA
2.198V    37.01nA    671.7nA    3.108nA
[Power Clamp]
-1.098V   234.7mA    184mA      290.9mA
-1.063V   174.3mA    143.9mA    208.4mA
-1.027V   123.2mA    109.3mA    139.9mA
-991.8mV  84.22mA    80.69mA    90.47mA
-956.4mV  57.52mA    58.94mA    60.01mA
-920.9mV  40.49mA    43.1mA     43.03mA
-885.5mV  30.01mA    31.97mA    34.24mA
-814.5mV  19.98mA    18.81mA    26.36mA
-708.2mV  13.19mA    10.62mA    18.16mA
-530.9mV  4.87mA     4.169mA    6.821mA
-318.2mV  236.4uA    417.8uA    261.6uA
2.199V    -18.75nA   -654.4nA   -1.875nA
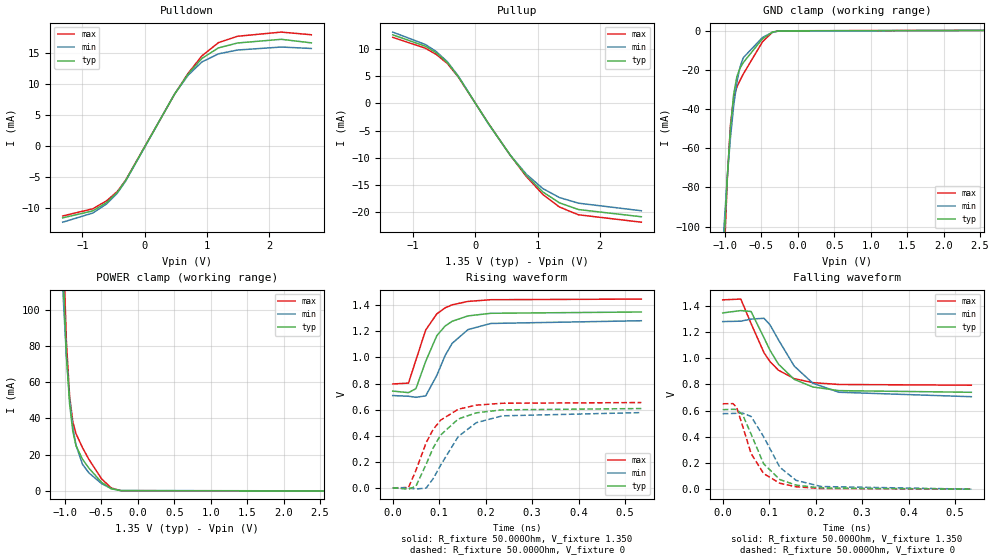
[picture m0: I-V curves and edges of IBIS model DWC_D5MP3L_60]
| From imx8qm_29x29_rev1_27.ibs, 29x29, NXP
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[Model] DWC_D5MP3L_60
Model_type   I/O
Polarity   Non-Inverting
Enable   Active-High
C_comp   1.262pF   1.180pF   1.365pF
C_comp_pullup   279.441fF   258.852fF   306.885fF
C_comp_pulldown 973.651fF   908.565fF   1.053pF
Vinh = 800.000mV
Vinl = 550.000mV
Vmeas = 675.000mV
Vref = 675.000mV
Rref = 50Ohms
Cref = 0pF
[Model Spec]
Vinh   800.000mV   766.500mV   850.000mV
Vinl   550.000mV   516.500mV   600.000mV
Vmeas   675.000mV   641.500mV   725.000mV
Vref   675.000mV   641.500mV   725.000mV
D_overshoot_ampl_h 0.4 NA   NA
D_overshoot_ampl_l 0.4 NA   NA
D_overshoot_area_l 100.000p NA   NA
D_overshoot_area_h 100.000p NA   NA
[Receiver Thresholds]
Vth = 675.000mV
Vth_min = 661.500mV
Vth_max = 688.500mV
Vinh_ac = 125.000mV
Vinh_dc = 90.000mV
Vinl_ac = -125.000mV
Vinl_dc = -90.000mV
Tslew_ac = 5.000ns
Threshold_sensitivity = 0.5
Reference_supply Pullup_ref
[Temperature Range]   25.000   125.000   -40.000
[Voltage Range]   1.350V   1.283V   1.450V
[GND Clamp Reference]   0.00V   0.00V   0.00V
[C Comp Corner]
| variable   typ   min   max
C_comp 1.262pF   1.365pF   1.180pF
C_comp_pullup 279.441fF   306.885fF   258.852fF
C_comp_pulldown 973.651fF   1.053pF   908.565fF
[Pulldown Reference]   0.00V   0.00V   0.00V
[POWER Clamp Reference]   1.350V   1.283V   1.450V
[Pullup Reference]   1.350V   1.283V   1.450V
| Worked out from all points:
|   slope of the pulldown table from 0 to 0.203 V, typ, clamps not added: 55.7 ohm
|   slope of the pullup table from 0 to 0.203 V, typ, clamps not added: 56.7 ohm
|   GND clamp passes 1 mA (typ) near -0.36 V on its own axis
|   POWER clamp passes 1 mA (typ) near -0.36 V on its own axis
|   rising waveform, R_fixture 50.000Ohm, V_fixture 1.350: 20-80 % time 47.1ps typ, 52.6ps min, 44.2ps max; typ from 0.742 V to 1.35 V
|   rising waveform, R_fixture 50.000Ohm, V_fixture 0: 20-80 % time 58.7ps typ, 67.4ps min, 54.6ps max; typ from 0.001 V to 0.608 V
|   falling waveform, R_fixture 50.000Ohm, V_fixture 1.350: 20-80 % time 64.5ps typ, 72.6ps min, 58.9ps max; typ from 1.35 V to 0.74 V
|   falling waveform, R_fixture 50.000Ohm, V_fixture 0: 20-80 % time 50.2ps typ, 57.6ps min, 45.1ps max; typ from 0.608 V to 0 V
[GND Clamp]
-1.318V   -593.4mA   -427mA     -758.7mA
-1.011V   -108.7mA   -99.8mA    -118.2mA
-966.7mV  -74.7mA    -74.6mA    -75.87mA
-922.7mV  -49.41mA   -54.3mA    -47.9mA
-878.8mV  -32.42mA   -38.21mA   -34.12mA
-834.8mV  -23.33mA   -26.23mA   -28.72mA
-790.9mV  -19.01mA   -18.35mA   -25.26mA
-747mV    -16.25mA   -13.76mA   -22.11mA
-483.3mV  -4.093mA   -3.434mA   -5.633mA
-351.5mV  -766.8uA   -911.3uA   -894.7uA
-263.6mV  -79.41uA   -192.1uA   -51.43uA
2.68V     154.9uA    127.3uA    193.1uA
[Power Clamp]
-1.33V    727.8mA    510.6mA    954.1mA
-1.023V   119.4mA    107.4mA    137.5mA
-978.8mV  74.87mA    74.2mA     82.23mA
-934.8mV  47.95mA    50.66mA    52.21mA
-890.9mV  32.9mA     35.12mA    38.1mA
-847mV    24.9mA     25.11mA    31.53mA
-759.1mV  17.5mA     14.71mA    23.9mA
-671.2mV  12.54mA    9.915mA    17.38mA
-495.5mV  4.603mA    3.922mA    6.563mA
-363.6mV  1.088mA    1.21mA     1.541mA
-231.8mV  46.56uA    141.4uA    53.69uA
2.668V    -76.24uA   -66.58uA   -87.76uA
[Pulldown]
-1.318V   -11.5mA    -12.2mA    -11.2mA
-834.8mV  -10.39mA   -10.73mA   -10.05mA
-615.2mV  -9.06mA    -9.294mA   -8.789mA
-439.4mV  -7.411mA   -7.525mA   -7.263mA
-307.6mV  -5.543mA   -5.636mA   -5.466mA
483.3mV   8.402mA    8.419mA    8.395mA
703mV     11.64mA    11.45mA    11.77mA
922.7mV   14.12mA    13.55mA    14.53mA
1.186V    15.79mA    14.83mA    16.63mA
1.494V    16.58mA    15.45mA    17.66mA
2.197V    17.17mA    15.93mA    18.33mA
2.68V     16.6mA     15.7mA     17.9mA
[Pullup]
-1.33V    12.6mA     13.1mA     12.13mA
-803mV    10.5mA     10.82mA    10.13mA
-627.3mV  9.274mA    9.502mA    8.976mA
-451.5mV  7.529mA    7.658mA    7.332mA
-275.8mV  4.943mA    5.041mA    4.864mA
207.6mV   -3.657mA   -3.719mA   -3.635mA
559.1mV   -9.476mA   -9.478mA   -9.507mA
822.7mV   -13.27mA   -13.03mA   -13.46mA
1.086V    -16.26mA   -15.64mA   -16.72mA
1.35V     -18.24mA   -17.27mA   -19.01mA
1.658V    -19.48mA   -18.31mA   -20.44mA
2.668V    -20.8mA    -19.7mA    -21.8mA
[Ramp]
R_load=50.000Ohm
dV/dt_r   364.350mV/54.000ps  345.537mV/60.500ps  391.320mV/50.500ps
dV/dt_f   364.350mV/58.000ps  345.537mV/65.500ps  391.290mV/53.500ps
[Rising waveform]
R_fixture=50.000Ohm
V_fixture=1.350
V_fixture_min=1.283
V_fixture_max=1.450
0s        741.9mV    707.7mV    796.4mV
34ps      730.2mV    702.5mV    803.1mV
50ps      760.6mV    694.3mV    980.2mV
71ps      970.1mV    705.2mV    1.21V
95ps      1.167V     862.8mV    1.334V
113ps     1.241V     1.016V     1.38V
128ps     1.277V     1.108V     1.403V
162ps     1.318V     1.213V     1.429V
211ps     1.338V     1.26V      1.442V
535ps     1.348V     1.281V     1.447V
[Rising waveform]
R_fixture=50.000Ohm
V_fixture=0
0s        843.7uV    922.8uV    693uV
34ps      -9.549mV   -1.036mV   2.917mV
50ps      13.21mV    -8.422mV   134.1mV
72ps      181.5mV    -991.8uV   346.9mV
87ps      305.8mV    70.4mV     447.7mV
103ps     404.8mV    173.1mV    518.9mV
141ps     528.2mV    393.9mV    603mV
180ps     575.4mV    500.1mV    634.3mV
236ps     598.1mV    552.4mV    648.7mV
535ps     608.2mV    577.1mV    654mV
[Falling waveform]
R_fixture=50.000Ohm
V_fixture=1.350
V_fixture_min=1.283
V_fixture_max=1.450
0s        1.347V     1.281V     1.447V
39ps      1.365V     1.284V     1.453V
61ps      1.358V     1.3V       1.266V
89ps      1.156V     1.306V     1.042V
102ps     1.06V      1.255V     974mV
120ps     955.4mV    1.141V     909.2mV
154ps     839mV      940.4mV    844.6mV
194ps     781.1mV    809.7mV    814.2mV
250ps     753.2mV    740.7mV    800.1mV
535ps     740.4mV    706.7mV    794.6mV
[Falling waveform]
R_fixture=50.000Ohm
V_fixture=0
0s        607.5mV    576.9mV    652.6mV
22ps      610.4mV    578.7mV    653.9mV
30ps      609.3mV    579.9mV    625.4mV
43ps      568.2mV    580.9mV    480.4mV
61ps      421.6mV    556mV      272.6mV
88ps      194.4mV    401.1mV    119.8mV
123ps     73.29mV    166.8mV    45.19mV
158ps     30.67mV    67.25mV    18.32mV
212ps     9.343mV    20.18mV    4.899mV
535ps     22.29uV    130.8uV    9.202uV
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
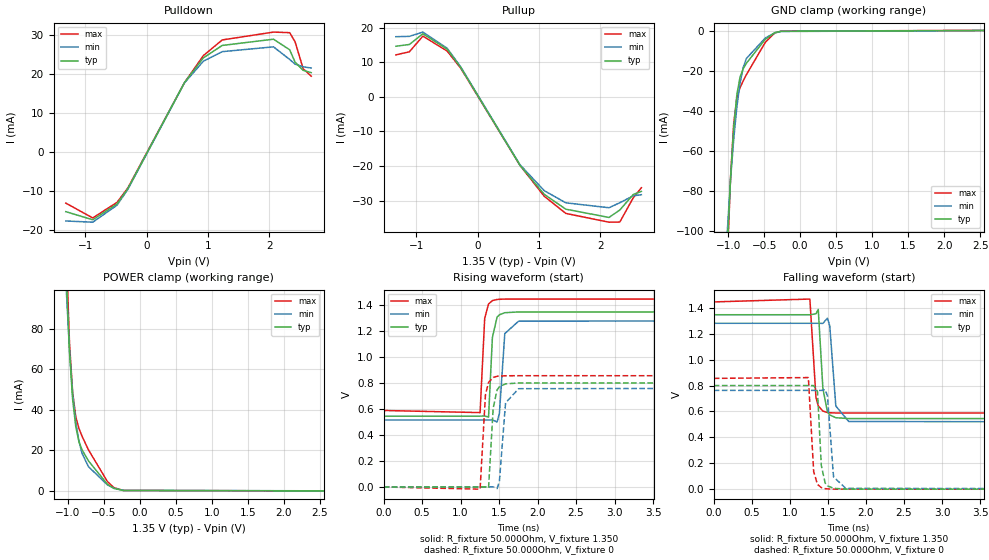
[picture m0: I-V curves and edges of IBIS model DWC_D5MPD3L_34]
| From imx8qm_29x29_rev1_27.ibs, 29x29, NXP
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[Model] DWC_D5MPD3L_34
Model_type   I/O
Polarity   Non-Inverting
Enable   Active-High
C_comp   1.451pF   1.359pF   1.565pF
C_comp_pullup   315.783fF   294.189fF   344.067fF
C_comp_pulldown 1.109pF   1.032pF   1.207pF
Vinh = 800.000mV
Vinl = 550.000mV
Vmeas = 675.000mV
Vref = 675.000mV
Rref = 50Ohms
Cref = 0pF
[Model Spec]
Vinh   800.000mV   767.000mV   850.000mV
Vinl   550.000mV   517.000mV   600.000mV
Vmeas   675.000mV   642.000mV   725.000mV
Vref   675.000mV   642.000mV   725.000mV
D_overshoot_ampl_h 0.4 NA   NA
D_overshoot_ampl_l 0.4 NA   NA
D_overshoot_area_l 100.000p NA   NA
D_overshoot_area_h 100.000p NA   NA
[Receiver Thresholds]
Vcross_low = 525.000mV
Vcross_high = 825.000mV
Vdiff_ac = 250.000mV
Vdiff_dc = 180.000mV
Tdiffslew_ac = 10.000ns
[Temperature Range]   25.000   125.000   -40.000
[Voltage Range]   1.350V   1.283V   1.450V
[GND Clamp Reference]   0.00V   0.00V   0.00V
[C Comp Corner]
| variable   typ   min   max
C_comp 1.451pF   1.565pF   1.359pF
C_comp_pullup 315.783fF   344.067fF   294.189fF
C_comp_pulldown 1.109pF   1.207pF   1.032pF
[Pulldown Reference]   0.00V   0.00V   0.00V
[POWER Clamp Reference]   1.350V   1.283V   1.450V
[Pullup Reference]   1.350V   1.283V   1.450V
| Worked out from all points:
|   slope of the pulldown table from 0 to 0.203 V, typ, clamps not added: 32.6 ohm
|   slope of the pullup table from 0 to 0.203 V, typ, clamps not added: 32.9 ohm
|   GND clamp passes 1 mA (typ) near -0.36 V on its own axis
|   POWER clamp passes 1 mA (typ) near -0.36 V on its own axis
|   rising waveform, R_fixture 50.000Ohm, V_fixture 1.350: 20-80 % time 41.2ps typ, 46.2ps min, 39.1ps max; typ from 0.545 V to 1.35 V
|   rising waveform, R_fixture 50.000Ohm, V_fixture 0: 20-80 % time 49.6ps typ, 57ps min, 46.1ps max; typ from 0 V to 0.8 V
|   falling waveform, R_fixture 50.000Ohm, V_fixture 1.350: 20-80 % time 52.3ps typ, 58.5ps min, 49.8ps max; typ from 1.35 V to 0.545 V
|   falling waveform, R_fixture 50.000Ohm, V_fixture 0: 20-80 % time 43.4ps typ, 49.5ps min, 39.8ps max; typ from 0.8 V to 0 V
[GND Clamp]
-1.318V   -611.9mA   -435.6mA   -789.4mA
-1.011V   -107.3mA   -99.44mA   -114.7mA
-966.7mV  -73.21mA   -74.14mA   -72.86mA
-922.7mV  -48.19mA   -53.84mA   -45.97mA
-878.8mV  -31.65mA   -37.83mA   -33.26mA
-834.8mV  -22.94mA   -25.98mA   -28.23mA
-790.9mV  -18.78mA   -18.21mA   -24.87mA
-747mV    -16.07mA   -13.69mA   -21.78mA
-483.3mV  -4.069mA   -3.422mA   -5.579mA
-351.5mV  -769.8uA   -913.6uA   -898.3uA
-263.6mV  -80.12uA   -193.4uA   -52.02uA
2.68V     309.8uA    252.8uA    386uA
[Power Clamp]
-1.33V    624.3mA    459.2mA    781.3mA
-1.023V   106.8mA    99.48mA    118.2mA
-978.8mV  68.81mA    69.68mA    73.53mA
-934.8mV  45.17mA    48.25mA    48.62mA
-890.9mV  31.58mA    33.85mA    36.56mA
-847mV    24.24mA    24.41mA    30.7mA
-803mV    20.11mA    18.35mA    26.81mA
-715.2mV  14.71mA    11.84mA    20.17mA
-451.5mV  3.129mA    2.823mA    4.473mA
-363.6mV  1.086mA    1.21mA     1.534mA
-231.8mV  46.56uA    141.6uA    53.57uA
2.668V    -152.4uA   -131.4uA   -175.4uA
[Pulldown]
-1.318V   -15.4mA    -17.8mA    -13.2mA
-878.8mV  -17.49mA   -18.11mA   -17.02mA
-483.3mV  -13.41mA   -13.73mA   -13mA
-307.6mV  -9.463mA   -9.657mA   -9.28mA
615.2mV   17.84mA    17.76mA    17.84mA
922.7mV   24.21mA    23.34mA    24.79mA
1.23V     27.41mA    25.81mA    28.83mA
2.065V    29.02mA    27.05mA    30.85mA
2.329V    26.29mA    23.8mA     30.7mA
2.417V    23.1mA     22.6mA     28.35mA
2.549V    21mA       21.9mA     21.4mA
2.68V     20.4mA     21.6mA     19.5mA
[Pullup]
-1.33V    14.6mA     17.35mA    12.1mA
-1.111V   15.1mA     17.45mA    12.99mA
-890.9mV  18.2mA     18.68mA    17.52mA
-495.5mV  13.74mA    14.03mA    13.2mA
-275.8mV  8.506mA    8.669mA    8.301mA
690.9mV   -19.77mA   -19.61mA   -19.78mA
1.086V    -28.15mA   -27.09mA   -28.71mA
1.438V    -32.44mA   -30.6mA    -33.66mA
2.141V    -34.82mA   -32.02mA   -36.19mA
2.317V    -32.68mA   -30.57mA   -36.15mA
2.536V    -28.2mA    -28.59mA   -29.14mA
2.668V    -27.3mA    -28.25mA   -26.24mA
[Ramp]
R_load=50.000Ohm
dV/dt_r   480.660mV/46.000ps  458.488mV/52.500ps  513.870mV/43.000ps
dV/dt_f   480.660mV/48.500ps  458.458mV/54.500ps  513.840mV/45.000ps
[Rising waveform]
R_fixture=50.000Ohm
V_fixture=1.350
V_fixture_min=1.283
V_fixture_max=1.450
0s        545.1mV    515.4mV    588.7mV
1.253ns   545.1mV    515.4mV    572.3mV
1.313ns   546.2mV    515.4mV    1.298V
1.363ns   537.8mV    515.3mV    1.408V
1.413ns   1.15V      516.3mV    1.434V
1.474ns   1.308V     500mV      1.443V
1.504ns   1.325V     564.9mV    1.444V
1.574ns   1.341V     1.18V      1.446V
1.754ns   1.347V     1.276V     1.446V
10ns      1.347V     1.281V     1.446V
[Rising waveform]
R_fixture=50.000Ohm
V_fixture=0
0s        350.6nV    7.364uV    48.17nV
1.253ns   6.973uV    3.721uV    -16.83mV
1.323ns   1.498mV    20.39uV    710.8mV
1.363ns   -7.766mV   -79.06uV   805mV
1.423ns   606.4mV    1.232mV    842.8mV
1.474ns   747.3mV    -12.01mV   851.7mV
1.504ns   771.4mV    43.43mV    853.8mV
1.584ns   793.5mV    647.1mV    855.8mV
1.754ns   800.2mV    756.3mV    856.2mV
10ns      800.3mV    763mV      855.7mV
[Falling waveform]
R_fixture=50.000Ohm
V_fixture=1.350
V_fixture_min=1.283
V_fixture_max=1.450
0s        1.347V     1.281V     1.446V
1.263ns   1.347V     1.281V     1.468V
1.343ns   1.354V     1.281V     707.1mV
1.373ns   1.388V     1.281V     643.8mV
1.434ns   777.5mV    1.28V      602.4mV
1.494ns   596.9mV    1.321V     592.1mV
1.524ns   573.5mV    1.261V     590.2mV
1.604ns   551.8mV    641.7mV    588.4mV
1.774ns   545.1mV    522.6mV    588mV
10ns      545mV      515.4mV    588.6mV
[Falling waveform]
R_fixture=50.000Ohm
V_fixture=0
0s        800.2mV    762.9mV    855.5mV
1.243ns   800.2mV    762.9mV    861.7mV
1.313ns   799.7mV    762.9mV    134.8mV
1.363ns   755mV      763mV      36.8mV
1.413ns   183.1mV    762.5mV    12.32mV
1.464ns   47.21mV    768.5mV    4.221mV
1.494ns   25.95mV    720.7mV    2.267mV
1.574ns   6.464mV    94.86mV    451.2uV
1.734ns   464uV      6.588mV    42.14uV
10ns      554.4nV    7.428uV    169.9nV
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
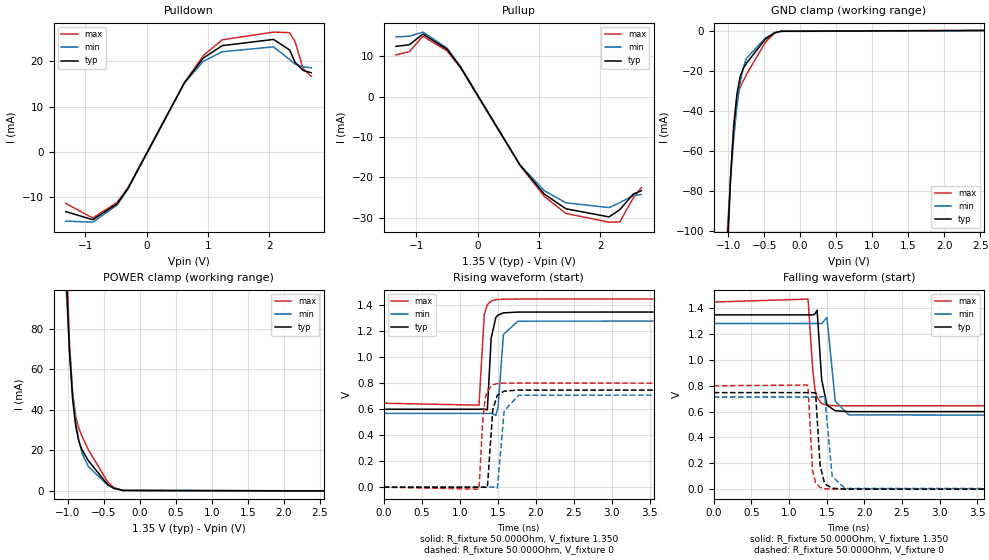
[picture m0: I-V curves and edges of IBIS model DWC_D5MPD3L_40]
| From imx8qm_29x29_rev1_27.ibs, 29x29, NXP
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[Model] DWC_D5MPD3L_40
Model_type   I/O
Polarity   Non-Inverting
Enable   Active-High
C_comp   1.451pF   1.359pF   1.565pF
C_comp_pullup   315.783fF   294.189fF   344.067fF
C_comp_pulldown 1.109pF   1.032pF   1.207pF
Vinh = 800.000mV
Vinl = 550.000mV
Vmeas = 675.000mV
Vref = 675.000mV
Rref = 50Ohms
Cref = 0pF
[Model Spec]
Vinh   800.000mV   767.000mV   850.000mV
Vinl   550.000mV   517.000mV   600.000mV
Vmeas   675.000mV   642.000mV   725.000mV
Vref   675.000mV   642.000mV   725.000mV
D_overshoot_ampl_h 0.4 NA   NA
D_overshoot_ampl_l 0.4 NA   NA
D_overshoot_area_l 100.000p NA   NA
D_overshoot_area_h 100.000p NA   NA
[Receiver Thresholds]
Vcross_low = 525.000mV
Vcross_high = 825.000mV
Vdiff_ac = 250.000mV
Vdiff_dc = 180.000mV
Tdiffslew_ac = 10.000ns
[Temperature Range]   25.000   125.000   -40.000
[Voltage Range]   1.350V   1.283V   1.450V
[GND Clamp Reference]   0.00V   0.00V   0.00V
[C Comp Corner]
| variable   typ   min   max
C_comp 1.451pF   1.565pF   1.359pF
C_comp_pullup 315.783fF   344.067fF   294.189fF
C_comp_pulldown 1.109pF   1.207pF   1.032pF
[Pulldown Reference]   0.00V   0.00V   0.00V
[POWER Clamp Reference]   1.350V   1.283V   1.450V
[Pullup Reference]   1.350V   1.283V   1.450V
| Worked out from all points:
|   slope of the pulldown table from 0 to 0.203 V, typ, clamps not added: 38 ohm
|   slope of the pullup table from 0 to 0.203 V, typ, clamps not added: 38.5 ohm
|   GND clamp passes 1 mA (typ) near -0.36 V on its own axis
|   POWER clamp passes 1 mA (typ) near -0.36 V on its own axis
|   rising waveform, R_fixture 50.000Ohm, V_fixture 1.350: 20-80 % time 44.3ps typ, 49.1ps min, 42.1ps max; typ from 0.599 V to 1.35 V
|   rising waveform, R_fixture 50.000Ohm, V_fixture 0: 20-80 % time 53.8ps typ, 62.2ps min, 50.1ps max; typ from 0 V to 0.746 V
|   falling waveform, R_fixture 50.000Ohm, V_fixture 1.350: 20-80 % time 57.8ps typ, 64.5ps min, 54.5ps max; typ from 1.35 V to 0.599 V
|   falling waveform, R_fixture 50.000Ohm, V_fixture 0: 20-80 % time 47.2ps typ, 53.7ps min, 43.3ps max; typ from 0.746 V to 0 V
[GND Clamp]
-1.318V   -611.9mA   -435.6mA   -789.4mA
-1.011V   -107.3mA   -99.44mA   -114.7mA
-966.7mV  -73.21mA   -74.14mA   -72.86mA
-922.7mV  -48.19mA   -53.84mA   -45.97mA
-878.8mV  -31.65mA   -37.83mA   -33.26mA
-834.8mV  -22.94mA   -25.98mA   -28.23mA
-790.9mV  -18.78mA   -18.21mA   -24.87mA
-747mV    -16.07mA   -13.69mA   -21.78mA
-483.3mV  -4.069mA   -3.422mA   -5.579mA
-351.5mV  -769.8uA   -913.6uA   -898.3uA
-263.6mV  -80.12uA   -193.4uA   -52.02uA
2.68V     309.8uA    252.8uA    386uA
[Power Clamp]
-1.33V    624.3mA    459.2mA    781.3mA
-1.023V   106.8mA    99.48mA    118.2mA
-978.8mV  68.81mA    69.68mA    73.53mA
-934.8mV  45.17mA    48.25mA    48.62mA
-890.9mV  31.58mA    33.85mA    36.56mA
-847mV    24.24mA    24.41mA    30.7mA
-803mV    20.11mA    18.35mA    26.81mA
-715.2mV  14.71mA    11.84mA    20.17mA
-451.5mV  3.129mA    2.823mA    4.473mA
-363.6mV  1.086mA    1.21mA     1.534mA
-231.8mV  46.56uA    141.6uA    53.57uA
2.668V    -152.4uA   -131.4uA   -175.4uA
[Pulldown]
-1.318V   -13.2mA    -15.3mA    -11.4mA
-878.8mV  -14.99mA   -15.54mA   -14.61mA
-483.3mV  -11.5mA    -11.78mA   -11.17mA
-307.6mV  -8.113mA   -8.287mA   -7.978mA
615.2mV   15.29mA    15.24mA    15.33mA
922.7mV   20.75mA    20.02mA    21.3mA
1.23V     23.48mA    22.14mA    24.77mA
2.065V    24.86mA    23.21mA    26.48mA
2.329V    22.52mA    20.4mA     26.35mA
2.417V    19.8mA     19.4mA     24.33mA
2.549V    18mA       18.8mA     18.4mA
2.68V     17.5mA     18.6mA     16.7mA
[Pullup]
-1.33V    12.5mA     14.85mA    10.4mA
-1.111V   12.9mA     15.01mA    11.19mA
-890.9mV  15.56mA    16.04mA    15.04mA
-495.5mV  11.76mA    12.05mA    11.35mA
-275.8mV  7.283mA    7.45mA     7.139mA
690.9mV   -16.93mA   -16.85mA   -17mA
1.086V    -24.09mA   -23.26mA   -24.67mA
1.438V    -27.75mA   -26.26mA   -28.91mA
2.141V    -29.77mA   -27.47mA   -31.08mA
2.317V    -27.98mA   -26.22mA   -31.04mA
2.536V    -24.1mA    -24.5mA    -25.06mA
2.668V    -23.3mA    -24.2mA    -22.51mA
[Ramp]
R_load=50.000Ohm
dV/dt_r   448.110mV/50.000ps  427.618mV/56.500ps  479.910mV/46.500ps
dV/dt_f   448.110mV/53.000ps  427.618mV/59.500ps  479.910mV/50.000ps
[Rising waveform]
R_fixture=50.000Ohm
V_fixture=1.350
V_fixture_min=1.283
V_fixture_max=1.450
0s        599.3mV    567.4mV    645.4mV
1.253ns   599.3mV    567.3mV    630.7mV
1.323ns   600.4mV    567.4mV    1.329V
1.363ns   595.1mV    567.2mV    1.403V
1.413ns   1.146V     568.2mV    1.431V
1.474ns   1.304V     552.6mV    1.442V
1.504ns   1.323V     615.6mV    1.443V
1.574ns   1.34V      1.174V     1.445V
1.764ns   1.346V     1.276V     1.446V
10ns      1.347V     1.28V      1.446V
[Rising waveform]
R_fixture=50.000Ohm
V_fixture=0
0s        384.3nV    8.074uV    52.65nV
1.253ns   7.701uV    4.453uV    -15.16mV
1.303ns   257uV      15.14uV    520.9mV
1.333ns   357.2uV    14.82uV    677.8mV
1.363ns   -4.772mV   -72.94uV   740.8mV
1.434ns   596mV      1.525mV    787.2mV
1.494ns   706.2mV    -8.025mV   796.4mV
1.584ns   738.3mV    587mV      799.7mV
1.774ns   746.4mV    706.4mV    800.2mV
10ns      746.3mV    712.3mV    799.6mV
[Falling waveform]
R_fixture=50.000Ohm
V_fixture=1.350
V_fixture_min=1.283
V_fixture_max=1.450
0s        1.347V     1.28V      1.446V
1.253ns   1.347V     1.28V      1.469V
1.313ns   1.346V     1.28V      934.3mV
1.343ns   1.353V     1.28V      776mV
1.373ns   1.383V     1.281V     709mV
1.434ns   847.4mV    1.279V     662.1mV
1.504ns   649.3mV    1.326V     648.8mV
1.614ns   606.2mV    680.9mV    645mV
1.794ns   599.2mV    573.9mV    644.5mV
10ns      599.2mV    567.3mV    645.2mV
[Falling waveform]
R_fixture=50.000Ohm
V_fixture=0
0s        746.2mV    712.2mV    799.4mV
1.243ns   746.2mV    712.2mV    804.6mV
1.253ns   746.2mV    712.2mV    786.1mV
1.313ns   745.9mV    712.2mV    139.5mV
1.353ns   743.1mV    712.2mV    50.82mV
1.413ns   182.9mV    711.8mV    14.03mV
1.474ns   41.66mV    716.8mV    4.045mV
1.574ns   7.285mV    98.05mV    558uV
1.744ns   473.2uV    6.331mV    44.78uV
10ns      425.6nV    8.256uV    263.1nV
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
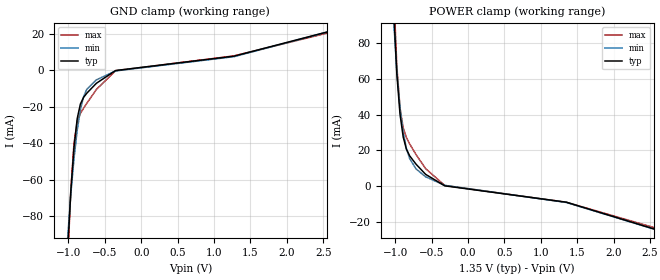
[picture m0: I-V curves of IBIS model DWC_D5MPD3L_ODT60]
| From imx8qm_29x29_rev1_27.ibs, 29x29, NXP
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[Model] DWC_D5MPD3L_ODT60
Model_type   Input
Polarity   Non-Inverting
Enable   Active-High
C_comp   1.505pF   1.450pF   1.588pF
C_comp_power_clamp   384.895fF   382.989fF   397.062fF
C_comp_gnd_clamp 1.094pF   1.020pF   1.191pF
Vinh = 800.000mV
Vinl = 550.000mV
[Model Spec]
D_overshoot_ampl_h 0.4 NA   NA
D_overshoot_ampl_l 0.4 NA   NA
D_overshoot_area_l 100.000p NA   NA
D_overshoot_area_h 100.000p NA   NA
[Receiver Thresholds]
Vcross_low = 525.000mV
Vcross_high = 825.000mV
Vdiff_ac = 250.000mV
Vdiff_dc = 180.000mV
Tdiffslew_ac = 10.000ns
[Temperature Range]   25.000   125.000   -40.000
[Voltage Range]   1.350V   1.283V   1.450V
[GND Clamp Reference]   0.00V   0.00V   0.00V
[C Comp Corner]
| variable   typ   min   max
C_comp 1.505pF   1.588pF   1.450pF
C_comp_pullup 384.895fF   382.989fF   397.062fF
C_comp_pulldown 1.094pF   1.191pF   1.020pF
[POWER Clamp Reference]   1.350V   1.283V   1.450V
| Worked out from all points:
|   GND clamp passes 1 mA (typ) near -0.41 V on its own axis
|   POWER clamp passes 1 mA (typ) near -0.39 V on its own axis
[GND Clamp]
-1.318V   -598.8mA   -424.1mA   -774.9mA
-1.011V   -99.7mA    -92.64mA   -106.5mA
-966.7mV  -66.48mA   -68.04mA   -65.77mA
-922.7mV  -42.26mA   -48.35mA   -39.95mA
-878.8mV  -26.49mA   -32.92mA   -28.16mA
-834.8mV  -18.47mA   -21.64mA   -23.69mA
-790.9mV  -14.82mA   -14.42mA   -20.76mA
-747mV    -12.55mA   -10.38mA   -18.08mA
-615.2mV  -7.09mA    -5.216mA   -10.5mA
-351.5mV  -115.4uA   -325.8uA   -197.4uA
1.274V    7.769mA    7.495mA    7.945mA
2.68V     22.37mA    22.31mA    21.64mA
[Power Clamp]
-1.33V    612.2mA    449mA      767.9mA
-1.023V   99.72mA    93.39mA    110.5mA
-978.8mV  62.91mA    64.37mA    67.44mA
-934.8mV  40.27mA    43.69mA    43.76mA
-890.9mV  27.45mA    29.93mA    32.53mA
-847mV    20.68mA    21.03mA    27.18mA
-803mV    16.99mA    15.43mA    23.67mA
-715.2mV  12.27mA    9.638mA    17.68mA
-583.3mV  6.576mA    5.195mA    9.763mA
-319.7mV  136.8uA    402.8uA    354uA
1.35V     -9.024mA   -9.182mA   -9.062mA
2.668V    -25.43mA   -25.5mA    -24.56mA
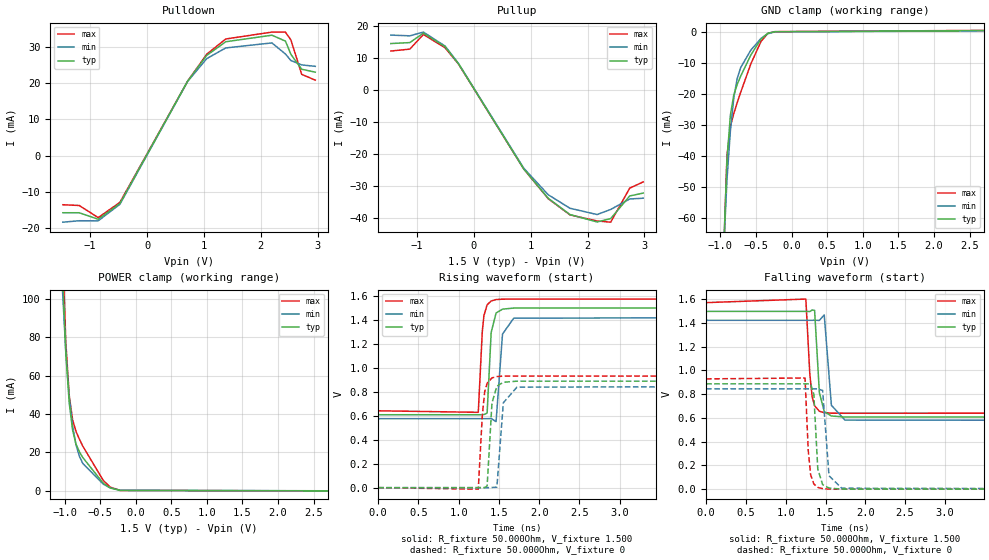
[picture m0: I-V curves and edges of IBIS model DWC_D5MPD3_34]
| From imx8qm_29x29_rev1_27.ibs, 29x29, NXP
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[Model] DWC_D5MPD3_34
Model_type   I/O
Polarity   Non-Inverting
Enable   Active-High
C_comp   1.449pF   1.359pF   1.562pF
C_comp_pullup   309.408fF   290.590fF   338.313fF
C_comp_pulldown 1.131pF   1.055pF   1.218pF
Vinh = 875.000mV
Vinl = 625.000mV
Vmeas = 750.000mV
Vref = 750.000mV
Rref = 50Ohms
Cref = 0pF
[Model Spec]
Vinh   875.000mV   838.000mV   913.000mV
Vinl   625.000mV   588.000mV   663.000mV
Vmeas   750.000mV   713.000mV   788.000mV
Vref   750.000mV   713.000mV   788.000mV
D_overshoot_ampl_h 0.4 NA   NA
D_overshoot_ampl_l 0.4 NA   NA
D_overshoot_area_l 100.000p NA   NA
D_overshoot_area_h 100.000p NA   NA
[Receiver Thresholds]
Vcross_low = 575.000mV
Vcross_high = 925.000mV
Vdiff_ac = 250.000mV
Vdiff_dc = 200.000mV
Tdiffslew_ac = 10.000ns
[Temperature Range]   25.000   125.000   -40.000
[Voltage Range]   1.500V   1.425V   1.575V
[GND Clamp Reference]   0.00V   0.00V   0.00V
[C Comp Corner]
| variable   typ   min   max
C_comp 1.449pF   1.562pF   1.359pF
C_comp_pullup 309.408fF   338.313fF   290.590fF
C_comp_pulldown 1.131pF   1.218pF   1.055pF
[Pulldown Reference]   0.00V   0.00V   0.00V
[POWER Clamp Reference]   1.500V   1.425V   1.575V
[Pullup Reference]   1.500V   1.425V   1.575V
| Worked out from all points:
|   slope of the pulldown table from 0 to 0.225 V, typ, clamps not added: 32.9 ohm
|   slope of the pullup table from 0 to 0.225 V, typ, clamps not added: 33.4 ohm
|   GND clamp passes 1 mA (typ) near -0.36 V on its own axis
|   POWER clamp passes 1 mA (typ) near -0.34 V on its own axis
|   rising waveform, R_fixture 50.000Ohm, V_fixture 1.500: 20-80 % time 41.9ps typ, 47.4ps min, 39ps max; typ from 0.608 V to 1.5 V
|   rising waveform, R_fixture 50.000Ohm, V_fixture 0: 20-80 % time 47.9ps typ, 55.5ps min, 45.1ps max; typ from 0 V to 0.887 V
|   falling waveform, R_fixture 50.000Ohm, V_fixture 1.500: 20-80 % time 50.6ps typ, 55.4ps min, 48.4ps max; typ from 1.5 V to 0.607 V
|   falling waveform, R_fixture 50.000Ohm, V_fixture 0: 20-80 % time 42.3ps typ, 47.2ps min, 39.6ps max; typ from 0.887 V to 0 V
[GND Clamp]
-1.48V    -953.7mA   -668.6mA   -1.235A
-1.002V   -100.2mA   -94.39mA   -105.7mA
-906.8mV  -41.27mA   -47.66mA   -39.94mA
-859.1mV  -26.94mA   -32.05mA   -30.57mA
-811.4mV  -20.4mA    -21.37mA   -26.37mA
-763.6mV  -17.03mA   -15.12mA   -22.94mA
-715.9mV  -14.41mA   -11.66mA   -19.65mA
-572.7mV  -7.58mA    -5.976mA   -10.46mA
-429.5mV  -2.403mA   -2.2mA     -3.204mA
-334.1mV  -541.6uA   -710uA     -592.8uA
-238.6mV  -34.76uA   -109.3uA   -17.5uA
2.959V    342.2uA    278.6uA    426.2uA
[Power Clamp]
-1.459V   879.2mA    638.3mA    1.105A
-1.03V    115.1mA    105.8mA    129.1mA
-981.8mV  71.94mA    72.39mA    77.67mA
-934.1mV  45.89mA    48.93mA    49.78mA
-886.4mV  31.62mA    33.58mA    36.91mA
-838.6mV  24.3mA     23.87mA    30.9mA
-790.9mV  20.23mA    17.9mA     26.85mA
-743.2mV  17.24mA    14.16mA    23.2mA
-456.8mV  3.872mA    3.378mA    5.352mA
-361.4mV  1.38mA     1.454mA    1.878mA
-218.2mV  56.55uA    161.4uA    60.38uA
2.979V    -171.1uA   -147.7uA   -202.3uA
[Pulldown]
-1.48V    -15.7mA    -18.3mA    -13.5mA
-1.193V   -15.7mA    -17.9mA    -13.7mA
-859.1mV  -17.49mA   -17.92mA   -17.04mA
-477.3mV  -13.15mA   -13.37mA   -12.84mA
715.9mV   20.58mA    20.48mA    20.57mA
1.05V     27.62mA    26.73mA    27.93mA
1.384V    31.37mA    29.67mA    32.13mA
2.196V    33.17mA    31.05mA    34.03mA
2.434V    31.55mA    27.99mA    34.01mA
2.53V     27.9mA     26.2mA     31.86mA
2.72V     23.8mA     25mA       22.4mA
2.959V    23mA       24.6mA     20.8mA
[Pullup]
-1.459V   14.4mA     17.04mA    12.06mA
-1.125V   14.7mA     16.81mA    12.66mA
-886.4mV  17.66mA    17.98mA    17.24mA
-504.5mV  13.41mA    13.61mA    13.07mA
-265.9mV  8.015mA    8.098mA    7.914mA
879.5mV   -24.79mA   -24.55mA   -24.8mA
1.309V    -33.93mA   -32.82mA   -34.06mA
1.691V    -39mA      -37.04mA   -39.11mA
2.168V    -41.32mA   -39mA      -41.01mA
2.407V    -40.27mA   -37.42mA   -41.39mA
2.741V    -33.2mA    -34.14mA   -30.77mA
2.979V    -32.3mA    -33.9mA    -28.81mA
[Ramp]
R_load=50.000Ohm
dV/dt_r   532.890mV/45.500ps  507.896mV/52.000ps  557.790mV/43.000ps
dV/dt_f   532.860mV/47.000ps  507.896mV/52.500ps  557.760mV/44.500ps
[Rising waveform]
R_fixture=50.000Ohm
V_fixture=1.500
V_fixture_min=1.425
V_fixture_max=1.575
0s        607.5mV    574.6mV    640.3mV
1.243ns   607.5mV    574.6mV    627.5mV
1.293ns   607.6mV    574.6mV    1.302V
1.313ns   609mV      574.6mV    1.433V
1.353ns   621.6mV    574.5mV    1.523V
1.403ns   1.293V     575.6mV    1.555V
1.464ns   1.455V     550.2mV    1.567V
1.544ns   1.487V     1.28V      1.57V
1.684ns   1.496V     1.412V     1.571V
10ns      1.497V     1.422V     1.571V
[Rising waveform]
R_fixture=50.000Ohm
V_fixture=0
0s        738.2nV    12.87uV    92.49nV
1.243ns   14.12uV    11.63uV    -12.56mV
1.293ns   90.02uV    14.85uV    603.8mV
1.323ns   579.5uV    26.47uV    800.8mV
1.353ns   14.26mV    -58.2uV    870.6mV
1.413ns   705.1mV    1.478mV    914.5mV
1.474ns   845.7mV    3.98mV     925.6mV
1.554ns   877.8mV    706.8mV    929.1mV
1.724ns   887.1mV    837.8mV    929.9mV
10ns      887.2mV    845.2mV    929.1mV
[Falling waveform]
R_fixture=50.000Ohm
V_fixture=1.500
V_fixture_min=1.425
V_fixture_max=1.575
0s        1.497V     1.422V     1.571V
1.253ns   1.497V     1.422V     1.601V
1.303ns   1.496V     1.422V     968mV
1.333ns   1.509V     1.422V     775.2mV
1.363ns   1.506V     1.423V     702.5mV
1.423ns   812.8mV    1.421V     655.9mV
1.484ns   654.2mV    1.468V     644mV
1.574ns   616.2mV    706.5mV    640.1mV
1.744ns   607.4mV    582.1mV    639.3mV
10ns      607.4mV    574.5mV    640.1mV
[Falling waveform]
R_fixture=50.000Ohm
V_fixture=0
0s        887mV      845.1mV    928.8mV
1.243ns   887mV      845.1mV    936.1mV
1.283ns   887mV      845.1mV    326.6mV
1.313ns   886.9mV    845.1mV    122.6mV
1.353ns   800.5mV    845.2mV    44.14mV
1.403ns   169mV      844.6mV    14.71mV
1.464ns   38.3mV     831.7mV    4.098mV
1.544ns   9.288mV    113mV      801.1uV
1.704ns   667.5uV    7.713mV    58.21uV
10ns      996.2nV    13.1uV     248nV
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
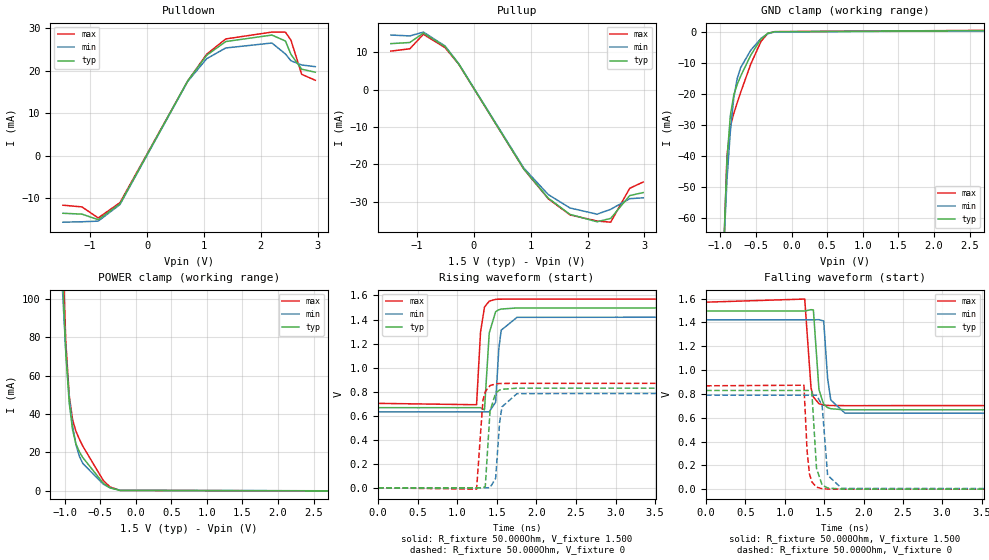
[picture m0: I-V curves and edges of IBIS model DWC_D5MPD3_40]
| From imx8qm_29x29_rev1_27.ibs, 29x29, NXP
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[Model] DWC_D5MPD3_40
Model_type   I/O
Polarity   Non-Inverting
Enable   Active-High
C_comp   1.449pF   1.359pF   1.562pF
C_comp_pullup   309.408fF   290.590fF   338.313fF
C_comp_pulldown 1.131pF   1.055pF   1.218pF
Vinh = 875.000mV
Vinl = 625.000mV
Vmeas = 750.000mV
Vref = 750.000mV
Rref = 50Ohms
Cref = 0pF
[Model Spec]
Vinh   875.000mV   838.000mV   913.000mV
Vinl   625.000mV   588.000mV   663.000mV
Vmeas   750.000mV   713.000mV   788.000mV
Vref   750.000mV   713.000mV   788.000mV
D_overshoot_ampl_h 0.4 NA   NA
D_overshoot_ampl_l 0.4 NA   NA
D_overshoot_area_l 100.000p NA   NA
D_overshoot_area_h 100.000p NA   NA
[Receiver Thresholds]
Vcross_low = 575.000mV
Vcross_high = 925.000mV
Vdiff_ac = 250.000mV
Vdiff_dc = 200.000mV
Tdiffslew_ac = 10.000ns
[Temperature Range]   25.000   125.000   -40.000
[Voltage Range]   1.500V   1.425V   1.575V
[GND Clamp Reference]   0.00V   0.00V   0.00V
[C Comp Corner]
| variable   typ   min   max
C_comp 1.449pF   1.562pF   1.359pF
C_comp_pullup 309.408fF   338.313fF   290.590fF
C_comp_pulldown 1.131pF   1.218pF   1.055pF
[Pulldown Reference]   0.00V   0.00V   0.00V
[POWER Clamp Reference]   1.500V   1.425V   1.575V
[Pullup Reference]   1.500V   1.425V   1.575V
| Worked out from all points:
|   slope of the pulldown table from 0 to 0.225 V, typ, clamps not added: 38.3 ohm
|   slope of the pullup table from 0 to 0.225 V, typ, clamps not added: 38.9 ohm
|   GND clamp passes 1 mA (typ) near -0.36 V on its own axis
|   POWER clamp passes 1 mA (typ) near -0.34 V on its own axis
|   rising waveform, R_fixture 50.000Ohm, V_fixture 1.500: 20-80 % time 44.6ps typ, 49.9ps min, 42.7ps max; typ from 0.667 V to 1.5 V
|   rising waveform, R_fixture 50.000Ohm, V_fixture 0: 20-80 % time 51.9ps typ, 59.3ps min, 49.3ps max; typ from 0 V to 0.829 V
|   falling waveform, R_fixture 50.000Ohm, V_fixture 1.500: 20-80 % time 55.7ps typ, 61.4ps min, 53.4ps max; typ from 1.5 V to 0.666 V
|   falling waveform, R_fixture 50.000Ohm, V_fixture 0: 20-80 % time 46.1ps typ, 50.9ps min, 42.7ps max; typ from 0.828 V to 0 V
[GND Clamp]
-1.48V    -953.7mA   -668.6mA   -1.235A
-1.002V   -100.2mA   -94.39mA   -105.7mA
-906.8mV  -41.27mA   -47.66mA   -39.94mA
-859.1mV  -26.94mA   -32.05mA   -30.57mA
-811.4mV  -20.4mA    -21.37mA   -26.37mA
-763.6mV  -17.03mA   -15.12mA   -22.94mA
-715.9mV  -14.41mA   -11.66mA   -19.65mA
-572.7mV  -7.58mA    -5.976mA   -10.46mA
-429.5mV  -2.403mA   -2.2mA     -3.204mA
-334.1mV  -541.6uA   -710uA     -592.8uA
-238.6mV  -34.76uA   -109.3uA   -17.5uA
2.959V    342.2uA    278.6uA    426.2uA
[Power Clamp]
-1.459V   879.2mA    638.3mA    1.105A
-1.03V    115.1mA    105.8mA    129.1mA
-981.8mV  71.94mA    72.39mA    77.67mA
-934.1mV  45.89mA    48.93mA    49.78mA
-886.4mV  31.62mA    33.58mA    36.91mA
-838.6mV  24.3mA     23.87mA    30.9mA
-790.9mV  20.23mA    17.9mA     26.85mA
-743.2mV  17.24mA    14.16mA    23.2mA
-456.8mV  3.872mA    3.378mA    5.352mA
-361.4mV  1.38mA     1.454mA    1.878mA
-218.2mV  56.55uA    161.4uA    60.38uA
2.979V    -171.1uA   -147.7uA   -202.3uA
[Pulldown]
-1.48V    -13.5mA    -15.6mA    -11.6mA
-1.145V   -13.7mA    -15.5mA    -12mA
-859.1mV  -15.01mA   -15.35mA   -14.6mA
-477.3mV  -11.29mA   -11.46mA   -11.01mA
715.9mV   17.67mA    17.55mA    17.64mA
1.05V     23.7mA     22.89mA    23.95mA
1.384V    26.91mA    25.4mA     27.53mA
2.196V    28.44mA    26.57mA    29.14mA
2.434V    27.04mA    23.99mA    29.12mA
2.53V     23.9mA     22.4mA     27.26mA
2.72V     20.4mA     21.4mA     19.2mA
2.959V    19.7mA     21mA       17.8mA
[Pullup]
-1.459V   12.3mA     14.6mA     10.3mA
-1.125V   12.6mA     14.36mA    10.91mA
-886.4mV  15.13mA    15.39mA    14.79mA
-504.5mV  11.5mA     11.66mA    11.22mA
-265.9mV  6.876mA    6.943mA    6.798mA
879.5mV   -21.27mA   -21.04mA   -21.3mA
1.309V    -29.1mA    -28.12mA   -29.25mA
1.691V    -33.44mA   -31.72mA   -33.57mA
2.168V    -35.42mA   -33.39mA   -35.21mA
2.407V    -34.51mA   -32.08mA   -35.53mA
2.741V    -28.4mA    -29.24mA   -26.46mA
2.979V    -27.6mA    -29mA      -24.76mA
[Ramp]
R_load=50.000Ohm
dV/dt_r   497.520mV/48.500ps  473.726mV/55.500ps  520.710mV/46.500ps
dV/dt_f   497.520mV/51.000ps  473.726mV/56.500ps  520.680mV/48.500ps
[Rising waveform]
R_fixture=50.000Ohm
V_fixture=1.500
V_fixture_min=1.425
V_fixture_max=1.575
0s        666.6mV    632mV      702.5mV
1.243ns   666.6mV    632mV      691.1mV
1.293ns   666.7mV    632mV      1.295V
1.343ns   648.5mV    632mV      1.503V
1.403ns   1.288V     632.9mV    1.553V
1.484ns   1.465V     711.9mV    1.567V
1.524ns   1.481V     1.155V     1.569V
1.554ns   1.487V     1.311V     1.569V
1.754ns   1.496V     1.418V     1.57V
10ns      1.496V     1.422V     1.57V
[Rising waveform]
R_fixture=50.000Ohm
V_fixture=0
0s        808nV      14.11uV    101.2nV
1.243ns   14.39uV    12.98uV    -11.13mV
1.323ns   488uV      28.12uV    725.8mV
1.353ns   11.2mV     -52.85uV   800.7mV
1.413ns   636.2mV    1.355mV    850.5mV
1.484ns   789.9mV    79.29mV    864.7mV
1.534ns   813.1mV    544.3mV    867.5mV
1.564ns   819.5mV    673.6mV    868.2mV
1.754ns   828.9mV    783.4mV    869.1mV
10ns      828.7mV    788.9mV    868.1mV
[Falling waveform]
R_fixture=50.000Ohm
V_fixture=1.500
V_fixture_min=1.425
V_fixture_max=1.575
0s        1.496V     1.422V     1.57V
1.253ns   1.496V     1.422V     1.596V
1.333ns   1.507V     1.422V     851.7mV
1.363ns   1.505V     1.422V     774.3mV
1.434ns   835.1mV    1.423V     717.5mV
1.494ns   711.8mV    1.412V     706.1mV
1.544ns   684.6mV    930.8mV    703.1mV
1.584ns   675.4mV    748.8mV    702.2mV
1.764ns   666.3mV    638.7mV    701.4mV
10ns      666.4mV    631.9mV    702.3mV
[Falling waveform]
R_fixture=50.000Ohm
V_fixture=0
0s        828.5mV    788.8mV    867.8mV
1.243ns   828.5mV    788.8mV    872.7mV
1.283ns   828.5mV    788.8mV    320.8mV
1.313ns   828.5mV    788.8mV    129.2mV
1.343ns   817.7mV    788.8mV    61.19mV
1.403ns   173.7mV    788.4mV    16.8mV
1.474ns   34.91mV    704.8mV    3.963mV
1.544ns   10.46mV    117.1mV    987.8uV
1.724ns   577.6uV    6.538mV    57.01uV
10ns      1.058uV    14.19uV    311.3nV
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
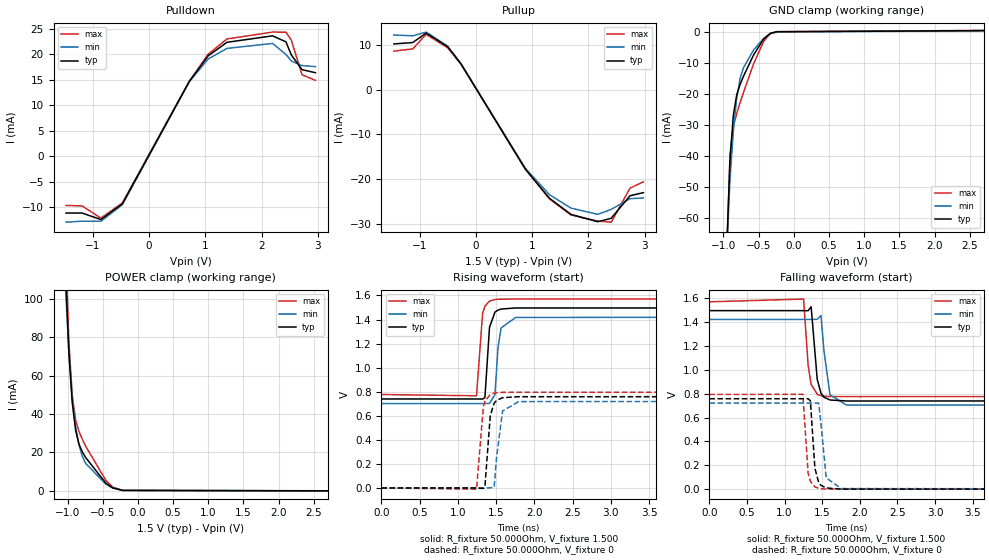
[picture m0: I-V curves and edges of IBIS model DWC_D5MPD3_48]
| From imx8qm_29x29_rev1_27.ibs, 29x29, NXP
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[Model] DWC_D5MPD3_48
Model_type   I/O
Polarity   Non-Inverting
Enable   Active-High
C_comp   1.449pF   1.359pF   1.562pF
C_comp_pullup   309.408fF   290.590fF   338.313fF
C_comp_pulldown 1.131pF   1.055pF   1.218pF
Vinh = 875.000mV
Vinl = 625.000mV
Vmeas = 750.000mV
Vref = 750.000mV
Rref = 50Ohms
Cref = 0pF
[Model Spec]
Vinh   875.000mV   838.000mV   913.000mV
Vinl   625.000mV   588.000mV   663.000mV
Vmeas   750.000mV   713.000mV   788.000mV
Vref   750.000mV   713.000mV   788.000mV
D_overshoot_ampl_h 0.4 NA   NA
D_overshoot_ampl_l 0.4 NA   NA
D_overshoot_area_l 100.000p NA   NA
D_overshoot_area_h 100.000p NA   NA
[Receiver Thresholds]
Vcross_low = 575.000mV
Vcross_high = 925.000mV
Vdiff_ac = 250.000mV
Vdiff_dc = 200.000mV
Tdiffslew_ac = 10.000ns
[Temperature Range]   25.000   125.000   -40.000
[Voltage Range]   1.500V   1.425V   1.575V
[GND Clamp Reference]   0.00V   0.00V   0.00V
[C Comp Corner]
| variable   typ   min   max
C_comp 1.449pF   1.562pF   1.359pF
C_comp_pullup 309.408fF   338.313fF   290.590fF
C_comp_pulldown 1.131pF   1.218pF   1.055pF
[Pulldown Reference]   0.00V   0.00V   0.00V
[POWER Clamp Reference]   1.500V   1.425V   1.575V
[Pullup Reference]   1.500V   1.425V   1.575V
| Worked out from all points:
|   slope of the pulldown table from 0 to 0.225 V, typ, clamps not added: 46.1 ohm
|   slope of the pullup table from 0 to 0.225 V, typ, clamps not added: 46.6 ohm
|   GND clamp passes 1 mA (typ) near -0.36 V on its own axis
|   POWER clamp passes 1 mA (typ) near -0.34 V on its own axis
|   rising waveform, R_fixture 50.000Ohm, V_fixture 1.500: 20-80 % time 48.9ps typ, 53.5ps min, 46.6ps max; typ from 0.74 V to 1.5 V
|   rising waveform, R_fixture 50.000Ohm, V_fixture 0: 20-80 % time 57ps typ, 64.7ps min, 54.3ps max; typ from 0 V to 0.758 V
|   falling waveform, R_fixture 50.000Ohm, V_fixture 1.500: 20-80 % time 62.1ps typ, 68.8ps min, 58.8ps max; typ from 1.5 V to 0.739 V
|   falling waveform, R_fixture 50.000Ohm, V_fixture 0: 20-80 % time 50.7ps typ, 56.1ps min, 47.2ps max; typ from 0.758 V to 0 V
[GND Clamp]
-1.48V    -953.7mA   -668.6mA   -1.235A
-1.002V   -100.2mA   -94.39mA   -105.7mA
-906.8mV  -41.27mA   -47.66mA   -39.94mA
-859.1mV  -26.94mA   -32.05mA   -30.57mA
-811.4mV  -20.4mA    -21.37mA   -26.37mA
-763.6mV  -17.03mA   -15.12mA   -22.94mA
-715.9mV  -14.41mA   -11.66mA   -19.65mA
-572.7mV  -7.58mA    -5.976mA   -10.46mA
-429.5mV  -2.403mA   -2.2mA     -3.204mA
-334.1mV  -541.6uA   -710uA     -592.8uA
-238.6mV  -34.76uA   -109.3uA   -17.5uA
2.959V    342.2uA    278.6uA    426.2uA
[Power Clamp]
-1.459V   879.2mA    638.3mA    1.105A
-1.03V    115.1mA    105.8mA    129.1mA
-981.8mV  71.94mA    72.39mA    77.67mA
-934.1mV  45.89mA    48.93mA    49.78mA
-886.4mV  31.62mA    33.58mA    36.91mA
-838.6mV  24.3mA     23.87mA    30.9mA
-790.9mV  20.23mA    17.9mA     26.85mA
-743.2mV  17.24mA    14.16mA    23.2mA
-456.8mV  3.872mA    3.378mA    5.352mA
-361.4mV  1.38mA     1.454mA    1.878mA
-218.2mV  56.55uA    161.4uA    60.38uA
2.979V    -171.1uA   -147.7uA   -202.3uA
[Pulldown]
-1.48V    -11.2mA    -13mA      -9.7mA
-1.193V   -11.2mA    -12.8mA    -9.8mA
-859.1mV  -12.48mA   -12.81mA   -12.2mA
-477.3mV  -9.392mA   -9.564mA   -9.208mA
715.9mV   14.71mA    14.65mA    14.77mA
1.05V     19.72mA    19.1mA     20.04mA
1.384V    22.38mA    21.18mA    23.04mA
2.196V    23.65mA    22.16mA    24.39mA
2.434V    22.48mA    19.99mA    24.37mA
2.53V     19.9mA     18.7mA     22.8mA
2.72V     17mA       17.8mA     16mA
2.959V    16.4mA     17.6mA     14.9mA
[Pullup]
-1.459V   10.2mA     12.2mA     8.6mA
-1.125V   10.5mA     12mA       9.072mA
-886.4mV  12.61mA    12.84mA    12.33mA
-504.5mV  9.588mA    9.734mA    9.362mA
-265.9mV  5.737mA    5.798mA    5.679mA
879.5mV   -17.74mA   -17.57mA   -17.79mA
1.309V    -24.26mA   -23.47mA   -24.41mA
1.691V    -27.86mA   -26.46mA   -28mA
2.168V    -29.5mA    -27.85mA   -29.34mA
2.407V    -28.73mA   -26.75mA   -29.6mA
2.741V    -23.7mA    -24.34mA   -22mA
2.979V    -23mA      -24.2mA    -20.6mA
[Ramp]
R_load=50.000Ohm
dV/dt_r   454.320mV/53.500ps  432.565mV/60.000ps  476.190mV/51.000ps
dV/dt_f   454.320mV/57.000ps  432.565mV/63.000ps  476.160mV/53.500ps
[Rising waveform]
R_fixture=50.000Ohm
V_fixture=1.500
V_fixture_min=1.425
V_fixture_max=1.575
0s        739.5mV    701.5mV    776.7mV
1.243ns   739.6mV    701.5mV    766.3mV
1.323ns   739.3mV    701.5mV    1.451V
1.353ns   751.2mV    701.4mV    1.511V
1.413ns   1.335V     702.8mV    1.553V
1.484ns   1.461V     776.1mV    1.566V
1.524ns   1.478V     1.165V     1.568V
1.564ns   1.487V     1.33V      1.569V
1.754ns   1.496V     1.417V     1.57V
10ns      1.496V     1.422V     1.57V
[Rising waveform]
R_fixture=50.000Ohm
V_fixture=0
0s        893.4nV    15.61uV    111.5nV
1.243ns   14.56uV    14.64uV    -10mV
1.333ns   -4.13mV    20.99uV    676.5mV
1.353ns   11.01mV    -46.32uV   719.6mV
1.423ns   601.2mV    1.413mV    777.4mV
1.474ns   704.5mV    6.691mV    788.8mV
1.504ns   727mV      246mV      791.8mV
1.584ns   750.3mV    639.6mV    794.8mV
1.794ns   758.5mV    717.8mV    795.5mV
10ns      758mV      721.5mV    794.4mV
[Falling waveform]
R_fixture=50.000Ohm
V_fixture=1.500
V_fixture_min=1.425
V_fixture_max=1.575
0s        1.496V     1.422V     1.57V
1.253ns   1.496V     1.422V     1.593V
1.313ns   1.495V     1.422V     1.037V
1.353ns   1.529V     1.422V     878.3mV
1.434ns   921.1mV    1.423V     795.2mV
1.484ns   803.5mV    1.455V     782.9mV
1.524ns   770.5mV    1.157V     778.8mV
1.604ns   747.3mV    790.2mV    776.1mV
1.824ns   738.9mV    705mV      775.3mV
10ns      739.3mV    701.4mV    776.4mV
[Falling waveform]
R_fixture=50.000Ohm
V_fixture=0
0s        757.8mV    721.4mV    794mV
1.243ns   757.8mV    721.4mV    794.8mV
1.313ns   757.9mV    721.4mV    132.3mV
1.343ns   741mV      721.4mV    65.41mV
1.403ns   174.5mV    721mV      18.92mV
1.454ns   55.51mV    721.7mV    6.952mV
1.484ns   32.05mV    543mV      3.889mV
1.554ns   10.06mV    94.78mV    1.025mV
1.754ns   446.3uV    4.927mV    51.07uV
10ns      1.045uV    15.8uV     320.3nV
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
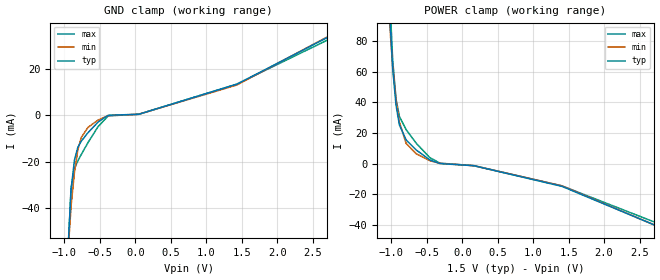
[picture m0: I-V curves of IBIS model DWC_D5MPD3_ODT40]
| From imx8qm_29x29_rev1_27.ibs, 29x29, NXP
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[Model] DWC_D5MPD3_ODT40
Model_type   Input
Polarity   Non-Inverting
Enable   Active-High
C_comp   1.679pF   1.676pF   1.722pF
C_comp_power_clamp   605.196fF   482.480fF   627.215fF
C_comp_gnd_clamp 1.108pF   1.035pF   1.191pF
Vinh = 875.000mV
Vinl = 625.000mV
[Model Spec]
D_overshoot_ampl_h 0.4 NA   NA
D_overshoot_ampl_l 0.4 NA   NA
D_overshoot_area_l 100.000p NA   NA
D_overshoot_area_h 100.000p NA   NA
[Receiver Thresholds]
Vcross_low = 575.000mV
Vcross_high = 925.000mV
Vdiff_ac = 250.000mV
Vdiff_dc = 200.000mV
Tdiffslew_ac = 10.000ns
[Temperature Range]   25.000   125.000   -40.000
[Voltage Range]   1.500V   1.425V   1.575V
[GND Clamp Reference]   0.00V   0.00V   0.00V
[C Comp Corner]
| variable   typ   min   max
C_comp 1.722pF   1.679pF   1.676pF
C_comp_pullup 605.196fF   482.480fF   627.215fF
C_comp_pulldown 1.108pF   1.191pF   1.035pF
[POWER Clamp Reference]   1.500V   1.425V   1.575V
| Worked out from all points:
|   GND clamp passes 1 mA (typ) near -0.44 V on its own axis
|   POWER clamp passes 1 mA (typ) near -0.39 V on its own axis
[GND Clamp]
-1.48V    -929.2mA   -647.1mA   -1.209A
-1.002V   -88.31mA   -83.74mA   -93.16mA
-906.8mV  -32.27mA   -39.23mA   -31.11mA
-859.1mV  -19.27mA   -24.62mA   -23.06mA
-811.4mV  -13.78mA   -14.92mA   -19.66mA
-763.6mV  -11.19mA   -9.557mA   -16.93mA
-668.2mV  -7.511mA   -5.225mA   -11.77mA
-525mV    -2.914mA   -2.058mA   -4.872mA
-381.8mV  -11.16uA   -146.4uA   -259.8uA
47.73mV   426.2uA    423.3uA    410uA
1.432V    13.38mA    13.03mA    13.42mA
2.959V    37.42mA    37.84mA    36.07mA
[Power Clamp]
-1.459V   858.1mA    619.9mA    1.082A
-1.03V    103.7mA    95.65mA    116.9mA
-981.8mV  62.57mA    63.59mA    68.09mA
-934.1mV  38.24mA    41.4mA     42.31mA
-886.4mV  25.23mA    27.13mA    30.78mA
-790.9mV  15.45mA    13.09mA    22.13mA
-647.7mV  8.857mA    6.395mA    13.2mA
-456.8mV  2.382mA    1.894mA    3.884mA
-313.6mV  16.11uA    155.5uA    281.1uA
163.6mV   -1.367mA   -1.371mA   -1.328mA
1.405V    -14.85mA   -14.52mA   -14.52mA
2.979V    -45.29mA   -45.33mA   -43.02mA
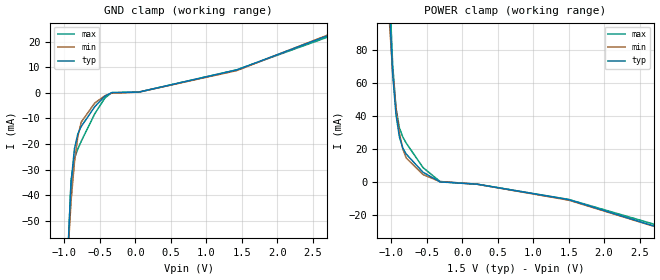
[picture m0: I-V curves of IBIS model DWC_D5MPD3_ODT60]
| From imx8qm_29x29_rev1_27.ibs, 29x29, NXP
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[Model] DWC_D5MPD3_ODT60
Model_type   Input
Polarity   Non-Inverting
Enable   Active-High
C_comp   1.626pF   1.561pF   1.645pF
C_comp_power_clamp   501.472fF   437.611fF   506.025fF
C_comp_gnd_clamp 1.115pF   1.040pF   1.201pF
Vinh = 875.000mV
Vinl = 625.000mV
[Model Spec]
D_overshoot_ampl_h 0.4 NA   NA
D_overshoot_ampl_l 0.4 NA   NA
D_overshoot_area_l 100.000p NA   NA
D_overshoot_area_h 100.000p NA   NA
[Receiver Thresholds]
Vcross_low = 575.000mV
Vcross_high = 925.000mV
Vdiff_ac = 250.000mV
Vdiff_dc = 200.000mV
Tdiffslew_ac = 10.000ns
[Temperature Range]   25.000   125.000   -40.000
[Voltage Range]   1.500V   1.425V   1.575V
[GND Clamp Reference]   0.00V   0.00V   0.00V
[C Comp Corner]
| variable   typ   min   max
C_comp 1.626pF   1.645pF   1.561pF
C_comp_pullup 501.472fF   437.611fF   506.025fF
C_comp_pulldown 1.115pF   1.201pF   1.040pF
[POWER Clamp Reference]   1.500V   1.425V   1.575V
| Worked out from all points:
|   GND clamp passes 1 mA (typ) near -0.41 V on its own axis
|   POWER clamp passes 1 mA (typ) near -0.37 V on its own axis
[GND Clamp]
-1.48V    -937.4mA   -654.3mA   -1.218A
-1.002V   -92.34mA   -87.36mA   -97.32mA
-906.8mV  -35.28mA   -42.04mA   -34.04mA
-859.1mV  -21.83mA   -27.1mA    -25.56mA
-811.4mV  -15.99mA   -17.06mA   -21.89mA
-763.6mV  -13.14mA   -11.41mA   -18.92mA
-572.7mV  -5.404mA   -3.968mA   -8.151mA
-429.5mV  -1.276mA   -1.15mA    -1.993mA
-334.1mV  81.7uA     -119.8uA   66.73uA
47.73mV   284.7uA    282.7uA    273.7uA
1.432V    8.94mA     8.704mA    9.008mA
2.959V    24.93mA    25.23mA    24.22mA
[Power Clamp]
-1.459V   865.2mA    626.1mA    1.09A
-1.03V    107.5mA    99.01mA    120.9mA
-981.8mV  65.69mA    66.51mA    71.23mA
-934.1mV  40.78mA    43.92mA    44.75mA
-886.4mV  27.36mA    29.28mA    32.78mA
-838.6mV  20.65mA    20.17mA    27.32mA
-790.9mV  17.04mA    14.7mA     23.67mA
-552.3mV  6.019mA    4.625mA    8.813mA
-313.6mV  224.5uA    378uA      466.4uA
211.4mV   -1.182mA   -1.19mA    -1.162mA
1.5V      -10.49mA   -10.78mA   -10.34mA
2.979V    -30.08mA   -30.19mA   -28.7mA
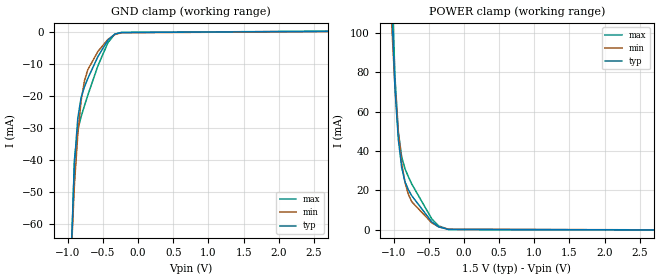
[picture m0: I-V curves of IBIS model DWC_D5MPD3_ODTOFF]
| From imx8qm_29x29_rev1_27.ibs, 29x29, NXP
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[Model] DWC_D5MPD3_ODTOFF
Model_type   Input
Polarity   Non-Inverting
Enable   Active-High
C_comp   1.449pF   1.359pF   1.562pF
C_comp_power_clamp   309.408fF   290.590fF   338.313fF
C_comp_gnd_clamp 1.131pF   1.055pF   1.218pF
Vinh = 875.000mV
Vinl = 625.000mV
[Model Spec]
D_overshoot_ampl_h 0.4 NA   NA
D_overshoot_ampl_l 0.4 NA   NA
D_overshoot_area_l 100.000p NA   NA
D_overshoot_area_h 100.000p NA   NA
[Receiver Thresholds]
Vcross_low = 575.000mV
Vcross_high = 925.000mV
Vdiff_ac = 250.000mV
Vdiff_dc = 200.000mV
Tdiffslew_ac = 10.000ns
[Temperature Range]   25.000   125.000   -40.000
[Voltage Range]   1.500V   1.425V   1.575V
[GND Clamp Reference]   0.00V   0.00V   0.00V
[C Comp Corner]
| variable   typ   min   max
C_comp 1.449pF   1.562pF   1.359pF
C_comp_pullup 309.408fF   338.313fF   290.590fF
C_comp_pulldown 1.131pF   1.218pF   1.055pF
[POWER Clamp Reference]   1.500V   1.425V   1.575V
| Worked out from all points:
|   GND clamp passes 1 mA (typ) near -0.36 V on its own axis
|   POWER clamp passes 1 mA (typ) near -0.34 V on its own axis
[GND Clamp]
-1.48V    -953.7mA   -668.6mA   -1.235A
-1.002V   -100.2mA   -94.39mA   -105.7mA
-906.8mV  -41.27mA   -47.66mA   -39.94mA
-859.1mV  -26.94mA   -32.05mA   -30.57mA
-811.4mV  -20.4mA    -21.37mA   -26.37mA
-763.6mV  -17.03mA   -15.12mA   -22.94mA
-715.9mV  -14.41mA   -11.66mA   -19.65mA
-572.7mV  -7.58mA    -5.976mA   -10.46mA
-429.5mV  -2.403mA   -2.2mA     -3.204mA
-334.1mV  -541.6uA   -710uA     -592.8uA
-238.6mV  -34.76uA   -109.3uA   -17.5uA
2.959V    342.2uA    278.6uA    426.2uA
[Power Clamp]
-1.459V   879.2mA    638.3mA    1.105A
-1.03V    115.1mA    105.8mA    129.1mA
-981.8mV  71.94mA    72.39mA    77.67mA
-934.1mV  45.89mA    48.93mA    49.78mA
-886.4mV  31.62mA    33.58mA    36.91mA
-838.6mV  24.3mA     23.87mA    30.9mA
-790.9mV  20.23mA    17.9mA     26.85mA
-743.2mV  17.24mA    14.16mA    23.2mA
-456.8mV  3.872mA    3.378mA    5.352mA
-361.4mV  1.38mA     1.454mA    1.878mA
-218.2mV  56.55uA    161.4uA    60.38uA
2.979V    -171.1uA   -147.7uA   -202.3uA
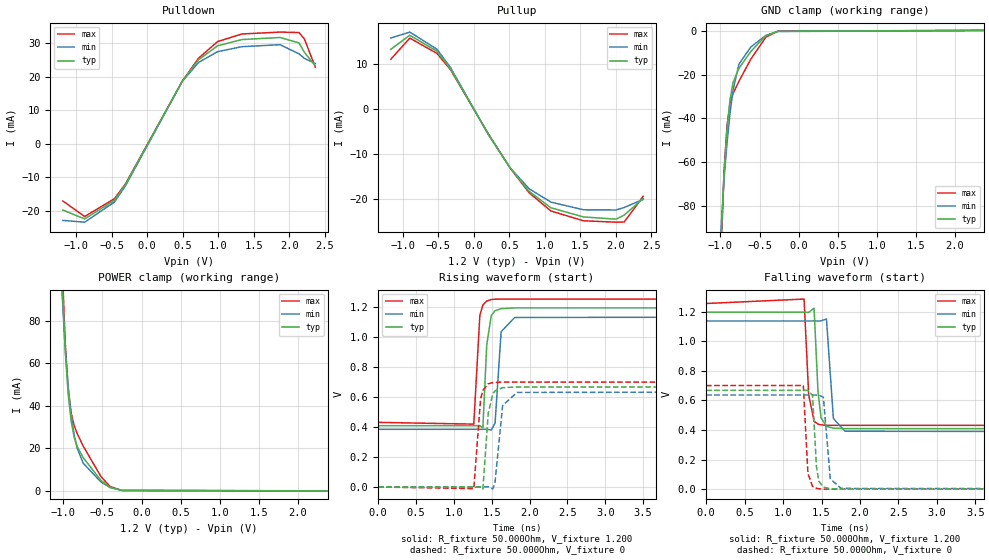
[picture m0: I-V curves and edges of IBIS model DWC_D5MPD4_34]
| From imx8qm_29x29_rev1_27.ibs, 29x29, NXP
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[Model] DWC_D5MPD4_34
Model_type   I/O
Polarity   Non-Inverting
Enable   Active-High
C_comp   1.452pF   1.359pF   1.567pF
C_comp_pullup   326.352fF   306.057fF   351.574fF
C_comp_pulldown 1.100pF   1.018pF   1.196pF
Vinh = 910.000mV
Vinl = 724.000mV
Vmeas = 817.000mV
Vref = 817.000mV
Rref = 50Ohms
Cref = 0pF
[Model Spec]
Vinh   910.000mV   869.000mV   951.000mV
Vinl   724.000mV   683.000mV   765.000mV
Vmeas   817.000mV   776.000mV   858.000mV
Vref   817.000mV   776.000mV   858.000mV
D_overshoot_ampl_h 0.4 NA   NA
D_overshoot_ampl_l 0.4 NA   NA
D_overshoot_area_l 60.000p NA   NA
D_overshoot_area_h 60.000p NA   NA
[Receiver Thresholds]
Vcross_low = 697.000mV
Vcross_high = 937.000mV
Vdiff_ac = 136.000mV
Vdiff_dc = 136.000mV
Tdiffslew_ac = 10.000ns
[Temperature Range]   25.000   125.000   -40.000
[Voltage Range]   1.200V   1.140V   1.260V
[GND Clamp Reference]   0.00V   0.00V   0.00V
[C Comp Corner]
| variable   typ   min   max
C_comp 1.452pF   1.567pF   1.359pF
C_comp_pullup 326.352fF   351.574fF   306.057fF
C_comp_pulldown 1.100pF   1.196pF   1.018pF
[Pulldown Reference]   0.00V   0.00V   0.00V
[POWER Clamp Reference]   1.200V   1.140V   1.260V
[Pullup Reference]   1.200V   1.140V   1.260V
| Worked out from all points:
|   slope of the pulldown table from 0 to 0.18 V, typ, clamps not added: 25.1 ohm
|   slope of the pullup table from 0 to 0.18 V, typ, clamps not added: 37.1 ohm
|   GND clamp passes 1 mA (typ) near -0.36 V on its own axis
|   POWER clamp passes 1 mA (typ) near -0.38 V on its own axis
|   rising waveform, R_fixture 50.000Ohm, V_fixture 1.200: 20-80 % time 44.4ps typ, 51.7ps min, 41.8ps max; typ from 0.409 V to 1.2 V
|   rising waveform, R_fixture 50.000Ohm, V_fixture 0: 20-80 % time 58.1ps typ, 69.2ps min, 53.1ps max; typ from 0 V to 0.668 V
|   falling waveform, R_fixture 50.000Ohm, V_fixture 1.200: 20-80 % time 47.1ps typ, 53.4ps min, 43.5ps max; typ from 1.2 V to 0.409 V
|   falling waveform, R_fixture 50.000Ohm, V_fixture 0: 20-80 % time 41.2ps typ, 49.9ps min, 35.4ps max; typ from 0.668 V to 0 V
[GND Clamp]
-1.184V   -348.5mA   -259.9mA   -439.9mA
-1.069V   -169.5mA   -142.4mA   -196.8mA
-1.031V   -126.4mA   -112.9mA   -139.4mA
-954.5mV  -65.34mA   -67.95mA   -63.85mA
-916.4mV  -45.2mA    -51.17mA   -43.27mA
-878.2mV  -31.45mA   -37.57mA   -33.15mA
-840mV    -23.64mA   -27.11mA   -28.67mA
-763.6mV  -17.03mA   -15.11mA   -22.94mA
-610.9mV  -9.282mA   -7.243mA   -12.78mA
-420mV    -2.151mA   -2.011mA   -2.842mA
-267.3mV  -90.01uA   -209.5uA   -60.56uA
2.367V    273.5uA    222.3uA    340.9uA
[Power Clamp]
-1.167V   319.3mA    247.1mA    390.6mA
-1.015V   97.56mA    92.13mA    106.5mA
-976.4mV  66.14mA    67.19mA    69.94mA
-938.2mV  45.51mA    48.6mA     48.18mA
-900mV    32.73mA    35.4mA     36.58mA
-861.8mV  25.19mA    26.24mA    30.62mA
-823.6mV  20.79mA    20mA       26.94mA
-747.3mV  15.56mA    12.93mA    21.03mA
-518.2mV  4.741mA    4.028mA    6.547mA
-403.6mV  1.468mA    1.527mA    1.973mA
-250.9mV  45.67uA    138.5uA    40.26uA
2.384V    -136.7uA   -117uA     -161.8uA
[Pulldown]
-1.184V   -19.8mA    -22.9mA    -17.1mA
-878.2mV  -22.44mA   -23.43mA   -21.73mA
-458.2mV  -16.9mA    -17.39mA   -16.4mA
-305.5mV  -12.28mA   -12.62mA   -12.05mA
496.4mV   18.72mA    18.68mA    18.73mA
725.5mV   25.13mA    24.32mA    25.6mA
992.7mV   29.29mA    27.54mA    30.54mA
1.336V    31.15mA    29.02mA    32.82mA
1.871V    31.77mA    29.61mA    33.38mA
2.138V    30.14mA    26.89mA    33.25mA
2.215V    27.29mA    25.5mA     31.27mA
2.367V    23.3mA     24mA       22.9mA
[Pullup]
-1.167V   13.3mA     15.8mA     11.09mA
-900mV    16.42mA    17.12mA    15.79mA
-518.2mV  12.88mA    13.33mA    12.4mA
-327.3mV  9.001mA    9.273mA    8.784mA
207.3mV   -5.564mA   -5.684mA   -5.511mA
512.7mV   -13.03mA   -13mA      -13.06mA
780mV     -18.22mA   -17.64mA   -18.53mA
1.085V    -21.84mA   -20.59mA   -22.55mA
1.544V    -23.88mA   -22.29mA   -24.73mA
2.002V    -24.37mA   -22.33mA   -25.04mA
2.116V    -23.46mA   -21.78mA   -25mA
2.384V    -19.8mA    -19.99mA   -19.3mA
[Ramp]
R_load=50.000Ohm
dV/dt_r   436.860mV/52.000ps  416.789mV/61.000ps  457.530mV/47.500ps
dV/dt_f   436.860mV/45.000ps  416.789mV/52.500ps  457.530mV/39.500ps
[Rising waveform]
R_fixture=50.000Ohm
V_fixture=1.200
V_fixture_min=1.140
V_fixture_max=1.260
0s        409.4mV    385.5mV    431.9mV
1.263ns   409.4mV    385.5mV    420.1mV
1.343ns   410.2mV    385.5mV    1.147V
1.383ns   394.8mV    385.4mV    1.216V
1.434ns   950.3mV    386.2mV    1.243V
1.494ns   1.147V     380.2mV    1.253V
1.544ns   1.178V     427.3mV    1.255V
1.624ns   1.192V     1.038V     1.256V
1.804ns   1.197V     1.133V     1.256V
10ns      1.197V     1.138V     1.256V
[Rising waveform]
R_fixture=50.000Ohm
V_fixture=0
0s        142.6nV    3.545uV    17.79nV
1.263ns   -3.534uV   -630.6nV   -11.16mV
1.353ns   89.42uV    -7.979uV   589mV
1.383ns   -14.6mV    -86.17uV   646.4mV
1.454ns   492.3mV    1.159mV    689.2mV
1.514ns   622.8mV    -13.43mV   697.6mV
1.544ns   642.6mV    34.65mV    699.2mV
1.644ns   663.9mV    544.4mV    700.9mV
1.834ns   668.5mV    632.1mV    701.1mV
10ns      668.5mV    637mV      700.8mV
[Falling waveform]
R_fixture=50.000Ohm
V_fixture=1.200
V_fixture_min=1.140
V_fixture_max=1.260
0s        1.197V     1.138V     1.256V
1.273ns   1.197V     1.138V     1.286V
1.333ns   1.196V     1.138V     638.2mV
1.403ns   1.224V     1.138V     458.5mV
1.454ns   659.6mV    1.137V     439.9mV
1.494ns   482.4mV    1.139V     435mV
1.564ns   425.1mV    1.151V     432.3mV
1.654ns   412.5mV    477.6mV    431.7mV
1.804ns   409.5mV    391.9mV    431.6mV
10ns      409.4mV    385.5mV    431.8mV
[Falling waveform]
R_fixture=50.000Ohm
V_fixture=0
0s        668.5mV    637mV      700.7mV
1.263ns   668.5mV    637mV      701.4mV
1.323ns   668.1mV    637mV      106.5mV
1.383ns   634.5mV    637mV      19.3mV
1.434ns   151.7mV    636.5mV    5.983mV
1.464ns   55.13mV    637.3mV    3.074mV
1.524ns   14.31mV    621.9mV    824.3uV
1.614ns   2.895mV    69.66mV    125.5uV
1.754ns   265.3uV    5.434mV    23.31uV
10ns      195.1nV    3.946uV    256.6nV
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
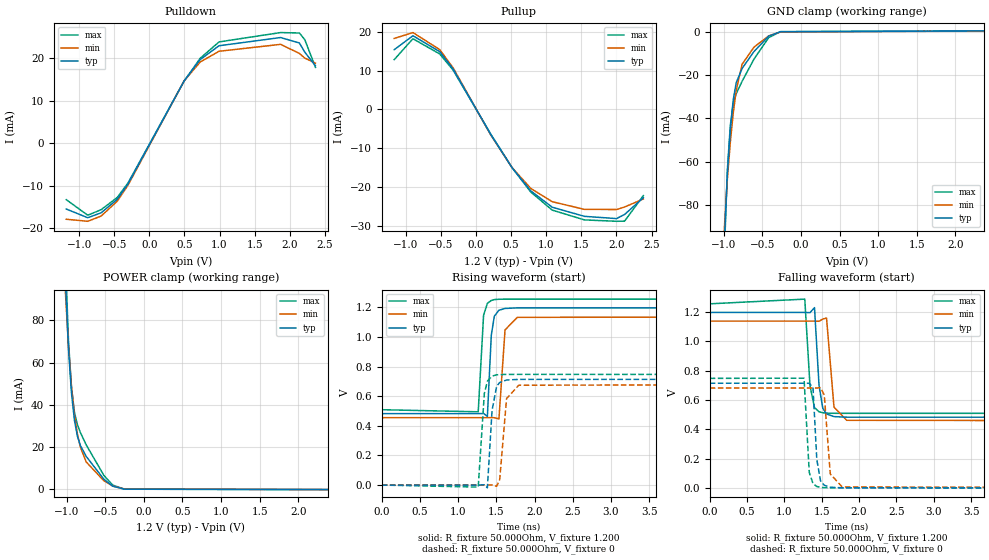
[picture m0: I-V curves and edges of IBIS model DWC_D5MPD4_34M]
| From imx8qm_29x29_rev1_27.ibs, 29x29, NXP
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[Model] DWC_D5MPD4_34M
Model_type   I/O
Polarity   Non-Inverting
Enable   Active-High
C_comp   1.453pF   1.359pF   1.567pF
C_comp_pullup   324.159fF   302.789fF   350.625fF
C_comp_pulldown 1.096pF   1.013pF   1.193pF
Vinh = 693.000mV
Vinl = 507.000mV
Vmeas = 600.000mV
Vref = 600.000mV
Rref = 50Ohms
Cref = 0pF
[Model Spec]
Vinh   693.000mV   663.000mV   723.000mV
Vinl   507.000mV   477.000mV   537.000mV
Vmeas   600.000mV   570.000mV   630.000mV
Vref   600.000mV   570.000mV   630.000mV
D_overshoot_ampl_h 0.4 NA   NA
D_overshoot_ampl_l 0.4 NA   NA
D_overshoot_area_l 60.000p NA   NA
D_overshoot_area_h 60.000p NA   NA
[Receiver Thresholds]
Vcross_low = 480.000mV
Vcross_high = 720.000mV
Vdiff_ac = 136.000mV
Vdiff_dc = 136.000mV
Tdiffslew_ac = 10.000ns
[Temperature Range]   25.000   125.000   -40.000
[Voltage Range]   1.200V   1.140V   1.260V
[GND Clamp Reference]   0.00V   0.00V   0.00V
[C Comp Corner]
| variable   typ   min   max
C_comp 1.453pF   1.567pF   1.359pF
C_comp_pullup 324.159fF   350.625fF   302.789fF
C_comp_pulldown 1.096pF   1.193pF   1.013pF
[Pulldown Reference]   0.00V   0.00V   0.00V
[POWER Clamp Reference]   1.200V   1.140V   1.260V
[Pullup Reference]   1.200V   1.140V   1.260V
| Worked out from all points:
|   slope of the pulldown table from 0 to 0.18 V, typ, clamps not added: 32 ohm
|   slope of the pullup table from 0 to 0.18 V, typ, clamps not added: 32.1 ohm
|   GND clamp passes 1 mA (typ) near -0.36 V on its own axis
|   POWER clamp passes 1 mA (typ) near -0.38 V on its own axis
|   rising waveform, R_fixture 50.000Ohm, V_fixture 1.200: 20-80 % time 40.6ps typ, 46.8ps min, 37.8ps max; typ from 0.482 V to 1.2 V
|   rising waveform, R_fixture 50.000Ohm, V_fixture 0: 20-80 % time 52.9ps typ, 62ps min, 49ps max; typ from 0 V to 0.714 V
|   falling waveform, R_fixture 50.000Ohm, V_fixture 1.200: 20-80 % time 55.6ps typ, 63ps min, 51.9ps max; typ from 1.2 V to 0.482 V
|   falling waveform, R_fixture 50.000Ohm, V_fixture 0: 20-80 % time 45.8ps typ, 54ps min, 40.9ps max; typ from 0.714 V to 0 V
[GND Clamp]
-1.184V   -348.5mA   -259.9mA   -439.9mA
-1.069V   -169.5mA   -142.4mA   -196.8mA
-1.031V   -126.4mA   -112.9mA   -139.4mA
-954.5mV  -65.34mA   -67.95mA   -63.85mA
-916.4mV  -45.2mA    -51.17mA   -43.27mA
-878.2mV  -31.45mA   -37.57mA   -33.15mA
-840mV    -23.64mA   -27.11mA   -28.67mA
-763.6mV  -17.03mA   -15.11mA   -22.94mA
-610.9mV  -9.282mA   -7.243mA   -12.78mA
-420mV    -2.151mA   -2.011mA   -2.842mA
-267.3mV  -90.01uA   -209.5uA   -60.56uA
2.367V    273.5uA    222.3uA    340.9uA
[Power Clamp]
-1.167V   319.3mA    247.1mA    390.6mA
-1.015V   97.56mA    92.13mA    106.5mA
-976.4mV  66.14mA    67.19mA    69.94mA
-938.2mV  45.51mA    48.6mA     48.18mA
-900mV    32.73mA    35.4mA     36.58mA
-861.8mV  25.19mA    26.24mA    30.62mA
-823.6mV  20.79mA    20mA       26.94mA
-747.3mV  15.56mA    12.93mA    21.03mA
-518.2mV  4.741mA    4.028mA    6.547mA
-403.6mV  1.468mA    1.527mA    1.973mA
-250.9mV  45.67uA    138.5uA    40.26uA
2.384V    -136.7uA   -117uA     -161.8uA
[Pulldown]
-1.184V   -15.5mA    -17.9mA    -13.3mA
-878.2mV  -17.54mA   -18.38mA   -16.95mA
-687.3mV  -16.38mA   -17.15mA   -15.65mA
-458.2mV  -13.22mA   -13.66mA   -12.79mA
-305.5mV  -9.62mA    -9.919mA   -9.404mA
496.4mV   14.65mA    14.67mA    14.62mA
725.5mV   19.66mA    19.09mA    19.97mA
992.7mV   22.9mA     21.6mA     23.8mA
1.871V    24.83mA    23.23mA    26mA
2.138V    23.55mA    21.09mA    25.9mA
2.215V    21.39mA    20mA       24.34mA
2.367V    18.2mA     18.8mA     17.8mA
[Pullup]
-1.167V   15.4mA     18.3mA     12.83mA
-900mV    19mA       19.82mA    18.23mA
-518.2mV  14.89mA    15.42mA    14.3mA
-327.3mV  10.4mA     10.72mA    10.12mA
207.3mV   -6.428mA   -6.573mA   -6.35mA
512.7mV   -15.06mA   -15.04mA   -15.05mA
780mV     -21.06mA   -20.42mA   -21.36mA
1.085V    -25.26mA   -23.84mA   -26.01mA
1.544V    -27.62mA   -25.82mA   -28.54mA
2.002V    -28.2mA    -25.86mA   -28.9mA
2.116V    -27.14mA   -25.21mA   -28.86mA
2.384V    -22.8mA    -23.14mA   -22.26mA
[Ramp]
R_load=50.000Ohm
dV/dt_r   428.700mV/47.000ps  409.289mV/54.500ps  448.470mV/44.000ps
dV/dt_f   428.700mV/52.000ps  409.289mV/58.500ps  448.470mV/46.500ps
[Rising waveform]
R_fixture=50.000Ohm
V_fixture=1.200
V_fixture_min=1.140
V_fixture_max=1.260
0s        482.4mV    455.1mV    509mV
1.263ns   482.4mV    455.1mV    494.9mV
1.333ns   483.6mV    455.1mV    1.147V
1.383ns   464.1mV    455mV      1.228V
1.434ns   1.012V     455.9mV    1.247V
1.474ns   1.141V     455mV      1.253V
1.534ns   1.181V     446.8mV    1.255V
1.614ns   1.193V     1.048V     1.256V
1.774ns   1.197V     1.133V     1.256V
10ns      1.197V     1.138V     1.256V
[Rising waveform]
R_fixture=50.000Ohm
V_fixture=0
0s        167nV      4.154uV    20.75nV
1.263ns   -3.103uV   -455.8nV   -13.65mV
1.343ns   1.46mV     6.766uV    618.9mV
1.383ns   -18.86mV   -102.7uV   701.5mV
1.444ns   503.6mV    1.04mV     735.8mV
1.504ns   666.9mV    -7.998mV   744.4mV
1.544ns   692.6mV    36.3mV     746.3mV
1.634ns   709.7mV    584.4mV    747.5mV
1.794ns   713.9mV    674.6mV    747.7mV
10ns      714mV      681.4mV    747.4mV
[Falling waveform]
R_fixture=50.000Ohm
V_fixture=1.200
V_fixture_min=1.140
V_fixture_max=1.260
0s        1.197V     1.138V     1.256V
1.273ns   1.197V     1.138V     1.288V
1.343ns   1.196V     1.138V     695mV
1.403ns   1.23V      1.138V     548.3mV
1.464ns   697mV      1.137V     519mV
1.514ns   543.6mV    1.152V     512.3mV
1.564ns   504.7mV    1.159V     509.9mV
1.664ns   486.2mV    551mV      508.8mV
1.834ns   482.4mV    461.1mV    508.6mV
10ns      482.4mV    455.1mV    508.9mV
[Falling waveform]
R_fixture=50.000Ohm
V_fixture=0
0s        714mV      681.4mV    747.3mV
1.263ns   714mV      681.4mV    748.4mV
1.333ns   713.7mV    681.4mV    105.2mV
1.383ns   685.2mV    681.4mV    29.02mV
1.434ns   192.7mV    681mV      9.502mV
1.484ns   47.31mV    684.1mV    3.311mV
1.534ns   17.46mV    632.6mV    1.168mV
1.614ns   4.428mV    95.02mV    234.2uV
1.774ns   318.8uV    5.976mV    29.4uV
10ns      435.6nV    4.465uV    217nV
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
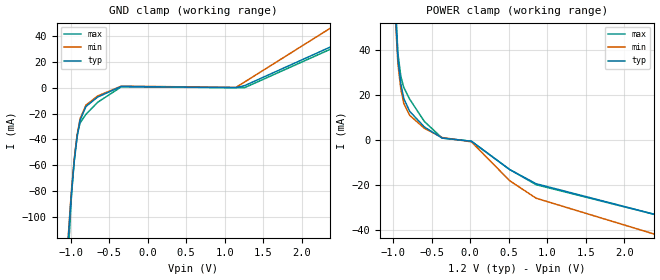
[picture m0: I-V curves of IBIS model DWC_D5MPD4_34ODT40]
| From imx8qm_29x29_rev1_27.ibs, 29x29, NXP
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[Model] DWC_D5MPD4_34ODT40
Model_type   Input
Polarity   Non-Inverting
Enable   Active-High
C_comp   1.578pF   1.488pF   1.614pF
C_comp_power_clamp   404.373fF   400.762fF   419.336fF
C_comp_gnd_clamp 1.147pF   1.051pF   1.172pF
Vinh = 969.000mV
Vinl = 783.000mV
[Model Spec]
D_overshoot_ampl_h 0.4 NA   NA
D_overshoot_ampl_l 0.4 NA   NA
D_overshoot_area_l 60.000p NA   NA
D_overshoot_area_h 60.000p NA   NA
[Receiver Thresholds]
Vcross_low = 756.000mV
Vcross_high = 996.000mV
Vdiff_ac = 136.000mV
Vdiff_dc = 136.000mV
Tdiffslew_ac = 10.000ns
[Temperature Range]   25.000   125.000   -40.000
[Voltage Range]   1.200V   1.140V   1.260V
[GND Clamp Reference]   0.00V   0.00V   0.00V
[C Comp Corner]
| variable   typ   min   max
C_comp 1.578pF   1.614pF   1.488pF
C_comp_pullup 404.373fF   419.336fF   400.762fF
C_comp_pulldown 1.147pF   1.172pF   1.051pF
[POWER Clamp Reference]   1.200V   1.140V   1.260V
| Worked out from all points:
|   GND clamp passes 1 mA (typ) near -0.23 V on its own axis
|   POWER clamp passes 1 mA (typ) near -0.37 V on its own axis
[GND Clamp]
-1.184V   -335.6mA   -332.5mA   -425.1mA
-1.031V   -116.9mA   -114.7mA   -128.9mA
-992.7mV  -83.49mA   -81.51mA   -86.45mA
-954.5mV  -57.59mA   -55.86mA   -55.87mA
-916.4mV  -38.2mA    -36.67mA   -36.44mA
-878.2mV  -25.22mA   -23.89mA   -27.25mA
-801.8mV  -14.48mA   -13.41mA   -20.55mA
-649.1mV  -7.14mA    -6.302mA   -11.18mA
-343.6mV  1.082mA    1.317mA    746.2uA
1.145V    129.6uA    297.9uA    156.3uA
1.26V     1.743mA    4.593mA    179.4uA
2.367V    31.54mA    46.13mA    29.82mA
[Power Clamp]
-1.167V   301.4mA    294.7mA    370.6mA
-1.015V   85.37mA    82.07mA    93.29mA
-938.2mV  36.59mA    34.09mA    38.7mA
-900mV    25.05mA    22.74mA    28.41mA
-861.8mV  18.56mA    16.4mA     23.46mA
-785.5mV  12.88mA    11.09mA    18.28mA
-594.5mV  5.91mA     5.311mA    8.354mA
-365.5mV  963.6uA    1.22mA     1.006mA
16.4mV    -448.7uA   -702.8uA   -440.4uA
512.7mV   -13.01mA   -17.97mA   -13.03mA
856.4mV   -19.34mA   -25.78mA   -19.76mA
2.384V    -32.85mA   -41.67mA   -32.91mA
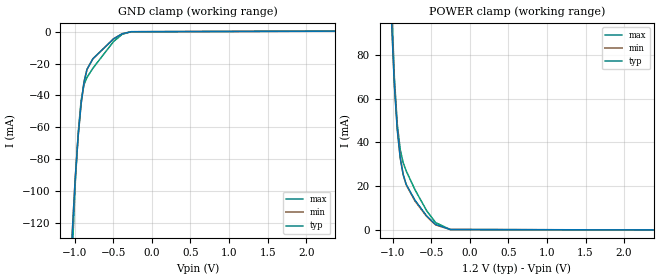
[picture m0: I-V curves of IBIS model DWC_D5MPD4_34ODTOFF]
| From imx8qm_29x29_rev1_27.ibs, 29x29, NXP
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[Model] DWC_D5MPD4_34ODTOFF
Model_type   Input
Polarity   Non-Inverting
Enable   Active-High
C_comp   1.453pF   1.359pF   1.453pF
C_comp_power_clamp   324.159fF   302.789fF   327.259fF
C_comp_gnd_clamp 1.096pF   1.013pF   1.099pF
Vinh = 910.000mV
Vinl = 724.000mV
[Model Spec]
D_overshoot_ampl_h 0.4 NA   NA
D_overshoot_ampl_l 0.4 NA   NA
D_overshoot_area_l 60.000p NA   NA
D_overshoot_area_h 60.000p NA   NA
[Receiver Thresholds]
Vcross_low = 697.000mV
Vcross_high = 937.000mV
Vdiff_ac = 136.000mV
Vdiff_dc = 136.000mV
Tdiffslew_ac = 10.000ns
[Temperature Range]   25.000   125.000   -40.000
[Voltage Range]   1.200V   1.140V   1.260V
[GND Clamp Reference]   0.00V   0.00V   0.00V
[C Comp Corner]
| variable   typ   min   max
C_comp 1.453pF   1.453pF   1.359pF
C_comp_pullup 324.159fF   327.259fF   302.789fF
C_comp_pulldown 1.096pF   1.099pF   1.013pF
[POWER Clamp Reference]   1.200V   1.140V   1.260V
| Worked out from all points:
|   GND clamp passes 1 mA (typ) near -0.36 V on its own axis
|   POWER clamp passes 1 mA (typ) near -0.38 V on its own axis
[GND Clamp]
-1.184V   -348.5mA   -348.4mA   -439.9mA
-1.031V   -126.4mA   -126.3mA   -139.4mA
-992.7mV  -92.04mA   -91.97mA   -95.58mA
-954.5mV  -65.34mA   -65.3mA    -63.85mA
-916.4mV  -45.2mA    -45.17mA   -43.27mA
-878.2mV  -31.45mA   -31.43mA   -33.15mA
-840mV    -23.64mA   -23.63mA   -28.67mA
-763.6mV  -17.03mA   -17.02mA   -22.94mA
-496.4mV  -4.53mA    -4.53mA    -6.229mA
-381.8mV  -1.287mA   -1.287mA   -1.614mA
-267.3mV  -90.01uA   -90.01uA   -60.56uA
2.367V    273.5uA    273.4uA    340.9uA
[Power Clamp]
-1.167V   319.3mA    319.4mA    390.6mA
-1.015V   97.56mA    98.58mA    106.5mA
-976.4mV  66.14mA    67.1mA     69.94mA
-938.2mV  45.51mA    46.08mA    48.18mA
-900mV    32.73mA    32.97mA    36.58mA
-861.8mV  25.19mA    25.17mA    30.62mA
-823.6mV  20.79mA    20.56mA    26.94mA
-709.1mV  13.45mA    13.1mA     18.28mA
-556.4mV  6.219mA    5.945mA    8.571mA
-441.8mV  2.34mA     2.177mA    3.207mA
-250.9mV  45.67uA    42.22uA    40.26uA
2.384V    -136.7uA   -143.7uA   -161.8uA
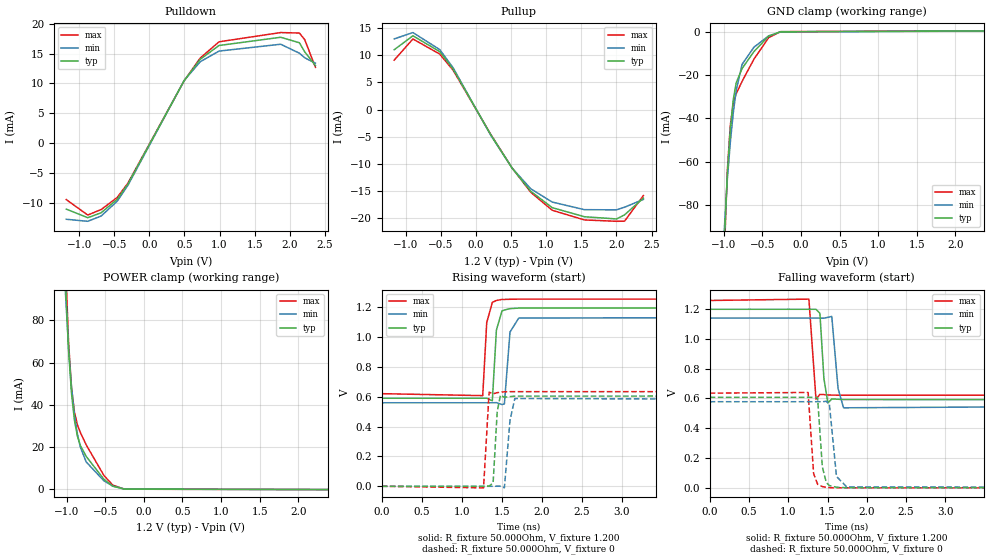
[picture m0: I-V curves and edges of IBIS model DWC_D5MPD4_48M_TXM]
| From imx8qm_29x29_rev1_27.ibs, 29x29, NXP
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[Model] DWC_D5MPD4_48M_TXM
Model_type   I/O
Polarity   Non-Inverting
Enable   Active-High
C_comp   1.453pF   1.359pF   1.567pF
C_comp_pullup   324.720fF   303.353fF   351.193fF
C_comp_pulldown 1.095pF   1.013pF   1.192pF
Vinh = 693.000mV
Vinl = 507.000mV
Vmeas = 600.000mV
Vref = 600.000mV
Rref = 50Ohms
Cref = 0pF
[Model Spec]
Vinh   693.000mV   663.000mV   723.000mV
Vinl   507.000mV   477.000mV   537.000mV
Vmeas   600.000mV   570.000mV   630.000mV
Vref   600.000mV   570.000mV   630.000mV
D_overshoot_ampl_h 0.4 NA   NA
D_overshoot_ampl_l 0.4 NA   NA
D_overshoot_area_l 60.000p NA   NA
D_overshoot_area_h 60.000p NA   NA
[Receiver Thresholds]
Vcross_low = 480.000mV
Vcross_high = 720.000mV
Vdiff_ac = 136.000mV
Vdiff_dc = 136.000mV
Tdiffslew_ac = 10.000ns
[Temperature Range]   25.000   125.000   -40.000
[Voltage Range]   1.200V   1.140V   1.260V
[GND Clamp Reference]   0.00V   0.00V   0.00V
[C Comp Corner]
| variable   typ   min   max
C_comp 1.453pF   1.567pF   1.359pF
C_comp_pullup 324.720fF   351.193fF   303.353fF
C_comp_pulldown 1.095pF   1.192pF   1.013pF
[Pulldown Reference]   0.00V   0.00V   0.00V
[POWER Clamp Reference]   1.200V   1.140V   1.260V
[Pullup Reference]   1.200V   1.140V   1.260V
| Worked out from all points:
|   slope of the pulldown table from 0 to 0.18 V, typ, clamps not added: 44.8 ohm
|   slope of the pullup table from 0 to 0.18 V, typ, clamps not added: 44.9 ohm
|   GND clamp passes 1 mA (typ) near -0.36 V on its own axis
|   POWER clamp passes 1 mA (typ) near -0.38 V on its own axis
|   rising waveform, R_fixture 50.000Ohm, V_fixture 1.200: 20-80 % time 40.2ps typ, 47.8ps min, 34.6ps max; typ from 0.591 V to 1.2 V
|   rising waveform, R_fixture 50.000Ohm, V_fixture 0: 20-80 % time 37.8ps typ, 50.4ps min, 30.3ps max; typ from 0 V to 0.607 V
|   falling waveform, R_fixture 50.000Ohm, V_fixture 1.200: 20-80 % time 42.7ps typ, 54ps min, 34.3ps max; typ from 1.2 V to 0.591 V
|   falling waveform, R_fixture 50.000Ohm, V_fixture 0: 20-80 % time 46.6ps typ, 56.1ps min, 38.7ps max; typ from 0.607 V to 0 V
[GND Clamp]
-1.184V   -348.5mA   -259.9mA   -439.9mA
-1.069V   -169.5mA   -142.4mA   -196.8mA
-1.031V   -126.4mA   -112.9mA   -139.4mA
-954.5mV  -65.34mA   -67.95mA   -63.85mA
-916.4mV  -45.2mA    -51.17mA   -43.27mA
-878.2mV  -31.45mA   -37.57mA   -33.15mA
-840mV    -23.64mA   -27.11mA   -28.67mA
-763.6mV  -17.03mA   -15.11mA   -22.94mA
-610.9mV  -9.282mA   -7.243mA   -12.78mA
-420mV    -2.151mA   -2.011mA   -2.842mA
-267.3mV  -90.01uA   -209.5uA   -60.56uA
2.367V    273.5uA    222.3uA    340.9uA
[Power Clamp]
-1.167V   319.3mA    247.1mA    390.6mA
-1.015V   97.56mA    92.13mA    106.5mA
-976.4mV  66.14mA    67.19mA    69.94mA
-938.2mV  45.51mA    48.6mA     48.18mA
-900mV    32.73mA    35.4mA     36.58mA
-861.8mV  25.19mA    26.24mA    30.62mA
-823.6mV  20.79mA    20mA       26.94mA
-747.3mV  15.56mA    12.93mA    21.03mA
-518.2mV  4.741mA    4.028mA    6.547mA
-403.6mV  1.468mA    1.527mA    1.973mA
-250.9mV  45.67uA    138.5uA    40.26uA
2.384V    -136.7uA   -117uA     -161.8uA
[Pulldown]
-1.184V   -11.1mA    -12.8mA    -9.5mA
-878.2mV  -12.54mA   -13.14mA   -12.09mA
-687.3mV  -11.71mA   -12.26mA   -11.17mA
-458.2mV  -9.454mA   -9.768mA   -9.139mA
-305.5mV  -6.881mA   -7.099mA   -6.728mA
496.4mV   10.48mA    10.5mA     10.46mA
725.5mV   14.06mA    13.65mA    14.27mA
992.7mV   16.37mA    15.43mA    16.99mA
1.871V    17.75mA    16.58mA    18.54mA
2.138V    16.83mA    15.08mA    18.46mA
2.215V    15.29mA    14.3mA     17.33mA
2.367V    13mA       13.4mA     12.7mA
[Pullup]
-1.167V   11mA       13mA       9.086mA
-900mV    13.57mA    14.16mA    12.98mA
-518.2mV  10.65mA    11.03mA    10.2mA
-327.3mV  7.445mA    7.678mA    7.233mA
207.3mV   -4.603mA   -4.707mA   -4.538mA
512.7mV   -10.78mA   -10.76mA   -10.75mA
780mV     -15.06mA   -14.6mA    -15.24mA
1.085V    -18.06mA   -17.03mA   -18.54mA
1.544V    -19.73mA   -18.43mA   -20.32mA
2.002V    -20.14mA   -18.46mA   -20.57mA
2.116V    -19.38mA   -17.98mA   -20.54mA
2.384V    -16.3mA    -16.54mA   -15.84mA
[Ramp]
R_load=50.000Ohm
dV/dt_r   363.870mV/39.500ps  346.318mV/49.500ps  380.760mV/33.000ps
dV/dt_f   363.840mV/45.000ps  346.348mV/55.500ps  380.760mV/36.500ps
[Rising waveform]
R_fixture=50.000Ohm
V_fixture=1.200
V_fixture_min=1.140
V_fixture_max=1.260
0s        590.9mV    560.6mV    621.6mV
1.263ns   590.9mV    560.6mV    608.4mV
1.313ns   591.2mV    560.6mV    1.098V
1.383ns   573.7mV    560.5mV    1.234V
1.434ns   1.048V     561.4mV    1.247V
1.504ns   1.177V     548.4mV    1.254V
1.534ns   1.183V     553.5mV    1.254V
1.604ns   1.192V     1.035V     1.255V
1.714ns   1.196V     1.129V     1.256V
10ns      1.197V     1.138V     1.256V
[Rising waveform]
R_fixture=50.000Ohm
V_fixture=0
0s        202.7nV    5.054uV    25.11nV
1.273ns   -34.45uV   897.3nV    -10.51mV
1.343ns   1.423mV    8.987uV    631.2mV
1.393ns   23.09mV    -106.9uV   620.6mV
1.444ns   500.1mV    927uV      628.3mV
1.484ns   611.3mV    306.5uV    631.9mV
1.534ns   596.9mV    -10.32mV   634.1mV
1.604ns   602mV      442.6mV    635.1mV
1.664ns   605mV      588.8mV    635.3mV
10ns      607mV      577.4mV    635mV
[Falling waveform]
R_fixture=50.000Ohm
V_fixture=1.200
V_fixture_min=1.140
V_fixture_max=1.260
0s        1.197V     1.138V     1.256V
1.263ns   1.197V     1.138V     1.265V
1.353ns   1.197V     1.138V     595mV
1.403ns   1.17V      1.138V     626.5mV
1.454ns   733.1mV    1.137V     625.1mV
1.504ns   569.2mV    1.143V     622.8mV
1.554ns   595.6mV    1.149V     621.8mV
1.634ns   594mV      666.1mV    621.2mV
1.704ns   591.8mV    536.6mV    621.1mV
10ns      590.9mV    560.5mV    621.5mV
[Falling waveform]
R_fixture=50.000Ohm
V_fixture=0
0s        606.9mV    577.4mV    634.9mV
1.253ns   606.9mV    577.4mV    639.2mV
1.323ns   606.6mV    577.4mV    95.52mV
1.373ns   605.2mV    577.4mV    24.49mV
1.434ns   140.4mV    577mV      8.637mV
1.484ns   36.72mV    580.6mV    3.321mV
1.524ns   15.22mV    558.5mV    1.535mV
1.614ns   4.474mV    76.39mV    282uV
1.744ns   592.9uV    6.516mV    43.91uV
10ns      503.7nV    5.291uV    214.6nV
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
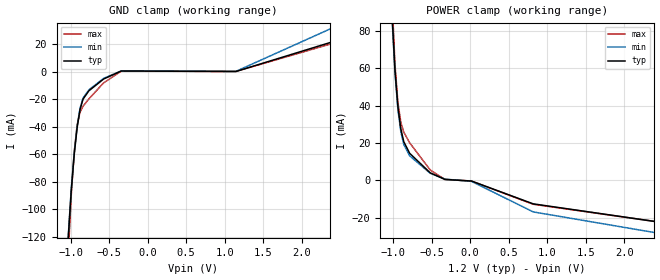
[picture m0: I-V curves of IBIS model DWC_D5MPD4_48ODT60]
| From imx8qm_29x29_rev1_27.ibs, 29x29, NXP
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[Model] DWC_D5MPD4_48ODT60
Model_type   Input
Polarity   Non-Inverting
Enable   Active-High
C_comp   1.533pF   1.446pF   1.559pF
C_comp_power_clamp   375.327fF   370.009fF   388.352fF
C_comp_gnd_clamp 1.131pF   1.040pF   1.149pF
Vinh = 960.000mV
Vinl = 774.000mV
[Model Spec]
D_overshoot_ampl_h 0.4 NA   NA
D_overshoot_ampl_l 0.4 NA   NA
D_overshoot_area_l 60.000p NA   NA
D_overshoot_area_h 60.000p NA   NA
[Receiver Thresholds]
Vcross_low = 747.000mV
Vcross_high = 987.000mV
Vdiff_ac = 136.000mV
Vdiff_dc = 136.000mV
Tdiffslew_ac = 10.000ns
[Temperature Range]   25.000   125.000   -40.000
[Voltage Range]   1.200V   1.140V   1.260V
[GND Clamp Reference]   0.00V   0.00V   0.00V
[C Comp Corner]
| variable   typ   min   max
C_comp 1.533pF   1.559pF   1.446pF
C_comp_pullup 375.327fF   388.352fF   370.009fF
C_comp_pulldown 1.131pF   1.149pF   1.040pF
[POWER Clamp Reference]   1.200V   1.140V   1.260V
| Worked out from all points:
|   GND clamp passes 1 mA (typ) near -0.44 V on its own axis
|   POWER clamp passes 1 mA (typ) near -0.37 V on its own axis
[GND Clamp]
-1.184V   -339.9mA   -337.8mA   -430.1mA
-1.031V   -120mA     -118.6mA   -132.4mA
-992.7mV  -86.35mA   -85.05mA   -89.56mA
-954.5mV  -60.21mA   -59.04mA   -58.58mA
-916.4mV  -40.57mA   -39.54mA   -38.77mA
-878.2mV  -27.32mA   -26.44mA   -29.27mA
-840mV    -19.95mA   -19.18mA   -25.1mA
-763.6mV  -13.87mA   -13.2mA    -19.75mA
-572.7mV  -5.34mA    -4.858mA   -8.16mA
-343.6mV  491.7uA    546.1uA    424.7uA
1.145V    129.5uA    242.9uA    156.8uA
2.367V    21.11mA    30.98mA    19.97mA
[Power Clamp]
-1.167V   307.3mA    302.8mA    377.3mA
-1.015V   89.44mA    87.44mA    97.66mA
-976.4mV  59.16mA    57.6mA     62.45mA
-938.2mV  39.53mA    37.98mA    41.83mA
-900mV    27.58mA    26.06mA    31.11mA
-861.8mV  20.74mA    19.24mA    25.82mA
-785.5mV  14.53mA    13.18mA    20.13mA
-518.2mV  4.065mA    3.834mA    5.604mA
-327.3mV  550.4uA    734uA      526.9uA
16.4mV    -298.8uA   -470.3uA   -293uA
818.2mV   -12.5mA    -16.8mA    -12.72mA
2.384V    -21.84mA   -27.77mA   -21.85mA
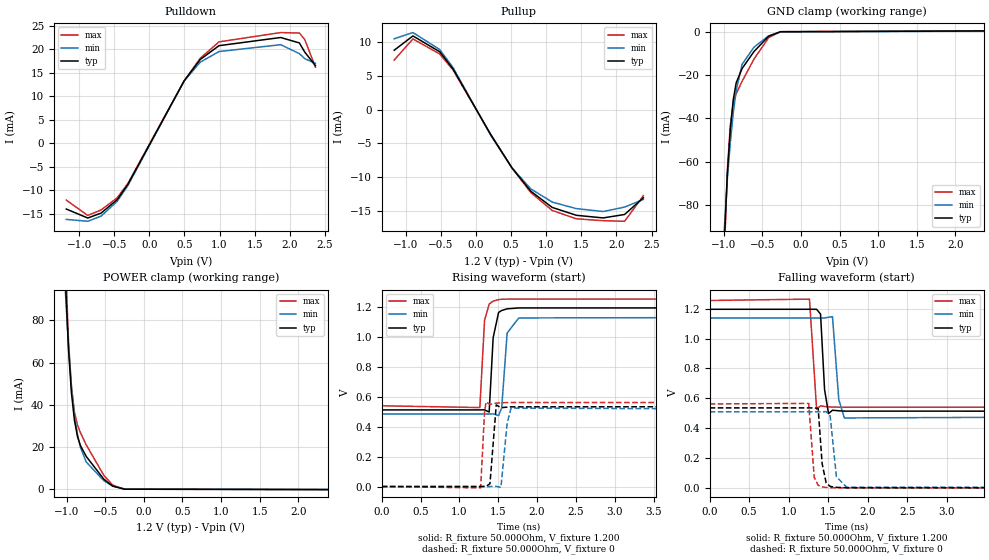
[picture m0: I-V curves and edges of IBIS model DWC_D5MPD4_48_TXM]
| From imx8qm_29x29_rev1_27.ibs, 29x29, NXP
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[Model] DWC_D5MPD4_48_TXM
Model_type   I/O
Polarity   Non-Inverting
Enable   Active-High
C_comp   1.452pF   1.359pF   1.567pF
C_comp_pullup   326.847fF   306.562fF   352.081fF
C_comp_pulldown 1.100pF   1.017pF   1.196pF
Vinh = 960.000mV
Vinl = 774.000mV
Vmeas = 867.000mV
Vref = 867.000mV
Rref = 50Ohms
Cref = 0pF
[Model Spec]
Vinh   960.000mV   917.000mV   1.003V
Vinl   774.000mV   731.000mV   817.000mV
Vmeas   867.000mV   823.000mV   910.000mV
Vref   867.000mV   823.000mV   910.000mV
D_overshoot_ampl_h 0.4 NA   NA
D_overshoot_ampl_l 0.4 NA   NA
D_overshoot_area_l 60.000p NA   NA
D_overshoot_area_h 60.000p NA   NA
[Receiver Thresholds]
Vcross_low = 747.000mV
Vcross_high = 987.000mV
Vdiff_ac = 136.000mV
Vdiff_dc = 136.000mV
Tdiffslew_ac = 10.000ns
[Temperature Range]   25.000   125.000   -40.000
[Voltage Range]   1.200V   1.140V   1.260V
[GND Clamp Reference]   0.00V   0.00V   0.00V
[C Comp Corner]
| variable   typ   min   max
C_comp 1.452pF   1.567pF   1.359pF
C_comp_pullup 326.847fF   352.081fF   306.562fF
C_comp_pulldown 1.100pF   1.196pF   1.017pF
[Pulldown Reference]   0.00V   0.00V   0.00V
[POWER Clamp Reference]   1.200V   1.140V   1.260V
[Pullup Reference]   1.200V   1.140V   1.260V
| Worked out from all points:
|   slope of the pulldown table from 0 to 0.18 V, typ, clamps not added: 35.3 ohm
|   slope of the pullup table from 0 to 0.18 V, typ, clamps not added: 55.7 ohm
|   GND clamp passes 1 mA (typ) near -0.36 V on its own axis
|   POWER clamp passes 1 mA (typ) near -0.38 V on its own axis
|   rising waveform, R_fixture 50.000Ohm, V_fixture 1.200: 20-80 % time 43.2ps typ, 52.1ps min, 37ps max; typ from 0.513 V to 1.2 V
|   rising waveform, R_fixture 50.000Ohm, V_fixture 0: 20-80 % time 37.8ps typ, 52ps min, 30ps max; typ from 0 V to 0.536 V
|   falling waveform, R_fixture 50.000Ohm, V_fixture 1.200: 20-80 % time 41ps typ, 51.6ps min, 34ps max; typ from 1.2 V to 0.513 V
|   falling waveform, R_fixture 50.000Ohm, V_fixture 0: 20-80 % time 42.5ps typ, 53ps min, 35.8ps max; typ from 0.536 V to 0 V
[GND Clamp]
-1.184V   -348.5mA   -259.9mA   -439.9mA
-1.069V   -169.5mA   -142.4mA   -196.8mA
-1.031V   -126.4mA   -112.9mA   -139.4mA
-954.5mV  -65.34mA   -67.95mA   -63.85mA
-916.4mV  -45.2mA    -51.17mA   -43.27mA
-878.2mV  -31.45mA   -37.57mA   -33.15mA
-840mV    -23.64mA   -27.11mA   -28.67mA
-763.6mV  -17.03mA   -15.11mA   -22.94mA
-610.9mV  -9.282mA   -7.243mA   -12.78mA
-420mV    -2.151mA   -2.011mA   -2.842mA
-267.3mV  -90.01uA   -209.5uA   -60.56uA
2.367V    273.5uA    222.3uA    340.9uA
[Power Clamp]
-1.167V   319.3mA    247.1mA    390.6mA
-1.015V   97.56mA    92.13mA    106.5mA
-976.4mV  66.14mA    67.19mA    69.94mA
-938.2mV  45.51mA    48.6mA     48.18mA
-900mV    32.73mA    35.4mA     36.58mA
-861.8mV  25.19mA    26.24mA    30.62mA
-823.6mV  20.79mA    20mA       26.94mA
-747.3mV  15.56mA    12.93mA    21.03mA
-518.2mV  4.741mA    4.028mA    6.547mA
-403.6mV  1.468mA    1.527mA    1.973mA
-250.9mV  45.67uA    138.5uA    40.26uA
2.384V    -136.7uA   -117uA     -161.8uA
[Pulldown]
-1.184V   -14mA      -16.2mA    -12.1mA
-878.2mV  -15.91mA   -16.61mA   -15.36mA
-687.3mV  -14.86mA   -15.5mA    -14.19mA
-458.2mV  -11.99mA   -12.35mA   -11.6mA
-305.5mV  -8.728mA   -8.971mA   -8.534mA
496.4mV   13.3mA     13.27mA    13.27mA
725.5mV   17.84mA    17.26mA    18.11mA
992.7mV   20.77mA    19.52mA    21.58mA
1.871V    22.51mA    20.98mA    23.56mA
2.138V    21.35mA    19.08mA    23.46mA
2.215V    19.39mA    18mA       22.05mA
2.367V    16.5mA     17mA       16.2mA
[Pullup]
-1.167V   8.8mA      10.5mA     7.343mA
-900mV    10.92mA    11.42mA    10.48mA
-518.2mV  8.571mA    8.902mA    8.242mA
-327.3mV  5.998mA    6.202mA    5.848mA
207.3mV   -3.708mA   -3.802mA   -3.67mA
512.7mV   -8.682mA   -8.689mA   -8.694mA
780mV     -12.13mA   -11.78mA   -12.32mA
1.085V    -14.53mA   -13.74mA   -14.98mA
1.429V    -15.7mA    -14.71mA   -16.22mA
1.811V    -16.09mA   -15.14mA   -16.5mA
2.116V    -15.58mA   -14.48mA   -16.59mA
2.384V    -13.1mA    -13.34mA   -12.79mA
[Ramp]
R_load=50.000Ohm
dV/dt_r   365.700mV/40.500ps  348.119mV/53.000ps  382.980mV/34.000ps
dV/dt_f   365.670mV/43.000ps  348.119mV/53.000ps  382.980mV/35.500ps
[Rising waveform]
R_fixture=50.000Ohm
V_fixture=1.200
V_fixture_min=1.140
V_fixture_max=1.260
0s        513.1mV    485.8mV    540.8mV
1.263ns   513.1mV    485.8mV    528.9mV
1.323ns   513.8mV    485.8mV    1.112V
1.383ns   498.8mV    485.7mV    1.222V
1.434ns   996.4mV    486.6mV    1.242V
1.504ns   1.166V     475mV      1.252V
1.544ns   1.179V     527mV      1.254V
1.614ns   1.19V      1.028V     1.255V
1.764ns   1.196V     1.129V     1.255V
10ns      1.196V     1.137V     1.255V
[Rising waveform]
R_fixture=50.000Ohm
V_fixture=0
0s        177.3nV    4.419uV    22.13nV
1.273ns   -30.15uV   669.1nV    -8.883mV
1.323ns   519.3uV    17.04uV    495.9mV
1.343ns   1.208mV    7.375uV    566.6mV
1.393ns   18.81mV    -88.65uV   550.1mV
1.474ns   546.5mV    1.071mV    558.4mV
1.534ns   528.1mV    -5.764mV   561.1mV
1.614ns   531.6mV    422.8mV    562.2mV
1.664ns   533.8mV    525.2mV    562.4mV
10ns      535.7mV    508.9mV    562.1mV
[Falling waveform]
R_fixture=50.000Ohm
V_fixture=1.200
V_fixture_min=1.140
V_fixture_max=1.260
0s        1.196V     1.137V     1.255V
1.263ns   1.196V     1.137V     1.264V
1.353ns   1.196V     1.137V     527.3mV
1.403ns   1.164V     1.137V     549.4mV
1.454ns   658.1mV    1.137V     545mV
1.504ns   497.6mV    1.143V     542.2mV
1.554ns   519.8mV    1.146V     541mV
1.634ns   516.1mV    590.8mV    540.5mV
1.704ns   513.9mV    468.2mV    540.4mV
10ns      513.1mV    485.8mV    540.7mV
[Falling waveform]
R_fixture=50.000Ohm
V_fixture=0
0s        535.6mV    508.9mV    562mV
1.253ns   535.6mV    508.9mV    565.7mV
1.323ns   535.3mV    508.9mV    71.89mV
1.373ns   532.3mV    508.9mV    16.45mV
1.423ns   162.5mV    508.6mV    6.998mV
1.474ns   33.24mV    510.8mV    2.532mV
1.524ns   9.865mV    483.5mV    920.4uV
1.604ns   3.424mV    74.13mV    192.9uV
1.734ns   422uV      4.494mV    32.18uV
10ns      344.2nV    4.623uV    92.85nV
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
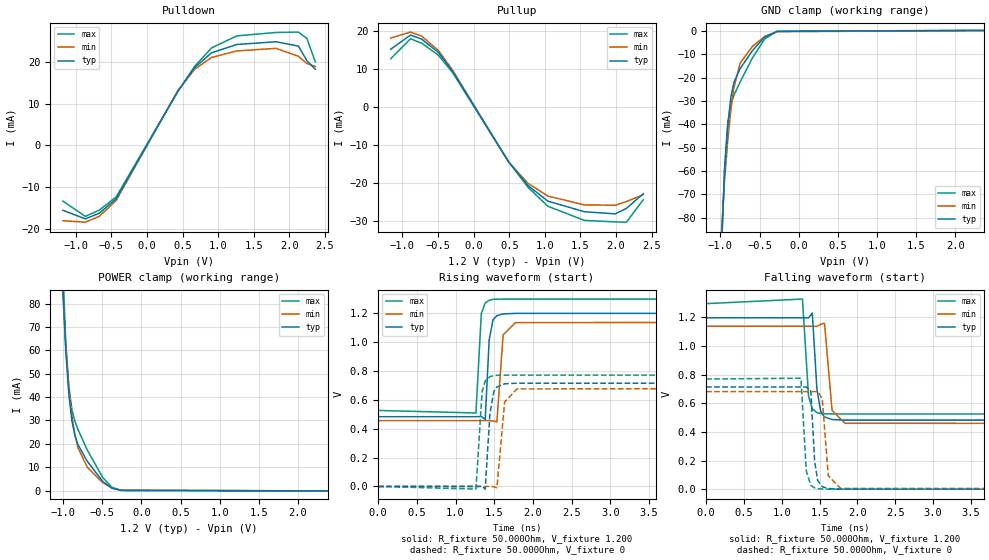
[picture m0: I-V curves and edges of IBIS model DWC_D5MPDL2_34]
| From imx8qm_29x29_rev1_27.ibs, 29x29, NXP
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[Model] DWC_D5MPDL2_34
Model_type   I/O
Polarity   Non-Inverting
Enable   Active-High
C_comp   1.453pF   1.359pF   1.567pF
C_comp_pullup   327.461fF   305.715fF   352.998fF
C_comp_pulldown 1.098pF   1.016pF   1.190pF
Vinh = 820.000mV
Vinl = 380.000mV
Vmeas = 600.000mV
Vref = 600.000mV
Rref = 50Ohms
Cref = 5pF
[Model Spec]
Vinh   820.000mV   790.000mV   870.000mV
Vinl   380.000mV   350.000mV   430.000mV
Vmeas   600.000mV   570.000mV   650.000mV
Vref   600.000mV   570.000mV   650.000mV
D_overshoot_ampl_h 0.35 NA   NA
D_overshoot_ampl_l 0.35 NA   NA
D_overshoot_area_l 150.000p NA   NA
D_overshoot_area_h 150.000p NA   NA
[Receiver Thresholds]
Vcross_low = 480.000mV
Vcross_high = 720.000mV
Vdiff_ac = 440.000mV
Vdiff_dc = 260.000mV
Tdiffslew_ac = 10.000ns
[Temperature Range]   25.000   125.000   -40.000
[Voltage Range]   1.200V   1.140V   1.300V
[GND Clamp Reference]   0.00V   0.00V   0.00V
[C Comp Corner]
| variable   typ   min   max
C_comp 1.453pF   1.567pF   1.359pF
C_comp_pullup 327.461fF   352.998fF   305.715fF
C_comp_pulldown 1.098pF   1.190pF   1.016pF
[Pulldown Reference]   0.00V   0.00V   0.00V
[POWER Clamp Reference]   1.200V   1.140V   1.300V
[Pullup Reference]   1.200V   1.140V   1.300V
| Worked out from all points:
|   slope of the pulldown table from 0 to 0.18 V, typ, clamps not added: 32 ohm
|   slope of the pullup table from 0 to 0.18 V, typ, clamps not added: 32.1 ohm
|   GND clamp passes 1 mA (typ) near -0.36 V on its own axis
|   POWER clamp passes 1 mA (typ) near -0.38 V on its own axis
|   rising waveform, R_fixture 50.000Ohm, V_fixture 1.200: 20-80 % time 40.6ps typ, 46.8ps min, 38.6ps max; typ from 0.482 V to 1.2 V
|   rising waveform, R_fixture 50.000Ohm, V_fixture 0: 20-80 % time 52.9ps typ, 62ps min, 47.8ps max; typ from 0 V to 0.714 V
|   falling waveform, R_fixture 50.000Ohm, V_fixture 1.200: 20-80 % time 55.6ps typ, 63ps min, 51.3ps max; typ from 1.2 V to 0.482 V
|   falling waveform, R_fixture 50.000Ohm, V_fixture 0: 20-80 % time 45.8ps typ, 54ps min, 40.9ps max; typ from 0.714 V to 0 V
[GND Clamp]
-1.182V   -345.2mA   -257.7mA   -435.6mA
-1.064V   -162.8mA   -137.9mA   -187.8mA
-1.024V   -119.8mA   -108.3mA   -130.8mA
-945.5mV  -59.97mA   -63.65mA   -57.95mA
-906.1mV  -40.85mA   -47.19mA   -39.65mA
-866.7mV  -28.53mA   -34.08mA   -31.47mA
-827.3mV  -22mA      -24.32mA   -27.6mA
-748.5mV  -16.16mA   -13.8mA    -21.88mA
-590.9mV  -8.378mA   -6.566mA   -11.55mA
-433.3mV  -2.507mA   -2.278mA   -3.353mA
-275.8mV  -117.4uA   -250.4uA   -85.68uA
2.364V    273.1uA    222uA      340.4uA
[Power Clamp]
-1.164V   313mA      242.8mA    382.6mA
-1.006V   89.54mA    86.11mA    97.5mA
-966.7mV  59.99mA    61.94mA    63.63mA
-927.3mV  41.19mA    44.38mA    44.46mA
-887.9mV  29.88mA    32.15mA    34.66mA
-848.5mV  23.4mA     23.81mA    29.55mA
-809.1mV  19.58mA    18.22mA    26.07mA
-690.9mV  12.5mA     9.979mA    17.31mA
-493.9mV  3.891mA    3.395mA    5.592mA
-375.8mV  975.2uA    1.117mA    1.394mA
-257.6mV  56.85uA    160.7uA    65.49uA
2.382V    -136.5uA   -116.8uA   -155.8uA
[Pulldown]
-1.182V   -15.5mA    -18mA      -13.3mA
-866.7mV  -17.56mA   -18.35mA   -16.96mA
-669.7mV  -16.2mA    -16.95mA   -15.45mA
-433.3mV  -12.74mA   -13.14mA   -12.3mA
433.3mV   13mA       13.1mA     12.92mA
669.7mV   18.62mA    18.22mA    18.94mA
906.1mV   22.15mA    21.04mA    23.32mA
1.261V    24.15mA    22.6mA     26.2mA
1.812V    24.8mA     23.22mA    27.02mA
2.127V    23.76mA    21.32mA    27.11mA
2.245V    20.3mA     19.6mA     25.62mA
2.364V    18.2mA     18.9mA     20mA
[Pullup]
-1.164V   15.3mA     18.25mA    12.79mA
-887.9mV  19.03mA    19.82mA    18.05mA
-730.3mV  17.96mA    18.75mA    16.89mA
-493.9mV  14.43mA    14.92mA    13.68mA
-297mV    9.496mA    9.808mA    9.151mA
490.9mV   -14.49mA   -14.5mA    -14.44mA
766.7mV   -20.81mA   -20.2mA    -21.26mA
1.042V    -24.84mA   -23.5mA    -26.19mA
1.554V    -27.64mA   -25.84mA   -29.93mA
1.988V    -28.21mA   -25.94mA   -30.34mA
2.146V    -26.76mA   -24.95mA   -30.41mA
2.382V    -22.9mA    -23.15mA   -24.5mA
[Ramp]
R_load=50.000Ohm
dV/dt_r   428.700mV/47.000ps  409.289mV/54.500ps  462.120mV/43.500ps
dV/dt_f   428.700mV/52.000ps  409.289mV/58.500ps  462.120mV/46.500ps
[Rising waveform]
R_fixture=50.000Ohm
V_fixture=1.200
V_fixture_min=1.140
V_fixture_max=1.300
0s        482.4mV    455.1mV    525.7mV
1.263ns   482.4mV    455.1mV    508mV
1.333ns   483.6mV    455.1mV    1.197V
1.383ns   464.1mV    455mV      1.269V
1.434ns   1.012V     455.9mV    1.288V
1.484ns   1.153V     452.7mV    1.294V
1.534ns   1.181V     446.8mV    1.295V
1.614ns   1.193V     1.048V     1.296V
1.774ns   1.197V     1.133V     1.296V
10ns      1.197V     1.138V     1.296V
[Rising waveform]
R_fixture=50.000Ohm
V_fixture=0
0s        167nV      4.154uV    23.99nV
1.263ns   -2.982uV   -413.2nV   -18.16mV
1.343ns   1.46mV     6.839uV    655.7mV
1.383ns   -18.87mV   -102.6uV   728.4mV
1.444ns   503.6mV    1.039mV    759.3mV
1.494ns   655.5mV    -2.656mV   766.3mV
1.534ns   688.1mV    -9.116mV   768.4mV
1.634ns   709.7mV    584.3mV    769.9mV
1.794ns   713.9mV    674.6mV    770mV
10ns      714mV      681.4mV    769.7mV
[Falling waveform]
R_fixture=50.000Ohm
V_fixture=1.200
V_fixture_min=1.140
V_fixture_max=1.300
0s        1.197V     1.138V     1.296V
1.273ns   1.197V     1.138V     1.328V
1.353ns   1.197V     1.138V     649.3mV
1.403ns   1.23V      1.138V     561.1mV
1.464ns   697.1mV    1.137V     534.8mV
1.514ns   543.6mV    1.152V     528.6mV
1.564ns   504.7mV    1.159V     526.5mV
1.664ns   486.2mV    551mV      525.4mV
1.834ns   482.4mV    461.1mV    525.3mV
10ns      482.4mV    455.1mV    525.6mV
[Falling waveform]
R_fixture=50.000Ohm
V_fixture=0
0s        714mV      681.4mV    769.6mV
1.253ns   714mV      681.4mV    774.9mV
1.323ns   713.6mV    681.4mV    128.3mV
1.383ns   685.3mV    681.4mV    27.13mV
1.434ns   193.1mV    681mV      8.96mV
1.474ns   60mV       682.6mV    3.863mV
1.534ns   17.47mV    632.6mV    1.114mV
1.614ns   4.426mV    95.06mV    227.4uV
1.774ns   319uV      5.969mV    29.94uV
10ns      478.1nV    4.461uV    93.03nV
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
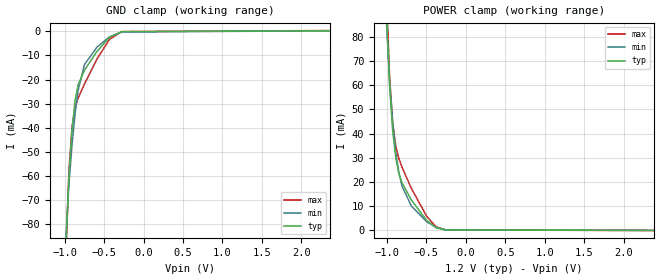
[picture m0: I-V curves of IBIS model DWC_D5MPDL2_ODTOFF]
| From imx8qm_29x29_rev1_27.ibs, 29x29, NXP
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[Model] DWC_D5MPDL2_ODTOFF
Model_type   Input
Polarity   Non-Inverting
Enable   Active-High
C_comp   1.453pF   1.359pF   1.567pF
C_comp_power_clamp   327.461fF   305.715fF   352.998fF
C_comp_gnd_clamp 1.098pF   1.016pF   1.190pF
Vinh = 820.000mV
Vinl = 380.000mV
[Model Spec]
D_overshoot_ampl_h 0.35 NA   NA
D_overshoot_ampl_l 0.35 NA   NA
D_overshoot_area_l 150.000p NA   NA
D_overshoot_area_h 150.000p NA   NA
[Receiver Thresholds]
Vcross_low = 480.000mV
Vcross_high = 720.000mV
Vdiff_ac = 440.000mV
Vdiff_dc = 260.000mV
Tdiffslew_ac = 10.000ns
[Temperature Range]   25.000   125.000   -40.000
[Voltage Range]   1.200V   1.140V   1.300V
[GND Clamp Reference]   0.00V   0.00V   0.00V
[C Comp Corner]
| variable   typ   min   max
C_comp 1.453pF   1.567pF   1.359pF
C_comp_pullup 327.461fF   352.998fF   305.715fF
C_comp_pulldown 1.098pF   1.190pF   1.016pF
[POWER Clamp Reference]   1.200V   1.140V   1.300V
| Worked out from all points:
|   GND clamp passes 1 mA (typ) near -0.36 V on its own axis
|   POWER clamp passes 1 mA (typ) near -0.38 V on its own axis
[GND Clamp]
-1.182V   -345.2mA   -257.7mA   -435.6mA
-1.064V   -162.8mA   -137.9mA   -187.8mA
-1.024V   -119.8mA   -108.3mA   -130.8mA
-945.5mV  -59.97mA   -63.65mA   -57.95mA
-906.1mV  -40.85mA   -47.19mA   -39.65mA
-866.7mV  -28.53mA   -34.08mA   -31.47mA
-827.3mV  -22mA      -24.32mA   -27.6mA
-748.5mV  -16.16mA   -13.8mA    -21.88mA
-590.9mV  -8.378mA   -6.566mA   -11.55mA
-433.3mV  -2.507mA   -2.278mA   -3.353mA
-275.8mV  -117.4uA   -250.4uA   -85.68uA
2.364V    273.1uA    222uA      340.4uA
[Power Clamp]
-1.164V   313mA      242.8mA    382.6mA
-1.006V   89.54mA    86.11mA    97.5mA
-966.7mV  59.99mA    61.94mA    63.63mA
-927.3mV  41.19mA    44.38mA    44.46mA
-887.9mV  29.88mA    32.15mA    34.66mA
-848.5mV  23.4mA     23.81mA    29.55mA
-809.1mV  19.58mA    18.22mA    26.07mA
-690.9mV  12.5mA     9.979mA    17.31mA
-493.9mV  3.891mA    3.395mA    5.592mA
-375.8mV  975.2uA    1.117mA    1.394mA
-257.6mV  56.85uA    160.7uA    65.49uA
2.382V    -136.5uA   -116.8uA   -155.8uA
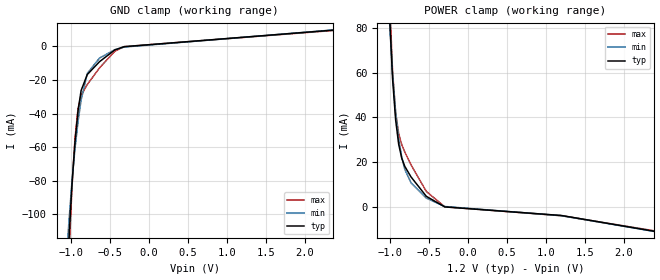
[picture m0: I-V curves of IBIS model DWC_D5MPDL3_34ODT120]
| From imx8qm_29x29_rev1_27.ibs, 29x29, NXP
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[Model] DWC_D5MPDL3_34ODT120
Model_type   Input
Polarity   Non-Inverting
Enable   Active-High
C_comp   1.461pF   1.367pF   1.572pF
C_comp_power_clamp   340.751fF   314.244fF   362.040fF
C_comp_gnd_clamp 1.092pF   1.015pF   1.188pF
Vinh = 868.000mV
Vinl = 598.000mV
[Model Spec]
D_overshoot_ampl_h 0.35 NA   NA
D_overshoot_ampl_l 0.35 NA   NA
D_overshoot_area_l 100.000p NA   NA
D_overshoot_area_h 100.000p NA   NA
[Receiver Thresholds]
Vcross_low = 612.000mV
Vcross_high = 852.000mV
Vdiff_ac = 270.000mV
Vdiff_dc = 200.000mV
Tdiffslew_ac = 10.000ns
[Temperature Range]   25.000   125.000   -40.000
[Voltage Range]   1.200V   1.140V   1.300V
[GND Clamp Reference]   0.00V   0.00V   0.00V
[C Comp Corner]
| variable   typ   min   max
C_comp 1.461pF   1.572pF   1.367pF
C_comp_pullup 340.751fF   362.040fF   314.244fF
C_comp_pulldown 1.092pF   1.188pF   1.015pF
[POWER Clamp Reference]   1.200V   1.140V   1.300V
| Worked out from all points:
|   GND clamp passes 1 mA (typ) near -0.38 V on its own axis
|   POWER clamp passes 1 mA (typ) near -0.39 V on its own axis
[GND Clamp]
-1.182V   -340.1mA   -253.2mA   -429.8mA
-1.064V   -158.7mA   -134.2mA   -183.2mA
-1.024V   -116.1mA   -105mA     -126.7mA
-984.8mV  -82.66mA   -80.81mA   -84.56mA
-945.5mV  -57.01mA   -60.94mA   -54.8mA
-906.1mV  -38.22mA   -44.74mA   -36.93mA
-866.7mV  -26.21mA   -31.87mA   -29.1mA
-787.9mV  -16.73mA   -16.05mA   -22.68mA
-630.3mV  -9.021mA   -6.886mA   -12.71mA
-433.3mV  -2.02mA    -1.859mA   -2.786mA
-315.2mV  -118.5uA   -336.7uA   -76.04uA
2.364V    9.738mA    9.839mA    9.516mA
[Power Clamp]
-1.164V   308.3mA    238.8mA    377.2mA
-1.006V   86.46mA    83.39mA    94.14mA
-966.7mV  57.41mA    59.53mA    60.9mA
-927.3mV  39.01mA    42.29mA    42.22mA
-887.9mV  28.02mA    30.34mA    32.76mA
-848.5mV  21.79mA    22.23mA    27.87mA
-809.1mV  18.16mA    16.85mA    24.57mA
-730.3mV  13.5mA     10.89mA    18.89mA
-533.3mV  4.814mA    4.011mA    6.991mA
-297mV    98.84uA    285.2uA    145.7uA
1.2V      -3.735mA   -3.816mA   -3.837mA
2.382V    -10.73mA   -10.81mA   -10.52mA
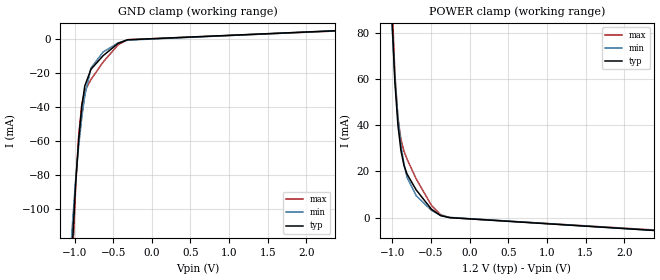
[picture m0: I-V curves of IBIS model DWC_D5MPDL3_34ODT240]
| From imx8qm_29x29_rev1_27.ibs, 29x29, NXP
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[Model] DWC_D5MPDL3_34ODT240
Model_type   Input
Polarity   Non-Inverting
Enable   Active-High
C_comp   1.454pF   1.360pF   1.566pF
C_comp_power_clamp   329.367fF   303.985fF   352.565fF
C_comp_gnd_clamp 1.095pF   1.017pF   1.191pF
Vinh = 809.000mV
Vinl = 539.000mV
[Model Spec]
D_overshoot_ampl_h 0.35 NA   NA
D_overshoot_ampl_l 0.35 NA   NA
D_overshoot_area_l 100.000p NA   NA
D_overshoot_area_h 100.000p NA   NA
[Receiver Thresholds]
Vcross_low = 554.000mV
Vcross_high = 794.000mV
Vdiff_ac = 270.000mV
Vdiff_dc = 200.000mV
Tdiffslew_ac = 10.000ns
[Temperature Range]   25.000   125.000   -40.000
[Voltage Range]   1.200V   1.140V   1.300V
[GND Clamp Reference]   0.00V   0.00V   0.00V
[C Comp Corner]
| variable   typ   min   max
C_comp 1.454pF   1.566pF   1.360pF
C_comp_pullup 329.367fF   352.565fF   303.985fF
C_comp_pulldown 1.095pF   1.191pF   1.017pF
[POWER Clamp Reference]   1.200V   1.140V   1.300V
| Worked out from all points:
|   GND clamp passes 1 mA (typ) near -0.37 V on its own axis
|   POWER clamp passes 1 mA (typ) near -0.38 V on its own axis
[GND Clamp]
-1.182V   -342.6mA   -255.5mA   -432.7mA
-1.064V   -160.7mA   -136.1mA   -185.6mA
-1.024V   -117.9mA   -106.7mA   -128.8mA
-984.8mV  -84.28mA   -82.29mA   -86.36mA
-945.5mV  -58.47mA   -62.29mA   -56.38mA
-906.1mV  -39.51mA   -45.96mA   -38.29mA
-866.7mV  -27.35mA   -32.97mA   -30.29mA
-787.9mV  -17.63mA   -16.92mA   -23.67mA
-630.3mV  -9.592mA   -7.405mA   -13.36mA
-433.3mV  -2.26mA    -2.067mA   -3.071mA
-315.2mV  -233uA     -429.7uA   -213.1uA
2.364V    5.063mA    5.035mA    4.889mA
[Power Clamp]
-1.164V   310.6mA    240.7mA    379.9mA
-1.006V   87.98mA    84.72mA    95.87mA
-966.7mV  58.68mA    60.73mA    62.28mA
-927.3mV  40.08mA    43.33mA    43.35mA
-887.9mV  28.93mA    31.24mA    33.72mA
-848.5mV  22.58mA    23.02mA    28.72mA
-809.1mV  18.86mA    17.53mA    25.33mA
-690.9mV  12mA       9.527mA    16.78mA
-493.9mV  3.691mA    3.22mA     5.361mA
-375.8mV  891.1uA    1.045mA    1.292mA
-257.6mV  25.54uA    139.7uA    28.87uA
2.382V    -5.51mA    -5.464mA   -5.297mA
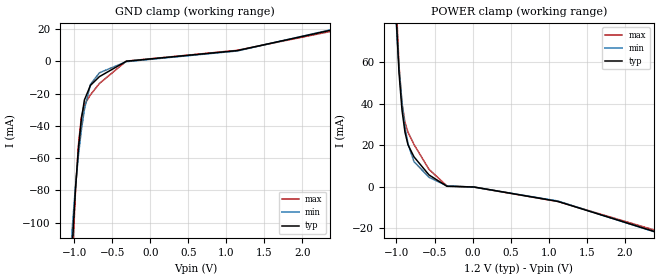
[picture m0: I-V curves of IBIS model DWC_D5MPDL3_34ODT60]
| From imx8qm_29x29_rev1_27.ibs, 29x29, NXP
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[Model] DWC_D5MPDL3_34ODT60
Model_type   Input
Polarity   Non-Inverting
Enable   Active-High
C_comp   1.470pF   1.386pF   1.576pF
C_comp_power_clamp   357.281fF   339.268fF   374.451fF
C_comp_gnd_clamp 1.086pF   1.010pF   1.181pF
Vinh = 952.000mV
Vinl = 682.000mV
[Model Spec]
D_overshoot_ampl_h 0.35 NA   NA
D_overshoot_ampl_l 0.35 NA   NA
D_overshoot_area_l 100.000p NA   NA
D_overshoot_area_h 100.000p NA   NA
[Receiver Thresholds]
Vcross_low = 697.000mV
Vcross_high = 937.000mV
Vdiff_ac = 270.000mV
Vdiff_dc = 200.000mV
Tdiffslew_ac = 10.000ns
[Temperature Range]   25.000   125.000   -40.000
[Voltage Range]   1.200V   1.140V   1.300V
[GND Clamp Reference]   0.00V   0.00V   0.00V
[C Comp Corner]
| variable   typ   min   max
C_comp 1.470pF   1.576pF   1.386pF
C_comp_pullup 357.281fF   374.451fF   339.268fF
C_comp_pulldown 1.086pF   1.181pF   1.010pF
[POWER Clamp Reference]   1.200V   1.140V   1.300V
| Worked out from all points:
|   GND clamp passes 1 mA (typ) near -0.41 V on its own axis
|   POWER clamp passes 1 mA (typ) near -0.40 V on its own axis
[GND Clamp]
-1.182V   -334.9mA   -248.8mA   -424mA
-1.064V   -154.7mA   -130.7mA   -178.7mA
-1.024V   -112.4mA   -101.8mA   -122.7mA
-984.8mV  -79.35mA   -77.83mA   -81mA
-945.5mV  -54.04mA   -58.23mA   -51.71mA
-906.1mV  -35.57mA   -42.28mA   -34.27mA
-866.7mV  -23.89mA   -29.66mA   -26.77mA
-787.9mV  -14.88mA   -14.31mA   -20.75mA
-669.7mV  -9.434mA   -7.062mA   -13.68mA
-315.2mV  112.8uA    -148.9uA   185.8uA
1.142V    6.709mA    6.493mA    6.882mA
2.364V    19.27mA    19.54mA    18.55mA
[Power Clamp]
-1.164V   303.6mA    234.8mA    371.9mA
-1.006V   83.39mA    80.63mA    90.9mA
-966.7mV  54.85mA    57.14mA    58.26mA
-927.3mV  36.86mA    40.22mA    40.06mA
-887.9mV  26.18mA    28.53mA    30.93mA
-848.5mV  20.2mA     20.66mA    26.26mA
-769.7mV  14.4mA     12.12mA    20.36mA
-572.7mV  5.71mA     4.556mA    8.408mA
-336.4mV  239.4uA    469.5uA    382.7uA
18.2mV    -96.36uA   -156.6uA   -151.7uA
1.121V    -7.027mA   -6.83mA    -7.091mA
2.382V    -21.44mA   -21.58mA   -20.73mA
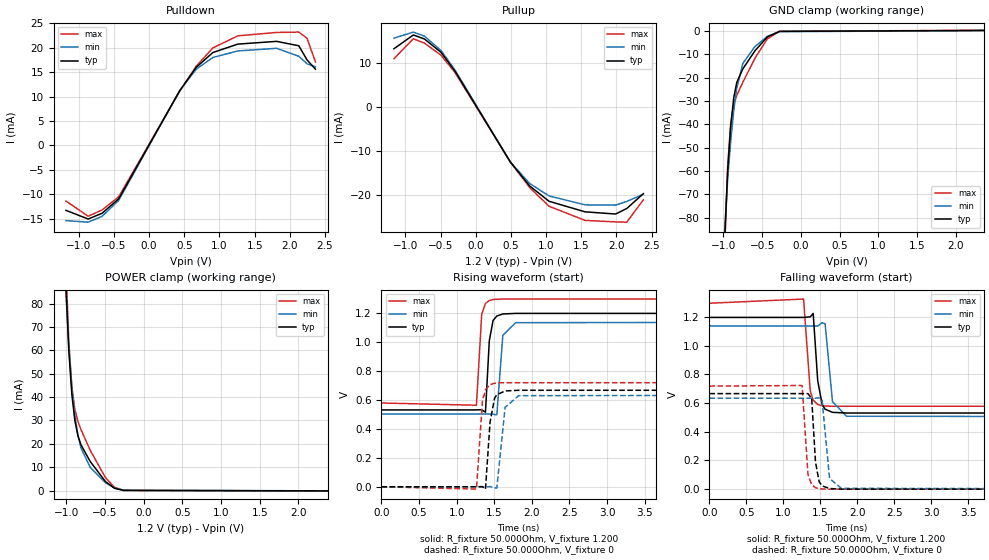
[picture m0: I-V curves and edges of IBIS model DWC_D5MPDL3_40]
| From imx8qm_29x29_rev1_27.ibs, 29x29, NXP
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[Model] DWC_D5MPDL3_40
Model_type   I/O
Polarity   Non-Inverting
Enable   Active-High
C_comp   1.453pF   1.359pF   1.567pF
C_comp_pullup   325.220fF   301.153fF   350.881fF
C_comp_pulldown 1.100pF   1.020pF   1.196pF
Vinh = 975.000mV
Vinl = 705.000mV
Vmeas = 840.000mV
Vref = 840.000mV
Rref = 50Ohms
Cref = 5pF
[Model Spec]
Vinh   975.000mV   933.000mV   1.045V
Vinl   705.000mV   663.000mV   775.000mV
Vmeas   840.000mV   798.000mV   910.000mV
Vref   840.000mV   798.000mV   910.000mV
D_overshoot_ampl_h 0.35 NA   NA
D_overshoot_ampl_l 0.35 NA   NA
D_overshoot_area_l 100.000p NA   NA
D_overshoot_area_h 100.000p NA   NA
[Receiver Thresholds]
Vcross_low = 720.000mV
Vcross_high = 960.000mV
Vdiff_ac = 270.000mV
Vdiff_dc = 200.000mV
Tdiffslew_ac = 10.000ns
[Temperature Range]   25.000   125.000   -40.000
[Voltage Range]   1.200V   1.140V   1.300V
[GND Clamp Reference]   0.00V   0.00V   0.00V
[C Comp Corner]
| variable   typ   min   max
C_comp 1.453pF   1.567pF   1.359pF
C_comp_pullup 325.220fF   350.881fF   301.153fF
C_comp_pulldown 1.100pF   1.196pF   1.020pF
[Pulldown Reference]   0.00V   0.00V   0.00V
[POWER Clamp Reference]   1.200V   1.140V   1.300V
[Pullup Reference]   1.200V   1.140V   1.300V
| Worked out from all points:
|   slope of the pulldown table from 0 to 0.18 V, typ, clamps not added: 37.3 ohm
|   slope of the pullup table from 0 to 0.18 V, typ, clamps not added: 37.4 ohm
|   GND clamp passes 1 mA (typ) near -0.36 V on its own axis
|   POWER clamp passes 1 mA (typ) near -0.38 V on its own axis
|   rising waveform, R_fixture 50.000Ohm, V_fixture 1.200: 20-80 % time 43.8ps typ, 49.4ps min, 41.6ps max; typ from 0.531 V to 1.2 V
|   rising waveform, R_fixture 50.000Ohm, V_fixture 0: 20-80 % time 57.7ps typ, 67.1ps min, 52.8ps max; typ from 0 V to 0.666 V
|   falling waveform, R_fixture 50.000Ohm, V_fixture 1.200: 20-80 % time 61.4ps typ, 69.6ps min, 56.4ps max; typ from 1.2 V to 0.531 V
|   falling waveform, R_fixture 50.000Ohm, V_fixture 0: 20-80 % time 49.6ps typ, 57.4ps min, 44.3ps max; typ from 0.666 V to 0 V
[GND Clamp]
-1.182V   -345.2mA   -257.7mA   -435.6mA
-1.064V   -162.8mA   -137.9mA   -187.8mA
-1.024V   -119.8mA   -108.3mA   -130.8mA
-945.5mV  -59.97mA   -63.65mA   -57.95mA
-906.1mV  -40.85mA   -47.19mA   -39.65mA
-866.7mV  -28.53mA   -34.08mA   -31.47mA
-827.3mV  -22mA      -24.32mA   -27.6mA
-748.5mV  -16.16mA   -13.8mA    -21.88mA
-590.9mV  -8.378mA   -6.566mA   -11.55mA
-433.3mV  -2.507mA   -2.278mA   -3.353mA
-275.8mV  -117.4uA   -250.4uA   -85.68uA
2.364V    273.1uA    222uA      340.4uA
[Power Clamp]
-1.164V   313mA      242.8mA    382.6mA
-1.006V   89.54mA    86.11mA    97.5mA
-966.7mV  59.99mA    61.94mA    63.63mA
-927.3mV  41.19mA    44.38mA    44.46mA
-887.9mV  29.88mA    32.15mA    34.66mA
-848.5mV  23.4mA     23.81mA    29.55mA
-809.1mV  19.58mA    18.22mA    26.07mA
-690.9mV  12.5mA     9.979mA    17.31mA
-493.9mV  3.891mA    3.395mA    5.592mA
-375.8mV  975.2uA    1.117mA    1.394mA
-257.6mV  56.85uA    160.7uA    65.49uA
2.382V    -136.5uA   -116.8uA   -155.8uA
[Pulldown]
-1.182V   -13.3mA    -15.4mA    -11.4mA
-866.7mV  -15.07mA   -15.72mA   -14.5mA
-669.7mV  -13.9mA    -14.52mA   -13.22mA
-433.3mV  -10.94mA   -11.26mA   -10.53mA
433.3mV   11.16mA    11.23mA    11.06mA
669.7mV   15.99mA    15.61mA    16.22mA
906.1mV   19.02mA    18.01mA    19.96mA
1.261V    20.74mA    19.34mA    22.43mA
1.812V    21.3mA     19.88mA    23.13mA
2.127V    20.4mA     18.25mA    23.2mA
2.245V    17.5mA     16.7mA     21.92mA
2.364V    15.6mA     16.1mA     17.1mA
[Pullup]
-1.164V   13.2mA     15.6mA     10.95mA
-887.9mV  16.33mA    16.98mA    15.47mA
-730.3mV  15.42mA    16.06mA    14.48mA
-493.9mV  12.39mA    12.79mA    11.74mA
-297mV    8.161mA    8.411mA    7.858mA
490.9mV   -12.45mA   -12.43mA   -12.4mA
766.7mV   -17.87mA   -17.31mA   -18.25mA
1.042V    -21.33mA   -20.13mA   -22.46mA
1.554V    -23.72mA   -22.13mA   -25.65mA
1.988V    -24.21mA   -22.2mA    -26mA
2.146V    -22.96mA   -21.35mA   -26.06mA
2.382V    -19.6mA    -19.75mA   -20.99mA
[Ramp]
R_load=50.000Ohm
dV/dt_r   399.780mV/51.500ps  380.879mV/59.000ps  430.740mV/48.000ps
dV/dt_f   399.780mV/56.500ps  380.909mV/64.000ps  430.740mV/51.000ps
[Rising waveform]
R_fixture=50.000Ohm
V_fixture=1.200
V_fixture_min=1.140
V_fixture_max=1.300
0s        530.7mV    502.6mV    578.4mV
1.263ns   530.7mV    502.6mV    562.9mV
1.333ns   531.8mV    502.6mV    1.191V
1.383ns   515mV      502.4mV    1.266V
1.434ns   1.008V     503.4mV    1.286V
1.484ns   1.148V     499.9mV    1.293V
1.534ns   1.179V     497mV      1.295V
1.614ns   1.193V     1.046V     1.296V
1.784ns   1.197V     1.133V     1.296V
10ns      1.197V     1.138V     1.296V
[Rising waveform]
R_fixture=50.000Ohm
V_fixture=0
0s        183.1nV    4.562uV    26.9nV
1.263ns   -2.24uV    -152.8nV   -16.04mV
1.343ns   1.312mV    8.327uV    594.3mV
1.383ns   -16.51mV   -93.81uV   670.4mV
1.444ns   446.6mV    938.4uV    705.4mV
1.504ns   611.5mV    -7.211mV   714.7mV
1.534ns   635.6mV    -8.178mV   716.5mV
1.644ns   661.7mV    548.2mV    718.4mV
1.824ns   666.2mV    629mV      718.6mV
10ns      666.2mV    634.4mV    718.2mV
[Falling waveform]
R_fixture=50.000Ohm
V_fixture=1.200
V_fixture_min=1.140
V_fixture_max=1.300
0s        1.197V     1.138V     1.296V
1.273ns   1.197V     1.138V     1.325V
1.363ns   1.201V     1.138V     685.8mV
1.403ns   1.225V     1.138V     620.9mV
1.464ns   757.4mV    1.137V     589.9mV
1.524ns   588.8mV    1.16V      581.5mV
1.564ns   557.7mV    1.153V     579.5mV
1.664ns   535.5mV    610.1mV    578.1mV
1.854ns   530.7mV    508.2mV    577.9mV
10ns      530.6mV    502.5mV    578.3mV
[Falling waveform]
R_fixture=50.000Ohm
V_fixture=0
0s        666.1mV    634.4mV    718.1mV
1.253ns   666.1mV    634.4mV    722.5mV
1.333ns   666mV      634.4mV    100.1mV
1.383ns   631.9mV    634.4mV    30.11mV
1.434ns   190mV      634mV      10.22mV
1.484ns   50.95mV    637.3mV    3.668mV
1.524ns   23.05mV    619.3mV    1.63mV
1.624ns   4.226mV    74.68mV    229uV
1.784ns   319.5uV    5.702mV    30.37uV
10ns      581.4nV    4.753uV    142.5nV
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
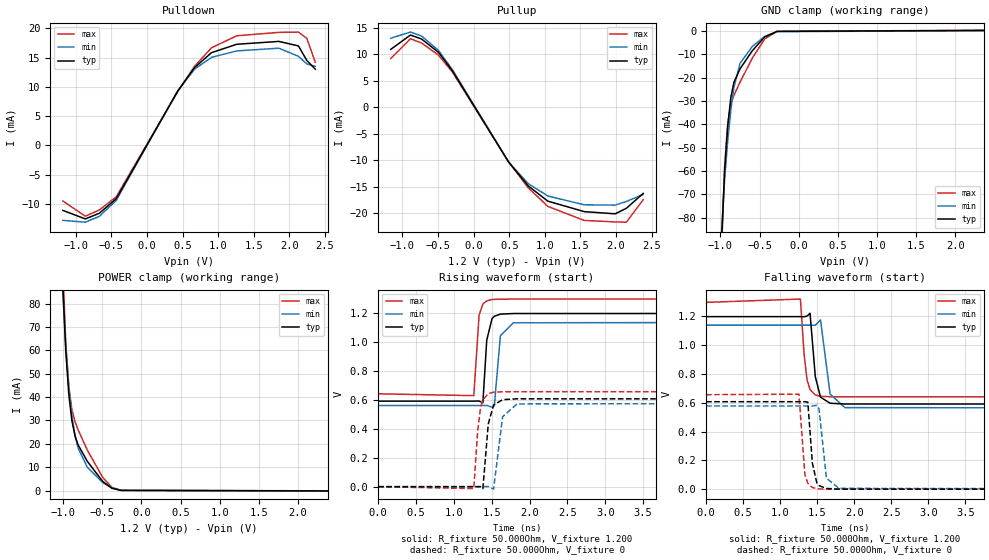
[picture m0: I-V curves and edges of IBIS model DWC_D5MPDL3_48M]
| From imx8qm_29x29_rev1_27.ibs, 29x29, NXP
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[Model] DWC_D5MPDL3_48M
Model_type   I/O
Polarity   Non-Inverting
Enable   Active-High
C_comp   1.453pF   1.359pF   1.567pF
C_comp_pullup   324.159fF   299.153fF   350.625fF
C_comp_pulldown 1.096pF   1.017pF   1.193pF
Vinh = 735.000mV
Vinl = 465.000mV
Vmeas = 600.000mV
Vref = 600.000mV
Rref = 50Ohms
Cref = 5pF
[Model Spec]
Vinh   735.000mV   705.000mV   785.000mV
Vinl   465.000mV   435.000mV   515.000mV
Vmeas   600.000mV   570.000mV   650.000mV
Vref   600.000mV   570.000mV   650.000mV
D_overshoot_ampl_h 0.35 NA   NA
D_overshoot_ampl_l 0.35 NA   NA
D_overshoot_area_l 100.000p NA   NA
D_overshoot_area_h 100.000p NA   NA
[Receiver Thresholds]
Vcross_low = 480.000mV
Vcross_high = 720.000mV
Vdiff_ac = 270.000mV
Vdiff_dc = 200.000mV
Tdiffslew_ac = 10.000ns
[Temperature Range]   25.000   125.000   -40.000
[Voltage Range]   1.200V   1.140V   1.300V
[GND Clamp Reference]   0.00V   0.00V   0.00V
[C Comp Corner]
| variable   typ   min   max
C_comp 1.453pF   1.567pF   1.359pF
C_comp_pullup 324.159fF   350.625fF   299.153fF
C_comp_pulldown 1.096pF   1.193pF   1.017pF
[Pulldown Reference]   0.00V   0.00V   0.00V
[POWER Clamp Reference]   1.200V   1.140V   1.300V
[Pullup Reference]   1.200V   1.140V   1.300V
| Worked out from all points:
|   slope of the pulldown table from 0 to 0.18 V, typ, clamps not added: 44.8 ohm
|   slope of the pullup table from 0 to 0.18 V, typ, clamps not added: 44.9 ohm
|   GND clamp passes 1 mA (typ) near -0.36 V on its own axis
|   POWER clamp passes 1 mA (typ) near -0.38 V on its own axis
|   rising waveform, R_fixture 50.000Ohm, V_fixture 1.200: 20-80 % time 48.4ps typ, 53.5ps min, 45.8ps max; typ from 0.591 V to 1.2 V
|   rising waveform, R_fixture 50.000Ohm, V_fixture 0: 20-80 % time 64.2ps typ, 73.5ps min, 58.2ps max; typ from 0 V to 0.607 V
|   falling waveform, R_fixture 50.000Ohm, V_fixture 1.200: 20-80 % time 69ps typ, 77.7ps min, 62.7ps max; typ from 1.2 V to 0.591 V
|   falling waveform, R_fixture 50.000Ohm, V_fixture 0: 20-80 % time 54.5ps typ, 62.4ps min, 47.9ps max; typ from 0.607 V to 0 V
[GND Clamp]
-1.182V   -345.2mA   -257.7mA   -435.6mA
-1.064V   -162.8mA   -137.9mA   -187.8mA
-1.024V   -119.8mA   -108.3mA   -130.8mA
-945.5mV  -59.97mA   -63.65mA   -57.95mA
-906.1mV  -40.85mA   -47.19mA   -39.65mA
-866.7mV  -28.53mA   -34.08mA   -31.47mA
-827.3mV  -22mA      -24.32mA   -27.6mA
-748.5mV  -16.16mA   -13.8mA    -21.88mA
-590.9mV  -8.378mA   -6.566mA   -11.55mA
-433.3mV  -2.507mA   -2.278mA   -3.353mA
-275.8mV  -117.4uA   -250.4uA   -85.68uA
2.364V    273.1uA    222uA      340.4uA
[Power Clamp]
-1.164V   313mA      242.8mA    382.6mA
-1.006V   89.54mA    86.11mA    97.5mA
-966.7mV  59.99mA    61.94mA    63.63mA
-927.3mV  41.19mA    44.38mA    44.46mA
-887.9mV  29.88mA    32.15mA    34.66mA
-848.5mV  23.4mA     23.81mA    29.55mA
-809.1mV  19.58mA    18.22mA    26.07mA
-690.9mV  12.5mA     9.979mA    17.31mA
-493.9mV  3.891mA    3.395mA    5.592mA
-375.8mV  975.2uA    1.117mA    1.394mA
-257.6mV  56.85uA    160.7uA    65.49uA
2.382V    -136.5uA   -116.8uA   -155.8uA
[Pulldown]
-1.182V   -11.1mA    -12.8mA    -9.5mA
-866.7mV  -12.55mA   -13.11mA   -12.09mA
-669.7mV  -11.58mA   -12.11mA   -11.02mA
-433.3mV  -9.111mA   -9.399mA   -8.787mA
433.3mV   9.296mA    9.373mA    9.235mA
669.7mV   13.31mA    13.03mA    13.54mA
906.1mV   15.83mA    15.03mA    16.66mA
1.261V    17.26mA    16.13mA    18.71mA
1.851V    17.75mA    16.59mA    19.29mA
2.127V    16.98mA    15.21mA    19.34mA
2.245V    14.5mA     13.9mA     18.26mA
2.364V    13mA       13.5mA     14.2mA
[Pullup]
-1.164V   10.9mA     13mA       9.146mA
-887.9mV  13.59mA    14.15mA    12.9mA
-730.3mV  12.83mA    13.4mA     12.08mA
-493.9mV  10.32mA    10.68mA    9.799mA
-297mV    6.8mA      7.024mA    6.564mA
490.9mV   -10.37mA   -10.38mA   -10.36mA
766.7mV   -14.88mA   -14.45mA   -15.24mA
1.042V    -17.76mA   -16.79mA   -18.75mA
1.554V    -19.74mA   -18.45mA   -21.4mA
1.988V    -20.15mA   -18.51mA   -21.68mA
2.146V    -19.1mA    -17.81mA   -21.73mA
2.382V    -16.3mA    -16.5mA    -17.48mA
[Ramp]
R_load=50.000Ohm
dV/dt_r   363.870mV/57.000ps  346.318mV/64.500ps  392.910mV/52.500ps
dV/dt_f   363.840mV/62.500ps  346.348mV/71.000ps  392.910mV/55.500ps
[Rising waveform]
R_fixture=50.000Ohm
V_fixture=1.200
V_fixture_min=1.140
V_fixture_max=1.300
0s        590.9mV    560.6mV    641.6mV
1.263ns   590.9mV    560.6mV    628.8mV
1.333ns   591.8mV    560.6mV    1.185V
1.383ns   578.8mV    560.5mV    1.262V
1.434ns   1.012V     561.4mV    1.284V
1.504ns   1.161V     549mV      1.293V
1.534ns   1.177V     557.5mV    1.294V
1.614ns   1.192V     1.042V     1.295V
1.784ns   1.196V     1.132V     1.296V
10ns      1.197V     1.138V     1.296V
[Rising waveform]
R_fixture=50.000Ohm
V_fixture=0
0s        202.7nV    5.054uV    29.53nV
1.263ns   -1.316uV   234.5nV    -13.5mV
1.313ns   125.6uV    16.23uV    375.9mV
1.353ns   122.5uV    -4.629uV   548.7mV
1.383ns   -13.76mV   -88.01uV   600.1mV
1.454ns   432.2mV    1.156mV    642.5mV
1.524ns   564.2mV    -17.25mV   652.6mV
1.644ns   601.1mV    483.3mV    655.8mV
1.834ns   606.9mV    571.6mV    656.2mV
10ns      607mV      577.4mV    655.7mV
[Falling waveform]
R_fixture=50.000Ohm
V_fixture=1.200
V_fixture_min=1.140
V_fixture_max=1.300
0s        1.197V     1.138V     1.296V
1.273ns   1.197V     1.138V     1.319V
1.323ns   1.196V     1.138V     933.8mV
1.363ns   1.201V     1.138V     758.2mV
1.403ns   1.221V     1.138V     691.1mV
1.474ns   780.7mV    1.137V     653.5mV
1.544ns   638.4mV    1.175V     644.3mV
1.674ns   596.3mV    659.3mV    641.3mV
1.874ns   590.9mV    566mV      641mV
10ns      590.9mV    560.5mV    641.5mV
[Falling waveform]
R_fixture=50.000Ohm
V_fixture=0
0s        606.9mV    577.4mV    655.6mV
1.253ns   606.9mV    577.4mV    658.9mV
1.333ns   606.8mV    577.4mV    103.3mV
1.373ns   603.6mV    577.4mV    41.06mV
1.434ns   182.3mV    577mV      11.8mV
1.494ns   44.11mV    582.3mV    3.628mV
1.524ns   25.21mV    557.1mV    2.025mV
1.624ns   4.843mV    76.34mV    307.1uV
1.794ns   339.6uV    5.52mV     34.19uV
10ns      538.3nV    5.342uV    153.7nV
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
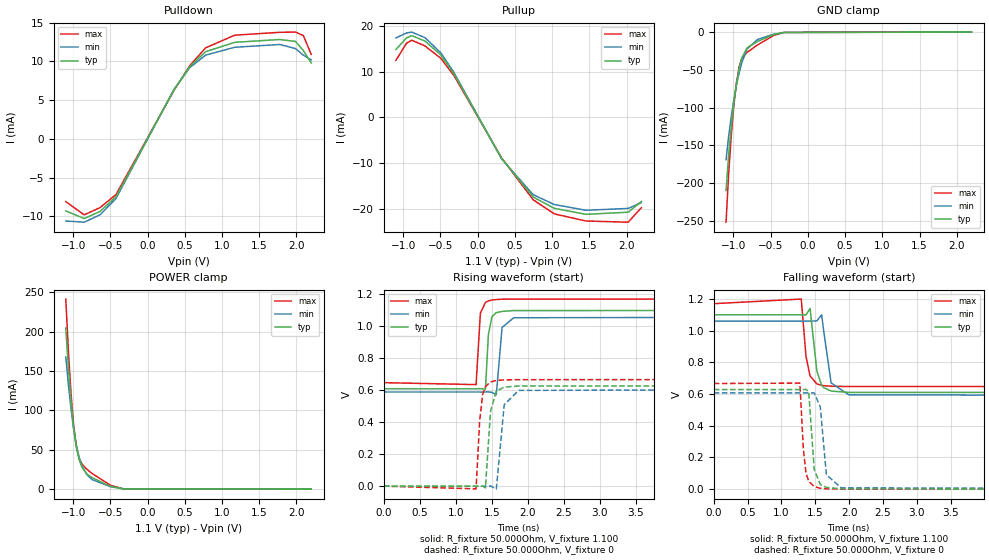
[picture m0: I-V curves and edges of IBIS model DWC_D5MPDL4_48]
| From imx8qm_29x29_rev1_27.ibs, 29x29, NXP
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[Model] DWC_D5MPDL4_48
Model_type   I/O
Polarity   Non-Inverting
Enable   Active-High
C_comp   1.573pF   1.476pF   1.691pF
C_comp_pullup   367.016fF   350.262fF   367.693fF
C_comp_pulldown 1.173pF   1.104pF   1.343pF
Vinh = 396.000mV
Vinl = 216.000mV
Vmeas = 306.000mV
Vref = 306.000mV
Rref = 50Ohms
Cref = 0pF
[Model Spec]
Vinh   396.000mV   384.000mV   415.000mV
Vinl   216.000mV   204.000mV   235.000mV
Vmeas   306.000mV   294.000mV   325.000mV
Vref   306.000mV   294.000mV   325.000mV
D_overshoot_ampl_h 0.35 NA   NA
D_overshoot_ampl_l 0.35 NA   NA
D_overshoot_area_l 800.000p NA   NA
D_overshoot_area_h 800.000p NA   NA
[Receiver Thresholds]
Vcross_low = 211.000mV
Vcross_high = 401.000mV
Vdiff_ac = 140.000mV
Vdiff_dc = 140.000mV
Tdiffslew_ac = 10.000ns
[Temperature Range]   25.000   125.000   -40.000
[Voltage Range]   1.100V   1.060V   1.170V
[GND Clamp Reference]   0.00V   0.00V   0.00V
[C Comp Corner]
| variable   typ   min   max
C_comp 1.573pF   1.691pF   1.476pF
C_comp_pullup 367.016fF   367.693fF   350.262fF
C_comp_pulldown 1.173pF   1.343pF   1.104pF
[Pulldown Reference]   0.00V   0.00V   0.00V
[POWER Clamp Reference]   1.100V   1.060V   1.170V
[Pullup Reference]   1.100V   1.060V   1.170V
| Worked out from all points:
|   slope of the pulldown table from 0 to 0.165 V, typ, clamps not added: 54.1 ohm
|   slope of the pullup table from 0 to 0.165 V, typ, clamps not added: 34.7 ohm
|   GND clamp passes 1 mA (typ) near -0.36 V on its own axis
|   POWER clamp passes 1 mA (typ) near -0.39 V on its own axis
|   rising waveform, R_fixture 50.000Ohm, V_fixture 1.100: 20-80 % time 42.8ps typ, 47.8ps min, 40.7ps max; typ from 0.609 V to 1.1 V
|   rising waveform, R_fixture 50.000Ohm, V_fixture 0: 20-80 % time 61.1ps typ, 69.3ps min, 55.5ps max; typ from 0 V to 0.628 V
|   falling waveform, R_fixture 50.000Ohm, V_fixture 1.100: 20-80 % time 83.3ps typ, 92.9ps min, 77ps max; typ from 1.1 V to 0.609 V
|   falling waveform, R_fixture 50.000Ohm, V_fixture 0: 20-80 % time 61.5ps typ, 70.4ps min, 55.7ps max; typ from 0.628 V to 0 V
[GND Clamp]
-1.099V   -209.8mA   -169.1mA   -251.7mA
-1.064V   -162.7mA   -137.8mA   -187.8mA
-1.028V   -123.6mA   -111mA     -135.8mA
-992.7mV  -92.04mA   -88.31mA   -95.63mA
-957.3mV  -67.05mA   -69.29mA   -65.81mA
-921.8mV  -47.73mA   -53.39mA   -45.6mA
-886.4mV  -33.92mA   -40.26mA   -34.72mA
-815.5mV  -20.84mA   -22.1mA    -26.75mA
-673.6mV  -12.32mA   -9.665mA   -16.87mA
-460.9mV  -3.34mA    -2.899mA   -4.539mA
-319.1mV  -390.9uA   -567.4uA   -395.4uA
2.198V    38.3nA     663.5nA    7.806nA
[Power Clamp]
-1.098V   204.7mA    167.9mA    241.5mA
-1.063V   153.5mA    132.2mA    175.1mA
-1.027V   110.2mA    101.3mA    120.2mA
-991.8mV  76.87mA    75.61mA    80.19mA
-956.4mV  53.56mA    55.87mA    54.83mA
-920.9mV  38.25mA    41.27mA    40.22mA
-885.5mV  28.61mA    30.83mA    32.49mA
-814.5mV  19.18mA    18.23mA    25.18mA
-743.6mV  14.55mA    12.13mA    19.82mA
-495.5mV  3.463mA    3.102mA    4.838mA
-318.2mV  225.2uA    399.5uA    248.6uA
2.199V    -19.18nA   -668.9nA   -2.437nA
[Pulldown]
-1.099V   -9.3mA     -10.6mA    -8.1mA
-850.9mV  -10.28mA   -10.75mA   -9.804mA
-638.2mV  -9.352mA   -9.79mA    -8.867mA
-425.5mV  -7.479mA   -7.71mA    -7.189mA
354.5mV   6.322mA    6.387mA    6.259mA
567.3mV   9.348mA    9.207mA    9.462mA
780mV     11.25mA    10.81mA    11.75mA
1.17V     12.46mA    11.82mA    13.38mA
1.773V    12.82mA    12.18mA    13.75mA
1.986V    12.58mA    11.66mA    13.78mA
2.092V    11.4mA     10.8mA     13.33mA
2.198V    9.8mA      10.2mA     10.9mA
[Pullup]
-1.098V   14.9mA     17.42mA    12.52mA
-956.4mV  17.43mA    18.52mA    16.26mA
-885.5mV  17.93mA    18.71mA    16.93mA
-708.2mV  16.75mA    17.49mA    15.68mA
-495.5mV  13.71mA    14.17mA    12.98mA
-318.2mV  9.544mA    9.857mA    9.166mA
320mV     -8.926mA   -9.028mA   -8.826mA
745.5mV   -17.43mA   -16.91mA   -18.04mA
1.029V    -19.91mA   -19.08mA   -21.13mA
1.455V    -21.23mA   -20.34mA   -22.69mA
2.022V    -20.76mA   -19.93mA   -22.95mA
2.199V    -18.4mA    -18.67mA   -19.78mA
[Ramp]
R_load=50.000Ohm
dV/dt_r   335.820mV/52.500ps  323.489mV/59.500ps  356.730mV/48.500ps
dV/dt_f   335.790mV/73.500ps  323.489mV/82.500ps  356.760mV/66.500ps
[Rising waveform]
R_fixture=50.000Ohm
V_fixture=1.100
V_fixture_min=1.060
V_fixture_max=1.170
0s        609mV      588.8mV    647.4mV
1.283ns   609mV      588.8mV    635.1mV
1.343ns   610mV      588.7mV    1.082V
1.413ns   606.4mV    588.7mV    1.149V
1.454ns   946.7mV    589.7mV    1.158V
1.504ns   1.061V     586.6mV    1.164V
1.564ns   1.085V     571.1mV    1.167V
1.644ns   1.093V     991.9mV    1.169V
1.804ns   1.098V     1.053V     1.17V
10ns      1.1V       1.06V      1.17V
[Rising waveform]
R_fixture=50.000Ohm
V_fixture=0
0s        139.1nV    4.091uV    22.07nV
1.283ns   -38.08uV   2.234uV    -16.7mV
1.333ns   352.3uV    18.46uV    408.4mV
1.373ns   726.9uV    -26.9uV    570.6mV
1.413ns   -10.48mV   -120.8uV   623.2mV
1.484ns   468.5mV    1.507mV    652mV
1.564ns   593.8mV    -18.67mV   661mV
1.674ns   619.6mV    509.3mV    664.6mV
1.874ns   626.6mV    599mV      666.3mV
10ns      628.4mV    607.1mV    666.5mV
[Falling waveform]
R_fixture=50.000Ohm
V_fixture=1.100
V_fixture_min=1.060
V_fixture_max=1.170
0s        1.1V       1.06V      1.17V
1.293ns   1.1V       1.06V      1.199V
1.363ns   1.099V     1.06V      836.6mV
1.423ns   1.14V      1.06V      713.9mV
1.524ns   744.2mV    1.061V     663.8mV
1.594ns   655.7mV    1.1V       654.9mV
1.624ns   640.7mV    999.2mV    652.9mV
1.734ns   618.8mV    670.3mV    649.3mV
1.995ns   610.4mV    595.1mV    647.3mV
10ns      609mV      588.7mV    647.3mV
[Falling waveform]
R_fixture=50.000Ohm
V_fixture=0
0s        628.3mV    607mV      666.5mV
1.273ns   628.3mV    607mV      668.6mV
1.323ns   628.2mV    607mV      257.1mV
1.363ns   629.1mV    607.1mV    100.8mV
1.403ns   616.5mV    607.1mV    49.8mV
1.484ns   125.7mV    607.4mV    16.55mV
1.574ns   29.12mV    519mV      5.805mV
1.664ns   11.32mV    91.02mV    2.2mV
1.884ns   1.604mV    8.327mV    276.7uV
10ns      448nV      4.499uV    106.7nV
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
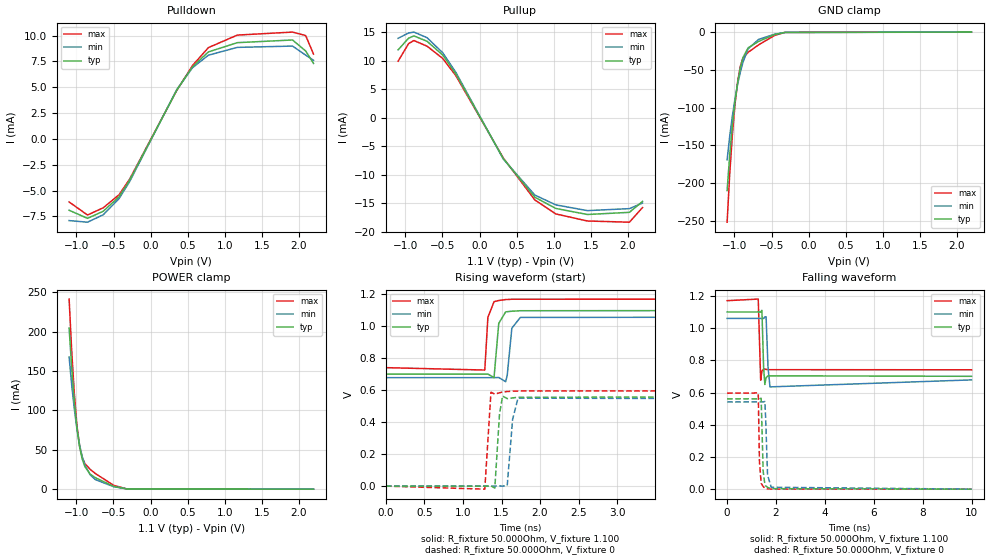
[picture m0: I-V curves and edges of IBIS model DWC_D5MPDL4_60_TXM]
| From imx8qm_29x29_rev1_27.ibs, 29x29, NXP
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[Model] DWC_D5MPDL4_60_TXM
Model_type   I/O
Polarity   Non-Inverting
Enable   Active-High
C_comp   1.572pF   1.476pF   1.691pF
C_comp_pullup   369.452fF   353.210fF   369.980fF
C_comp_pulldown 1.168pF   1.094pF   1.337pF
Vinh = 404.000mV
Vinl = 224.000mV
Vmeas = 314.000mV
Vref = 314.000mV
Rref = 50Ohms
Cref = 0pF
[Model Spec]
Vinh   404.000mV   393.000mV   424.000mV
Vinl   224.000mV   213.000mV   244.000mV
Vmeas   314.000mV   303.000mV   334.000mV
Vref   314.000mV   303.000mV   334.000mV
D_overshoot_ampl_h 0.35 NA   NA
D_overshoot_ampl_l 0.35 NA   NA
D_overshoot_area_l 800.000p NA   NA
D_overshoot_area_h 800.000p NA   NA
[Receiver Thresholds]
Vcross_low = 219.000mV
Vcross_high = 409.000mV
Vdiff_ac = 140.000mV
Vdiff_dc = 140.000mV
Tdiffslew_ac = 10.000ns
[Temperature Range]   25.000   125.000   -40.000
[Voltage Range]   1.100V   1.060V   1.170V
[GND Clamp Reference]   0.00V   0.00V   0.00V
[C Comp Corner]
| variable   typ   min   max
C_comp 1.572pF   1.691pF   1.476pF
C_comp_pullup 369.452fF   369.980fF   353.210fF
C_comp_pulldown 1.168pF   1.337pF   1.094pF
[Pulldown Reference]   0.00V   0.00V   0.00V
[POWER Clamp Reference]   1.100V   1.060V   1.170V
[Pullup Reference]   1.100V   1.060V   1.170V
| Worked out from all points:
|   slope of the pulldown table from 0 to 0.165 V, typ, clamps not added: 72.2 ohm
|   slope of the pullup table from 0 to 0.165 V, typ, clamps not added: 43.3 ohm
|   GND clamp passes 1 mA (typ) near -0.36 V on its own axis
|   POWER clamp passes 1 mA (typ) near -0.39 V on its own axis
|   rising waveform, R_fixture 50.000Ohm, V_fixture 1.100: 20-80 % time 40ps typ, 47.7ps min, 35.2ps max; typ from 0.7 V to 1.1 V
|   rising waveform, R_fixture 50.000Ohm, V_fixture 0: 20-80 % time 41.7ps typ, 54.7ps min, 32.4ps max; typ from 0 V to 0.561 V
|   falling waveform, R_fixture 50.000Ohm, V_fixture 1.100: 20-80 % time 43.2ps typ, 56.6ps min, 33.5ps max; typ from 1.1 V to 0.7 V
|   falling waveform, R_fixture 50.000Ohm, V_fixture 0: 20-80 % time 56ps typ, 67.6ps min, 47ps max; typ from 0.561 V to 0 V
[GND Clamp]
-1.099V   -209.8mA   -169.1mA   -251.7mA
-1.064V   -162.7mA   -137.8mA   -187.8mA
-1.028V   -123.6mA   -111mA     -135.8mA
-992.7mV  -92.04mA   -88.31mA   -95.63mA
-957.3mV  -67.05mA   -69.29mA   -65.81mA
-921.8mV  -47.73mA   -53.39mA   -45.6mA
-886.4mV  -33.92mA   -40.26mA   -34.72mA
-815.5mV  -20.84mA   -22.1mA    -26.75mA
-673.6mV  -12.32mA   -9.665mA   -16.87mA
-460.9mV  -3.34mA    -2.899mA   -4.539mA
-319.1mV  -390.9uA   -567.4uA   -395.4uA
2.198V    38.31nA    663.5nA    7.807nA
[Power Clamp]
-1.098V   204.7mA    167.9mA    241.5mA
-1.063V   153.5mA    132.2mA    175.1mA
-1.027V   110.2mA    101.3mA    120.2mA
-991.8mV  76.87mA    75.61mA    80.19mA
-956.4mV  53.56mA    55.87mA    54.83mA
-920.9mV  38.25mA    41.27mA    40.22mA
-885.5mV  28.61mA    30.83mA    32.49mA
-814.5mV  19.18mA    18.23mA    25.18mA
-743.6mV  14.55mA    12.13mA    19.82mA
-495.5mV  3.463mA    3.102mA    4.838mA
-318.2mV  225.2uA    399.5uA    248.6uA
2.199V    -19.18nA   -668.9nA   -2.437nA
[Pulldown]
-1.099V   -6.9mA     -7.9mA     -6.1mA
-850.9mV  -7.684mA   -8.055mA   -7.361mA
-638.2mV  -6.993mA   -7.334mA   -6.66mA
-425.5mV  -5.595mA   -5.778mA   -5.403mA
-283.6mV  -4.006mA   -4.143mA   -3.899mA
354.5mV   4.731mA    4.788mA    4.708mA
567.3mV   6.992mA    6.899mA    7.114mA
780mV     8.411mA    8.095mA    8.829mA
1.17V     9.308mA    8.851mA    10.04mA
1.915V    9.567mA    8.977mA    10.33mA
2.092V    8.505mA    8.1mA      9.994mA
2.198V    7.3mA      7.6mA      8.2mA
[Pullup]
-1.098V   11.9mA     13.93mA    9.915mA
-956.4mV  13.95mA    14.86mA    13mA
-885.5mV  14.35mA    15.02mA    13.54mA
-708.2mV  13.41mA    14.04mA    12.55mA
-495.5mV  10.98mA    11.38mA    10.39mA
-318.2mV  7.652mA    7.925mA    7.347mA
320mV     -7.156mA   -7.256mA   -7.073mA
745.5mV   -13.96mA   -13.58mA   -14.44mA
1.029V    -15.94mA   -15.31mA   -16.9mA
1.455V    -17mA      -16.32mA   -18.14mA
2.022V    -16.62mA   -15.97mA   -18.35mA
2.199V    -14.7mA    -14.99mA   -15.78mA
[Ramp]
R_load=50.000Ohm
dV/dt_r   288.120mV/41.500ps  276.899mV/52.000ps  307.470mV/34.000ps
dV/dt_f   288.090mV/50.500ps  276.899mV/63.500ps  307.440mV/40.500ps
[Rising waveform]
R_fixture=50.000Ohm
V_fixture=1.100
V_fixture_min=1.060
V_fixture_max=1.170
0s        700.5mV    678.3mV    741mV
1.283ns   700.5mV    678.3mV    726mV
1.323ns   700.7mV    678.3mV    1.055V
1.403ns   679.1mV    678.2mV    1.154V
1.464ns   1.018V     679.5mV    1.161V
1.554ns   1.09V      653.1mV    1.167V
1.574ns   1.091V     692.8mV    1.167V
1.634ns   1.094V     987.7mV    1.169V
1.744ns   1.097V     1.055V     1.169V
10ns      1.1V       1.06V      1.17V
[Rising waveform]
R_fixture=50.000Ohm
V_fixture=0
0s        158.6nV    4.671uV    25.1nV
1.283ns   -35.26uV   2.846uV    -19.13mV
1.363ns   1.48mV     -2.035uV   587.4mV
1.413ns   -12.53mV   -113uV     575.4mV
1.474ns   451.6mV    1.211mV    584mV
1.514ns   563.2mV    140.4uV    588.1mV
1.574ns   547.3mV    3.458mV    591.7mV
1.644ns   551.7mV    418.1mV    593.8mV
1.714ns   555.7mV    550.3mV    594.8mV
10ns      560.9mV    541.3mV    595.9mV
[Falling waveform]
R_fixture=50.000Ohm
V_fixture=1.100
V_fixture_min=1.060
V_fixture_max=1.170
0s        1.1V       1.06V      1.17V
1.273ns   1.1V       1.06V      1.18V
1.373ns   1.099V     1.06V      676.4mV
1.423ns   1.11V      1.06V      733.6mV
1.494ns   750.8mV    1.059V     744.7mV
1.544ns   649.9mV    1.07V      744.5mV
1.594ns   692.7mV    1.07V      743.6mV
1.674ns   703.9mV    755.6mV    742.4mV
1.754ns   703.6mV    634.9mV    741.7mV
10ns      700.5mV    678.3mV    741mV
[Falling waveform]
R_fixture=50.000Ohm
V_fixture=0
0s        560.8mV    541.3mV    595.8mV
1.273ns   560.8mV    541.3mV    597.2mV
1.323ns   560.7mV    541.3mV    171.3mV
1.393ns   564.2mV    541.3mV    36.83mV
1.474ns   113.1mV    541.3mV    16.17mV
1.544ns   29.94mV    544.1mV    7.49mV
1.574ns   21.15mV    447.7mV    5.414mV
1.654ns   11.4mV     87.78mV    2.349mV
1.804ns   3.091mV    11.89mV    557.8uV
10ns      511.4nV    4.964uV    305.6nV
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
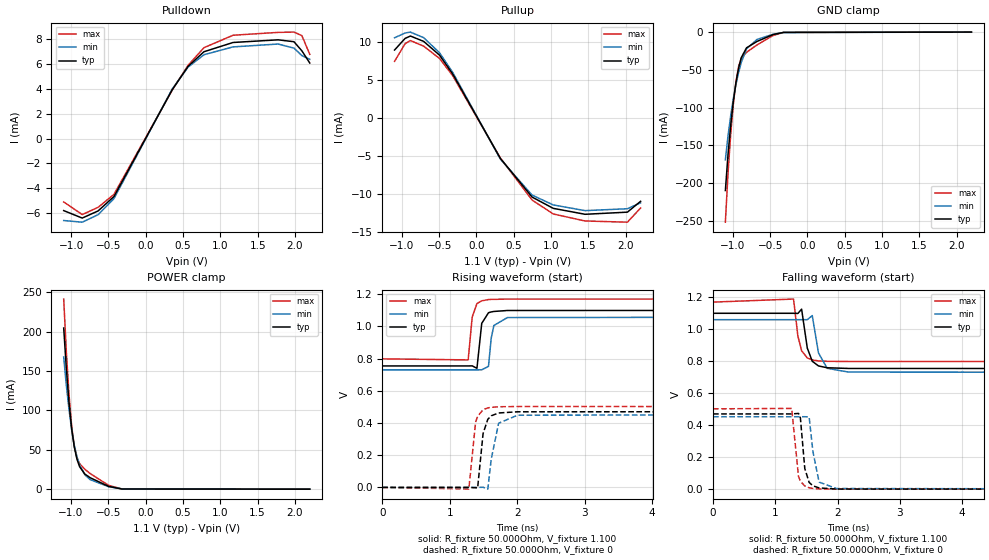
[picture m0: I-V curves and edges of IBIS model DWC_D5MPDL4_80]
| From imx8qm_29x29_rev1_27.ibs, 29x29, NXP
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[Model] DWC_D5MPDL4_80
Model_type   I/O
Polarity   Non-Inverting
Enable   Active-High
C_comp   1.573pF   1.476pF   1.691pF
C_comp_pullup   365.888fF   348.771fF   366.657fF
C_comp_pulldown 1.177pF   1.110pF   1.347pF
Vinh = 390.000mV
Vinl = 210.000mV
Vmeas = 300.000mV
Vref = 300.000mV
Rref = 50Ohms
Cref = 0pF
[Model Spec]
Vinh   390.000mV   379.000mV   409.000mV
Vinl   210.000mV   199.000mV   229.000mV
Vmeas   300.000mV   289.000mV   319.000mV
Vref   300.000mV   289.000mV   319.000mV
D_overshoot_ampl_h 0.35 NA   NA
D_overshoot_ampl_l 0.35 NA   NA
D_overshoot_area_l 800.000p NA   NA
D_overshoot_area_h 800.000p NA   NA
[Receiver Thresholds]
Vcross_low = 205.000mV
Vcross_high = 395.000mV
Vdiff_ac = 140.000mV
Vdiff_dc = 140.000mV
Tdiffslew_ac = 10.000ns
[Temperature Range]   25.000   125.000   -40.000
[Voltage Range]   1.100V   1.060V   1.170V
[GND Clamp Reference]   0.00V   0.00V   0.00V
[C Comp Corner]
| variable   typ   min   max
C_comp 1.573pF   1.691pF   1.476pF
C_comp_pullup 365.888fF   366.657fF   348.771fF
C_comp_pulldown 1.177pF   1.347pF   1.110pF
[Pulldown Reference]   0.00V   0.00V   0.00V
[POWER Clamp Reference]   1.100V   1.060V   1.170V
[Pullup Reference]   1.100V   1.060V   1.170V
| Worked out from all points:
|   slope of the pulldown table from 0 to 0.165 V, typ, clamps not added: 86.6 ohm
|   slope of the pullup table from 0 to 0.165 V, typ, clamps not added: 57.8 ohm
|   GND clamp passes 1 mA (typ) near -0.36 V on its own axis
|   POWER clamp passes 1 mA (typ) near -0.39 V on its own axis
|   rising waveform, R_fixture 50.000Ohm, V_fixture 1.100: 20-80 % time 55.4ps typ, 60.3ps min, 53.3ps max; typ from 0.755 V to 1.1 V
|   rising waveform, R_fixture 50.000Ohm, V_fixture 0: 20-80 % time 81.9ps typ, 91.1ps min, 75.5ps max; typ from 0 V to 0.471 V
|   falling waveform, R_fixture 50.000Ohm, V_fixture 1.100: 20-80 % time 99.9ps typ, 110ps min, 93.9ps max; typ from 1.1 V to 0.755 V
|   falling waveform, R_fixture 50.000Ohm, V_fixture 0: 20-80 % time 73.6ps typ, 83ps min, 67.5ps max; typ from 0.471 V to 0 V
[GND Clamp]
-1.099V   -209.8mA   -169.1mA   -251.7mA
-1.064V   -162.7mA   -137.8mA   -187.8mA
-1.028V   -123.6mA   -111mA     -135.8mA
-992.7mV  -92.04mA   -88.31mA   -95.63mA
-957.3mV  -67.05mA   -69.29mA   -65.81mA
-921.8mV  -47.73mA   -53.39mA   -45.6mA
-886.4mV  -33.92mA   -40.26mA   -34.72mA
-815.5mV  -20.84mA   -22.1mA    -26.75mA
-673.6mV  -12.32mA   -9.665mA   -16.87mA
-460.9mV  -3.34mA    -2.899mA   -4.539mA
-319.1mV  -390.9uA   -567.4uA   -395.4uA
2.198V    38.3nA     663.5nA    7.806nA
[Power Clamp]
-1.098V   204.7mA    167.9mA    241.5mA
-1.063V   153.5mA    132.2mA    175.1mA
-1.027V   110.2mA    101.3mA    120.2mA
-991.8mV  76.87mA    75.61mA    80.19mA
-956.4mV  53.56mA    55.87mA    54.83mA
-920.9mV  38.25mA    41.27mA    40.22mA
-885.5mV  28.61mA    30.83mA    32.49mA
-814.5mV  19.18mA    18.23mA    25.18mA
-743.6mV  14.55mA    12.13mA    19.82mA
-495.5mV  3.463mA    3.102mA    4.838mA
-318.2mV  225.2uA    399.5uA    248.6uA
2.199V    -19.18nA   -668.9nA   -2.436nA
[Pulldown]
-1.099V   -5.8mA     -6.6mA     -5.1mA
-850.9mV  -6.402mA   -6.734mA   -6.119mA
-638.2mV  -5.826mA   -6.131mA   -5.536mA
-425.5mV  -4.664mA   -4.83mA    -4.491mA
354.5mV   3.945mA    4.002mA    3.913mA
567.3mV   5.829mA    5.768mA    5.913mA
780mV     7.01mA     6.769mA    7.336mA
1.17V     7.757mA    7.401mA    8.341mA
1.773V    7.971mA    7.632mA    8.571mA
1.986V    7.818mA    7.305mA    8.595mA
2.092V    7.083mA    6.7mA      8.311mA
2.198V    6.1mA      6.4mA      6.8mA
[Pullup]
-1.098V   8.9mA      10.51mA    7.413mA
-956.4mV  10.43mA    11.14mA    9.738mA
-885.5mV  10.74mA    11.26mA    10.15mA
-708.2mV  10.04mA    10.53mA    9.41mA
-495.5mV  8.229mA    8.543mA    7.796mA
-318.2mV  5.737mA    5.951mA    5.518mA
320mV     -5.363mA   -5.448mA   -5.312mA
745.5mV   -10.45mA   -10.19mA   -10.84mA
1.029V    -11.93mA   -11.48mA   -12.67mA
1.455V    -12.71mA   -12.23mA   -13.59mA
2.022V    -12.43mA   -11.98mA   -13.75mA
2.199V    -11mA      -11.2mA    -11.88mA
[Ramp]
R_load=50.000Ohm
dV/dt_r   244.800mV/69.500ps  234.868mV/76.500ps  262.110mV/65.500ps
dV/dt_f   244.800mV/88.000ps  234.868mV/97.500ps  262.110mV/81.500ps
[Rising waveform]
R_fixture=50.000Ohm
V_fixture=1.100
V_fixture_min=1.060
V_fixture_max=1.170
0s        754.6mV    730.1mV    798.7mV
1.273ns   754.5mV    730.1mV    792mV
1.333ns   755.1mV    730.1mV    1.059V
1.403ns   739.9mV    730mV      1.142V
1.474ns   1.019V     730.7mV    1.159V
1.574ns   1.085V     752mV      1.167V
1.614ns   1.09V      926.3mV    1.168V
1.654ns   1.093V     1.006V     1.168V
1.854ns   1.099V     1.055V     1.17V
10ns      1.1V       1.06V      1.17V
[Rising waveform]
R_fixture=50.000Ohm
V_fixture=0
0s        170.3nV    5.021uV    26.9nV
1.283ns   -29.28uV   3.15uV     -9.911mV
1.383ns   -1.976mV   -44.07uV   404.7mV
1.413ns   -3.863mV   -91.43uV   442.1mV
1.494ns   334.8mV    1.048mV    482.8mV
1.564ns   423.1mV    -10.89mV   493.9mV
1.614ns   444.9mV    173.8mV    497.6mV
1.724ns   462.4mV    398.7mV    500.9mV
2.005ns   469.7mV    448.7mV    502.5mV
10ns      470.6mV    453mV      502.4mV
[Falling waveform]
R_fixture=50.000Ohm
V_fixture=1.100
V_fixture_min=1.060
V_fixture_max=1.170
0s        1.1V       1.06V      1.17V
1.293ns   1.1V       1.06V      1.189V
1.363ns   1.099V     1.06V      957.7mV
1.423ns   1.126V     1.06V      865.8mV
1.514ns   882.8mV    1.06V      820.7mV
1.594ns   800.3mV    1.086V     808.1mV
1.694ns   770.7mV    852mV      802.2mV
1.834ns   759.4mV    755.9mV    799.6mV
2.175ns   755mV      732.4mV    798.5mV
10ns      754.5mV    730.1mV    798.6mV
[Falling waveform]
R_fixture=50.000Ohm
V_fixture=0
0s        470.5mV    453mV      502.3mV
1.263ns   470.5mV    453mV      505.1mV
1.373ns   473.7mV    453mV      79.75mV
1.403ns   446.6mV    453mV      50.13mV
1.474ns   129.1mV    453.1mV    19.87mV
1.544ns   42.21mV    451.3mV    8.868mV
1.604ns   20.92mV    237.1mV    4.601mV
1.704ns   7.926mV    44.15mV    1.64mV
1.985ns   747.8uV    3.956mV    137.1uV
10ns      249.3nV    5.142uV    139.7nV
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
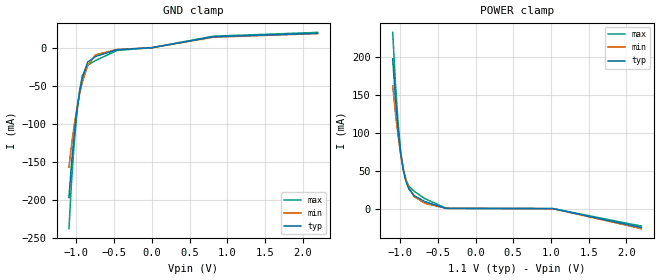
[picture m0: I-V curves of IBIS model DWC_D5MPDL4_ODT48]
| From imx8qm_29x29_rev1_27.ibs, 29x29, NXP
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[Model] DWC_D5MPDL4_ODT48
Model_type   Input
Polarity   Non-Inverting
Enable   Active-High
C_comp   1.511pF   1.428pF   1.614pF
C_comp_power_clamp   379.208fF   356.914fF   389.374fF
C_comp_gnd_clamp 1.103pF   1.053pF   1.247pF
Vinh = 640.000mV
Vinl = 460.000mV
[Model Spec]
D_overshoot_ampl_h 0.35 NA   NA
D_overshoot_ampl_l 0.35 NA   NA
D_overshoot_area_l 800.000p NA   NA
D_overshoot_area_h 800.000p NA   NA
[Receiver Thresholds]
Vcross_low = 455.000mV
Vcross_high = 645.000mV
Vdiff_ac = 140.000mV
Vdiff_dc = 140.000mV
Tdiffslew_ac = 10.000ns
[Temperature Range]   25.000   125.000   -40.000
[Voltage Range]   1.100V   1.060V   1.170V
[GND Clamp Reference]   0.00V   0.00V   0.00V
[C Comp Corner]
| variable   typ   min   max
C_comp 1.511pF   1.614pF   1.428pF
C_comp_pullup 379.208fF   389.374fF   356.914fF
C_comp_pulldown 1.103pF   1.247pF   1.053pF
[POWER Clamp Reference]   1.100V   1.060V   1.170V
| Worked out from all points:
|   GND clamp passes 1 mA (typ) near -0.36 V on its own axis
|   POWER clamp passes 1 mA (typ) near -0.43 V on its own axis
[GND Clamp]
-1.099V   -196.3mA   -156.8mA   -237.2mA
-1.064V   -150.4mA   -126.4mA   -174.5mA
-1.028V   -112.4mA   -100.5mA   -123.8mA
-992.7mV  -81.86mA   -78.77mA   -84.78mA
-957.3mV  -57.8mA    -60.57mA   -56.08mA
-921.8mV  -39.41mA   -45.48mA   -36.96mA
-850.9mV  -18.87mA   -23.45mA   -22.93mA
-744.5mV  -11.45mA   -9.278mA   -16.73mA
-460.9mV  -2.678mA   -2.363mA   -3.639mA
-1.5uV    -21.11uA   -31.8uA    -13.75uA
815.5mV   14.3mA     13.72mA    15.05mA
2.198V    18.82mA    18.47mA    20.03mA
[Power Clamp]
-1.098V   198.2mA    162.5mA    233.2mA
-1.063V   147.6mA    127.2mA    167.7mA
-1.027V   105.1mA    96.7mA     114mA
-991.8mV  72.62mA    71.57mA    75.33mA
-956.4mV  50.08mA    52.33mA    51.1mA
-920.9mV  35.36mA    38.16mA    37.26mA
-885.5mV  26.16mA    28.07mA    30.03mA
-814.5mV  17.24mA    15.98mA    23.11mA
-672.7mV  9.312mA    7.037mA    13.23mA
-389.1mV  252.4uA    284.8uA    493.9uA
1.029V    -4.887nA   -51.14uA   -727.1pA
2.199V    -25.07mA   -26.54mA   -23.14mA
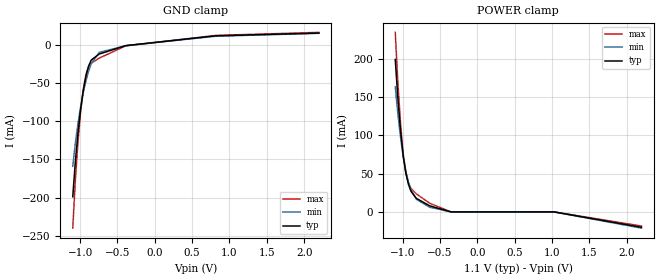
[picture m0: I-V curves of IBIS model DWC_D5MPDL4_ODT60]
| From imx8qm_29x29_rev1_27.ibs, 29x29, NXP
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[Model] DWC_D5MPDL4_ODT60
Model_type   Input
Polarity   Non-Inverting
Enable   Active-High
C_comp   1.523pF   1.436pF   1.629pF
C_comp_power_clamp   382.338fF   362.627fF   390.150fF
C_comp_gnd_clamp 1.100pF   1.035pF   1.249pF
Vinh = 640.000mV
Vinl = 460.000mV
[Model Spec]
D_overshoot_ampl_h 0.35 NA   NA
D_overshoot_ampl_l 0.35 NA   NA
D_overshoot_area_l 800.000p NA   NA
D_overshoot_area_h 800.000p NA   NA
[Receiver Thresholds]
Vcross_low = 455.000mV
Vcross_high = 645.000mV
Vdiff_ac = 140.000mV
Vdiff_dc = 140.000mV
Tdiffslew_ac = 10.000ns
[Temperature Range]   25.000   125.000   -40.000
[Voltage Range]   1.100V   1.060V   1.170V
[GND Clamp Reference]   0.00V   0.00V   0.00V
[C Comp Corner]
| variable   typ   min   max
C_comp 1.523pF   1.629pF   1.436pF
C_comp_pullup 382.338fF   390.150fF   362.627fF
C_comp_pulldown 1.100pF   1.249pF   1.035pF
[POWER Clamp Reference]   1.100V   1.060V   1.170V
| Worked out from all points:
|   GND clamp passes 1 mA (typ) near -0.36 V on its own axis
|   POWER clamp passes 1 mA (typ) near -0.43 V on its own axis
[GND Clamp]
-1.099V   -199mA     -159.2mA   -240mA
-1.064V   -152.9mA   -128.8mA   -177.1mA
-1.028V   -114.6mA   -102.6mA   -126.1mA
-992.7mV  -83.85mA   -80.65mA   -86.96mA
-957.3mV  -59.62mA   -62.3mA    -58.02mA
-921.8mV  -41.05mA   -47.05mA   -38.67mA
-886.4mV  -27.96mA   -34.54mA   -28.6mA
-850.9mV  -20.16mA   -24.72mA   -24.29mA
-744.5mV  -12.34mA   -10.13mA   -17.71mA
-390mV    -1.367mA   -1.463mA   -1.624mA
815.5mV   11.45mA    10.97mA    12.02mA
2.198V    15.06mA    14.76mA    15.98mA
[Power Clamp]
-1.098V   199.4mA    163.6mA    234.9mA
-1.063V   148.7mA    128.2mA    169.1mA
-1.027V   106.1mA    97.63mA    115.1mA
-991.8mV  73.47mA    72.38mA    76.3mA
-956.4mV  50.78mA    53.04mA    51.84mA
-920.9mV  35.94mA    38.78mA    37.85mA
-885.5mV  26.65mA    28.63mA    30.52mA
-814.5mV  17.63mA    16.44mA    23.52mA
-637.3mV  7.982mA    6.115mA    11.34mA
-353.6mV  17.25uA    112.1uA    100.5uA
1.029V    -4.877nA   -40.94uA   -721.6pA
2.199V    -20.09mA   -21.24mA   -18.49mA
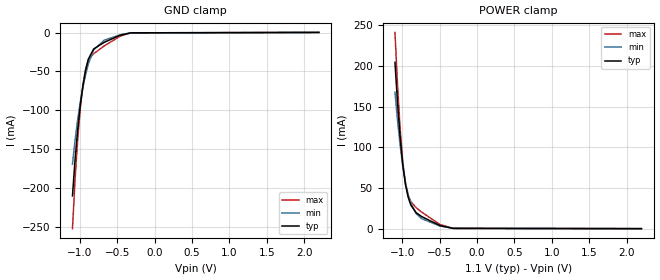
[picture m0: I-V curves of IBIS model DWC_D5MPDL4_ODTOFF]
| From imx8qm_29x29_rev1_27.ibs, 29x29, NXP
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[Model] DWC_D5MPDL4_ODTOFF
Model_type   Input
Polarity   Non-Inverting
Enable   Active-High
C_comp   1.483pF   1.387pF   1.600pF
C_comp_power_clamp   323.277fF   298.219fF   351.442fF
C_comp_gnd_clamp 1.141pF   1.068pF   1.240pF
Vinh = 640.000mV
Vinl = 460.000mV
[Model Spec]
D_overshoot_ampl_h 0.35 NA   NA
D_overshoot_ampl_l 0.35 NA   NA
D_overshoot_area_l 800.000p NA   NA
D_overshoot_area_h 800.000p NA   NA
[Receiver Thresholds]
Vcross_low = 455.000mV
Vcross_high = 645.000mV
Vdiff_ac = 140.000mV
Vdiff_dc = 140.000mV
Tdiffslew_ac = 10.000ns
[Temperature Range]   25.000   125.000   -40.000
[Voltage Range]   1.100V   1.060V   1.170V
[GND Clamp Reference]   0.00V   0.00V   0.00V
[C Comp Corner]
| variable   typ   min   max
C_comp 1.483pF   1.600pF   1.387pF
C_comp_pullup 323.277fF   351.442fF   298.219fF
C_comp_pulldown 1.141pF   1.240pF   1.068pF
[POWER Clamp Reference]   1.100V   1.060V   1.170V
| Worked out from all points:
|   GND clamp passes 1 mA (typ) near -0.36 V on its own axis
|   POWER clamp passes 1 mA (typ) near -0.39 V on its own axis
[GND Clamp]
-1.099V   -209.7mA   -169mA     -251.7mA
-1.064V   -162.7mA   -137.9mA   -187.8mA
-1.028V   -123.6mA   -111mA     -135.9mA
-992.7mV  -92.11mA   -88.31mA   -95.85mA
-957.3mV  -67.15mA   -69.3mA    -66.11mA
-921.8mV  -47.88mA   -53.41mA   -45.95mA
-886.4mV  -34.11mA   -40.3mA    -35.12mA
-815.5mV  -21.1mA    -22.17mA   -27.14mA
-673.6mV  -12.53mA   -9.801mA   -17.15mA
-460.9mV  -3.416mA   -2.964mA   -4.639mA
-319.1mV  -401.1uA   -581.6uA   -406.8uA
2.198V    127uA      103.5uA    158.2uA
[Power Clamp]
-1.098V   204.6mA    167.9mA    241.4mA
-1.063V   153.5mA    132.2mA    175.1mA
-1.027V   110.2mA    101.2mA    120.2mA
-991.8mV  76.91mA    75.6mA     80.37mA
-956.4mV  53.66mA    55.88mA    55.16mA
-920.9mV  38.44mA    41.31mA    40.68mA
-885.5mV  28.89mA    30.91mA    33.05mA
-814.5mV  19.57mA    18.41mA    25.77mA
-743.6mV  14.95mA    12.38mA    20.38mA
-495.5mV  3.599mA    3.224mA    5.023mA
-318.2mV  236.4uA    418.4uA    261.2uA
2.199V    -63.5uA    -53.95uA   -74.1uA
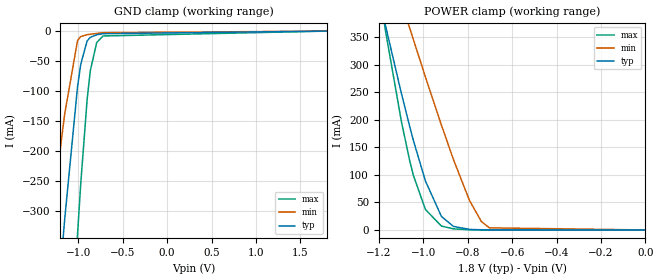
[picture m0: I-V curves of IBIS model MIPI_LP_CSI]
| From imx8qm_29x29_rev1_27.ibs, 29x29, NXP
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[Model] MIPI_LP_CSI
Model_type   Input
Polarity   Non-Inverting
Enable   Active-High
Vinh =   0.88
Vinl =   0.55
|   typ   min   max
C_comp   1.2p   1.02p   1.24p
[Temperature Range]   85   125   -40
[Voltage Range]   1.8   1.52   1.98
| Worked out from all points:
|   GND clamp passes 1 mA (typ) near -0.49 V on its own axis
|   POWER clamp passes 1 mA (typ) near -0.79 V on its own axis
[GND_clamp]
|Voltage   I (typ)   I (min)   I (max)
-1.764V   -1.504A    -927.3mA   -2.592A
-1.332V   -645.6mA   -358.9mA   -1.255A
-1.296V   -577mA     -313.1mA   -1.147A
-1.188V   -377.1mA   -180mA     -829mA
-1.152V   -313.4mA   -138.1mA   -725.8mA
-1.008V   -93.18mA   -15.98mA   -339.9mA
-972mV    -55.59mA   -9.064mA   -255.1mA
-900mV    -16.47mA   -5.99mA    -114.5mA
-864mV    -10.34mA   -5.25mA    -66mA
-792mV    -6.135mA   -3.907mA   -19.07mA
-720mV    -4.323mA   -2.673mA   -8.16mA
1.8V      4.16nA     777.7pA    57.34nA
[Power_clamp]
|Voltage   I (typ)   I (min)   I (max)
-1.782V   1.556A     1.311A     2.153A
-1.17V    371.3mA    505.9mA    361.7mA
-1.098V   247.4mA    413.6mA    196.3mA
-1.062V   189.5mA    367.9mA    127.8mA
-1.044V   162.1mA    345.2mA    98.75mA
-990mV    88.79mA    277.7mA    37mA
-918mV    24.5mA     190.3mA    7.093mA
-864mV    6.439mA    127.8mA    2.033mA
-792mV    1.021mA    53.67mA    402uA
-738mV    282.5uA    15.1mA     132.7uA
-702mV    142.9uA    3.865mA    73.38uA
0V        4.16nA     777.7pA    57.34nA
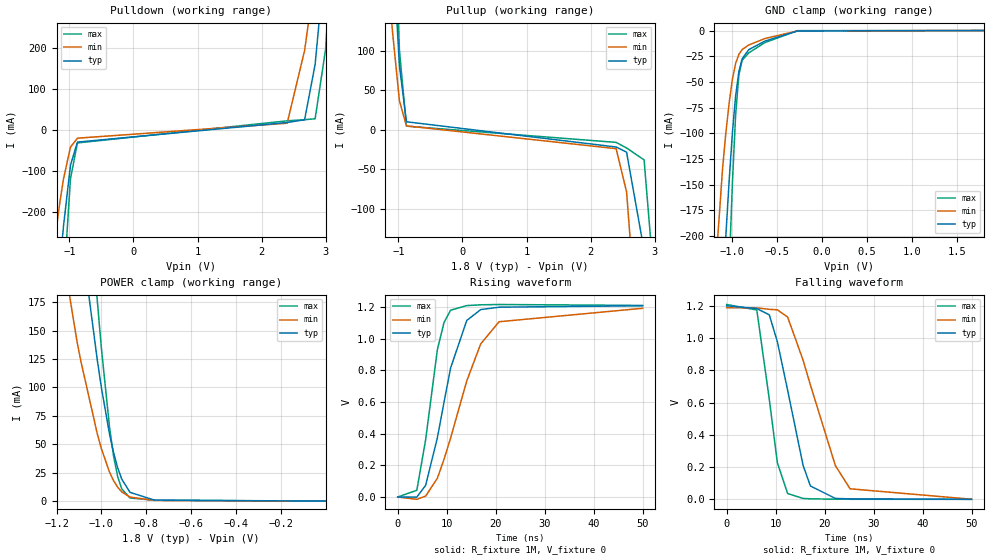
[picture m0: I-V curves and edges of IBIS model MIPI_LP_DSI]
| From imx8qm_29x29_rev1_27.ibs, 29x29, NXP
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[Model] MIPI_LP_DSI
Model_type   I/O
Polarity   Non-Inverting
Enable   Active-High
Vinh =   0.88
Vinl =   0.55
Vmeas = 0.6
Rref = 1M
Vref = 0
|   typ   min   max
C_comp  6.37p   6.20p   6.54p
[Temperature Range]   85   125   -40
[Voltage Range]   1.8   1.52   1.98
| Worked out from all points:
|   slope of the pulldown table from 0 to 0.27 V, typ, clamps not added: 111 ohm
|   slope of the pullup table from 0 to 0.27 V, typ, clamps not added: 14.7 kohm
|   GND clamp passes 1 mA (typ) near -0.33 V on its own axis
|   POWER clamp passes 1 mA (typ) near -0.77 V on its own axis
|   falling waveform, R_fixture 1M, V_fixture 0: 20-80 % time 4.91ns typ, 7.13ns min, 2.98ns max; typ from 1.2 V to 0 V
|   rising waveform, R_fixture 1M, V_fixture 0: 20-80 % time 4.82ns typ, 7.26ns min, 3.2ns max; typ from 0 V to 1.21 V
[GND_clamp]
|Voltage   I (typ)   I (min)   I (max)
-1.8V     -1.608A    -995.2mA   -2.596A
-1.109V   -258.7mA   -133.8mA   -430.2mA
-1.073V   -199.9mA   -99.74mA   -329mA
-1.036V   -146mA     -70.4mA    -233.7mA
-1V       -99.47mA   -47.42mA   -148.6mA
-963.7mV  -63.29mA   -31.91mA   -81.65mA
-927.4mV  -39.79mA   -23.08mA   -42.92mA
-891mV    -27.48mA   -18.47mA   -28.89mA
-818.3mV  -18.6mA    -14.04mA   -21.73mA
-636.5mV  -10.18mA   -7.724mA   -11.63mA
-272.9mV  -360.4uA   -288.5uA   -68.59uA
1.8V      29.12uA    51.4uA     11.28uA
[Power_clamp]
|Volatge   I (typ)   I (min)   I (max)
-1.8V     1.584A     981.6mA    2.537A
-1.109V   263.6mA    140.7mA    414.1mA
-1.091V   233.6mA    122.6mA    363.6mA
-1.018V   123.6mA    58.92mA    175.6mA
-1V       99.74mA    46.06mA    134.3mA
-963.7mV  58.73mA    25.42mA    64.71mA
-945.5mV  42.39mA    17.9mA     39.21mA
-927.4mV  29.25mA    12.22mA    21.38mA
-909.2mV  19.34mA    8.156mA    10.74mA
-872.8mV  7.764mA    3.577mA    2.807mA
-763.7mV  909.8uA    638.9uA    798uA
-180uV    29.14uA    19uA       18.23uA
[Pulldown]
|Volatge   I (typ)   I (min)   I (max)
-1.8V     -1.612A    -997mA     -2.601A
-1.364V   -735.7mA   -431.5mA   -1.209A
-1.146V   -327.6mA   -174.8mA   -542.4mA
-1.091V   -235.5mA   -120.1mA   -386.3mA
-982.5mV  -86.5mA    -42.49mA   -119.3mA
-873.5mV  -30.22mA   -20.65mA   -32.24mA
2.397V    17.67mA    15.96mA    21.77mA
2.669V    24.3mA     193.8mA    24.61mA
2.833V    159.9mA    380.3mA    26.83mA
2.996V    429.8mA    579.4mA    196.3mA
3.105V    629.9mA    715.6mA    484.6mA
3.595V    1.587A     1.346A     1.976A
[Pullup]
|Volatge   I (typ)   I (min)   I (max)
-1.8V     1.585A     981.9mA    2.537A
-1.364V   729.7mA    433mA      1.174A
-1.146V   328.6mA    180.4mA    521.1mA
-1.091V   236.8mA    124.5mA    367.4mA
-982.5mV  81.06mA    36.58mA    100.3mA
-873.5mV  10.09mA    4.898mA    4.554mA
2.397V    -21.84mA   -23.94mA   -16.01mA
2.56V     -28.42mA   -78.68mA   -23.07mA
2.833V    -152.7mA   -368.3mA   -38.16mA
2.996V    -422.5mA   -572.5mA   -197.7mA
3.105V    -626.4mA   -712.6mA   -488.8mA
3.595V    -1.604A    -1.362A    -2.013A
[Ramp]
|variable typ   min   max
dV/dt_r   726m/4.88n   727m/7.36n   746m/3.26n
dV/dt_f   726m/5.00n   728m/7.28n   739m/3.04n
R_load  = 1M
[Falling waveform]
R_fixture = 1M
V_fixture = 0
|time   V (typ)   V (min)   V (max)
0s        1.2V       1.188V     1.208V
6.15ns    1.183V     1.187V     1.174V
8.7ns     1.144V     1.178V     621.2mV
10.35ns   977mV      1.175V     226.7mV
12.45ns   675.8mV    1.13V      36.11mV
15.6ns    210.9mV    862.8mV    5.38mV
17.1ns    82.73mV    708.6mV    3.235mV
22.2ns    5.614mV    209.1mV    891.1uV
25.2ns    2.798mV    65.29mV    435.7uV
50ns      27.58uV    677.2uV    5.889uV
[Rising waveform]
R_fixture = 1M
V_fixture = 0
|time   V (typ)   V (min)   V (max)
0s        -8.947uV   -34.45uV   2.263uV
3.9ns     -519.9uV   -14.73mV   42.69mV
5.7ns     73.6mV     5.594mV    362.2mV
8.1ns     374.8mV    119mV      932.1mV
9.45ns    598.5mV    237.4mV    1.103V
10.8ns    815.9mV    372.9mV    1.181V
14.1ns    1.116V     734.2mV    1.21V
16.95ns   1.185V     968mV      1.215V
20.7ns    1.2V       1.108V     1.217V
50ns      1.209V     1.193V     1.211V
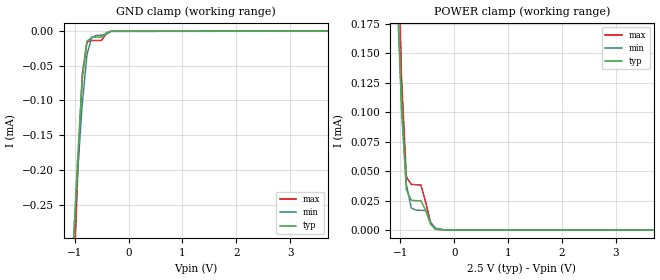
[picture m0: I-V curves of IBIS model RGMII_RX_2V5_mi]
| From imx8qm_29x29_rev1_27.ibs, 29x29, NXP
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[Model] RGMII_RX_2V5_mi
|   Model RGMII_RX_2V5_mi
| This model was characterised for following simulation conditions:
| External (pad) voltage:
|   - Typ: 2.5V,   - Min: 2.25V,   - Max: 2.75V
| Library cells for typ/min/max conditions are connected as defined below:
|  IO - External Pad
|  ASRCN3V3[0] - vdd
|  ASRCN3V3[1] - gnd
|  ASRCN3V3[2] - vdd
|  ASRCN3V3[3] - gnd
|  ASRCN3V3[4] - gnd
|  ASRCP3V3[0] - gnd
|  ASRCP3V3[1] - vdd
|  ASRCP3V3[2] - gnd
|  ASRCP3V3[3] - vdd
|  ASRCP3V3[4] - gnd
|  PDRV - gnd
|  PSW - vdd
|  gnd - gnd
|  gnde - gnde
|  vdd - vdd
|  vdde3v3 - vdde3v3
| All other pins connected to ground
Model_type Input
Vinl =   0.7000V
Vinh =   1.7000V
C_comp   0.1460pF   0.1416pF   0.1507pF
|C_comp_pullup   29.8653fF   29.4591fF   30.1209fF
|C_comp_pulldown   10.7739fF   10.8362fF   10.7032fF
[Receiver Thresholds]
Vth  =   1.2500V
Vinh_ac  =   1.0000V
Vinh_dc  =   0.4500V
Vinl_ac  =   -1.0000V
Vinl_dc  =   -0.5500V
Tslew_ac  =   0.7500nS
[Temperature Range]   25.0000   0.1050k   -20.0000
[Voltage Range]   2.5000V   2.2500V   2.7500V
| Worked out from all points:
|   GND clamp passes 1 mA (typ) near -1.42 V on its own axis
|   POWER clamp passes 1 mA (typ) near -1.51 V on its own axis
[GND_clamp]
|Voltage   I(typ)   I(min)   I(max)
-2.75V    -2.816mA   -2.309mA   -3.534mA
-1.04V    -339.1uA   -324uA     -418.1uA
-950mV    -192.5uA   -209.2uA   -220.5uA
-860mV    -70.63uA   -106.6uA   -64.35uA
-770mV    -14.48uA   -33.48uA   -15.47uA
-680mV    -9.005uA   -8.807uA   -13.56uA
-590mV    -8.817uA   -6.144uA   -13.52uA
-500mV    -8.808uA   -5.964uA   -13.5uA
-410mV    -2.511uA   -4.47uA    -3.073uA
-320mV    -119.4nA   -483.5nA   -91.03nA
5.5V      0A         0A         0A
[POWER_clamp]
|Voltage   I(typ)   I(min)   I(max)
-2.75V    2.735mA    2.215mA    3.463mA
-1.07V    231.7uA    207.6uA    305.4uA
-980mV    103.4uA    107uA      129.9uA
-890mV    34.16uA    38.93uA    45.17uA
-800mV    25.18uA    18.79uA    38.69uA
-710mV    24.83uA    16.82uA    38.4uA
-620mV    24.8uA     16.67uA    38.26uA
-530mV    16.8uA     16.63uA    23.38uA
-440mV    4.837uA    6.402uA    6.234uA
-350mV    675.5nA    1.585uA    691.8nA
-170mV    2.03nA     19.85nA    1.175nA
5.5V      0A         0A         0A
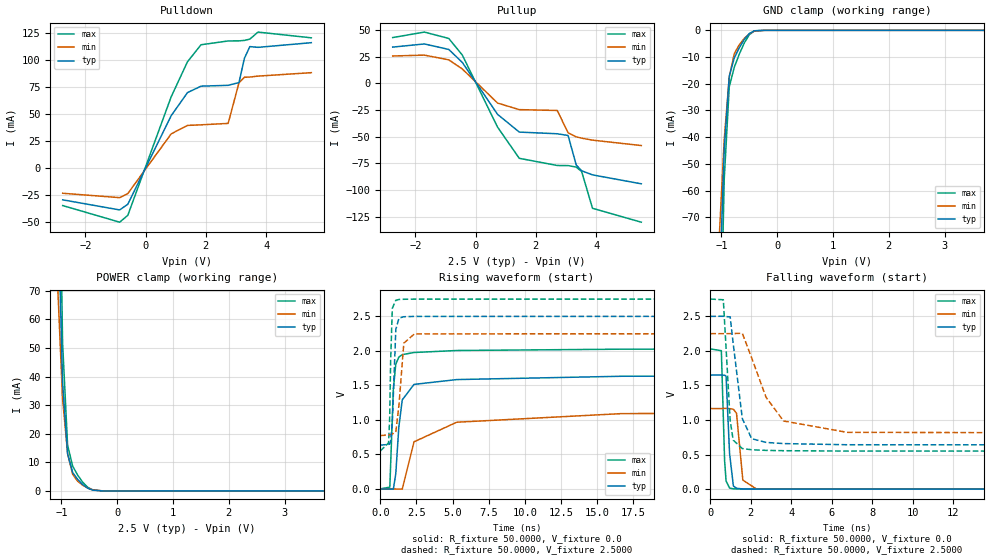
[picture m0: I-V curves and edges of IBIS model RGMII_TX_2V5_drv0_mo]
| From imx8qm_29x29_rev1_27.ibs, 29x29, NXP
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[Model] RGMII_TX_2V5_drv0_mo
|   Model RGMII_TX_2V5_drv0_mo
| This model was characterised for following simulation conditions:
| External (pad) voltage:
|   - Typ: 2.5V,   - Min: 2.25V,   - Max: 2.75V
| Library cells for typ/min/max conditions are connected as defined below:
|  IO - External Pad
|  A - Core Input
|  EN - Output Buffer Enable
|  ASRCN3V3[0] - vdd
|  ASRCN3V3[1] - gnd
|  ASRCN3V3[2] - vdd
|  ASRCN3V3[3] - gnd
|  ASRCN3V3[4] - gnd
|  ASRCP3V3[0] - gnd
|  ASRCP3V3[1] - vdd
|  ASRCP3V3[2] - gnd
|  ASRCP3V3[3] - vdd
|  ASRCP3V3[4] - gnd
|  PDRV - gnd
|  PSW - vdd
|  gnd - gnd
|  gnde - gnde
|  vdd - vdd
|  vdde3v3 - vdde3v3
| All other pins connected to ground
Model_type 3-state
Polarity   Non-Inverting
Enable   Active-Low
Vmeas =  1.2500V
Cref =   5.0000pF
Rref =   1.0000M
Vref =   1.2500V
C_comp   1.9496pF   1.9278pF   1.9894pF
|C_comp_pullup   0.3440pF   0.3544pF   0.3291pF
|C_comp_pulldown   0.8715pF   0.9030pF   0.8275pF
[Model Spec]
| variable   typ   min   max
Vmeas   1.2500V   1.1250V   1.3750V
[Temperature Range]   25.0000   0.1050k   -20.0000
[Voltage Range]   2.5000V   2.2500V   2.7500V
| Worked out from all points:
|   slope of the pulldown table from 0 to 0.375 V, typ, clamps not added: 16.5 ohm
|   slope of the pullup table from 0 to 0.375 V, typ, clamps not added: 23.8 ohm
|   GND clamp passes 1 mA (typ) near -0.48 V on its own axis
|   POWER clamp passes 1 mA (typ) near -0.53 V on its own axis
|   rising waveform, R_fixture 50.0000, V_fixture 0.0: 20-80 % time 458ps typ, 2.53ns min, 213ps max; typ from 0 V to 1.65 V
|   rising waveform, R_fixture 50.0000, V_fixture 2.5000: 20-80 % time 193ps typ, 278ps min, 113ps max; typ from 0.634 V to 2.5 V
|   falling waveform, R_fixture 50.0000, V_fixture 0.0: 20-80 % time 168ps typ, 204ps min, 110ps max; typ from 1.65 V to 0 V
|   falling waveform, R_fixture 50.0000, V_fixture 2.5000: 20-80 % time 466ps typ, 1.35ns min, 250ps max; typ from 2.5 V to 0.634 V
[Pulldown]
|Voltage   I(typ)   I(min)   I(max)
-2.75V    -29.22mA   -23.15mA   -34.51mA
-860mV    -38.56mA   -27.21mA   -49.89mA
-590mV    -33.32mA   -23.43mA   -43.55mA
850mV     48.56mA    31.75mA    66.02mA
1.39V     69.86mA    39.55mA    98.35mA
1.84V     75.83mA    40.09mA    114.1mA
2.74V     76.61mA    41.41mA    117.6mA
3.1V      79.17mA    78.99mA    117.7mA
3.28V     101.6mA    84.06mA    118.1mA
3.46V     112.4mA    84.25mA    119.3mA
3.73V     111.7mA    85.11mA    125.8mA
5.5V      116mA      88.3mA     120.5mA
[Pullup]
|Voltage   I(typ)   I(min)   I(max)
-2.75V    33.86mA    25.53mA    42.78mA
-1.7V     36.82mA    26.36mA    47.9mA
-890mV    31.68mA    21.93mA    41.97mA
-440mV    19.52mA    13.4mA     26.39mA
730mV     -29.05mA   -18.47mA   -41.01mA
1.45V     -45.62mA   -24.62mA   -70.16mA
2.71V     -47.2mA    -25.41mA   -76.87mA
3.07V     -48.81mA   -46.26mA   -76.94mA
3.34V     -76.41mA   -50.06mA   -78.39mA
3.52V     -81.81mA   -51.3mA    -82.52mA
3.88V     -85.64mA   -53.17mA   -116.9mA
5.5V      -94.02mA   -58.21mA   -129.9mA
[GND_clamp]
|Voltage   I(typ)   I(min)   I(max)
-2.75V    -3.095A    -1.863A    -4.789A
-1.04V    -100.9mA   -77.82mA   -140.7mA
-950mV    -44.47mA   -40.86mA   -55.79mA
-860mV    -17.18mA   -17.59mA   -21.17mA
-770mV    -10.34mA   -8.753mA   -13.84mA
-680mV    -6.532mA   -5.396mA   -8.906mA
-590mV    -3.404mA   -3.019mA   -4.694mA
-500mV    -1.195mA   -1.287mA   -1.627mA
-410mV    -168.8uA   -312.8uA   -198.9uA
-230mV    -283.8nA   -2.491uA   -119.1nA
5.5V      0A         0A         0A
[POWER_clamp]
|Voltage   I(typ)   I(min)   I(max)
-2.75V    3.023A     1.788A     4.744A
-1.07V    106mA      73.03mA    167.9mA
-980mV    38.14mA    32.4mA     52.11mA
-890mV    12.98mA    13.13mA    16.04mA
-800mV    6.499mA    5.855mA    8.73mA
-710mV    4.048mA    3.412mA    5.557mA
-620mV    2.244mA    2.008mA    3.067mA
-530mV    971.7uA    1.01mA     1.289mA
-440mV    275uA      386uA      329.3uA
-260mV    2.098uA    12.18uA    1.171uA
5.5V      0A         0A         0A
[Ramp]
| variable   typ   min   max
dV/dt_r  0.9917/0.4579n   0.6989/2.5282n   1.2178/0.2134n
dV/dt_f  1.1199/0.4663n   0.8875/1.3489n   1.3205/0.2499n
R_load = 50.0000
[Rising Waveform]
R_fixture= 50.0000
V_fixture= 0.0
V_fixture_min= 0.0
V_fixture_max= 0.0
|time   V(typ)   V(min)   V(max)
0s        12.75nV    206nV      38.4nV
660.9ps   -1.702mV   -1.253mV   26.77mV
904.3ps   -3.33mV    -503.2uV   1.444V
1.072ns   218.2mV    -1.266mV   1.806V
1.285ns   900.3mV    -2.23mV    1.909V
1.521ns   1.29V      -2.074mV   1.945V
2.334ns   1.514V     682.4mV    1.976V
5.292ns   1.584V     966.3mV    2.005V
16.7ns    1.632V     1.091V     2.024V
100ns     1.653V     1.165V     2.03V
[Rising Waveform]
R_fixture= 50.0000
V_fixture= 2.5000
V_fixture_min= 2.2500
V_fixture_max= 2.7500
|time   V(typ)   V(min)   V(max)
0s        633.6mV    772.7mV    549.2mV
574.4ps   645.2mV    781.4mV    667.2mV
649.1ps   650.5mV    785.5mV    1.019V
718.1ps   694mV      789.8mV    1.856V
832.4ps   962.3mV    795.6mV    2.616V
1.075ns   2.31V      823.5mV    2.733V
1.295ns   2.474V     1.22V      2.744V
1.628ns   2.494V     2.111V     2.747V
2.365ns   2.499V     2.246V     2.749V
100ns     2.5V       2.25V      2.75V
[Falling Waveform]
R_fixture= 50.0000
V_fixture= 0.0
V_fixture_min= 0.0
V_fixture_max= 0.0
|time   V(typ)   V(min)   V(max)
0s        1.65V      1.166V     2.029V
546.8ps   1.651V     1.166V     2.003V
707.1ps   1.649V     1.169V     415.6mV
779.8ps   1.633V     1.169V     118.9mV
952.4ps   516.9mV    1.165V     15.42mV
1.141ns   45.75mV    1.156V     5.086mV
1.295ns   12.65mV    1.099V     2.997mV
1.607ns   3.438mV    131.5mV    1.618mV
2.268ns   1.064mV    4.263mV    747.4uV
100ns     -81.52nV   2.137uV    -306nV
[Falling Waveform]
R_fixture= 50.0000
V_fixture= 2.5000
V_fixture_min= 2.2500
V_fixture_max= 2.7500
|time   V(typ)   V(min)   V(max)
0s        2.5V       2.25V      2.75V
644.1ps   2.501V     2.249V     2.74V
982.6ps   2.491V     2.251V     990.4mV
1.132ns   2.106V     2.251V     709.6mV
1.581ns   1.023V     2.256V     587.5mV
2.042ns   730.5mV    1.901V     570mV
2.752ns   676.4mV    1.33V      561.1mV
3.616ns   659.4mV    986.5mV    556.4mV
6.751ns   642.6mV    822.1mV    551.2mV
100ns     633.5mV    770.8mV    549.2mV
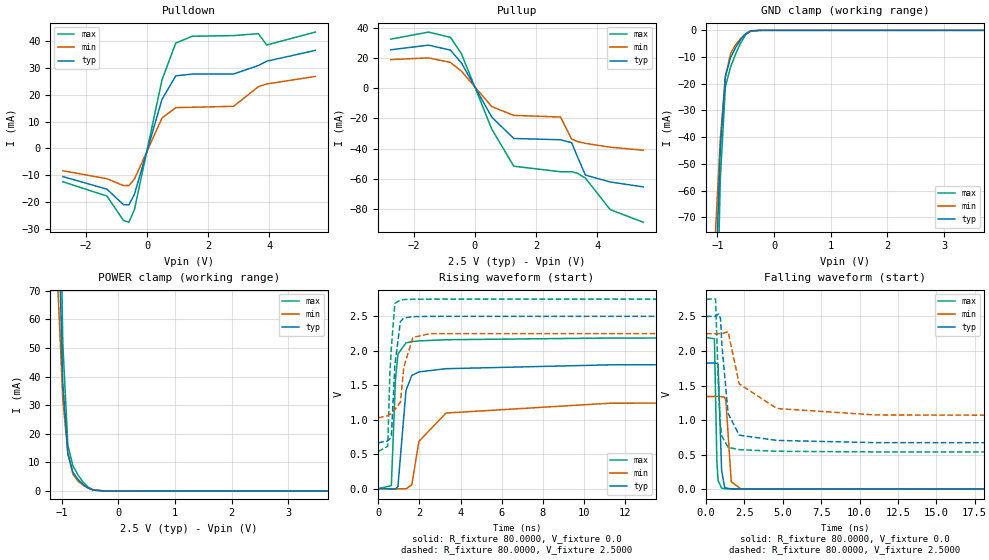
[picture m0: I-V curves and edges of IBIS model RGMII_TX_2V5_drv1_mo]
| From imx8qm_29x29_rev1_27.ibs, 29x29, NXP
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[Model] RGMII_TX_2V5_drv1_mo
|   Model RGMII_TX_2V5_drv1_mo
| This model was characterised for following simulation conditions:
| External (pad) voltage:
|   - Typ: 2.5V,   - Min: 2.25V,   - Max: 2.75V
| Library cells for typ/min/max conditions are connected as defined below:
|  IO - External Pad
|  A - Core Input
|  EN - Output Buffer Enable
|  ASRCN3V3[0] - vdd
|  ASRCN3V3[1] - gnd
|  ASRCN3V3[2] - vdd
|  ASRCN3V3[3] - gnd
|  ASRCN3V3[4] - gnd
|  ASRCP3V3[0] - gnd
|  ASRCP3V3[1] - vdd
|  ASRCP3V3[2] - gnd
|  ASRCP3V3[3] - vdd
|  ASRCP3V3[4] - gnd
|  PDRV - vdd
|  PSW - vdd
|  gnd - gnd
|  gnde - gnde
|  vdd - vdd
|  vdde3v3 - vdde3v3
| All other pins connected to ground
Model_type 3-state
Polarity   Non-Inverting
Enable   Active-Low
Vmeas =  1.2500V
Cref =   5.0000pF
Rref =   1.0000M
Vref =   1.2500V
C_comp   1.9495pF   1.9276pF   1.9893pF
|C_comp_pullup   0.3444pF   0.3549pF   0.3292pF
|C_comp_pulldown   0.8702pF   0.9017pF   0.8262pF
[Model Spec]
| variable   typ   min   max
Vmeas   1.2500V   1.1250V   1.3750V
[Temperature Range]   25.0000   0.1050k   -20.0000
[Voltage Range]   2.5000V   2.2500V   2.7500V
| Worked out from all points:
|   slope of the pulldown table from 0 to 0.375 V, typ, clamps not added: 25.8 ohm
|   slope of the pullup table from 0 to 0.375 V, typ, clamps not added: 27.8 ohm
|   GND clamp passes 1 mA (typ) near -0.48 V on its own axis
|   POWER clamp passes 1 mA (typ) near -0.53 V on its own axis
|   rising waveform, R_fixture 80.0000, V_fixture 0.0: 20-80 % time 320ps typ, 1.2ns min, 176ps max; typ from 0 V to 1.83 V
|   rising waveform, R_fixture 80.0000, V_fixture 2.5000: 20-80 % time 244ps typ, 273ps min, 165ps max; typ from 0.665 V to 2.5 V
|   falling waveform, R_fixture 80.0000, V_fixture 0.0: 20-80 % time 157ps typ, 226ps min, 107ps max; typ from 1.82 V to 0 V
|   falling waveform, R_fixture 80.0000, V_fixture 2.5000: 20-80 % time 478ps typ, 1.57ns min, 242ps max; typ from 2.5 V to 0.665 V
[Pulldown]
|Voltage   I(typ)   I(min)   I(max)
-2.75V    -10.48mA   -8.319mA   -12.42mA
-1.31V    -15.18mA   -11.27mA   -17.74mA
-770mV    -20.94mA   -13.83mA   -26.81mA
-590mV    -20.99mA   -13.79mA   -27.46mA
-410mV    -17.02mA   -11.37mA   -22.68mA
490mV     18.29mA    11.33mA    25.56mA
940mV     27.02mA    15.2mA     39.23mA
1.48V     27.68mA    15.32mA    41.77mA
2.83V     27.72mA    15.69mA    42mA
3.64V     30.87mA    22.99mA    42.74mA
3.91V     32.46mA    23.99mA    38.5mA
5.5V      36.49mA    26.8mA     43.31mA
[Pullup]
|Voltage   I(typ)   I(min)   I(max)
-2.75V    25.74mA    19.22mA    32.82mA
-1.52V    28.83mA    20.35mA    37.52mA
-800mV    25.52mA    17.32mA    34mA
-440mV    16.95mA    11.46mA    23.04mA
550mV     -19.1mA    -12.09mA   -27.08mA
1.27V     -33.32mA   -17.95mA   -51.78mA
2.8V      -34.16mA   -19.01mA   -55.44mA
3.16V     -36.11mA   -33.71mA   -55.48mA
3.34V     -44.95mA   -35.27mA   -56.31mA
3.61V     -57.68mA   -36.57mA   -59.65mA
4.42V     -62.26mA   -39.1mA    -80.67mA
5.5V      -65.54mA   -41.12mA   -89.04mA
[GND_clamp]
|Voltage   I(typ)   I(min)   I(max)
-2.75V    -3.095A    -1.863A    -4.789A
-1.04V    -100.9mA   -77.82mA   -140.7mA
-950mV    -44.47mA   -40.86mA   -55.79mA
-860mV    -17.18mA   -17.59mA   -21.17mA
-770mV    -10.34mA   -8.753mA   -13.84mA
-680mV    -6.532mA   -5.396mA   -8.906mA
-590mV    -3.404mA   -3.019mA   -4.694mA
-500mV    -1.195mA   -1.287mA   -1.627mA
-410mV    -168.8uA   -312.8uA   -198.9uA
-230mV    -283.8nA   -2.491uA   -119.1nA
5.5V      0A         0A         0A
[POWER_clamp]
|Voltage   I(typ)   I(min)   I(max)
-2.75V    3.023A     1.788A     4.744A
-1.07V    106mA      73.03mA    167.9mA
-980mV    38.14mA    32.4mA     52.11mA
-890mV    12.98mA    13.13mA    16.04mA
-800mV    6.499mA    5.855mA    8.73mA
-710mV    4.048mA    3.412mA    5.557mA
-620mV    2.244mA    2.008mA    3.067mA
-530mV    971.7uA    1.01mA     1.289mA
-440mV    275uA      386uA      329.3uA
-260mV    2.098uA    12.18uA    1.171uA
5.5V      0A         0A         0A
[Ramp]
| variable   typ   min   max
dV/dt_r  1.0956/0.3199n   0.8031/1.2040n   1.3162/0.1758n
dV/dt_f  1.1010/0.4781n   0.7315/1.5701n   1.3269/0.2416n
R_load = 80.0000
[Rising Waveform]
R_fixture= 80.0000
V_fixture= 0.0
V_fixture_min= 0.0
V_fixture_max= 0.0
|time   V(typ)   V(min)   V(max)
0s        19.3nV     328nV      57.04nV
638.9ps   -2.931mV   -2.853mV   44.08mV
837.7ps   -7.176mV   -1.619mV   1.571V
959.5ps   32.12mV    -994.3uV   1.952V
1.35ns    1.423V     -2.916mV   2.115V
1.632ns   1.642V     56.76mV    2.133V
1.979ns   1.694V     686.3mV    2.143V
3.294ns   1.74V      1.097V     2.16V
11.24ns   1.796V     1.239V     2.185V
100ns     1.826V     1.339V     2.194V
[Rising Waveform]
R_fixture= 80.0000
V_fixture= 2.5000
V_fixture_min= 2.2500
V_fixture_max= 2.7500
|time   V(typ)   V(min)   V(max)
0s        665.3mV    1.028V     538.5mV
464.7ps   693.2mV    1.057V     614.2mV
566.1ps   722.5mV    1.078V     1.659V
638.6ps   759.6mV    1.099V     2.043V
811.2ps   1.792V     1.147V     2.687V
1.08ns    2.423V     1.255V     2.736V
1.244ns   2.475V     1.763V     2.743V
1.686ns   2.495V     2.195V     2.747V
2.525ns   2.499V     2.248V     2.749V
100ns     2.5V       2.25V      2.75V
[Falling Waveform]
R_fixture= 80.0000
V_fixture= 0.0
V_fixture_min= 0.0
V_fixture_max= 0.0
|time   V(typ)   V(min)   V(max)
0s        1.824V     1.341V     2.193V
541.9ps   1.825V     1.341V     2.177V
701.6ps   1.822V     1.343V     400.7mV
779ps     1.806V     1.344V     127mV
1.01ns    272.5mV    1.336V     16.33mV
1.206ns   27.56mV    1.332V     7.57mV
1.294ns   16.39mV    1.265V     5.993mV
1.64ns    5.42mV     106.2mV    3.179mV
2.262ns   2.034mV    5.642mV    1.465mV
100ns     75.28nV    1.146uV    -104.9nV
[Falling Waveform]
R_fixture= 80.0000
V_fixture= 2.5000
V_fixture_min= 2.2500
V_fixture_max= 2.7500
|time   V(typ)   V(min)   V(max)
0s        2.5V       2.25V      2.75V
616.2ps   2.501V     2.249V     2.751V
817.5ps   2.538V     2.25V      1.397V
938.2ps   2.473V     2.251V     923.3mV
1.026ns   2.094V     2.251V     768.9mV
1.435ns   1.096V     2.28V      603.8mV
2.156ns   781.7mV    1.524V     572mV
4.616ns   705.2mV    1.167V     548.2mV
11.01ns   673.3mV    1.074V     538.8mV
100ns     664.9mV    1.031V     538.5mV
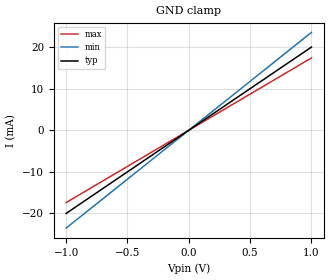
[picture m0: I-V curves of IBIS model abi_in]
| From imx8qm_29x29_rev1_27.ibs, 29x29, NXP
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[Model] abi_in
Model_type  Input
Vinl=0.4
Vinh=0.6
| variable   typ   min   max
C_comp   0.0pF   0.0pF   0.0pF
[Temperature Range]   20   20   20
[Voltage range]   1.0   1.0   1.0
[GND Clamp]
|   Voltage   I(typ)   I(min)   I(max)
-1V       -20mA      -23.53mA   -17.39mA
0V        0A         0A         0A
1V        20mA       23.53mA    17.39mA
[Algorithmic Model]
Executable Windows_VisualStudio10.0.30319_32 ABICDR_Rx2_x86.dll abi_g3_rx.ami
Executable Windows_VisualStudio10.0.30319_64 ABICDR_Rx2_x64.dll abi_g3_rx.ami
Executable Linux_gcc4.1.2_64   ABICDR_Rx2_rh64.dll  abi_g3_rx.ami
[End Algorithmic Model]
| End [Model] abi_in
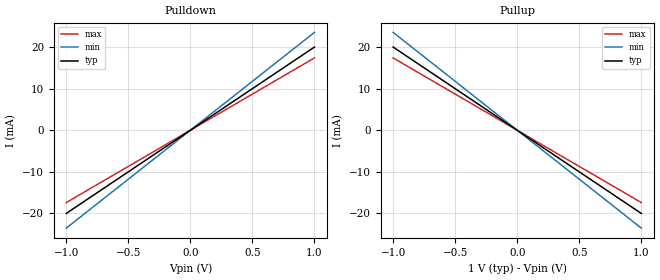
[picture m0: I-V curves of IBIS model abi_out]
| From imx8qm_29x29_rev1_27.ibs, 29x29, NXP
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[Model] abi_out
Model_type  Output
Polarity Non-Inverting
Vmeas =   0.5
| variable   typ   min   max
C_comp   0.0pF   0.0pF   0.0pF
[Temperature Range]   20   20   20
[Voltage range]   1.0   1.0   1.0
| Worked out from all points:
|   slope of the pulldown table from 0 to 0.15 V, typ, clamps not added: 50 ohm
|   slope of the pullup table from 0 to 0.15 V, typ, clamps not added: 50 ohm
[Pulldown]
|   Voltage   I(typ)   I(min)   I(max)
|   100 Ohm   85 Ohm   115 Ohm
-1V       -20mA      -23.53mA   -17.39mA
0V        0A         0A         0A
1V        20mA       23.53mA    17.39mA
[Pullup]
|   Voltage   I(typ)   I(min)   I(max)
-1V       20mA       23.53mA    17.39mA
0V        0A         0A         0A
1V        -20mA      -23.53mA   -17.39mA
[Ramp]
| variable   typ   min   max
dV/dt_r   1.00/0.05E-09   1.00/0.05E-09   1.00/0.05E-09
dV/dt_f   1.00/0.05E-09   1.00/0.05E-09   1.00/0.05E-09
R_load = 50
[Algorithmic Model]
Executable Windows_VisualStudio10.0.30319_32 ABICDR_Tx_x86.dll abi_g3_tx.ami
Executable Windows_VisualStudio10.0.30319_64 ABICDR_Tx_x64.dll abi_g3_tx.ami
Executable Linux_gcc4.1.2_64   ABICDR_Tx_rh64.dll  abi_g3_tx.ami
[End Algorithmic Model]
| End [Model] abi_out
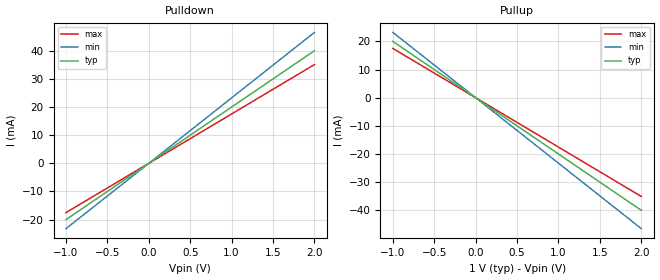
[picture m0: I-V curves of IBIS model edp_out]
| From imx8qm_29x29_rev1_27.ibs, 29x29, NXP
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[Model] edp_out
Model_type  Output
Polarity Non-Inverting
Vmeas =   0.2
| variable   typ   min   max
C_comp   1.125pF   1.012pF   1.250pF
[Temperature Range]   27   -40   125
[Voltage range]   1   1   1
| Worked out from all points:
|   slope of the pulldown table from 0 to 0.15 V, typ, clamps not added: 50 ohm
|   slope of the pullup table from 0 to 0.15 V, typ, clamps not added: 50 ohm
[Pulldown]
|  Voltage   I(typ)   I(min)   I(max)
-1V       -20mA      -23.2mA    -17.5mA
0V        0A         0A         0A
2V        40mA       46.51mA    35.08mA
[Pullup]
|  Voltage   I(typ)   I(min)   I(max)
-1V       20mA       23.2mA     17.5mA
0V        0A         0A         0A
2V        -40mA      -46.51mA   -35.08mA
[Ramp]
| variable   typ   min   max
dV/dt_r   0.624/0.131E-09   0.624/0.131E-09   0.624/0.131E-09
dV/dt_f   0.624/0.131E-09   0.624/0.131E-09   0.624/0.131E-09
R_load = 50
[Algorithmic Model]
Executable Windows_VisualStudio7.1.3088_32 tx_win32_rev1.dll edp_tx_rev1.ami
Executable Windows_VisualStudio10.0.30319_64 tx_win64_rev1.dll edp_tx_rev1.ami
Executable Linux_gcc4.1.2_64 tx_rev1.so edp_tx_rev1.ami
[End Algorithmic Model]
| End [Model] edp_out
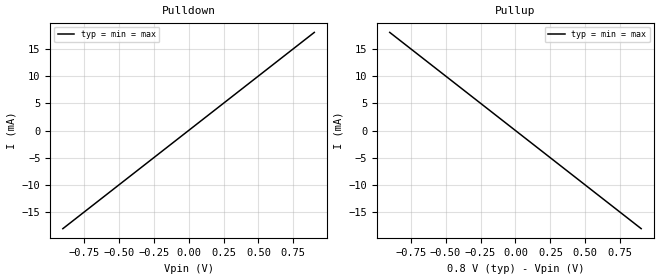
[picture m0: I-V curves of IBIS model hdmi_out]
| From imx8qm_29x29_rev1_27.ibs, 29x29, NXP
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[Model] hdmi_out
Model_type  Output
Polarity Non-Inverting
Vmeas =0
| variable   typ min max
C_comp   1pF 1pF 1pF
[Temperature Range]   25 125 125
[Voltage range]   0.8 0.8 0.8
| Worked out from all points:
|   slope of the pulldown table from 0 to 0.12 V, typ, clamps not added: 50 ohm
|   slope of the pullup table from 0 to 0.12 V, typ, clamps not added: 50 ohm
|**********************************************ss********************************
[Pullup]
|  Voltage   I(typ) I(min) I(max)
-900mV    18mA       18mA       18mA
0V        0A         0A         0A
900mV     -18mA      -18mA      -18mA
[Pulldown]
|  Voltage   I(typ) I(min) I(max)
-900mV    -18mA      -18mA      -18mA
0V        0A         0A         0A
900mV     18mA       18mA       18mA
[Ramp]
| variable   typ   min   max
dV/dt_r   0.12/3.465e-11   0.57/0.027E-09  0.63/0.027n
dV/dt_f   0.12/3.465e-11   0.57/0.027E-09 0.63/0.027n
R_load = 50
| End [Model] hdmi_out
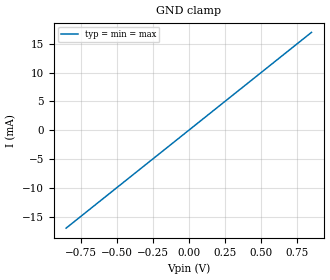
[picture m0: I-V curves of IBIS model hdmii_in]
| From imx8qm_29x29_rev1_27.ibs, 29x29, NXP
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[Model] hdmii_in
Model_type  Input
Vinl=0.1
Vinh=0.1
| variable   typ   min   max
C_comp   1.5pF   1.5pF   1.5pF
[Temperature Range]   27   -40   125
[Voltage range]   0.85   0.85   0.85
[GND Clamp]
|  Voltage   I(typ)   I(min)   I(max)
-850mV    -17mA      -17mA      -17mA
0V        0A         0A         0A
850mV     17mA       17mA       17mA
[Algorithmic Model]
Executable Windows_VisualStudio7.1.3088_32 rx_win32_rev1.dll hdmii2_rx_rev1.ami
Executable Windows_VisualStudio10.0.30319_64 rx_win64_rev1.dll hdmii2_rx_rev1.ami
Executable Linux_gcc4.1.2_64 rx_rev1.so hdmii2_rx_rev1.ami
[End Algorithmic Model]
| End [Model] hdmii_in
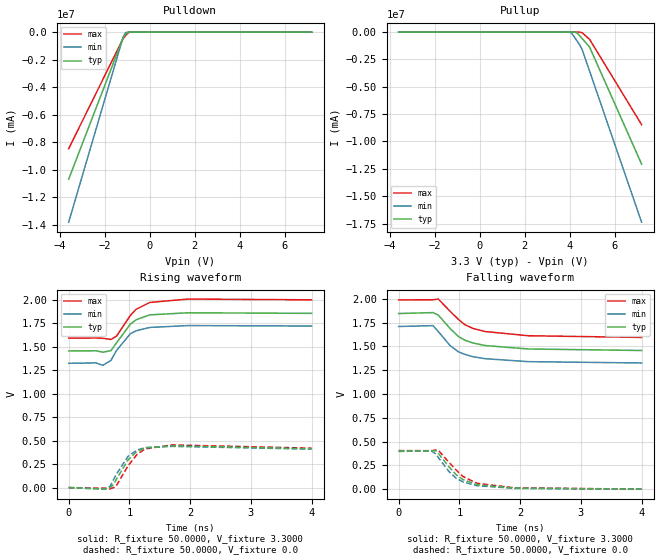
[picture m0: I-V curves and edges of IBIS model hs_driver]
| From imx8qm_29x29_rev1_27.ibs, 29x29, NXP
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[Model] hs_driver
|   Model hs_driver
| This model was characterised for following simulation conditions:
| Spice Models:
|  - Typ Condition
|   /project/usb2_ln28fdsoi/HS/s2ibis/HS-output_1/ln28fdsoi_lp2.combination ln28fdsoi_typ
|  - Min Condition
|   /project/usb2_ln28fdsoi/HS/s2ibis/HS-output_1/ln28fdsoi_lp2.combination ln28fdsoi_wcs
|  - Max Condition
|   /project/usb2_ln28fdsoi/HS/s2ibis/HS-output_1/ln28fdsoi_lp2.combination ln28fdsoi_bcs
Model_type Output
Polarity   Non-Inverting
C_comp   2.8431pF   2.6338pF   3.0727pF
[Temperature Range]   27.0000   -40.0000   0.1050k
[Voltage Range]   3.3000V   3.0000V   3.6000V
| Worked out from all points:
|   slope of the pulldown table from 0 to 0.495 V, typ, clamps not added: 39.2 ohm
|   slope of the pullup table from 0 to 0.495 V, typ, clamps not added: 17.7 ohm
|   rising waveform, R_fixture 50.0000, V_fixture 3.3000: 20-80 % time 297ps typ, 284ps min, 314ps max; typ from 1.45 V to 1.85 V
|   rising waveform, R_fixture 50.0000, V_fixture 0.0: 20-80 % time 243ps typ, 233ps min, 256ps max; typ from 0 V to 0.413 V
|   falling waveform, R_fixture 50.0000, V_fixture 3.3000: 20-80 % time 496ps typ, 471ps min, 519ps max; typ from 1.84 V to 1.46 V
|   falling waveform, R_fixture 50.0000, V_fixture 0.0: 20-80 % time 401ps typ, 378ps min, 432ps max; typ from 0.401 V to 0.002 V
[Pulldown]
|Voltage   I(typ)   I(min)   I(max)
-3.6V     -10.68kA   -13.8kA    -8.465kA
-1.18V    -414.1A    -362.8A    -466.3A
-1.07V    -158.9A    -39.09A    -263.8A
-960mV    -4.472A    -194.9mA   -61.23A
-850mV    -90.69mA   -24.66mA   -2.125A
-740mV    -21.84mA   -20.06mA   -96.29mA
7.2V      3.427mA    3.802mA    3.129mA
[Pullup]
|Voltage   I(typ)   I(min)   I(max)
-3.6V     3.158mA    3.199mA    3.129mA
4.01V     -38.53mA   -2.024A    -29.35mA
4.12V     -64.03mA   -183.6A    -32.74mA
4.23V     -1.443A    -512.1A    -39.59mA
4.34V     -89.37A    -840.6A    -115.2mA
4.45V     -344.6A    -1.17kA    -2.144A
4.56V     -599.7A    -1.616kA   -61.25A
4.67V     -854.9A    -2.272kA   -263.8A
4.89V     -1.383kA   -3.587kA   -668.9A
7.2V      -12.07kA   -17.38kA   -8.465kA
[Ramp]
| variable   typ   min   max
dV/dt_r  0.2477/0.2433n   0.2451/0.2333n   0.2516/0.2564n
dV/dt_f  0.2327/0.4961n   0.2300/0.4710n   0.2359/0.5185n
R_load = 50.0000
[Rising Waveform]
R_fixture= 50.0000
V_fixture= 3.3000
V_fixture_min= 3.0000
V_fixture_max= 3.6000
|time   V(typ)   V(min)   V(max)
0s        1.453V     1.322V     1.589V
450.2ps   1.455V     1.326V     1.591V
563.6ps   1.44V      1.3V       1.588V
695.4ps   1.456V     1.352V     1.575V
788.7ps   1.54V      1.459V     1.612V
1.015ns   1.738V     1.636V     1.831V
1.112ns   1.785V     1.668V     1.897V
1.335ns   1.837V     1.703V     1.969V
1.963ns   1.859V     1.723V     2.005V
4ns       1.853V     1.718V     1.997V
[Rising Waveform]
R_fixture= 50.0000
V_fixture= 0.0
V_fixture_min= 0.0
V_fixture_max= 0.0
|time   V(typ)   V(min)   V(max)
0s        76.82nV    2.186nV    5.833uV
590.9ps   -17.02mV   -16.81mV   -6.256mV
682ps     -587.1uV   13.82mV    -13.63mV
741.7ps   36.23mV    87.27mV    348.9uV
784.4ps   86.28mV    140.7mV    18.75mV
976.4ps   293.2mV    330.9mV    230.7mV
1.121ns   382.7mV    397.8mV    349.5mV
1.256ns   421.7mV    425.2mV    410.7mV
1.7ns     443.4mV    438.1mV    453.7mV
4ns       412.9mV    408.5mV    419.3mV
[Falling Waveform]
R_fixture= 50.0000
V_fixture= 3.3000
V_fixture_min= 3.0000
V_fixture_max= 3.6000
|time   V(typ)   V(min)   V(max)
0s        1.845V     1.709V     1.988V
564.8ps   1.855V     1.718V     1.99V
652.3ps   1.829V     1.656V     1.997V
844.8ps   1.689V     1.51V      1.87V
980.9ps   1.605V     1.444V     1.785V
1.09ns    1.565V     1.416V     1.728V
1.222ns   1.536V     1.392V     1.689V
1.424ns   1.509V     1.371V     1.656V
2.133ns   1.473V     1.34V      1.612V
4ns       1.457V     1.326V     1.594V
[Falling Waveform]
R_fixture= 50.0000
V_fixture= 0.0
V_fixture_min= 0.0
V_fixture_max= 0.0
|time   V(typ)   V(min)   V(max)
0s        401mV      396.8mV    406.1mV
533.8ps   403.4mV    405.6mV    405.2mV
610.1ps   404.1mV    370.3mV    412mV
652.4ps   376.4mV    333.3mV    409.6mV
833.6ps   232.1mV    181.4mV    279.2mV
948.5ps   151.6mV    114.7mV    200.6mV
1.058ns   102mV      77.87mV    134.2mV
1.29ns    48.54mV    37.4mV     63.03mV
1.913ns   11.95mV    9.65mV     14.73mV
4ns       1.551mV    1.236mV    1.897mV
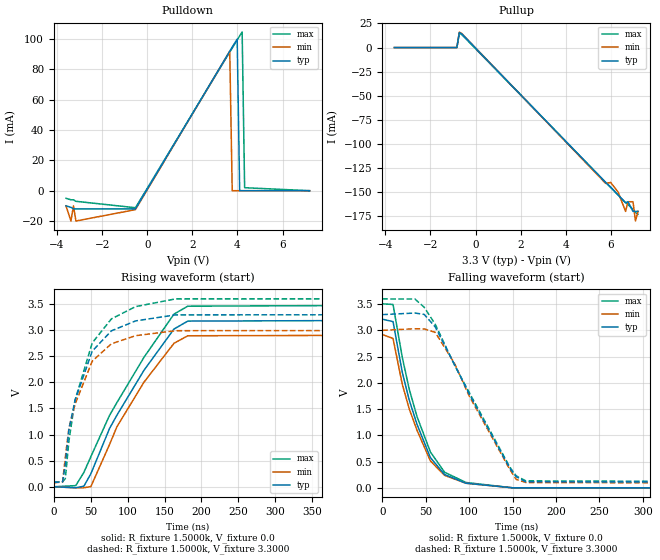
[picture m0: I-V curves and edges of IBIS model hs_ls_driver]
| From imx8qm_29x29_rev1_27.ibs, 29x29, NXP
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[Model] hs_ls_driver
|   Model hs_ls_driver
| This model was characterised for following simulation conditions:
| Spice Models:
|  - Typ Condition
|   /project/usb2_ln28fdsoi/HS/s2ibis/LS/ln28fdsoi_lp2.combination ln28fdsoi_typ
|  - Min Condition
|   /project/usb2_ln28fdsoi/HS/s2ibis/LS/ln28fdsoi_lp2.combination ln28fdsoi_wcs
|  - Max Condition
|   /project/usb2_ln28fdsoi/HS/s2ibis/LS/ln28fdsoi_lp2.combination ln28fdsoi_bcs
Model_type Output
Polarity   Non-Inverting
Enable   Active-Low
C_comp   2.8431pF   2.6338pF   3.0727pF
[Temperature Range]   27.0000   -40.0000   0.1050k
[Voltage Range]   3.3000V   3.0000V   3.6000V
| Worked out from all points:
|   slope of the pulldown table from 0 to 0.495 V, typ, clamps not added: 39.2 ohm
|   slope of the pullup table from 0 to 0.495 V, typ, clamps not added: 40.4 ohm
|   rising waveform, R_fixture 1.5000k, V_fixture 0.0: 20-80 % time 75.7ns typ, 68.8ns min, 83ns max; typ from 0 V to 3.21 V
|   rising waveform, R_fixture 1.5000k, V_fixture 3.3000: 20-80 % time 37.5ns typ, 36.2ns min, 38.5ns max; typ from 0.084 V to 3.3 V
|   falling waveform, R_fixture 1.5000k, V_fixture 0.0: 20-80 % time 34.4ns typ, 34.7ns min, 35.1ns max; typ from 3.21 V to 0 V
|   falling waveform, R_fixture 1.5000k, V_fixture 3.3000: 20-80 % time 59.6ns typ, 54.4ns min, 65.2ns max; typ from 3.3 V to 0.084 V
[Pulldown]
|Voltage   I(typ)   I(min)   I(max)
-3.6V     -10mA      -10mA      -5mA
-3.38V    -11mA      -20mA      -6mA
-3.27V    -12mA      -10mA      -6mA
-3.16V    -12mA      -20mA      -7mA
-520mV    -11.99mA   -12.49mA   -11.23mA
3.66V     92.06mA    91.98mA    91.46mA
3.77V     94.77mA    0A         94.14mA
3.99V     99.96mA    0A         99.47mA
4.1V      0A         0A         102.1mA
4.21V     0A         0A         104.7mA
4.32V     0A         0A         1.979mA
7.2V      0A         0A         0A
[Pullup]
|Voltage   I(typ)   I(min)   I(max)
-3.6V     0A         0A         0A
-830mV    0A         0A         0A
-720mV    15.57mA    16.12mA    14.85mA
-610mV    14.08mA    14.52mA    13.43mA
5.77V     -140mA     -141mA     -140mA
5.99V     -145mA     -140mA     -145mA
6.32V     -153mA     -150mA     -153mA
6.65V     -161mA     -170mA     -161mA
6.76V     -160mA     -160mA     -163mA
6.98V     -170mA     -160mA     -168mA
7.09V     -170mA     -180mA     -171mA
7.2V      -170mA     -170mA     -173mA
[Ramp]
| variable   typ   min   max
dV/dt_r  1.9280/75.7638n   1.7526/68.8233n   2.1033/83.0284n
dV/dt_f  1.9297/59.6250n   1.7541/54.3401n   2.1049/65.1937n
R_load = 1.5000k
[Rising Waveform]
R_fixture= 1.5000k
V_fixture= 0.0
V_fixture_min= 0.0
V_fixture_max= 0.0
|time   V(typ)   V(min)   V(max)
0s        128.1nV    3.393nV    9.919uV
29.7ns    -18.44mV   -20.85mV   22.05mV
40.71ns   10.55mV    -18.98mV   274.9mV
50.24ns   250.9mV    3.916mV    579.2mV
75.53ns   1.118V     811.8mV    1.369V
85.53ns   1.372V     1.151V     1.614V
122.1ns   2.231V     2.003V     2.479V
162.8ns   3.022V     2.749V     3.308V
181.5ns   3.174V     2.893V     3.46V
1us       3.213V     2.921V     3.506V
[Rising Waveform]
R_fixture= 1.5000k
V_fixture= 3.3000
V_fixture_min= 3.0000
V_fixture_max= 3.6000
|time   V(typ)   V(min)   V(max)
0s        83.84mV    76.43mV    91.8mV
11.85ns   92.69mV    90.75mV    97.27mV
15.54ns   421.1mV    560.2mV    154mV
20.46ns   1.1V       1.125V     876.3mV
28.74ns   1.657V     1.58V      1.658V
52.05ns   2.599V     2.407V     2.757V
78.04ns   2.988V     2.74V      3.217V
110.9ns   3.178V     2.895V     3.452V
164.8ns   3.293V     2.99V      3.599V
1us       3.3V       3V         3.6V
[Falling Waveform]
R_fixture= 1.5000k
V_fixture= 0.0
V_fixture_min= 0.0
V_fixture_max= 0.0
|time   V(typ)   V(min)   V(max)
0s        3.214V     2.921V     3.506V
12.47ns   3.166V     2.846V     3.493V
23.07ns   2.203V     1.975V     2.487V
31.16ns   1.669V     1.502V     1.875V
40.09ns   1.208V     1.095V     1.356V
55.46ns   576.2mV    513.6mV    683.7mV
71.73ns   254.2mV    238mV      298.2mV
96.35ns   87.91mV    87.61mV    102.5mV
149.9ns   1.168mV    1.138mV    1.128mV
1us       4.48uV     4.862uV    13.14uV
[Falling Waveform]
R_fixture= 1.5000k
V_fixture= 3.3000
V_fixture_min= 3.0000
V_fixture_max= 3.6000
|time   V(typ)   V(min)   V(max)
0s        3.3V       3V         3.6V
37.74ns   3.33V      3.031V     3.596V
48.3ns    3.304V     3.027V     3.441V
60.94ns   3.068V     2.964V     3.119V
83.16ns   2.351V     2.374V     2.341V
100.3ns   1.781V     1.744V     1.812V
147ns     372.1mV    347mV      392.9mV
154.2ns   212.9mV    161.9mV    227.9mV
165.4ns   115.9mV    101mV      132.8mV
1us       83.84mV    76.43mV    91.8mV
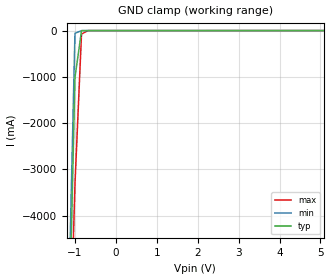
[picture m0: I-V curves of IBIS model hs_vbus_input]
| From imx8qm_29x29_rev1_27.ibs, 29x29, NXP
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[Model] hs_vbus_input
|   Model hs_vbus_input
| This model was characterised for following simulation conditions:
| Spice Models:
|  - Typ Condition
|   /project/usb2_ln28fdsoi/HS/s2ibis/Vbus_input/ln28fdsoi_lp2.combination ln28fdsoi_typ
|  - Min Condition
|   /project/usb2_ln28fdsoi/HS/s2ibis/Vbus_input/ln28fdsoi_lp2.combination ln28fdsoi_wcs
|  - Max Condition
|   /project/usb2_ln28fdsoi/HS/s2ibis/Vbus_input/ln28fdsoi_lp2.combination ln28fdsoi_bcs
Model_type Input
C_comp   2.8431pF   2.6338pF   3.0727pF
[Temperature Range]   27.0000   -40.0000   0.1050k
[Voltage Range]   5.0000V   4.7500V   5.2500V
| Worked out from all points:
|   GND clamp passes 1 mA (typ) near -0.74 V on its own axis
[GND_clamp]
|Voltage   I(typ)   I(min)   I(max)
-5V       -303.7A    -388.2A    -244.1A
-1.16V    -7.204A    -6.126A    -8.234A
-1V       -1.018A    -59.05mA   -3.323A
-840mV    -2.453mA   -304.2uA   -75.78mA
-680mV    -144.5uA   -130.1uA   -801.5uA
5.08V     65.36uA    64.13uA    65.23uA
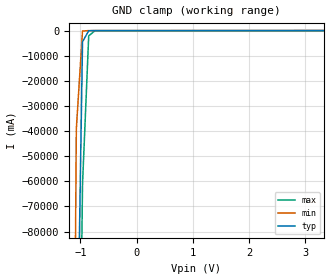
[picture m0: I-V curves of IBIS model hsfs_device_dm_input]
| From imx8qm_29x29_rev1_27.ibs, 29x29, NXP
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[Model] hsfs_device_dm_input
|   Model hsfs_device_dm_input
Model_type Input
Polarity   Non-Inverting
C_comp   2.8431pF   2.6338pF   3.0727pF
[Temperature Range]   27.0000   -40.0000   0.1050k
[Voltage Range]   3.3000V   3.0000V   3.6000V
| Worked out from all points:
|   GND clamp passes 1 mA (typ) near -0.46 V on its own axis
[GND_clamp]
|Voltage   I(typ)   I(min)   I(max)
-3.6V     -10.68kA   -13.8kA    -8.465kA
-1.18V    -414.1A    -362.8A    -466.3A
-1.07V    -158.9A    -39.07A    -263.8A
-960mV    -4.457A    -179.3mA   -61.22A
-850mV    -76.08mA   -9.518mA   -2.112A
-740mV    -7.874mA   -5.527mA   -83.65mA
3.33V     105.2nA    380.1nA    35.91nA
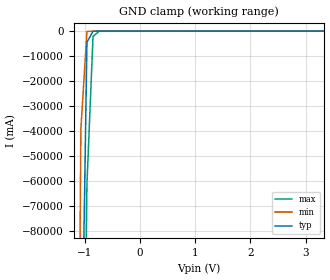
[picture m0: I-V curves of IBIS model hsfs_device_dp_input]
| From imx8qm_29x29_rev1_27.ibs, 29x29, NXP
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[Model] hsfs_device_dp_input
|   Model hsfs_device_dp_input
Model_type Input
Polarity   Non-Inverting
C_comp   2.8431pF   2.6338pF   3.0727pF
[Temperature Range]   27.0000   -40.0000   0.1050k
[Voltage Range]   3.3000V   3.0000V   3.6000V
[GND_clamp]
|Voltage   I(typ)   I(min)   I(max)
-3.6V     -10.68kA   -13.8kA    -8.465kA
-1.18V    -414.1A    -362.8A    -466.3A
-1.07V    -158.9A    -39.07A    -263.8A
-960mV    -4.46A     -182.4mA   -61.22A
-850mV    -79.36mA   -12.51mA   -2.115A
-740mV    -11.07mA   -8.434mA   -87.15mA
3.33V     23.88uA    256.7uA    -217.4uA
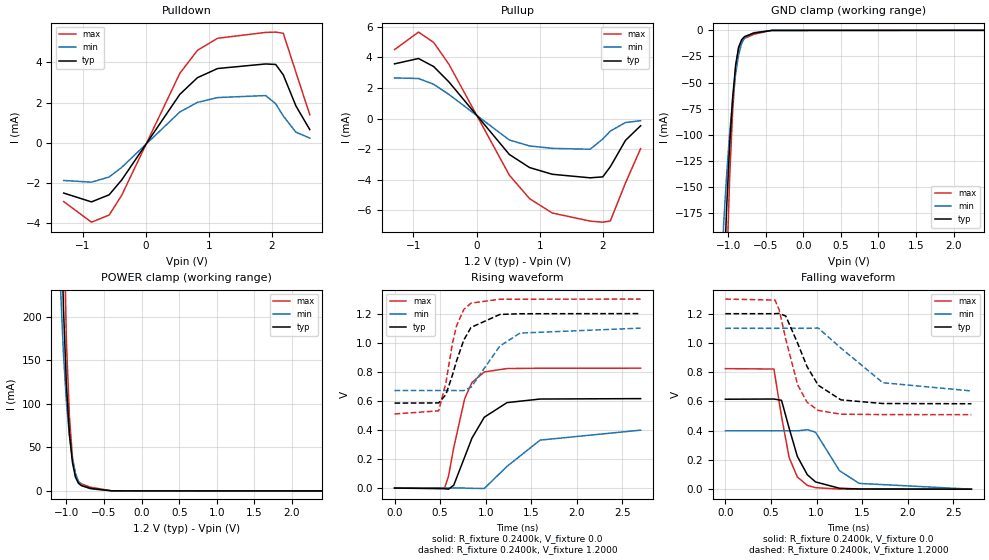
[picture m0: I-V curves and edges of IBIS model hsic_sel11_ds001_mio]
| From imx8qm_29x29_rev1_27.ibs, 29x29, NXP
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[Model] hsic_sel11_ds001_mio
|   Model hsic_sel11_ds001_mio
| This model was characterised for following simulation conditions:
| External (pad) voltage:
|   - Typ: 1.2V,   - Min: 1.1V,   - Max: 1.3V
| Library cells for typ/min/max conditions are connected as defined below:
|  pad - External Pad
|  ipp_do - Core Input
|  ipp_obe - Output Buffer Enable
|  ddr_sel0 - vddi
|  ddr_sel1 - vddi
|  esd_boost - ovdd
|  esd_trigger - ovss
|  ipp_dse0 - vddi
|  ipp_dse1 - ovss
|  ipp_dse2 - ovss
|  ipp_ind - NC
|  ovdd - ovdd
|  ovss - ovss
|  pd_calb[0] - ovss
|  pd_calb[1] - ovss
|  pd_calb[2] - vdd1p8
|  pd_calb[3] - ovss
|  pd_calb[4] - vdd1p8
|  pd_calb_buf[0] - NC
|  pd_calb_buf[1] - NC
|  pd_calb_buf[2] - NC
|  pd_calb_buf[3] - NC
|  pd_calb_buf[4] - NC
|  pd_m1_calb[0] - vdd1p8
|  pd_m1_calb[1] - vdd1p8
|  pd_m1_calb[2] - ovss
|  pd_m1_calb[3] - ovss
|  pd_m1_calb[4] - vdd1p8
|  pd_m1_calb_buf[0] - NC
|  pd_m1_calb_buf[1] - NC
|  pd_m1_calb_buf[2] - NC
|  pd_m1_calb_buf[3] - NC
|  pd_m1_calb_buf[4] - NC
|  pu_cal[0] - vdd1p8
|  pu_cal[1] - vdd1p8
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Model_type I/O
Polarity   Non-Inverting
Enable   Active-High
Vinl =   0.4700V
Vinh =   0.7300V
Vmeas =  0.6000V
Cref =   5.0000pF
Rref =   0.1200k
Vref =   0.6000V
C_comp   1.1786pF   1.0549pF   1.3266pF
|C_comp_pullup   0.5406pF   0.5887pF   0.5027pF
|C_comp_pulldown   0.6256pF   0.7255pF   0.5394pF
[Model Spec]
| variable   typ   min   max
Vinh   0.7300V   0.7000V   0.7900V
Vinl   0.4700V   0.4400V   0.5300V
S_overshoot_high   1.2000V   1.1400V   1.3200V
S_overshoot_low   0.0V   0.0V   0.0V
D_overshoot_high   1.5500V   1.4900V   1.6700V
D_overshoot_low   -0.3500V   -0.3500V   -0.3500V
D_overshoot_time   1.7140nS   1.7140nS   1.7140nS
Vmeas   0.6000V   0.5700V   0.6600V
Vref   0.6000V   0.5700V   0.6600V
Cref   5.0000pF   5.0000pF   5.0000pF
Rref   50.0000   50.0000   50.0000
[Receiver Thresholds]
Vth  =   0.6000V
Vinh_ac  =   0.2200V
Vinh_dc  =   0.1300V
Vinl_ac  =   -0.2200V
Vinl_dc  =   -0.1300V
Tslew_ac  =   0.4400nS
Vcross_high  =   0.7200V
Vcross_low  =   0.4800V
Vdiff_ac  =   0.4400V
Vdiff_dc  =   0.2600V
Tdiffslew_ac  =   0.2200nS
[Temperature Range]   25.0000   0.1050k   -20.0000
[Voltage Range]   1.2000V   1.1000V   1.3000V
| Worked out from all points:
|   slope of the pulldown table from 0 to 0.18 V, typ, clamps not added: 208 ohm
|   slope of the pullup table from 0 to 0.18 V, typ, clamps not added: 197 ohm
|   GND clamp passes 1 mA (typ) near -0.55 V on its own axis
|   POWER clamp passes 1 mA (typ) near -0.55 V on its own axis
|   rising waveform, R_fixture 0.2400k, V_fixture 0.0: 20-80 % time 272ps typ, 416ps min, 178ps max; typ from 0 V to 0.615 V
|   rising waveform, R_fixture 0.2400k, V_fixture 1.2000: 20-80 % time 208ps typ, 305ps min, 146ps max; typ from 0.584 V to 1.2 V
|   falling waveform, R_fixture 0.2400k, V_fixture 0.0: 20-80 % time 199ps typ, 284ps min, 144ps max; typ from 0.615 V to 0 V
|   falling waveform, R_fixture 0.2400k, V_fixture 1.2000: 20-80 % time 278ps typ, 424ps min, 201ps max; typ from 1.2 V to 0.584 V
[Pulldown]
|Voltage   I(typ)   I(min)   I(max)
-1.3V     -2.512mA   -1.884mA   -2.935mA
-860mV    -2.951mA   -1.969mA   -3.963mA
-580mV    -2.599mA   -1.71mA    -3.607mA
-380mV    -1.855mA   -1.229mA   -2.618mA
540mV     2.406mA    1.528mA    3.452mA
820mV     3.239mA    2.008mA    4.602mA
1.14V     3.695mA    2.247mA    5.203mA
1.9V      3.922mA    2.348mA    5.494mA
2.06V     3.896mA    1.939mA    5.51mA
2.18V     3.378mA    1.329mA    5.451mA
2.38V     1.833mA    521uA      3.509mA
2.6V      650uA      230uA      1.39mA
[Pullup]
|Voltage   I(typ)   I(min)   I(max)
-1.3V     3.57mA     2.65mA     4.5mA
-920mV    3.919mA    2.613mA    5.644mA
-680mV    3.393mA    2.234mA    4.97mA
-440mV    2.398mA    1.577mA    3.557mA
520mV     -2.349mA   -1.404mA   -3.701mA
840mV     -3.202mA   -1.791mA   -5.233mA
1.2V      -3.641mA   -1.949mA   -6.17mA
1.8V      -3.873mA   -2.007mA   -6.698mA
2V        -3.81mA    -1.339mA   -6.77mA
2.12V     -3.148mA   -820.6uA   -6.692mA
2.36V     -1.429mA   -261.3uA   -4.208mA
2.6V      -472uA     -144uA     -1.968mA
[GND_clamp]
|Voltage   I(typ)   I(min)   I(max)
-1.3V     -1.327A    -774.7mA   -2.13A
-1.06V    -249.5mA   -186.8mA   -362.1mA
-1.02V    -170.7mA   -138.9mA   -233.4mA
-980mV    -110.7mA   -99.55mA   -142.7mA
-940mV    -65mA      -67.2mA    -78.14mA
-900mV    -33.36mA   -41.59mA   -36.54mA
-860mV    -16.14mA   -23.43mA   -17.16mA
-820mV    -8.924mA   -12.66mA   -10.41mA
-780mV    -5.964mA   -7.199mA   -7.779mA
-660mV    -2.678mA   -2.269mA   -3.845mA
-420mV    -80.74uA   -142.6uA   -96.45uA
2.6V      0A         0A         0A
[POWER_clamp]
|Voltage   I(typ)   I(min)   I(max)
-1.3V     1.653A     1.004A     2.566A
-1.08V    346.4mA    236.5mA    551.1mA
-1.04V    210.8mA    157.7mA    320.5mA
-1V       121.1mA    101.5mA    171mA
-960mV    65.36mA    62.81mA    84.97mA
-920mV    32.57mA    36.77mA    38.73mA
-880mV    15.78mA    20.35mA    17.99mA
-840mV    8.717mA    11.1mA     10.75mA
-800mV    5.976mA    6.48mA     8.129mA
-680mV    2.921mA    2.467mA    4.216mA
-400mV    106.3uA    181.1uA    127.5uA
2.6V      0A         0A         0A
[Ramp]
| variable   typ   min   max
dV/dt_r  0.3691/0.2716n   0.2390/0.4155n   0.4947/0.1776n
dV/dt_f  0.3694/0.2779n   0.2569/0.4242n   0.4742/0.2015n
R_load = 0.2400k
[Rising Waveform]
R_fixture= 0.2400k
V_fixture= 0.0
V_fixture_min= 0.0
V_fixture_max= 0.0
|time   V(typ)   V(min)   V(max)
0s        41.97nV    2.145uV    826.3nV
549.8ps   -4.498mV   32.38uV    345.2uV
591.9ps   -7.58mV    53.86uV    80.36mV
649.5ps   19.52mV    60.9uV     277.4mV
769.6ps   213.6mV    -65.59uV   615.2mV
849.4ps   343.5mV    -2.072mV   726.1mV
984.9ps   487.4mV    -2.653mV   798.6mV
1.234ns   587.8mV    149mV      822.1mV
1.597ns   612.4mV    329.8mV    824.2mV
2.7ns     615.2mV    398.3mV    824.6mV
[Rising Waveform]
R_fixture= 0.2400k
V_fixture= 1.2000
V_fixture_min= 1.1000
V_fixture_max= 1.3000
|time   V(typ)   V(min)   V(max)
0s        584.4mV    670.9mV    509.8mV
483.6ps   585.6mV    670.9mV    531.1mV
562.8ps   642.4mV    670.9mV    720.8mV
634.7ps   776.2mV    671mV      993.4mV
679.9ps   873.3mV    670.6mV    1.115V
759.1ps   1.017V     670.4mV    1.228V
839.1ps   1.105V     693.3mV    1.272V
1.155ns   1.194V     976.3mV    1.299V
1.376ns   1.199V     1.066V     1.299V
2.7ns     1.2V       1.1V       1.3V
[Falling Waveform]
R_fixture= 0.2400k
V_fixture= 0.0
V_fixture_min= 0.0
V_fixture_max= 0.0
|time   V(typ)   V(min)   V(max)
0s        615.3mV    399.4mV    824.4mV
532.6ps   616.7mV    399.3mV    821.6mV
616.1ps   607.8mV    399.3mV    497.9mV
699.7ps   417.3mV    399.3mV    216.4mV
789.5ps   224.6mV    399.2mV    84.2mV
899.2ps   99.16mV    406.7mV    26.27mV
989ps     49.85mV    389.9mV    10.55mV
1.252ns   6.647mV    126.9mV    1.325mV
1.468ns   1.629mV    39.83mV    813.4uV
2.7ns     377.7uV    358uV      360uV
[Falling Waveform]
R_fixture= 0.2400k
V_fixture= 1.2000
V_fixture_min= 1.1000
V_fixture_max= 1.3000
|time   V(typ)   V(min)   V(max)
0s        1.2V       1.1V       1.3V
544.6ps   1.2V       1.1V       1.293V
590.2ps   1.202V     1.1V       1.227V
662.6ps   1.184V     1.1V       1.026V
792.8ps   998.2mV    1.1V       713.7mV
896.2ps   838.1mV    1.1V       594.7mV
1.019ns   710.8mV    1.102V     538.4mV
1.268ns   610.7mV    964.8mV    513mV
1.728ns   585.8mV    728mV      510.1mV
2.7ns     584.4mV    671.9mV    509.7mV
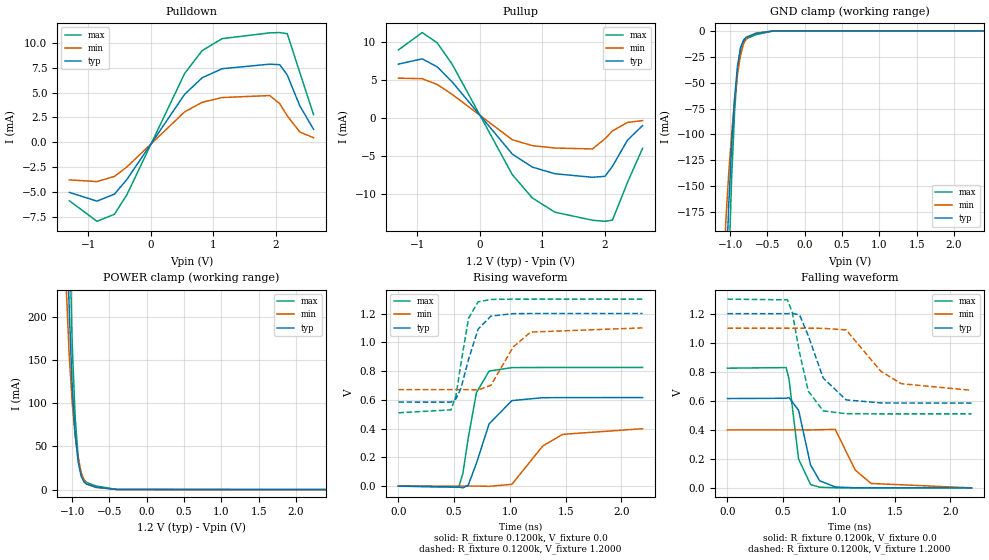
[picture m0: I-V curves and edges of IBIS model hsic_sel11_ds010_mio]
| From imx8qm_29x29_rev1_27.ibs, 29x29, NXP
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[Model] hsic_sel11_ds010_mio
|   Model hsic_sel11_ds010_mio
| This model was characterised for following simulation conditions:
| External (pad) voltage:
|   - Typ: 1.2V,   - Min: 1.1V,   - Max: 1.3V
| Library cells for typ/min/max conditions are connected as defined below:
|  pad - External Pad
|  ipp_do - Core Input
|  ipp_obe - Output Buffer Enable
|  ddr_sel0 - vddi
|  ddr_sel1 - vddi
|  esd_boost - ovdd
|  esd_trigger - ovss
|  ipp_dse0 - ovss
|  ipp_dse1 - vddi
|  ipp_dse2 - ovss
|  ipp_ind - NC
|  ovdd - ovdd
|  ovss - ovss
|  pd_calb[0] - ovss
|  pd_calb[1] - ovss
|  pd_calb[2] - vdd1p8
|  pd_calb[3] - ovss
|  pd_calb[4] - vdd1p8
|  pd_calb_buf[0] - NC
|  pd_calb_buf[1] - NC
|  pd_calb_buf[2] - NC
|  pd_calb_buf[3] - NC
|  pd_calb_buf[4] - NC
|  pd_m1_calb[0] - vdd1p8
|  pd_m1_calb[1] - vdd1p8
|  pd_m1_calb[2] - ovss
|  pd_m1_calb[3] - ovss
|  pd_m1_calb[4] - vdd1p8
|  pd_m1_calb_buf[0] - NC
|  pd_m1_calb_buf[1] - NC
|  pd_m1_calb_buf[2] - NC
|  pd_m1_calb_buf[3] - NC
|  pd_m1_calb_buf[4] - NC
|  pu_cal[0] - vdd1p8
|  pu_cal[1] - vdd1p8
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Model_type I/O
Polarity   Non-Inverting
Enable   Active-High
Vinl =   0.4700V
Vinh =   0.7300V
Vmeas =  0.6000V
Cref =   5.0000pF
Rref =   60.0000
Vref =   0.6000V
C_comp   1.1786pF   1.0549pF   1.3266pF
|C_comp_pullup   0.5406pF   0.5887pF   0.5025pF
|C_comp_pulldown   0.6256pF   0.7255pF   0.5397pF
[Model Spec]
| variable   typ   min   max
Vinh   0.7300V   0.7000V   0.7900V
Vinl   0.4700V   0.4400V   0.5300V
S_overshoot_high   1.2000V   1.1400V   1.3200V
S_overshoot_low   0.0V   0.0V   0.0V
D_overshoot_high   1.5500V   1.4900V   1.6700V
D_overshoot_low   -0.3500V   -0.3500V   -0.3500V
D_overshoot_time   1.7140nS   1.7140nS   1.7140nS
Vmeas   0.6000V   0.5700V   0.6600V
Vref   0.6000V   0.5700V   0.6600V
Cref   5.0000pF   5.0000pF   5.0000pF
Rref   50.0000   50.0000   50.0000
[Receiver Thresholds]
Vth  =   0.6000V
Vinh_ac  =   0.2200V
Vinh_dc  =   0.1300V
Vinl_ac  =   -0.2200V
Vinl_dc  =   -0.1300V
Tslew_ac  =   0.4400nS
Vcross_high  =   0.7200V
Vcross_low  =   0.4800V
Vdiff_ac  =   0.4400V
Vdiff_dc  =   0.2600V
Tdiffslew_ac  =   0.2200nS
[Temperature Range]   25.0000   0.1050k   -20.0000
[Voltage Range]   1.2000V   1.1000V   1.3000V
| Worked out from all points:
|   slope of the pulldown table from 0 to 0.18 V, typ, clamps not added: 104 ohm
|   slope of the pullup table from 0 to 0.18 V, typ, clamps not added: 98.4 ohm
|   GND clamp passes 1 mA (typ) near -0.55 V on its own axis
|   POWER clamp passes 1 mA (typ) near -0.55 V on its own axis
|   rising waveform, R_fixture 0.1200k, V_fixture 0.0: 20-80 % time 167ps typ, 269ps min, 109ps max; typ from 0 V to 0.616 V
|   rising waveform, R_fixture 0.1200k, V_fixture 1.2000: 20-80 % time 135ps typ, 199ps min, 95.7ps max; typ from 0.584 V to 1.2 V
|   falling waveform, R_fixture 0.1200k, V_fixture 0.0: 20-80 % time 115ps typ, 167ps min, 81.6ps max; typ from 0.615 V to 0 V
|   falling waveform, R_fixture 0.1200k, V_fixture 1.2000: 20-80 % time 181ps typ, 298ps min, 126ps max; typ from 1.2 V to 0.584 V
[Pulldown]
|Voltage   I(typ)   I(min)   I(max)
-1.3V     -5.024mA   -3.768mA   -5.868mA
-860mV    -5.902mA   -3.939mA   -7.925mA
-580mV    -5.198mA   -3.419mA   -7.213mA
-380mV    -3.709mA   -2.459mA   -5.236mA
540mV     4.814mA    3.056mA    6.904mA
820mV     6.479mA    4.018mA    9.206mA
1.14V     7.392mA    4.497mA    10.41mA
1.9V      7.848mA    4.697mA    10.99mA
2.06V     7.794mA    3.881mA    11.02mA
2.18V     6.76mA     2.661mA    10.91mA
2.38V     3.669mA    1.042mA    7.023mA
2.6V      1.31mA     460uA      2.78mA
[Pullup]
|Voltage   I(typ)   I(min)   I(max)
-1.3V     7.15mA     5.3mA      9.01mA
-920mV    7.842mA    5.228mA    11.3mA
-680mV    6.789mA    4.47mA     9.948mA
-440mV    4.799mA    3.155mA    7.117mA
520mV     -4.7mA     -2.807mA   -7.406mA
840mV     -6.405mA   -3.582mA   -10.47mA
1.2V      -7.282mA   -3.897mA   -12.34mA
1.8V      -7.747mA   -4.015mA   -13.4mA
2V        -7.621mA   -2.679mA   -13.54mA
2.12V     -6.297mA   -1.641mA   -13.39mA
2.36V     -2.857mA   -522.3uA   -8.414mA
2.6V      -944uA     -288uA     -3.932mA
[GND_clamp]
|Voltage   I(typ)   I(min)   I(max)
-1.3V     -1.327A    -774.7mA   -2.13A
-1.06V    -249.5mA   -186.8mA   -362.1mA
-1.02V    -170.7mA   -138.9mA   -233.4mA
-980mV    -110.7mA   -99.55mA   -142.7mA
-940mV    -65mA      -67.2mA    -78.14mA
-900mV    -33.36mA   -41.59mA   -36.54mA
-860mV    -16.14mA   -23.43mA   -17.16mA
-820mV    -8.924mA   -12.66mA   -10.41mA
-780mV    -5.964mA   -7.199mA   -7.779mA
-660mV    -2.678mA   -2.269mA   -3.845mA
-420mV    -80.74uA   -142.6uA   -96.45uA
2.6V      0A         0A         0A
[POWER_clamp]
|Voltage   I(typ)   I(min)   I(max)
-1.3V     1.653A     1.004A     2.566A
-1.08V    346.4mA    236.5mA    551.1mA
-1.04V    210.8mA    157.7mA    320.5mA
-1V       121.1mA    101.5mA    171mA
-960mV    65.36mA    62.81mA    84.97mA
-920mV    32.57mA    36.77mA    38.73mA
-880mV    15.78mA    20.35mA    17.99mA
-840mV    8.717mA    11.1mA     10.75mA
-800mV    5.976mA    6.48mA     8.129mA
-680mV    2.921mA    2.467mA    4.216mA
-400mV    106.3uA    181.1uA    127.5uA
2.6V      0A         0A         0A
[Ramp]
| variable   typ   min   max
dV/dt_r  0.3693/0.1674n   0.2394/0.2685n   0.4949/0.1090n
dV/dt_f  0.3695/0.1813n   0.2568/0.2982n   0.4743/0.1257n
R_load = 0.1200k
[Rising Waveform]
R_fixture= 0.1200k
V_fixture= 0.0
V_fixture_min= 0.0
V_fixture_max= 0.0
|time   V(typ)   V(min)   V(max)
0s        20.98nV    1.072uV    413nV
540.2ps   -5.919mV   11.96uV    -7.679mV
577.8ps   -12.17mV   39.01uV    85.98mV
626.3ps   6.631mV    -46.39nV   333.8mV
700ps     158.9mV    467.4uV    649.8mV
813.4ps   432.3mV    -1.613mV   799.6mV
1.018ns   594.6mV    12.69mV    824mV
1.295ns   614.6mV    278.9mV    824.7mV
1.473ns   615.4mV    359.8mV    824.8mV
2.19ns    615.5mV    399.1mV    824.9mV
[Rising Waveform]
R_fixture= 0.1200k
V_fixture= 1.2000
V_fixture_min= 1.1000
V_fixture_max= 1.3000
|time   V(typ)   V(min)   V(max)
0s        584.3mV    670.7mV    509.8mV
471.7ps   584mV      670.8mV    530mV
516.7ps   607.5mV    670.8mV    630.5mV
561ps     679.5mV    670.8mV    852.5mV
629.2ps   881.3mV    670.9mV    1.167V
715.3ps   1.092V     668.9mV    1.281V
829.7ps   1.182V     700.6mV    1.298V
1.03ns    1.199V     967.3mV    1.3V
1.186ns   1.2V       1.071V     1.3V
2.19ns    1.2V       1.1V       1.3V
[Falling Waveform]
R_fixture= 0.1200k
V_fixture= 0.0
V_fixture_min= 0.0
V_fixture_max= 0.0
|time   V(typ)   V(min)   V(max)
0s        615.4mV    399.4mV    824.5mV
526.9ps   617.1mV    399.4mV    828.5mV
552.3ps   622mV      399.3mV    751.2mV
638.5ps   534.6mV    399.5mV    198.3mV
746.3ps   157mV      399.1mV    22.77mV
827.5ps   49.34mV    400.7mV    4.82mV
967.7ps   6.513mV    402.7mV    762.4uV
1.146ns   743.3uV    123mV      532.7uV
1.289ns   411.2uV    30.54mV    481.6uV
2.19ns    232.9uV    222.6uV    241.2uV
[Falling Waveform]
R_fixture= 0.1200k
V_fixture= 1.2000
V_fixture_min= 1.1000
V_fixture_max= 1.3000
|time   V(typ)   V(min)   V(max)
0s        1.2V       1.1V       1.3V
538.9ps   1.2V       1.1V       1.295V
582.3ps   1.203V     1.1V       1.207V
647.8ps   1.19V      1.1V       928.7mV
725.6ps   1.048V     1.1V       666.4mV
858.8ps   757.1mV    1.099V     530.6mV
1.065ns   606.1mV    1.088V     510.7mV
1.376ns   585.3mV    803.7mV    509.7mV
1.559ns   584.3mV    717.6mV    509.6mV
2.19ns    584.1mV    671.9mV    509.5mV
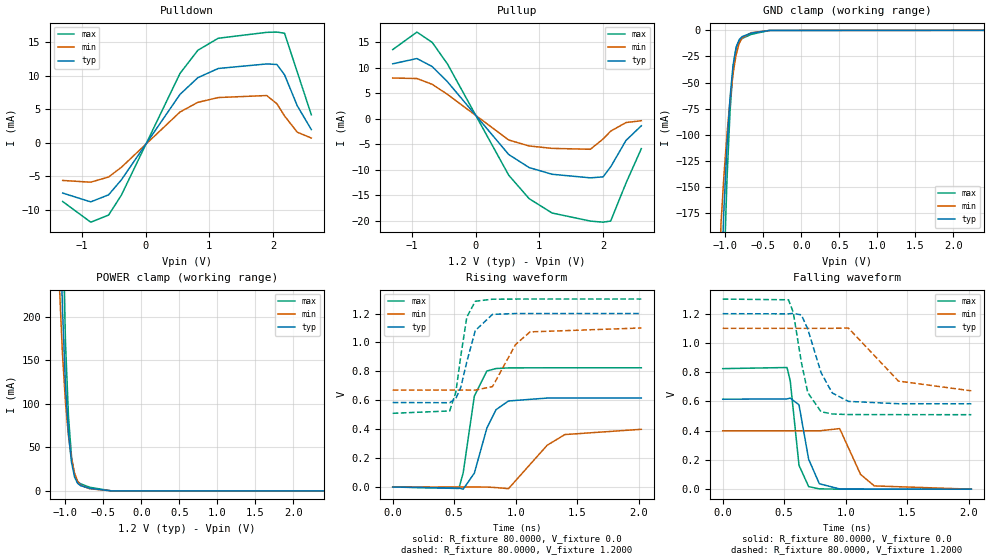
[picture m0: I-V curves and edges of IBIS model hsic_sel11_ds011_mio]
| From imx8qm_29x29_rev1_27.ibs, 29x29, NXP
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[Model] hsic_sel11_ds011_mio
|   Model hsic_sel11_ds011_mio
| This model was characterised for following simulation conditions:
| External (pad) voltage:
|   - Typ: 1.2V,   - Min: 1.1V,   - Max: 1.3V
| Library cells for typ/min/max conditions are connected as defined below:
|  pad - External Pad
|  ipp_do - Core Input
|  ipp_obe - Output Buffer Enable
|  ddr_sel0 - vddi
|  ddr_sel1 - vddi
|  esd_boost - ovdd
|  esd_trigger - ovss
|  ipp_dse0 - vddi
|  ipp_dse1 - vddi
|  ipp_dse2 - ovss
|  ipp_ind - NC
|  ovdd - ovdd
|  ovss - ovss
|  pd_calb[0] - ovss
|  pd_calb[1] - ovss
|  pd_calb[2] - vdd1p8
|  pd_calb[3] - ovss
|  pd_calb[4] - vdd1p8
|  pd_calb_buf[0] - NC
|  pd_calb_buf[1] - NC
|  pd_calb_buf[2] - NC
|  pd_calb_buf[3] - NC
|  pd_calb_buf[4] - NC
|  pd_m1_calb[0] - vdd1p8
|  pd_m1_calb[1] - vdd1p8
|  pd_m1_calb[2] - ovss
|  pd_m1_calb[3] - ovss
|  pd_m1_calb[4] - vdd1p8
|  pd_m1_calb_buf[0] - NC
|  pd_m1_calb_buf[1] - NC
|  pd_m1_calb_buf[2] - NC
|  pd_m1_calb_buf[3] - NC
|  pd_m1_calb_buf[4] - NC
|  pu_cal[0] - vdd1p8
|  pu_cal[1] - vdd1p8
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Model_type I/O
Polarity   Non-Inverting
Enable   Active-High
Vinl =   0.4700V
Vinh =   0.7300V
Vmeas =  0.6000V
Cref =   5.0000pF
Rref =   40.0000
Vref =   0.6000V
C_comp   1.1786pF   1.0549pF   1.3266pF
|C_comp_pullup   0.5410pF   0.5887pF   0.5025pF
|C_comp_pulldown   0.6252pF   0.7255pF   0.5397pF
[Model Spec]
| variable   typ   min   max
Vinh   0.7300V   0.7000V   0.7900V
Vinl   0.4700V   0.4400V   0.5300V
S_overshoot_high   1.2000V   1.1400V   1.3200V
S_overshoot_low   0.0V   0.0V   0.0V
D_overshoot_high   1.5500V   1.4900V   1.6700V
D_overshoot_low   -0.3500V   -0.3500V   -0.3500V
D_overshoot_time   1.7140nS   1.7140nS   1.7140nS
Vmeas   0.6000V   0.5700V   0.6600V
Vref   0.6000V   0.5700V   0.6600V
Cref   5.0000pF   5.0000pF   5.0000pF
Rref   50.0000   50.0000   50.0000
[Receiver Thresholds]
Vth  =   0.6000V
Vinh_ac  =   0.2200V
Vinh_dc  =   0.1300V
Vinl_ac  =   -0.2200V
Vinl_dc  =   -0.1300V
Tslew_ac  =   0.4400nS
Vcross_high  =   0.7200V
Vcross_low  =   0.4800V
Vdiff_ac  =   0.4400V
Vdiff_dc  =   0.2600V
Tdiffslew_ac  =   0.2200nS
[Temperature Range]   25.0000   0.1050k   -20.0000
[Voltage Range]   1.2000V   1.1000V   1.3000V
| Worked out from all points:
|   slope of the pulldown table from 0 to 0.18 V, typ, clamps not added: 69.2 ohm
|   slope of the pullup table from 0 to 0.18 V, typ, clamps not added: 65.6 ohm
|   GND clamp passes 1 mA (typ) near -0.55 V on its own axis
|   POWER clamp passes 1 mA (typ) near -0.55 V on its own axis
|   rising waveform, R_fixture 80.0000, V_fixture 0.0: 20-80 % time 135ps typ, 225ps min, 87.4ps max; typ from 0 V to 0.616 V
|   rising waveform, R_fixture 80.0000, V_fixture 1.2000: 20-80 % time 110ps typ, 162ps min, 78.6ps max; typ from 0.584 V to 1.2 V
|   falling waveform, R_fixture 80.0000, V_fixture 0.0: 20-80 % time 85.8ps typ, 127ps min, 60.7ps max; typ from 0.615 V to 0 V
|   falling waveform, R_fixture 80.0000, V_fixture 1.2000: 20-80 % time 150ps typ, 258ps min, 101ps max; typ from 1.2 V to 0.584 V
[Pulldown]
|Voltage   I(typ)   I(min)   I(max)
-1.3V     -7.536mA   -5.652mA   -8.802mA
-860mV    -8.853mA   -5.908mA   -11.89mA
-580mV    -7.796mA   -5.128mA   -10.82mA
-380mV    -5.563mA   -3.687mA   -7.852mA
540mV     7.219mA    4.583mA    10.35mA
820mV     9.716mA    6.026mA    13.81mA
1.14V     11.09mA    6.744mA    15.61mA
1.9V      11.77mA    7.045mA    16.49mA
2.06V     11.69mA    5.821mA    16.53mA
2.18V     10.14mA    3.991mA    16.36mA
2.38V     5.505mA    1.563mA    10.54mA
2.6V      1.96mA     690uA      4.17mA
[Pullup]
|Voltage   I(typ)   I(min)   I(max)
-1.3V     10.72mA    7.94mA     13.51mA
-920mV    11.76mA    7.84mA     16.94mA
-680mV    10.18mA    6.702mA    14.91mA
-440mV    7.194mA    4.731mA    10.67mA
520mV     -7.048mA   -4.21mA    -11.1mA
840mV     -9.606mA   -5.373mA   -15.7mA
1.2V      -10.92mA   -5.846mA   -18.51mA
1.8V      -11.62mA   -6.023mA   -20.09mA
2V        -11.43mA   -4.019mA   -20.31mA
2.12V     -9.451mA   -2.462mA   -20.08mA
2.36V     -4.288mA   -783.6uA   -12.63mA
2.6V      -1.417mA   -432uA     -5.903mA
[GND_clamp]
|Voltage   I(typ)   I(min)   I(max)
-1.3V     -1.327A    -774.7mA   -2.13A
-1.06V    -249.5mA   -186.8mA   -362.1mA
-1.02V    -170.7mA   -138.9mA   -233.4mA
-980mV    -110.7mA   -99.55mA   -142.7mA
-940mV    -65mA      -67.2mA    -78.14mA
-900mV    -33.36mA   -41.59mA   -36.54mA
-860mV    -16.14mA   -23.43mA   -17.16mA
-820mV    -8.924mA   -12.66mA   -10.41mA
-780mV    -5.964mA   -7.199mA   -7.779mA
-660mV    -2.678mA   -2.269mA   -3.845mA
-420mV    -80.74uA   -142.6uA   -96.45uA
2.6V      0A         0A         0A
[POWER_clamp]
|Voltage   I(typ)   I(min)   I(max)
-1.3V     1.653A     1.004A     2.566A
-1.08V    346.4mA    236.5mA    551.1mA
-1.04V    210.8mA    157.7mA    320.5mA
-1V       121.1mA    101.5mA    171mA
-960mV    65.36mA    62.81mA    84.97mA
-920mV    32.57mA    36.77mA    38.73mA
-880mV    15.78mA    20.35mA    17.99mA
-840mV    8.717mA    11.1mA     10.75mA
-800mV    5.976mA    6.48mA     8.129mA
-680mV    2.921mA    2.467mA    4.216mA
-400mV    106.3uA    181.1uA    127.5uA
2.6V      0A         0A         0A
[Ramp]
| variable   typ   min   max
dV/dt_r  0.3693/0.1354n   0.2395/0.2246n   0.4949/87.4169p
dV/dt_f  0.3695/0.1499n   0.2564/0.2582n   0.4743/0.1007n
R_load = 80.0000
[Rising Waveform]
R_fixture= 80.0000
V_fixture= 0.0
V_fixture_min= 0.0
V_fixture_max= 0.0
|time   V(typ)   V(min)   V(max)
0s        13.87nV    719nV      275.4nV
537.6ps   -7.245mV   6.385uV    -9.999mV
572.5ps   -14.84mV   43.1uV     97.2mV
663.5ps   96.39mV    152.7uV    629.6mV
764.9ps   407.1mV    -267.3uV   802.5mV
839.5ps   534.9mV    -3.859mV   819.6mV
940.5ps   595.1mV    -11.46mV   823.9mV
1.255ns   615.2mV    288.9mV    824.7mV
1.399ns   615.5mV    362.9mV    824.7mV
2.02ns    615.5mV    399.2mV    824.8mV
[Rising Waveform]
R_fixture= 80.0000
V_fixture= 1.2000
V_fixture_min= 1.1000
V_fixture_max= 1.3000
|time   V(typ)   V(min)   V(max)
0s        584.4mV    670.8mV    509.9mV
462.8ps   583.1mV    670.8mV    526.1mV
513.1ps   612.2mV    670.8mV    656.7mV
553.5ps   691mV      670.8mV    907.9mV
602.4ps   867.5mV    670.9mV    1.176V
671.3ps   1.083V     670.4mV    1.285V
810.9ps   1.194V     694.7mV    1.299V
998.2ps   1.2V       985.6mV    1.3V
1.116ns   1.2V       1.073V     1.3V
2.02ns    1.2V       1.1V       1.3V
[Falling Waveform]
R_fixture= 80.0000
V_fixture= 0.0
V_fixture_min= 0.0
V_fixture_max= 0.0
|time   V(typ)   V(min)   V(max)
0s        615.3mV    399.4mV    824.3mV
522.6ps   617mV      399.3mV    832mV
548.7ps   623.3mV    399.3mV    740.9mV
619.9ps   576.8mV    399.4mV    163.3mV
698.2ps   204.9mV    399.3mV    17.78mV
785.2ps   37.03mV    399mV      2.13mV
950.4ps   1.66mV     414.3mV    488uV
1.12ns    406.2uV    101.1mV    373.1uV
1.232ns   319.3uV    22.35mV    330.3uV
2.02ns    166.9uV    172.8uV    177.2uV
[Falling Waveform]
R_fixture= 80.0000
V_fixture= 1.2000
V_fixture_min= 1.1000
V_fixture_max= 1.3000
|time   V(typ)   V(min)   V(max)
0s        1.2V       1.1V       1.3V
534.6ps   1.199V     1.1V       1.295V
573.1ps   1.202V     1.1V       1.21V
639.1ps   1.192V     1.1V       867.8mV
691.2ps   1.095V     1.1V       660.4mV
798.7ps   797.7mV    1.1V       529.9mV
889.8ps   658.2mV    1.1V       514.3mV
1.021ns   600.4mV    1.102V     510.3mV
1.428ns   584.4mV    739.2mV    509.6mV
2.02ns    584.1mV    672.6mV    509.5mV
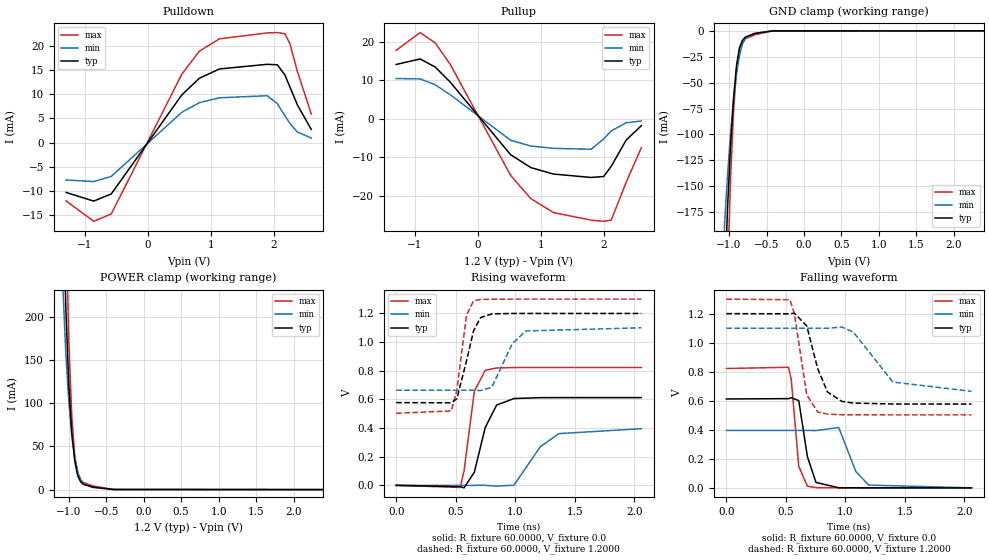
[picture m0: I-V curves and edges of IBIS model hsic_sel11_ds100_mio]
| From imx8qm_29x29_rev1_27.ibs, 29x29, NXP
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[Model] hsic_sel11_ds100_mio
|   Model hsic_sel11_ds100_mio
| This model was characterised for following simulation conditions:
| External (pad) voltage:
|   - Typ: 1.2V,   - Min: 1.1V,   - Max: 1.3V
| Library cells for typ/min/max conditions are connected as defined below:
|  pad - External Pad
|  ipp_do - Core Input
|  ipp_obe - Output Buffer Enable
|  ddr_sel0 - vddi
|  ddr_sel1 - vddi
|  esd_boost - ovdd
|  esd_trigger - ovss
|  ipp_dse0 - ovss
|  ipp_dse1 - ovss
|  ipp_dse2 - vddi
|  ipp_ind - NC
|  ovdd - ovdd
|  ovss - ovss
|  pd_calb[0] - ovss
|  pd_calb[1] - ovss
|  pd_calb[2] - vdd1p8
|  pd_calb[3] - ovss
|  pd_calb[4] - vdd1p8
|  pd_calb_buf[0] - NC
|  pd_calb_buf[1] - NC
|  pd_calb_buf[2] - NC
|  pd_calb_buf[3] - NC
|  pd_calb_buf[4] - NC
|  pd_m1_calb[0] - vdd1p8
|  pd_m1_calb[1] - vdd1p8
|  pd_m1_calb[2] - ovss
|  pd_m1_calb[3] - ovss
|  pd_m1_calb[4] - vdd1p8
|  pd_m1_calb_buf[0] - NC
|  pd_m1_calb_buf[1] - NC
|  pd_m1_calb_buf[2] - NC
|  pd_m1_calb_buf[3] - NC
|  pd_m1_calb_buf[4] - NC
|  pu_cal[0] - vdd1p8
|  pu_cal[1] - vdd1p8
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Model_type I/O
Polarity   Non-Inverting
Enable   Active-High
Vinl =   0.4700V
Vinh =   0.7300V
Vmeas =  0.6000V
Cref =   5.0000pF
Rref =   30.0000
Vref =   0.6000V
C_comp   1.1786pF   1.0549pF   1.3266pF
|C_comp_pullup   0.5410pF   0.5887pF   0.5027pF
|C_comp_pulldown   0.6252pF   0.7255pF   0.5394pF
[Model Spec]
| variable   typ   min   max
Vinh   0.7300V   0.7000V   0.7900V
Vinl   0.4700V   0.4400V   0.5300V
S_overshoot_high   1.2000V   1.1400V   1.3200V
S_overshoot_low   0.0V   0.0V   0.0V
D_overshoot_high   1.5500V   1.4900V   1.6700V
D_overshoot_low   -0.3500V   -0.3500V   -0.3500V
D_overshoot_time   1.7140nS   1.7140nS   1.7140nS
Vmeas   0.6000V   0.5700V   0.6600V
Vref   0.6000V   0.5700V   0.6600V
Cref   5.0000pF   5.0000pF   5.0000pF
Rref   50.0000   50.0000   50.0000
[Receiver Thresholds]
Vth  =   0.6000V
Vinh_ac  =   0.2200V
Vinh_dc  =   0.1300V
Vinl_ac  =   -0.2200V
Vinl_dc  =   -0.1300V
Tslew_ac  =   0.4400nS
Vcross_high  =   0.7200V
Vcross_low  =   0.4800V
Vdiff_ac  =   0.4400V
Vdiff_dc  =   0.2600V
Tdiffslew_ac  =   0.2200nS
[Temperature Range]   25.0000   0.1050k   -20.0000
[Voltage Range]   1.2000V   1.1000V   1.3000V
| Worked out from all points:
|   slope of the pulldown table from 0 to 0.18 V, typ, clamps not added: 51.1 ohm
|   slope of the pullup table from 0 to 0.18 V, typ, clamps not added: 49.5 ohm
|   GND clamp passes 1 mA (typ) near -0.55 V on its own axis
|   POWER clamp passes 1 mA (typ) near -0.55 V on its own axis
|   rising waveform, R_fixture 60.0000, V_fixture 0.0: 20-80 % time 120ps typ, 204ps min, 77ps max; typ from 0 V to 0.613 V
|   rising waveform, R_fixture 60.0000, V_fixture 1.2000: 20-80 % time 97.6ps typ, 141ps min, 70.9ps max; typ from 0.578 V to 1.2 V
|   falling waveform, R_fixture 60.0000, V_fixture 0.0: 20-80 % time 71.2ps typ, 108ps min, 50.3ps max; typ from 0.612 V to 0 V
|   falling waveform, R_fixture 60.0000, V_fixture 1.2000: 20-80 % time 131ps typ, 237ps min, 86ps max; typ from 1.2 V to 0.577 V
[Pulldown]
|Voltage   I(typ)   I(min)   I(max)
-1.3V     -10.3mA    -7.715mA   -12.04mA
-860mV    -12.08mA   -8.056mA   -16.25mA
-580mV    -10.59mA   -6.968mA   -14.71mA
540mV     9.815mA    6.241mA    14.08mA
820mV     13.27mA    8.236mA    18.86mA
1.14V     15.19mA    9.242mA    21.41mA
1.9V      16.15mA    9.664mA    22.63mA
2.06V     16.05mA    8.031mA    22.7mA
2.18V     13.98mA    5.572mA    22.46mA
2.26V     11.5mA     3.95mA     20.44mA
2.38V     7.76mA     2.165mA    14.66mA
2.6V      2.72mA     950uA      5.91mA
[Pullup]
|Voltage   I(typ)   I(min)   I(max)
-1.3V     14.16mA    10.5mA     17.82mA
-920mV    15.59mA    10.39mA    22.46mA
-680mV    13.5mA     8.886mA    19.78mA
-440mV    9.546mA    6.274mA    14.16mA
520mV     -9.324mA   -5.558mA   -14.7mA
840mV     -12.67mA   -7.068mA   -20.74mA
1.2V      -14.36mA   -7.677mA   -24.37mA
1.8V      -15.25mA   -7.903mA   -26.38mA
2V        -15mA      -5.23mA    -26.66mA
2.12V     -12.36mA   -3.158mA   -26.36mA
2.36V     -5.481mA   -1.007mA   -16.43mA
2.6V      -1.77mA    -562uA     -7.486mA
[GND_clamp]
|Voltage   I(typ)   I(min)   I(max)
-1.3V     -1.327A    -774.7mA   -2.13A
-1.06V    -249.5mA   -186.8mA   -362.1mA
-1.02V    -170.7mA   -138.9mA   -233.4mA
-980mV    -110.7mA   -99.55mA   -142.7mA
-940mV    -65mA      -67.2mA    -78.14mA
-900mV    -33.36mA   -41.59mA   -36.54mA
-860mV    -16.14mA   -23.43mA   -17.16mA
-820mV    -8.924mA   -12.66mA   -10.41mA
-780mV    -5.964mA   -7.199mA   -7.779mA
-660mV    -2.678mA   -2.269mA   -3.845mA
-420mV    -80.74uA   -142.6uA   -96.45uA
2.6V      0A         0A         0A
[POWER_clamp]
|Voltage   I(typ)   I(min)   I(max)
-1.3V     1.653A     1.004A     2.566A
-1.08V    346.4mA    236.5mA    551.1mA
-1.04V    210.8mA    157.7mA    320.5mA
-1V       121.1mA    101.5mA    171mA
-960mV    65.36mA    62.81mA    84.97mA
-920mV    32.57mA    36.77mA    38.73mA
-880mV    15.78mA    20.35mA    17.99mA
-840mV    8.717mA    11.1mA     10.75mA
-800mV    5.976mA    6.48mA     8.129mA
-680mV    2.921mA    2.467mA    4.216mA
-400mV    106.3uA    181.1uA    127.5uA
2.6V      0A         0A         0A
[Ramp]
| variable   typ   min   max
dV/dt_r  0.3676/0.1204n   0.2373/0.2047n   0.4936/76.9478p
dV/dt_f  0.3736/0.1313n   0.2610/0.2368n   0.4783/85.9502p
R_load = 60.0000
[Rising Waveform]
R_fixture= 60.0000
V_fixture= 0.0
V_fixture_min= 0.0
V_fixture_max= 0.0
|time   V(typ)   V(min)   V(max)
0s        10.31nV    531.8nV    203.9nV
537.8ps   -8.855mV   3.192uV    -14.55mV
570ps     -17.4mV    31.15uV    101.1mV
656.4ps   91.45mV    104.8uV    656.2mV
747.7ps   403mV      160uV      803.1mV
843.5ps   560.3mV    -4.887mV   819.6mV
989.4ps   606mV      1.073mV    822.4mV
1.211ns   612.3mV    269.7mV    822.6mV
1.367ns   612.6mV    361.3mV    822.6mV
2.06ns    612.6mV    395.5mV    822.6mV
[Rising Waveform]
R_fixture= 60.0000
V_fixture= 1.2000
V_fixture_min= 1.1000
V_fixture_max= 1.3000
|time   V(typ)   V(min)   V(max)
0s        577.7mV    664mV      503.2mV
462.7ps   576.4mV    664mV      519.5mV
509.4ps   604.5mV    664mV      663.5mV
591ps     869.4mV    663.9mV    1.19V
650.6ps   1.081V     664.2mV    1.288V
708.9ps   1.171V     661.5mV    1.298V
803.8ps   1.197V     685.3mV    1.299V
974.8ps   1.2V       988.9mV    1.3V
1.09ns    1.2V       1.078V     1.3V
2.06ns    1.2V       1.1V       1.3V
[Falling Waveform]
R_fixture= 60.0000
V_fixture= 0.0
V_fixture_min= 0.0
V_fixture_max= 0.0
|time   V(typ)   V(min)   V(max)
0s        612.3mV    395.6mV    822.1mV
523ps     614.6mV    395.5mV    830.7mV
546ps     621.2mV    395.5mV    741.9mV
608.6ps   600.9mV    395.6mV    147.9mV
681.1ps   215.3mV    395.6mV    11.65mV
753.4ps   37.36mV    395mV      1.814mV
944.7ps   910uV      415.4mV    388.7uV
1.088ns   375uV      113mV      283.9uV
1.196ns   265uV      19.45mV    248.2uV
2.06ns    118.7uV    122.3uV    125.6uV
[Falling Waveform]
R_fixture= 60.0000
V_fixture= 1.2000
V_fixture_min= 1.1000
V_fixture_max= 1.3000
|time   V(typ)   V(min)   V(max)
0s        1.2V       1.1V       1.3V
534.2ps   1.199V     1.1V       1.296V
571.7ps   1.203V     1.1V       1.201V
675.5ps   1.116V     1.1V       640.9mV
767.8ps   820.8mV    1.1V       522.8mV
850ps     660.5mV    1.099V     508mV
970.7ps   595.7mV    1.108V     503.8mV
1.067ns   584.1mV    1.073V     503.1mV
1.4ns     577.6mV    728.6mV    502.8mV
2.06ns    577.3mV    664.9mV    502.8mV
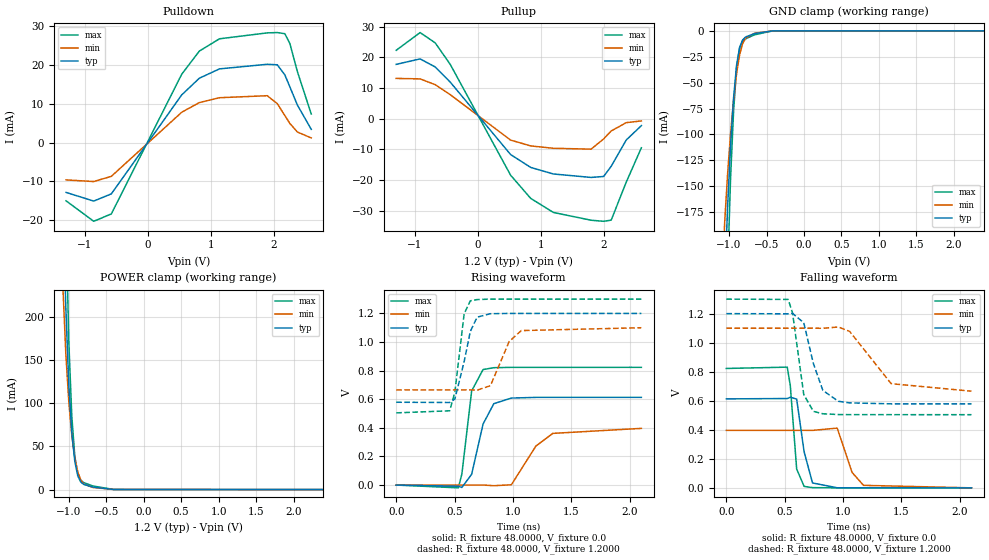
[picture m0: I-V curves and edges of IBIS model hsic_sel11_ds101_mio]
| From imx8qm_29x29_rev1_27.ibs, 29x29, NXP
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[Model] hsic_sel11_ds101_mio
|   Model hsic_sel11_ds101_mio
| This model was characterised for following simulation conditions:
| External (pad) voltage:
|   - Typ: 1.2V,   - Min: 1.1V,   - Max: 1.3V
| Library cells for typ/min/max conditions are connected as defined below:
|  pad - External Pad
|  ipp_do - Core Input
|  ipp_obe - Output Buffer Enable
|  ddr_sel0 - vddi
|  ddr_sel1 - vddi
|  esd_boost - ovdd
|  esd_trigger - ovss
|  ipp_dse0 - vddi
|  ipp_dse1 - ovss
|  ipp_dse2 - vddi
|  ipp_ind - NC
|  ovdd - ovdd
|  ovss - ovss
|  pd_calb[0] - ovss
|  pd_calb[1] - ovss
|  pd_calb[2] - vdd1p8
|  pd_calb[3] - ovss
|  pd_calb[4] - vdd1p8
|  pd_calb_buf[0] - NC
|  pd_calb_buf[1] - NC
|  pd_calb_buf[2] - NC
|  pd_calb_buf[3] - NC
|  pd_calb_buf[4] - NC
|  pd_m1_calb[0] - vdd1p8
|  pd_m1_calb[1] - vdd1p8
|  pd_m1_calb[2] - ovss
|  pd_m1_calb[3] - ovss
|  pd_m1_calb[4] - vdd1p8
|  pd_m1_calb_buf[0] - NC
|  pd_m1_calb_buf[1] - NC
|  pd_m1_calb_buf[2] - NC
|  pd_m1_calb_buf[3] - NC
|  pd_m1_calb_buf[4] - NC
|  pu_cal[0] - vdd1p8
|  pu_cal[1] - vdd1p8
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Model_type I/O
Polarity   Non-Inverting
Enable   Active-High
Vinl =   0.4700V
Vinh =   0.7300V
Vmeas =  0.6000V
Cref =   5.0000pF
Rref =   24.0000
Vref =   0.6000V
C_comp   1.1786pF   1.0549pF   1.3266pF
|C_comp_pullup   0.5407pF   0.5887pF   0.5027pF
|C_comp_pulldown   0.6254pF   0.7255pF   0.5394pF
[Model Spec]
| variable   typ   min   max
Vinh   0.7300V   0.7000V   0.7900V
Vinl   0.4700V   0.4400V   0.5300V
S_overshoot_high   1.2000V   1.1400V   1.3200V
S_overshoot_low   0.0V   0.0V   0.0V
D_overshoot_high   1.5500V   1.4900V   1.6700V
D_overshoot_low   -0.3500V   -0.3500V   -0.3500V
D_overshoot_time   1.7140nS   1.7140nS   1.7140nS
Vmeas   0.6000V   0.5700V   0.6600V
Vref   0.6000V   0.5700V   0.6600V
Cref   5.0000pF   5.0000pF   5.0000pF
Rref   50.0000   50.0000   50.0000
[Receiver Thresholds]
Vth  =   0.6000V
Vinh_ac  =   0.2200V
Vinh_dc  =   0.1300V
Vinl_ac  =   -0.2200V
Vinl_dc  =   -0.1300V
Tslew_ac  =   0.4400nS
Vcross_high  =   0.7200V
Vcross_low  =   0.4800V
Vdiff_ac  =   0.4400V
Vdiff_dc  =   0.2600V
Tdiffslew_ac  =   0.2200nS
[Temperature Range]   25.0000   0.1050k   -20.0000
[Voltage Range]   1.2000V   1.1000V   1.3000V
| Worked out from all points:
|   slope of the pulldown table from 0 to 0.18 V, typ, clamps not added: 41 ohm
|   slope of the pullup table from 0 to 0.18 V, typ, clamps not added: 39.6 ohm
|   GND clamp passes 1 mA (typ) near -0.55 V on its own axis
|   POWER clamp passes 1 mA (typ) near -0.55 V on its own axis
|   rising waveform, R_fixture 48.0000, V_fixture 0.0: 20-80 % time 112ps typ, 193ps min, 70.7ps max; typ from 0 V to 0.613 V
|   rising waveform, R_fixture 48.0000, V_fixture 1.2000: 20-80 % time 89.4ps typ, 129ps min, 65.3ps max; typ from 0.579 V to 1.2 V
|   falling waveform, R_fixture 48.0000, V_fixture 0.0: 20-80 % time 63.1ps typ, 96.7ps min, 44.3ps max; typ from 0.613 V to 0 V
|   falling waveform, R_fixture 48.0000, V_fixture 1.2000: 20-80 % time 123ps typ, 228ps min, 78.8ps max; typ from 1.2 V to 0.579 V
[Pulldown]
|Voltage   I(typ)   I(min)   I(max)
-1.3V     -12.81mA   -9.599mA   -14.97mA
-860mV    -15.03mA   -10.02mA   -20.22mA
-580mV    -13.18mA   -8.677mA   -18.32mA
540mV     12.22mA    7.768mA    17.53mA
820mV     16.5mA     10.24mA    23.46mA
1.14V     18.89mA    11.49mA    26.61mA
1.9V      20.07mA    12.01mA    28.13mA
2.06V     19.94mA    9.972mA    28.21mA
2.18V     17.36mA    6.903mA    27.92mA
2.26V     14.27mA    4.891mA    25.39mA
2.38V     9.597mA    2.686mA    18.18mA
2.6V      3.37mA     1.17mA     7.3mA
[Pullup]
|Voltage   I(typ)   I(min)   I(max)
-1.3V     17.73mA    13.15mA    22.32mA
-920mV    19.51mA    13mA       28.1mA
-680mV    16.9mA     11.12mA    24.75mA
-440mV    11.94mA    7.851mA    17.71mA
520mV     -11.67mA   -6.961mA   -18.4mA
840mV     -15.87mA   -8.859mA   -25.97mA
1.2V      -18mA      -9.625mA   -30.54mA
1.8V      -19.13mA   -9.911mA   -33.08mA
2V        -18.81mA   -6.571mA   -33.43mA
2.12V     -15.51mA   -3.979mA   -33.05mA
2.36V     -6.912mA   -1.268mA   -20.64mA
2.6V      -2.243mA   -706uA     -9.455mA
[GND_clamp]
|Voltage   I(typ)   I(min)   I(max)
-1.3V     -1.327A    -774.7mA   -2.13A
-1.06V    -249.5mA   -186.8mA   -362.1mA
-1.02V    -170.7mA   -138.9mA   -233.4mA
-980mV    -110.7mA   -99.55mA   -142.7mA
-940mV    -65mA      -67.2mA    -78.14mA
-900mV    -33.36mA   -41.59mA   -36.54mA
-860mV    -16.14mA   -23.43mA   -17.16mA
-820mV    -8.924mA   -12.66mA   -10.41mA
-780mV    -5.964mA   -7.199mA   -7.779mA
-660mV    -2.678mA   -2.269mA   -3.845mA
-420mV    -80.74uA   -142.6uA   -96.45uA
2.6V      0A         0A         0A
[POWER_clamp]
|Voltage   I(typ)   I(min)   I(max)
-1.3V     1.653A     1.004A     2.566A
-1.08V    346.4mA    236.5mA    551.1mA
-1.04V    210.8mA    157.7mA    320.5mA
-1V       121.1mA    101.5mA    171mA
-960mV    65.36mA    62.81mA    84.97mA
-920mV    32.57mA    36.77mA    38.73mA
-880mV    15.78mA    20.35mA    17.99mA
-840mV    8.717mA    11.1mA     10.75mA
-800mV    5.976mA    6.48mA     8.129mA
-680mV    2.921mA    2.467mA    4.216mA
-400mV    106.3uA    181.1uA    127.5uA
2.6V      0A         0A         0A
[Ramp]
| variable   typ   min   max
dV/dt_r  0.3679/0.1118n   0.2378/0.1929n   0.4938/70.6935p
dV/dt_f  0.3728/0.1230n   0.2604/0.2284n   0.4775/78.7826p
R_load = 48.0000
[Rising Waveform]
R_fixture= 48.0000
V_fixture= 0.0
V_fixture_min= 0.0
V_fixture_max= 0.0
|time   V(typ)   V(min)   V(max)
0s        8.264nV    426.1nV    163.5nV
532.3ps   -8.414mV   121.1nV    -19.67mV
562.4ps   -17.05mV   36.61uV    77.01mV
646.2ps   75.23mV    44.85uV    657.8mV
744ps     426.6mV    171.2uV    807.5mV
836.1ps   569mV      -4.719mV   820.5mV
986.4ps   608.2mV    1.942mV    822.9mV
1.197ns   613mV      273.1mV    823mV
1.341ns   613.2mV    361.2mV    823mV
2.1ns     613.2mV    396.3mV    823.1mV
[Rising Waveform]
R_fixture= 48.0000
V_fixture= 1.2000
V_fixture_min= 1.1000
V_fixture_max= 1.3000
|time   V(typ)   V(min)   V(max)
0s        579mV      665.3mV    504.6mV
458.5ps   577.3mV    665.4mV    519.2mV
502.6ps   601.6mV    665.4mV    650.2mV
581.9ps   862.6mV    665.3mV    1.197V
634.7ps   1.074V     665.7mV    1.288V
693.3ps   1.174V     663.4mV    1.297V
807.4ps   1.198V     694.9mV    1.3V
967.2ps   1.2V       1.003V     1.3V
1.071ns   1.2V       1.08V      1.3V
2.1ns     1.2V       1.1V       1.3V
[Falling Waveform]
R_fixture= 48.0000
V_fixture= 0.0
V_fixture_min= 0.0
V_fixture_max= 0.0
|time   V(typ)   V(min)   V(max)
0s        612.9mV    396.3mV    822.5mV
521.8ps   615.4mV    396.3mV    831.5mV
548ps     624mV      396.3mV    704.5mV
602.4ps   611.6mV    396.3mV    130mV
666.4ps   248.2mV    396.5mV    9.981mV
738.2ps   33.87mV    395.8mV    1.589mV
949.9ps   695.4uV    411.7mV    314uV
1.077ns   335.6uV    106.6mV    229.6uV
1.175ns   230.8uV    17.43mV    201.2uV
2.1ns     92.23uV    91.52uV    97.12uV
[Falling Waveform]
R_fixture= 48.0000
V_fixture= 1.2000
V_fixture_min= 1.1000
V_fixture_max= 1.3000
|time   V(typ)   V(min)   V(max)
0s        1.2V       1.1V       1.3V
530ps     1.199V     1.1V       1.298V
567.1ps   1.202V     1.1V       1.205V
663.4ps   1.137V     1.1V       642.3mV
745.6ps   856.1mV    1.1V       527mV
826.6ps   671.7mV    1.099V     510.4mV
959.1ps   596.4mV    1.108V     505.1mV
1.056ns   585.3mV    1.078V     504.4mV
1.412ns   578.8mV    717.7mV    504.2mV
2.1ns     578.6mV    666mV      504.1mV
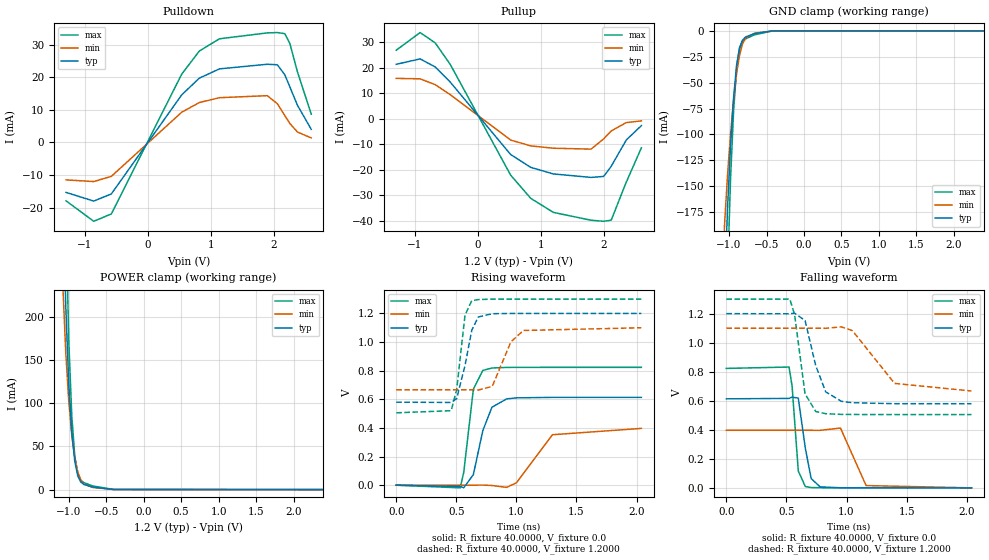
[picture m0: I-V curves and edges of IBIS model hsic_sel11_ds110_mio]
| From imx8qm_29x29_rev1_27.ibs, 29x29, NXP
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[Model] hsic_sel11_ds110_mio
|   Model hsic_sel11_ds110_mio
| This model was characterised for following simulation conditions:
| External (pad) voltage:
|   - Typ: 1.2V,   - Min: 1.1V,   - Max: 1.3V
| Library cells for typ/min/max conditions are connected as defined below:
|  pad - External Pad
|  ipp_do - Core Input
|  ipp_obe - Output Buffer Enable
|  ddr_sel0 - vddi
|  ddr_sel1 - vddi
|  esd_boost - ovdd
|  esd_trigger - ovss
|  ipp_dse0 - ovss
|  ipp_dse1 - vddi
|  ipp_dse2 - vddi
|  ipp_ind - NC
|  ovdd - ovdd
|  ovss - ovss
|  pd_calb[0] - ovss
|  pd_calb[1] - ovss
|  pd_calb[2] - vdd1p8
|  pd_calb[3] - ovss
|  pd_calb[4] - vdd1p8
|  pd_calb_buf[0] - NC
|  pd_calb_buf[1] - NC
|  pd_calb_buf[2] - NC
|  pd_calb_buf[3] - NC
|  pd_calb_buf[4] - NC
|  pd_m1_calb[0] - vdd1p8
|  pd_m1_calb[1] - vdd1p8
|  pd_m1_calb[2] - ovss
|  pd_m1_calb[3] - ovss
|  pd_m1_calb[4] - vdd1p8
|  pd_m1_calb_buf[0] - NC
|  pd_m1_calb_buf[1] - NC
|  pd_m1_calb_buf[2] - NC
|  pd_m1_calb_buf[3] - NC
|  pd_m1_calb_buf[4] - NC
|  pu_cal[0] - vdd1p8
|  pu_cal[1] - vdd1p8
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Model_type I/O
Polarity   Non-Inverting
Enable   Active-High
Vinl =   0.4700V
Vinh =   0.7300V
Vmeas =  0.6000V
Cref =   5.0000pF
Rref =   20.0000
Vref =   0.6000V
C_comp   1.1786pF   1.0549pF   1.3266pF
|C_comp_pullup   0.5407pF   0.5887pF   0.5025pF
|C_comp_pulldown   0.6254pF   0.7255pF   0.5397pF
[Model Spec]
| variable   typ   min   max
Vinh   0.7300V   0.7000V   0.7900V
Vinl   0.4700V   0.4400V   0.5300V
S_overshoot_high   1.2000V   1.1400V   1.3200V
S_overshoot_low   0.0V   0.0V   0.0V
D_overshoot_high   1.5500V   1.4900V   1.6700V
D_overshoot_low   -0.3500V   -0.3500V   -0.3500V
D_overshoot_time   1.7140nS   1.7140nS   1.7140nS
Vmeas   0.6000V   0.5700V   0.6600V
Vref   0.6000V   0.5700V   0.6600V
Cref   5.0000pF   5.0000pF   5.0000pF
Rref   50.0000   50.0000   50.0000
[Receiver Thresholds]
Vth  =   0.6000V
Vinh_ac  =   0.2200V
Vinh_dc  =   0.1300V
Vinl_ac  =   -0.2200V
Vinl_dc  =   -0.1300V
Tslew_ac  =   0.4400nS
Vcross_high  =   0.7200V
Vcross_low  =   0.4800V
Vdiff_ac  =   0.4400V
Vdiff_dc  =   0.2600V
Tdiffslew_ac  =   0.2200nS
[Temperature Range]   25.0000   0.1050k   -20.0000
[Voltage Range]   1.2000V   1.1000V   1.3000V
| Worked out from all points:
|   slope of the pulldown table from 0 to 0.18 V, typ, clamps not added: 34.3 ohm
|   slope of the pullup table from 0 to 0.18 V, typ, clamps not added: 32.9 ohm
|   GND clamp passes 1 mA (typ) near -0.55 V on its own axis
|   POWER clamp passes 1 mA (typ) near -0.55 V on its own axis
|   rising waveform, R_fixture 40.0000, V_fixture 0.0: 20-80 % time 106ps typ, 187ps min, 67ps max; typ from 0 V to 0.614 V
|   rising waveform, R_fixture 40.0000, V_fixture 1.2000: 20-80 % time 83.2ps typ, 120ps min, 61.1ps max; typ from 0.58 V to 1.2 V
|   falling waveform, R_fixture 40.0000, V_fixture 0.0: 20-80 % time 57.9ps typ, 89.4ps min, 40.6ps max; typ from 0.613 V to 0 V
|   falling waveform, R_fixture 40.0000, V_fixture 1.2000: 20-80 % time 118ps typ, 223ps min, 74.1ps max; typ from 1.2 V to 0.58 V
[Pulldown]
|Voltage   I(typ)   I(min)   I(max)
-1.3V     -15.32mA   -11.48mA   -17.91mA
-860mV    -17.98mA   -11.99mA   -24.18mA
-580mV    -15.78mA   -10.39mA   -21.92mA
540mV     14.62mA    9.295mA    20.98mA
820mV     19.74mA    12.25mA    28.06mA
1.14V     22.58mA    13.74mA    31.81mA
1.9V      24mA       14.36mA    33.62mA
2.06V     23.84mA    11.92mA    33.72mA
2.18V     20.75mA    8.237mA    33.38mA
2.26V     17.04mA    5.835mA    30.35mA
2.38V     11.44mA    3.208mA    21.7mA
2.6V      4.03mA     1.4mA      8.7mA
[Pullup]
|Voltage   I(typ)   I(min)   I(max)
-1.3V     21.31mA    15.8mA     26.83mA
-920mV    23.43mA    15.62mA    33.75mA
-680mV    20.29mA    13.35mA    29.72mA
-440mV    14.34mA    9.428mA    21.26mA
520mV     -14.02mA   -8.364mA   -22.1mA
840mV     -19.07mA   -10.65mA   -31.2mA
1.2V      -21.64mA   -11.57mA   -36.71mA
1.8V      -23mA      -11.92mA   -39.78mA
2V        -22.62mA   -7.911mA   -40.2mA
2.12V     -18.66mA   -4.8mA     -39.75mA
2.36V     -8.342mA   -1.53mA    -24.86mA
2.6V      -2.715mA   -850uA     -11.42mA
[GND_clamp]
|Voltage   I(typ)   I(min)   I(max)
-1.3V     -1.327A    -774.7mA   -2.13A
-1.06V    -249.5mA   -186.8mA   -362.1mA
-1.02V    -170.7mA   -138.9mA   -233.4mA
-980mV    -110.7mA   -99.55mA   -142.7mA
-940mV    -65mA      -67.2mA    -78.14mA
-900mV    -33.36mA   -41.59mA   -36.54mA
-860mV    -16.14mA   -23.43mA   -17.16mA
-820mV    -8.924mA   -12.66mA   -10.41mA
-780mV    -5.964mA   -7.199mA   -7.779mA
-660mV    -2.678mA   -2.269mA   -3.845mA
-420mV    -80.74uA   -142.6uA   -96.45uA
2.6V      0A         0A         0A
[POWER_clamp]
|Voltage   I(typ)   I(min)   I(max)
-1.3V     1.653A     1.004A     2.566A
-1.08V    346.4mA    236.5mA    551.1mA
-1.04V    210.8mA    157.7mA    320.5mA
-1V       121.1mA    101.5mA    171mA
-960mV    65.36mA    62.81mA    84.97mA
-920mV    32.57mA    36.77mA    38.73mA
-880mV    15.78mA    20.35mA    17.99mA
-840mV    8.717mA    11.1mA     10.75mA
-800mV    5.976mA    6.48mA     8.129mA
-680mV    2.921mA    2.467mA    4.216mA
-400mV    106.3uA    181.1uA    127.5uA
2.6V      0A         0A         0A
[Ramp]
| variable   typ   min   max
dV/dt_r  0.3682/0.1061n   0.2381/0.1867n   0.4940/66.9007p
dV/dt_f  0.3723/0.1176n   0.2597/0.2234n   0.4770/74.1034p
R_load = 40.0000
[Rising Waveform]
R_fixture= 40.0000
V_fixture= 0.0
V_fixture_min= 0.0
V_fixture_max= 0.0
|time   V(typ)   V(min)   V(max)
0s        6.895nV    355.4nV    136.4nV
532.7ps   -9.174mV   -676.3nV   -18.67mV
561.9ps   -18.09mV   33.17uV    89.31mV
642ps     73.86mV    12.54uV    670.6mV
720.7ps   381.2mV    758.9uV    802mV
796.6ps   544.8mV    -2.097mV   818.7mV
919.1ps   602.9mV    -15.29mV   822.9mV
1ns       610.2mV    16.78mV    823.3mV
1.3ns     613.6mV    352.6mV    823.4mV
2.04ns    613.6mV    396.8mV    823.4mV
[Rising Waveform]
R_fixture= 40.0000
V_fixture= 1.2000
V_fixture_min= 1.1000
V_fixture_max= 1.3000
|time   V(typ)   V(min)   V(max)
0s        580mV      666.3mV    505.6mV
457.4ps   578mV      666.3mV    520.6mV
503ps     605.3mV    666.3mV    666.4mV
572.3ps   835.3mV    666.2mV    1.187V
628.5ps   1.082V     666.6mV    1.289V
682.7ps   1.175V     664.8mV    1.297V
799.2ps   1.198V     690.3mV    1.3V
954.1ps   1.2V       1.001V     1.3V
1.058ns   1.2V       1.081V     1.3V
2.04ns    1.2V       1.1V       1.3V
[Falling Waveform]
R_fixture= 40.0000
V_fixture= 0.0
V_fixture_min= 0.0
V_fixture_max= 0.0
|time   V(typ)   V(min)   V(max)
0s        613.3mV    396.8mV    822.8mV
521.8ps   616.2mV    396.8mV    832.3mV
547.1ps   625.2mV    396.8mV    701.1mV
598.8ps   617.8mV    396.9mV    116.2mV
657.6ps   271.8mV    397mV      8.936mV
705.9ps   64.32mV    396.6mV    2.329mV
780.3ps   6.893mV    396.3mV    841.1uV
949.8ps   646.6uV    411.9mV    268.2uV
1.163ns   204.2uV    15.76mV    169.5uV
2.04ns    79.3uV     84.91uV    84.27uV
[Falling Waveform]
R_fixture= 40.0000
V_fixture= 1.2000
V_fixture_min= 1.1000
V_fixture_max= 1.3000
|time   V(typ)   V(min)   V(max)
0s        1.2V       1.1V       1.3V
528.4ps   1.199V     1.1V       1.3V
567.8ps   1.203V     1.1V       1.194V
654.9ps   1.153V     1.1V       648.4mV
743.6ps   842.5mV    1.1V       525.8mV
826.7ps   661.4mV    1.099V     510.9mV
957.1ps   596.3mV    1.109V     506mV
1.049ns   586.4mV    1.083V     505.4mV
1.4ns     579.8mV    719.5mV    505.1mV
2.04ns    579.6mV    667.2mV    505.1mV
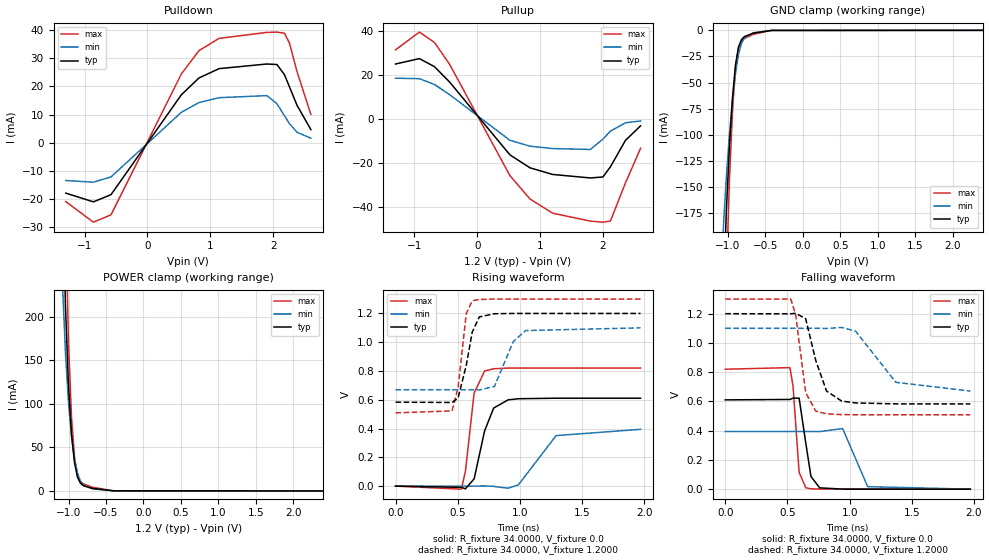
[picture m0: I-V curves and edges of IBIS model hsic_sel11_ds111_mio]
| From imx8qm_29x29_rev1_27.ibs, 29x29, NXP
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[Model] hsic_sel11_ds111_mio
|   Model hsic_sel11_ds111_mio
| This model was characterised for following simulation conditions:
| External (pad) voltage:
|   - Typ: 1.2V,   - Min: 1.1V,   - Max: 1.3V
| Library cells for typ/min/max conditions are connected as defined below:
|  pad - External Pad
|  ipp_do - Core Input
|  ipp_obe - Output Buffer Enable
|  ddr_sel0 - vddi
|  ddr_sel1 - vddi
|  esd_boost - ovdd
|  esd_trigger - ovss
|  ipp_dse0 - vddi
|  ipp_dse1 - vddi
|  ipp_dse2 - vddi
|  ipp_ind - NC
|  ovdd - ovdd
|  ovss - ovss
|  pd_calb[0] - ovss
|  pd_calb[1] - ovss
|  pd_calb[2] - vdd1p8
|  pd_calb[3] - ovss
|  pd_calb[4] - vdd1p8
|  pd_calb_buf[0] - NC
|  pd_calb_buf[1] - NC
|  pd_calb_buf[2] - NC
|  pd_calb_buf[3] - NC
|  pd_calb_buf[4] - NC
|  pd_m1_calb[0] - vdd1p8
|  pd_m1_calb[1] - vdd1p8
|  pd_m1_calb[2] - ovss
|  pd_m1_calb[3] - ovss
|  pd_m1_calb[4] - vdd1p8
|  pd_m1_calb_buf[0] - NC
|  pd_m1_calb_buf[1] - NC
|  pd_m1_calb_buf[2] - NC
|  pd_m1_calb_buf[3] - NC
|  pd_m1_calb_buf[4] - NC
|  pu_cal[0] - vdd1p8
|  pu_cal[1] - vdd1p8
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Model_type I/O
Polarity   Non-Inverting
Enable   Active-High
Vinl =   0.4700V
Vinh =   0.7300V
Vmeas =  0.6000V
Cref =   5.0000pF
Rref =   17.0000
Vref =   0.6000V
C_comp   1.1786pF   1.0549pF   1.3266pF
|C_comp_pullup   0.5407pF   0.5887pF   0.5025pF
|C_comp_pulldown   0.6254pF   0.7255pF   0.5397pF
[Model Spec]
| variable   typ   min   max
Vinh   0.7300V   0.7000V   0.7900V
Vinl   0.4700V   0.4400V   0.5300V
S_overshoot_high   1.2000V   1.1400V   1.3200V
S_overshoot_low   0.0V   0.0V   0.0V
D_overshoot_high   1.5500V   1.4900V   1.6700V
D_overshoot_low   -0.3500V   -0.3500V   -0.3500V
D_overshoot_time   1.7140nS   1.7140nS   1.7140nS
Vmeas   0.6000V   0.5700V   0.6600V
Vref   0.6000V   0.5700V   0.6600V
Cref   5.0000pF   5.0000pF   5.0000pF
Rref   50.0000   50.0000   50.0000
[Receiver Thresholds]
Vth  =   0.6000V
Vinh_ac  =   0.2200V
Vinh_dc  =   0.1300V
Vinl_ac  =   -0.2200V
Vinl_dc  =   -0.1300V
Tslew_ac  =   0.4400nS
Vcross_high  =   0.7200V
Vcross_low  =   0.4800V
Vdiff_ac  =   0.4400V
Vdiff_dc  =   0.2600V
Tdiffslew_ac  =   0.2200nS
[Temperature Range]   25.0000   0.1050k   -20.0000
[Voltage Range]   1.2000V   1.1000V   1.3000V
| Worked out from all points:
|   slope of the pulldown table from 0 to 0.18 V, typ, clamps not added: 29.4 ohm
|   slope of the pullup table from 0 to 0.18 V, typ, clamps not added: 28.2 ohm
|   GND clamp passes 1 mA (typ) near -0.55 V on its own axis
|   POWER clamp passes 1 mA (typ) near -0.55 V on its own axis
|   rising waveform, R_fixture 34.0000, V_fixture 0.0: 20-80 % time 103ps typ, 183ps min, 64.4ps max; typ from 0 V to 0.611 V
|   rising waveform, R_fixture 34.0000, V_fixture 1.2000: 20-80 % time 78.9ps typ, 115ps min, 58.2ps max; typ from 0.583 V to 1.2 V
|   falling waveform, R_fixture 34.0000, V_fixture 0.0: 20-80 % time 54ps typ, 84.2ps min, 37.9ps max; typ from 0.611 V to 0 V
|   falling waveform, R_fixture 34.0000, V_fixture 1.2000: 20-80 % time 114ps typ, 220ps min, 70.7ps max; typ from 1.2 V to 0.583 V
[Pulldown]
|Voltage   I(typ)   I(min)   I(max)
-1.3V     -17.84mA   -13.37mA   -20.84mA
-860mV    -20.93mA   -13.96mA   -28.14mA
-580mV    -18.38mA   -12.09mA   -25.52mA
540mV     17.03mA    10.82mA    24.42mA
820mV     22.98mA    14.26mA    32.66mA
1.14V     26.28mA    15.98mA    37.01mA
1.9V      27.92mA    16.71mA    39.12mA
2.06V     27.74mA    13.86mA    39.23mA
2.18V     24.14mA    9.569mA    38.83mA
2.26V     19.81mA    6.777mA    35.32mA
2.38V     13.28mA    3.729mA    25.23mA
2.6V      4.68mA     1.63mA     10.1mA
[Pullup]
|Voltage   I(typ)   I(min)   I(max)
-1.3V     24.88mA    18.44mA    31.33mA
-920mV    27.35mA    18.23mA    39.39mA
-680mV    23.68mA    15.59mA    34.69mA
-440mV    16.73mA    11mA       24.81mA
520mV     -16.37mA   -9.767mA   -25.79mA
840mV     -22.27mA   -12.44mA   -36.43mA
1.2V      -25.28mA   -13.52mA   -42.87mA
1.8V      -26.87mA   -13.93mA   -46.47mA
2V        -26.44mA   -9.253mA   -46.97mA
2.12V     -21.82mA   -5.622mA   -46.45mA
2.36V     -9.774mA   -1.791mA   -29.09mA
2.6V      -3.188mA   -994uA     -13.4mA
[GND_clamp]
|Voltage   I(typ)   I(min)   I(max)
-1.3V     -1.327A    -774.7mA   -2.13A
-1.06V    -249.5mA   -186.8mA   -362.1mA
-1.02V    -170.7mA   -138.9mA   -233.4mA
-980mV    -110.7mA   -99.55mA   -142.7mA
-940mV    -65mA      -67.2mA    -78.14mA
-900mV    -33.36mA   -41.59mA   -36.54mA
-860mV    -16.14mA   -23.43mA   -17.16mA
-820mV    -8.924mA   -12.66mA   -10.41mA
-780mV    -5.964mA   -7.199mA   -7.779mA
-660mV    -2.678mA   -2.269mA   -3.845mA
-420mV    -80.74uA   -142.6uA   -96.45uA
2.6V      0A         0A         0A
[POWER_clamp]
|Voltage   I(typ)   I(min)   I(max)
-1.3V     1.653A     1.004A     2.566A
-1.08V    346.4mA    236.5mA    551.1mA
-1.04V    210.8mA    157.7mA    320.5mA
-1V       121.1mA    101.5mA    171mA
-960mV    65.36mA    62.81mA    84.97mA
-920mV    32.57mA    36.77mA    38.73mA
-880mV    15.78mA    20.35mA    17.99mA
-840mV    8.717mA    11.1mA     10.75mA
-800mV    5.976mA    6.48mA     8.129mA
-680mV    2.921mA    2.467mA    4.216mA
-400mV    106.3uA    181.1uA    127.5uA
2.6V      0A         0A         0A
[Ramp]
| variable   typ   min   max
dV/dt_r  0.3666/0.1025n   0.2367/0.1825n   0.4924/64.3327p
dV/dt_f  0.3702/0.1144n   0.2575/0.2200n   0.4748/70.7298p
R_load = 34.0000
[Rising Waveform]
R_fixture= 34.0000
V_fixture= 0.0
V_fixture_min= 0.0
V_fixture_max= 0.0
|time   V(typ)   V(min)   V(max)
0s        5.898nV    303.4nV    116.7nV
529.5ps   -8.861mV   -1.489uV   -21.27mV
562ps     -19.07mV   39.25uV    103.7mV
632ps     50.5mV     -53.89uV   646.6mV
716.3ps   384mV      832.7uV    799.8mV
788.8ps   542.2mV    -1.9mV     815.8mV
904.7ps   599.3mV    -14.53mV   820.2mV
987.3ps   607.3mV    8.308mV    820.6mV
1.291ns   610.9mV    351mV      820.7mV
1.97ns    610.9mV    394.6mV    820.7mV
[Rising Waveform]
R_fixture= 34.0000
V_fixture= 1.2000
V_fixture_min= 1.1000
V_fixture_max= 1.3000
|time   V(typ)   V(min)   V(max)
0s        583.4mV    669.5mV    509.1mV
454.3ps   581.2mV    669.5mV    522.4mV
502.7ps   611.8mV    669.5mV    683.4mV
568.9ps   840.2mV    669.5mV    1.2V
617.1ps   1.071V     669.7mV    1.288V
673.8ps   1.176V     668.3mV    1.297V
795.2ps   1.198V     692.9mV    1.3V
946.9ps   1.2V       1.005V     1.3V
1.045ns   1.2V       1.081V     1.3V
1.97ns    1.2V       1.1V       1.3V
[Falling Waveform]
R_fixture= 34.0000
V_fixture= 0.0
V_fixture_min= 0.0
V_fixture_max= 0.0
|time   V(typ)   V(min)   V(max)
0s        610.6mV    394.5mV    820.2mV
520ps     613.5mV    394.5mV    831.2mV
544.8ps   622.7mV    394.5mV    705.7mV
593.9ps   622.5mV    394.6mV    115mV
647.8ps   312.9mV    394.7mV    9.309mV
689ps     87.28mV    394.5mV    2.727mV
758.9ps   9.066mV    393.8mV    955.7uV
943.8ps   617.8uV    414.5mV    239.3uV
1.145ns   193.1uV    17.22mV    146.9uV
1.97ns    69.99uV    83.15uV    75.27uV
[Falling Waveform]
R_fixture= 34.0000
V_fixture= 1.2000
V_fixture_min= 1.1000
V_fixture_max= 1.3000
|time   V(typ)   V(min)   V(max)
0s        1.2V       1.1V       1.3V
527.1ps   1.199V     1.1V       1.3V
566.1ps   1.203V     1.1V       1.192V
646.4ps   1.166V     1.1V       661.1mV
728.1ps   878.6mV    1.1V       533.3mV
814.4ps   670.8mV    1.099V     515.2mV
935.6ps   602.8mV    1.106V     509.9mV
1.048ns   589.6mV    1.08V      508.9mV
1.372ns   583.3mV    730.6mV    508.6mV
1.97ns    583mV      670.9mV    508.6mV
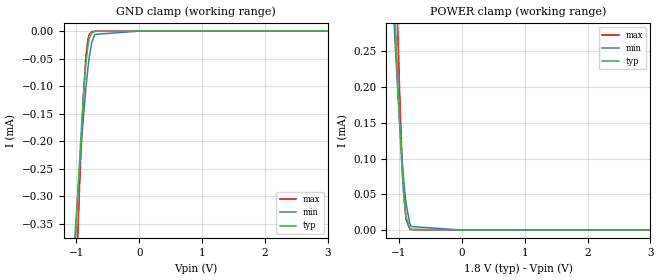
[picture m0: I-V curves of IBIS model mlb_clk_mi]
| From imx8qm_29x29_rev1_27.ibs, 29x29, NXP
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[Model] mlb_clk_mi
|   Model mlb_clk_mi
| This model was characterised for following simulation conditions:
| External (pad) voltage:
|   - Typ: 1.8V,   - Min: 1.62V,   - Max: 1.98V
| Library cells for typ/min/max conditions are connected as defined below:
|  bgref_en - vddi
|  ipp_ind - NC
|  ovdd - ovdd
|  ovss - ovss
|  padn - padn
|  padp - padp
|  rx_bias_ctl[0] - ovss vddi ovss
|  rx_bias_ctl[1] - vddi vddi ovss
|  rx_bias_ctl[2] - vddi ovss vddi
|  rx_bias_ctl[3] - ovss vddi ovss
|  vddi - vddi
| All other pins connected to ground
Model_type Input
Vinl =   0.9000V
Vinh =   1.1000V
C_comp   0.2418pF   0.2410pF   0.3182pF
|C_comp_pullup   -0.1252pF   -26.7349fF   -0.1410pF
|C_comp_pulldown   50.5295fF   39.6455fF   61.5491fF
[Model Spec]
| variable   typ   min   max
Vinh   1.1700V   1.0725V   1.2675V
Vinl   0.6300V   0.5775V   0.6825V
[Receiver Thresholds]
Vcross_high  =   0.0V
Vcross_low  =   0.0V
Vdiff_ac  =   0.0V
Vdiff_dc  =   0.0V
Tdiffslew_ac  =   0.0S
[Temperature Range]   25.0000   0.1050k   -20.0000
[Voltage Range]   1.8000V   1.6200V   1.9800V
[GND_clamp]
|Voltage   I(typ)   I(min)   I(max)
-1.98V    -2.695mA   -2.087mA   -3.728mA
-1.02V    -391.9uA   -367uA     -507.6uA
-948mV    -232.3uA   -247.5uA   -278.1uA
-912mV    -160.1uA   -191.5uA   -176.3uA
-888mV    -116.7uA   -156.3uA   -117.3uA
-852mV    -62.36uA   -107.9uA   -49.73uA
-816mV    -25.84uA   -66.66uA   -14.44uA
-792mV    -12.31uA   -44.58uA   -5.349uA
-756mV    -3.441uA   -21.08uA   -1.08uA
-708mV    -553.7nA   -6.064uA   -121.3nA
0V        -86.64fA   -25.87fA   -888.1fA
3.96V     0A         0A         0A
[POWER_clamp]
|Voltage   I(typ)   I(min)   I(max)
-1.98V    2.505mA    1.905mA    3.507mA
-1.104V   394.9uA    331.9uA    552.5uA
-1.032V   235.4uA    215.2uA    319.9uA
-996mV    163.1uA    161.4uA    214.1uA
-972mV    119.6uA    128.1uA    150.7uA
-948mV    81.25uA    97.55uA    95.78uA
-924mV    49.94uA    70.46uA    52.88uA
-888mV    19.11uA    38.12uA    15.73uA
-828mV    2.351uA    9.357uA    1.193uA
-804mV    942.5nA    4.801uA    400.9nA
0V        157.2fA    132.8fA    1.38pA
3.96V     0A         0A         0A
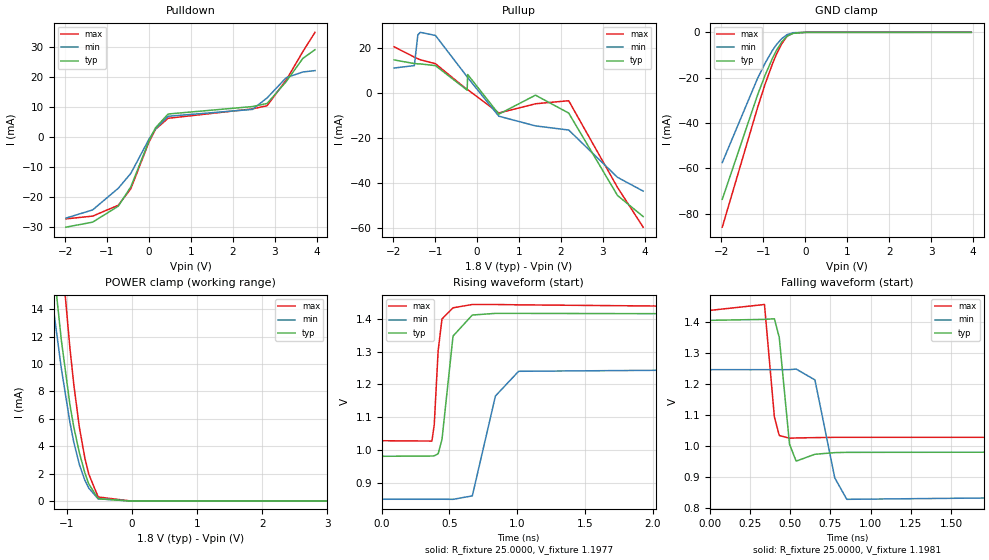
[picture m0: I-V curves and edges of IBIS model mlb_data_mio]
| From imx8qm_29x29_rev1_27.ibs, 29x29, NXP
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[Model] mlb_data_mio
|   Model mlb_data_mio
| This model was characterised for following simulation conditions:
| External (pad) voltage:
|   - Typ: 1.8V,   - Min: 1.62V,   - Max: 1.98V
| Library cells for typ/min/max conditions are connected as defined below:
|  bgref_en - vddi
|  dout - dout
|  ipp_ind - NC
|  oben - oben
|  ovdd - ovdd
|  ovss - ovss
|  padn - padn
|  padp - padp
|  ref_rx_bias_ctl[0] - ovss vddi ovss
|  ref_rx_bias_ctl[1] - vddi vddi ovss
|  ref_rx_bias_ctl[2] - vddi ovss vddi
|  ref_rx_bias_ctl[3] - ovss vddi ovss
|  rx_bias_ctl[0] - ovss vddi ovss
|  rx_bias_ctl[1] - ovss vddi ovss
|  rx_bias_ctl[2] - ovss ovss vddi
|  rx_bias_ctl[3] - vddi vddi ovss
|  tx_bias_ctl[0] - vddi vddi ovss
|  tx_bias_ctl[1] - ovss vddi ovss
|  tx_bias_ctl[2] - ovss vddi ovss
|  tx_bias_ctl[3] - vddi vddi ovss
|  vddi - vddi
| All other pins connected to ground
Model_type I/O
Polarity   Non-Inverting
Enable   Active-High
Vinl =   0.9000V
Vinh =   1.1000V
Vmeas =  1.0000V
Cref =   5.0000pF
Rref =   25.0000
Vref =   1.0000V
C_comp   0.4819pF   0.1560pF   0.4960pF
|C_comp_pullup   -0.4372pF   30.3610fF   30.1271fF
|C_comp_pulldown   -0.3567pF   -0.2628pF   -0.2559pF
[Model Spec]
| variable   typ   min   max
Vinh   1.1700V   1.0725V   1.2675V
Vinl   0.6300V   0.5775V   0.6825V
Vref   0.8985V   0.8135V   0.9860V
Cref   5.0000pF   5.0000pF   5.0000pF
Rref   50.0000   50.0000   50.0000
[Receiver Thresholds]
Vcross_high  =   0.0V
Vcross_low  =   0.0V
Vdiff_ac  =   0.0V
Vdiff_dc  =   0.0V
Tdiffslew_ac  =   0.0S
[Temperature Range]   25.0000   0.1050k   -20.0000
[Voltage Range]   1.8000V   1.6200V   1.9800V
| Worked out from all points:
|   slope of the pulldown table from 0 to 0.27 V, typ, clamps not added: 39.8 ohm
|   slope of the pullup table from 0 to 0.27 V, typ, clamps not added: 37.8 ohm
|   GND clamp passes 1 mA (typ) near -0.38 V on its own axis
|   POWER clamp passes 1 mA (typ) near -0.64 V on its own axis
|   rising waveform, R_fixture 25.0000, V_fixture 1.1977: 20-80 % time 61.3ps typ, 114ps min, 33.5ps max; typ from 0.982 V to 1.41 V
|   falling waveform, R_fixture 25.0000, V_fixture 1.1981: 20-80 % time 42.4ps typ, 83.3ps min, 31.6ps max; typ from 1.41 V to 0.982 V
[Pulldown]
|Voltage   I(typ)   I(min)   I(max)
-1.98V    -30.11mA   -27.09mA   -27.35mA
-1.344V   -28.44mA   -24.36mA   -26.43mA
-732mV    -23.11mA   -17.14mA   -22.81mA
-432mV    -16.63mA   -12.16mA   -17.26mA
0V        -1.362mA   -798.6uA   -1.731mA
156mV     3.014mA    2.636mA    2.523mA
456mV     7.602mA    6.847mA    6.175mA
2.47V     10.09mA    9.147mA    9.32mA
2.818V    11.12mA    12.98mA    10.37mA
3.274V    18.41mA    19.72mA    18.97mA
3.67V     26.14mA    21.61mA    28.38mA
3.96V     29.04mA    22.07mA    34.83mA
[Pullup]
|Voltage   I(typ)   I(min)   I(max)
-1.98V    14.75mA    11.15mA    20.58mA
-1.498V   13.14mA    12.23mA    16mA
-1.414V   13.02mA    25.94mA    15.29mA
-1.354V   12.98mA    27.03mA    14.82mA
-994mV    12.21mA    25.63mA    13.05mA
-238mV    1.308mA    7.243mA    1.545mA
-226mV    8.262mA    6.881mA    1.515mA
518mV     -9.365mA   -10.28mA   -8.846mA
1.392V    -921.2uA   -14.59mA   -4.745mA
2.184V    -8.878mA   -16.43mA   -3.394mA
3.348V    -45.54mA   -37.46mA   -41.95mA
3.96V     -54.9mA    -43.59mA   -59.63mA
[GND_clamp]
|Voltage   I(typ)   I(min)   I(max)
-1.98V    -73.74mA   -57.49mA   -86.02mA
-1.14V    -27.74mA   -20.4mA    -33.34mA
-960mV    -18.98mA   -13.66mA   -22.94mA
-780mV    -11.33mA   -7.875mA   -13.77mA
-684mV    -7.869mA   -5.346mA   -9.543mA
-564mV    -4.304mA   -2.829mA   -5.09mA
-432mV    -1.656mA   -1.007mA   -1.676mA
-288mV    -440uA     -175.1uA   -309.6uA
0V        -29.66uA   -1.751uA   -1.036uA
3.96V     0A         0A         0A
[POWER_clamp]
|Voltage   I(typ)   I(min)   I(max)
-1.98V    62.31mA    50.15mA    78.81mA
-1.284V   21.4mA     17.31mA    31.27mA
-1.2V     17.15mA    13.98mA    25.49mA
-1.08V    11.73mA    9.669mA    18.16mA
-948mV    7.011mA    5.717mA    11.13mA
-888mV    5.376mA    4.271mA    8.457mA
-804mV    3.531mA    2.668mA    5.394mA
-720mV    2.066mA    1.532mA    3.151mA
-660mV    1.254mA    948.5uA    1.972mA
-516mV    177.6uA    170.9uA    304.7uA
0V        472.7pA    2.583nA    1.885nA
3.96V     0A         0A         0A
[Ramp]
| variable   typ   min   max
dV/dt_r  89.8850m/31.4424p   0.2102/0.1470n   0.1248/25.1392p
dV/dt_f  0.1350/41.1869p   0.1299/77.3804p   0.1117/19.7515p
R_load = 25.0000
[Rising Waveform]
R_fixture= 25.0000
V_fixture= 1.1977
V_fixture_min= 1.0505
V_fixture_max= 1.2096
|time   V(typ)   V(min)   V(max)
0s        981.7mV    851.1mV    1.029V
370.4ps   982.5mV    851.1mV    1.028V
387.7ps   983.1mV    851.1mV    1.078V
416.5ps   989.4mV    851.1mV    1.303V
444.8ps   1.033V     851.2mV    1.399V
526.2ps   1.347V     850.9mV    1.433V
668.4ps   1.411V     861.4mV    1.443V
838.9ps   1.416V     1.165V     1.443V
1.01ns    1.416V     1.24V      1.442V
4.37ns    1.413V     1.25V      1.43V
[Falling Waveform]
R_fixture= 25.0000
V_fixture= 1.1981
V_fixture_min= 1.0465
V_fixture_max= 1.2099
|time   V(typ)   V(min)   V(max)
0s        1.406V     1.247V     1.438V
339.9ps   1.409V     1.247V     1.457V
401.5ps   1.411V     1.247V     1.095V
431.8ps   1.351V     1.247V     1.035V
495.5ps   1.007V     1.247V     1.026V
537ps     952.3mV    1.249V     1.027V
653.8ps   974.4mV    1.214V     1.028V
777.3ps   979.7mV    898.1mV    1.029V
851.9ps   980.6mV    829.2mV    1.029V
4.37ns    982.1mV    846.9mV    1.029V
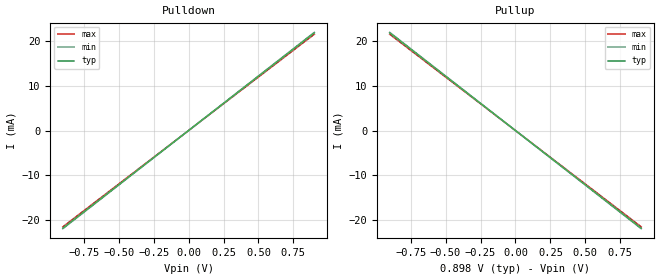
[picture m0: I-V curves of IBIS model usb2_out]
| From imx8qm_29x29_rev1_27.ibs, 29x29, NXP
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[Model] usb2_out
Model_type  Output
Polarity Non-Inverting
Vmeas =0
| variable   typ min max
C_comp   9.4pF 9.2pF 9.85pF
[Temperature Range]   27 -40 125
[Voltage range]   0.8981V 0.8448 0.9909
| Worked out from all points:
|   slope of the pulldown table from 0 to 0.135 V, typ, clamps not added: 41.2 ohm
|   slope of the pullup table from 0 to 0.135 V, typ, clamps not added: 41.2 ohm
[Pullup]
|  Voltage   I(typ) I(min) I(max)
-900mV    21.82mA    21.92mA    21.51mA
0V        0A         0A         0A
900mV     -21.82mA   -21.92mA   -21.51mA
[Pulldown]
|  Voltage   I(typ) I(min) I(max)
-900mV    -21.82mA   -21.92mA   -21.51mA
0V        0A         0A         0A
900mV     21.82mA    21.92mA    21.51mA
[Ramp]
| variable   typ min max
dV/dt_r   0.2953/2.89e-10 0.2783/2.85e-10 0.3237/3.09e-10
dV/dt_f   0.2953/2.89e-10 0.2783/2.85e-10 0.3237/3.09e-10
R_load = 50
[Algorithmic Model]
Executable Windows_VisualStudio7.1.3088_32 usb2_tx_win32_rev1.dll usb2_tx_rev1.ami
Executable Windows_VisualStudio10.0.30319_64 usb2_tx_win64_rev1.dll usb2_tx_rev1.ami
Executable Linux_gcc4.1.2_64 usb2_tx_rev1.so usb2_tx_rev1.ami
[End Algorithmic Model]
| End [Model] usb2_out
